Omron CX-Programmer project NewProject (CX-Programmer 9.75)

# PLC NewPLC1: CS1H-H CPU66
I/O table (CPU CS1W-SCB41-V1, CS1H-CPU66H): rack 0 slot 9 CS1W-CLK23; rack 2 slot 6 CS1W-SCU31-V1

## Program 新規ﾌﾟﾛｸﾞﾗﾑ1 (cyclic task 0)

### Section INITIAL

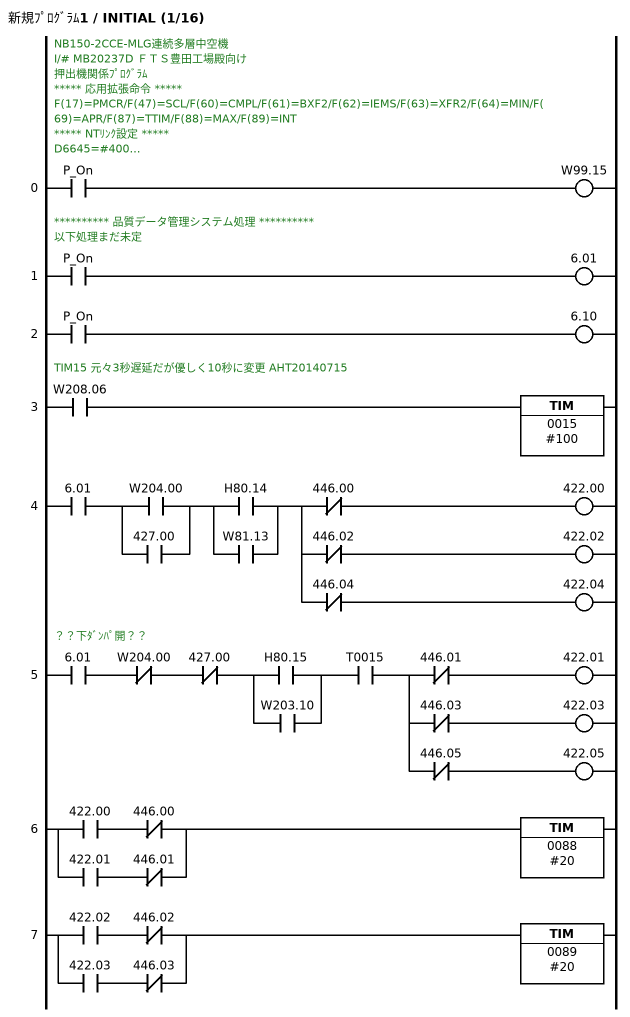
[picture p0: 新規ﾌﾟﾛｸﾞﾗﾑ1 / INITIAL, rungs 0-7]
; rung 0: NB150-2CCE-MLG連続多層中空機 / I/# MB20237D ＦＴＳ豊田工場殿向け / 押出機関係ﾌﾟﾛｸﾞﾗﾑ / ***** 応用拡張命令 ***** / F(17)=PMCR/F(47)=SCL/F(60)=CMPL/F(61)=BXF2/F(62)=IEMS/F(63)=XFR2/F(64)=MIN/F(69)=APR/F(87)=TTIM/F(88)=MAX/F(89)=INT / ***** NTﾘﾝｸ設定 ***** / D6645=#4000 / ***** 電源断検知後運転継続時間 ***** / D6605=#0010 / ***** ｺﾐｭﾆｹｰｼｮﾝﾎﾞｰﾄﾞ設定 ***** / D6555=#6001 D6556=#0304 / ***** ｺﾝﾄﾛｰﾗﾘｸ初期設定 ***** / D6420=#0010 D6421=#0400 D6422=#8000 D6423=#0014 D6424=#0000 D6425=#8200 D6426=#0020 D6427=#0000 D6428=#003F D6429=#0000 / 使用領域　400～483ch/D0000～D0119 / ***** ﾊｰﾄﾞ構成 ***** / ｼｰｹﾝｻ→C200HX-CPU65-Z / ﾃﾞｨｽﾌﾟﾚｲ→NT631C-ST141B-V2
LD P_On
OUT W99.15
; rung 1: ********** 品質データ管理システム処理 ********** / 以下処理まだ未定
LD P_On
OUT 6.01
; rung 2
LD P_On
OUT 6.10
; rung 3: TIM15 元々3秒遅延だが優しく10秒に変更 AHT20140715
LD W208.06
TIM 0015 #100
; rung 4
LD 6.01
LD W204.00
OR 427.00
ANDLD
LD H80.14
OR W81.13
ANDLD
OUT TR0
ANDNOT 446.00
OUT 422.00
LD TR0
ANDNOT 446.02
OUT 422.02
LD TR0
ANDNOT 446.04
OUT 422.04
; rung 5: ？？下ﾀﾞﾝﾊﾟ開？？
LD 6.01
ANDNOT W204.00
ANDNOT 427.00
LD H80.15
OR W203.10
ANDLD
AND T0015
OUT TR0
ANDNOT 446.01
OUT 422.01
LD TR0
ANDNOT 446.03
OUT 422.03
LD TR0
ANDNOT 446.05
OUT 422.05
; rung 6
LD 422.00
ANDNOT 446.00
LD 422.01
ANDNOT 446.01
ORLD
TIM 0088 #20
; rung 7
LD 422.02
ANDNOT 446.02
LD 422.03
ANDNOT 446.03
ORLD
TIM 0089 #20

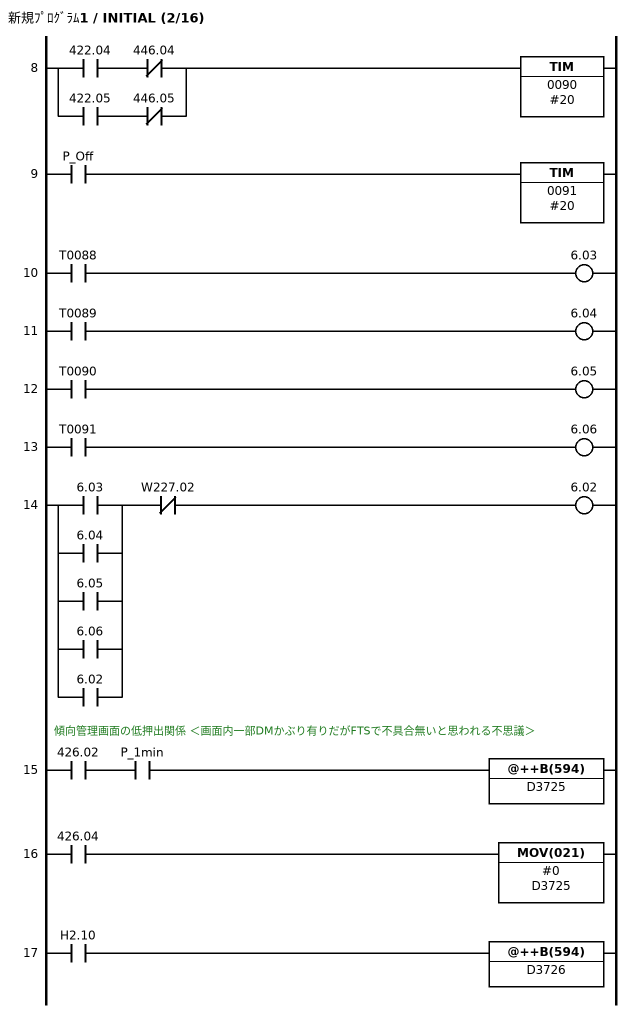
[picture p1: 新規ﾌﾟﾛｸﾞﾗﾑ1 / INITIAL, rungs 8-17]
; rung 8
LD 422.04
ANDNOT 446.04
LD 422.05
ANDNOT 446.05
ORLD
TIM 0090 #20
; rung 9
LD P_Off
TIM 0091 #20
; rung 10
LD T0088
OUT 6.03
; rung 11
LD T0089
OUT 6.04
; rung 12
LD T0090
OUT 6.05
; rung 13
LD T0091
OUT 6.06
; rung 14
LD 6.03
OR 6.04
OR 6.05
OR 6.06
OR 6.02
ANDNOT W227.02
OUT 6.02
; rung 15: 傾向管理画面の低押出関係 ＜画面内一部DMかぶり有りだがFTSで不具合無いと思われる不思議＞
LD 426.02
AND P_1min
@++B(594) D3725
; rung 16
LD 426.04
MOV(021) #0 D3725
; rung 17
LD H2.10
@++B(594) D3726

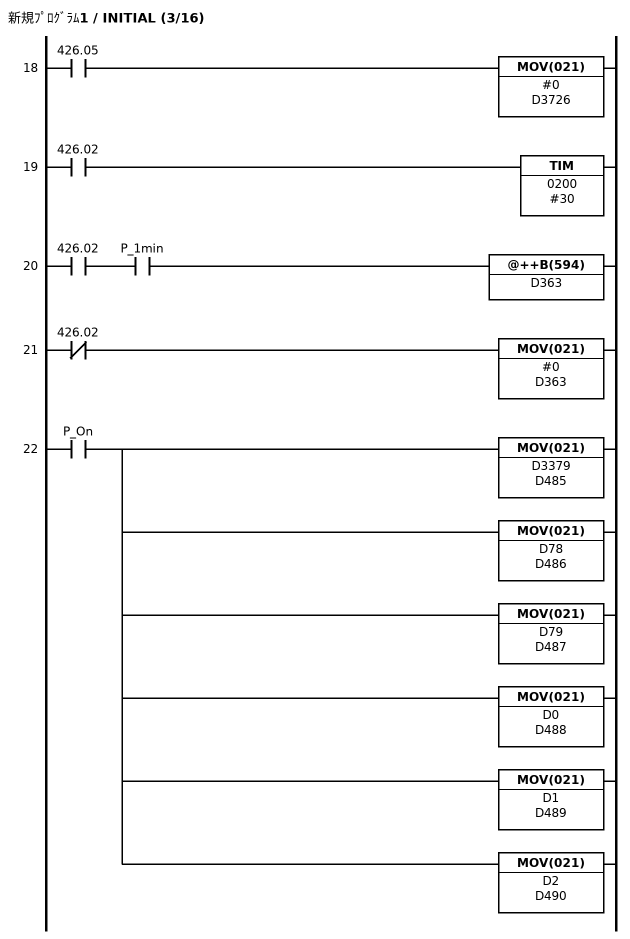
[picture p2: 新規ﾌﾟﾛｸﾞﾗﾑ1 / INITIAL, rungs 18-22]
; rung 18
LD 426.05
MOV(021) #0 D3726
; rung 19
LD 426.02
TIM 0200 #30
; rung 20
LD 426.02
AND P_1min
@++B(594) D363
; rung 21
LDNOT 426.02
MOV(021) #0 D363
; rung 22
LD P_On
MOV(021) D3379 D485
MOV(021) D78 D486
MOV(021) D79 D487
MOV(021) D0 D488
MOV(021) D1 D489
MOV(021) D2 D490

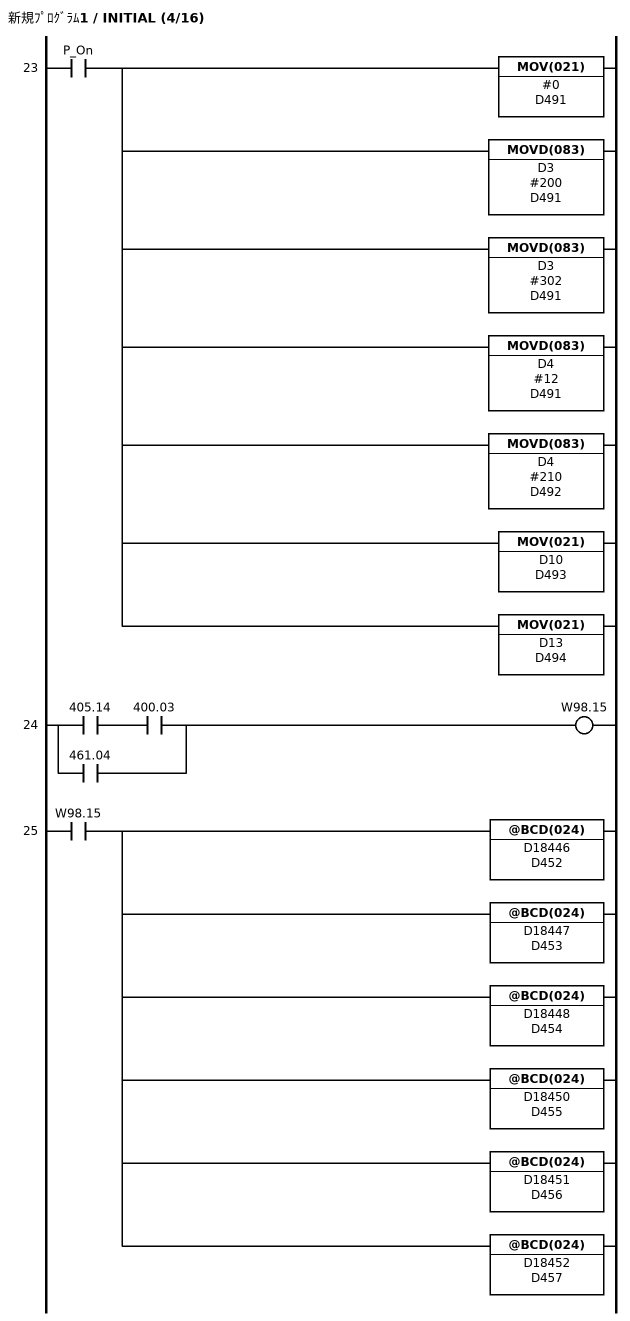
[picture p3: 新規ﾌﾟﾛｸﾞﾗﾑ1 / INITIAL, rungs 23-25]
; rung 23
LD P_On
MOV(021) #0 D491
MOVD(083) D3 #200 D491
MOVD(083) D3 #302 D491
MOVD(083) D4 #12 D491
MOVD(083) D4 #210 D492
MOV(021) D10 D493
MOV(021) D13 D494
; rung 24
LD 405.14
AND 400.03
OR 461.04
OUT W98.15
; rung 25
LD W98.15
@BCD(024) D18446 D452
@BCD(024) D18447 D453
@BCD(024) D18448 D454
@BCD(024) D18450 D455
@BCD(024) D18451 D456
@BCD(024) D18452 D457

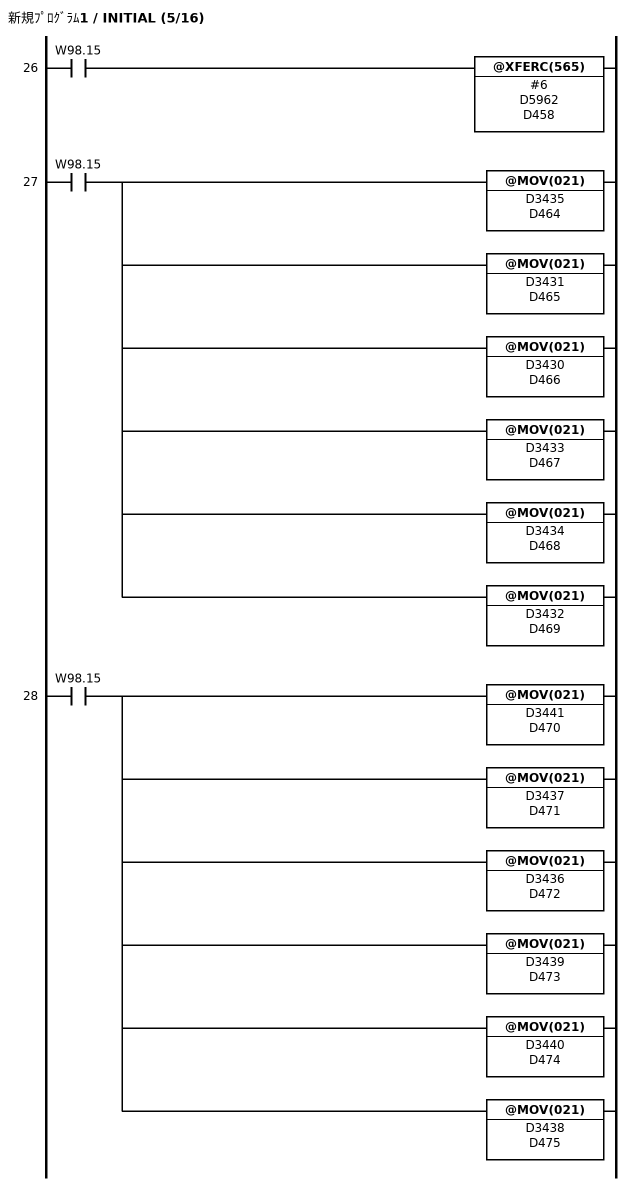
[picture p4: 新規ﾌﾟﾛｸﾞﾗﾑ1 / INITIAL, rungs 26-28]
; rung 26
LD W98.15
@XFERC(565) #6 D5962 D458
; rung 27
LD W98.15
@MOV(021) D3435 D464
@MOV(021) D3431 D465
@MOV(021) D3430 D466
@MOV(021) D3433 D467
@MOV(021) D3434 D468
@MOV(021) D3432 D469
; rung 28
LD W98.15
@MOV(021) D3441 D470
@MOV(021) D3437 D471
@MOV(021) D3436 D472
@MOV(021) D3439 D473
@MOV(021) D3440 D474
@MOV(021) D3438 D475

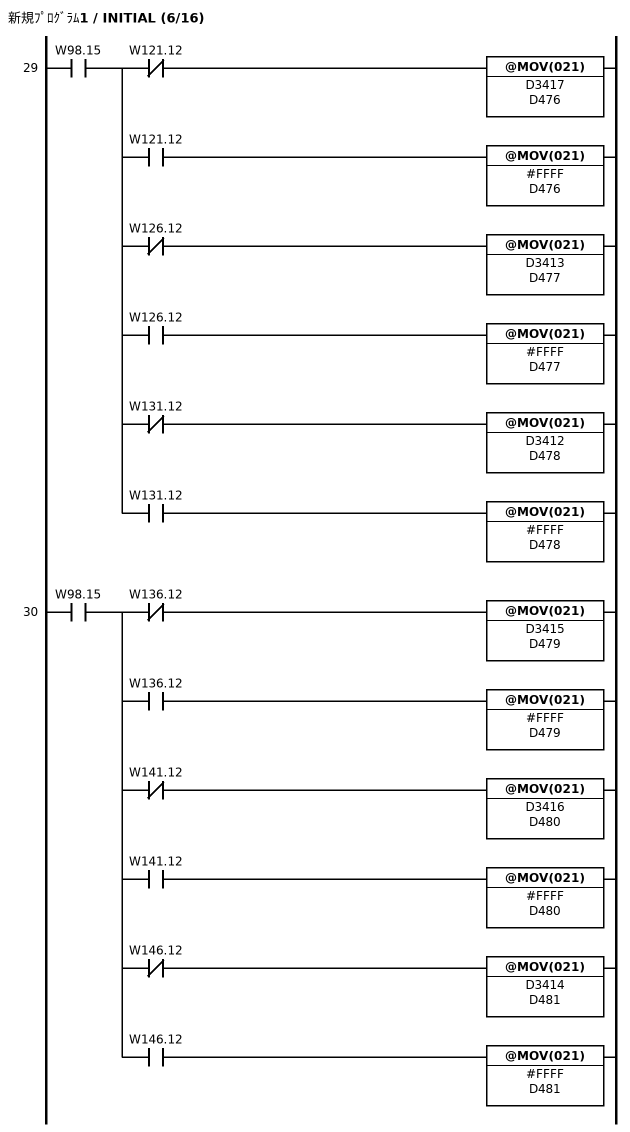
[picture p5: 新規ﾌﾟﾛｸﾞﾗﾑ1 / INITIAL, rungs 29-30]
; rung 29
LD W98.15
OUT TR0
ANDNOT W121.12
@MOV(021) D3417 D476
LD TR0
AND W121.12
@MOV(021) #FFFF D476
LD TR0
ANDNOT W126.12
@MOV(021) D3413 D477
LD TR0
AND W126.12
@MOV(021) #FFFF D477
LD TR0
ANDNOT W131.12
@MOV(021) D3412 D478
LD TR0
AND W131.12
@MOV(021) #FFFF D478
; rung 30
LD W98.15
OUT TR0
ANDNOT W136.12
@MOV(021) D3415 D479
LD TR0
AND W136.12
@MOV(021) #FFFF D479
LD TR0
ANDNOT W141.12
@MOV(021) D3416 D480
LD TR0
AND W141.12
@MOV(021) #FFFF D480
LD TR0
ANDNOT W146.12
@MOV(021) D3414 D481
LD TR0
AND W146.12
@MOV(021) #FFFF D481

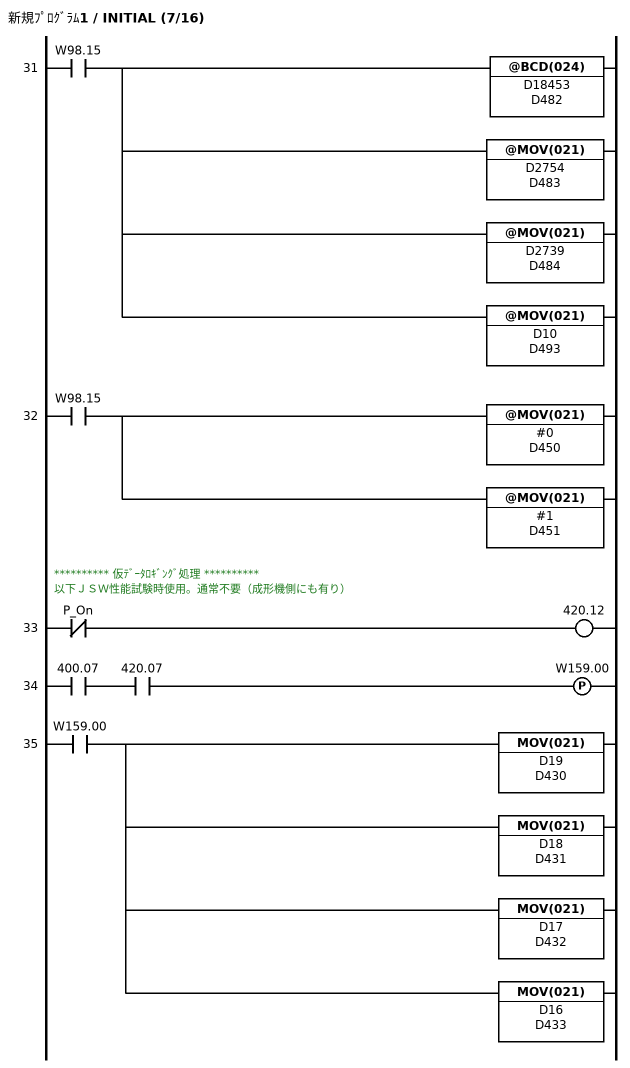
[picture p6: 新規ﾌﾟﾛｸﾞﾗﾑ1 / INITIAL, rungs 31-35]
; rung 31
LD W98.15
@BCD(024) D18453 D482
@MOV(021) D2754 D483
@MOV(021) D2739 D484
@MOV(021) D10 D493
; rung 32
LD W98.15
@MOV(021) #0 D450
@MOV(021) #1 D451
; rung 33: ********** 仮ﾃﾞｰﾀﾛｷﾞﾝｸﾞ処理 ********** / 以下ＪＳＷ性能試験時使用。通常不要（成形機側にも有り）
LDNOT P_On
OUT 420.12
; rung 34
LD 400.07
AND 420.07
DIFU(013) W159.00
; rung 35
LD W159.00
MOV(021) D19 D430
MOV(021) D18 D431
MOV(021) D17 D432
MOV(021) D16 D433

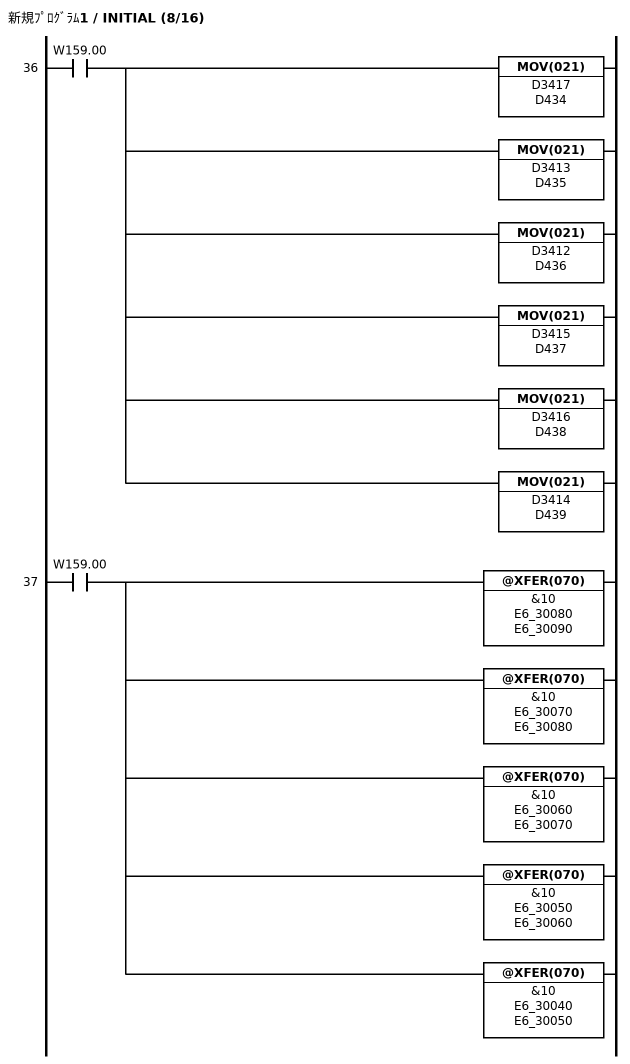
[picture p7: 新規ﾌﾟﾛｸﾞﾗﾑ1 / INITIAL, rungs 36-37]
; rung 36
LD W159.00
MOV(021) D3417 D434
MOV(021) D3413 D435
MOV(021) D3412 D436
MOV(021) D3415 D437
MOV(021) D3416 D438
MOV(021) D3414 D439
; rung 37
LD W159.00
@XFER(070) &10 E6_30080 E6_30090
@XFER(070) &10 E6_30070 E6_30080
@XFER(070) &10 E6_30060 E6_30070
@XFER(070) &10 E6_30050 E6_30060
@XFER(070) &10 E6_30040 E6_30050

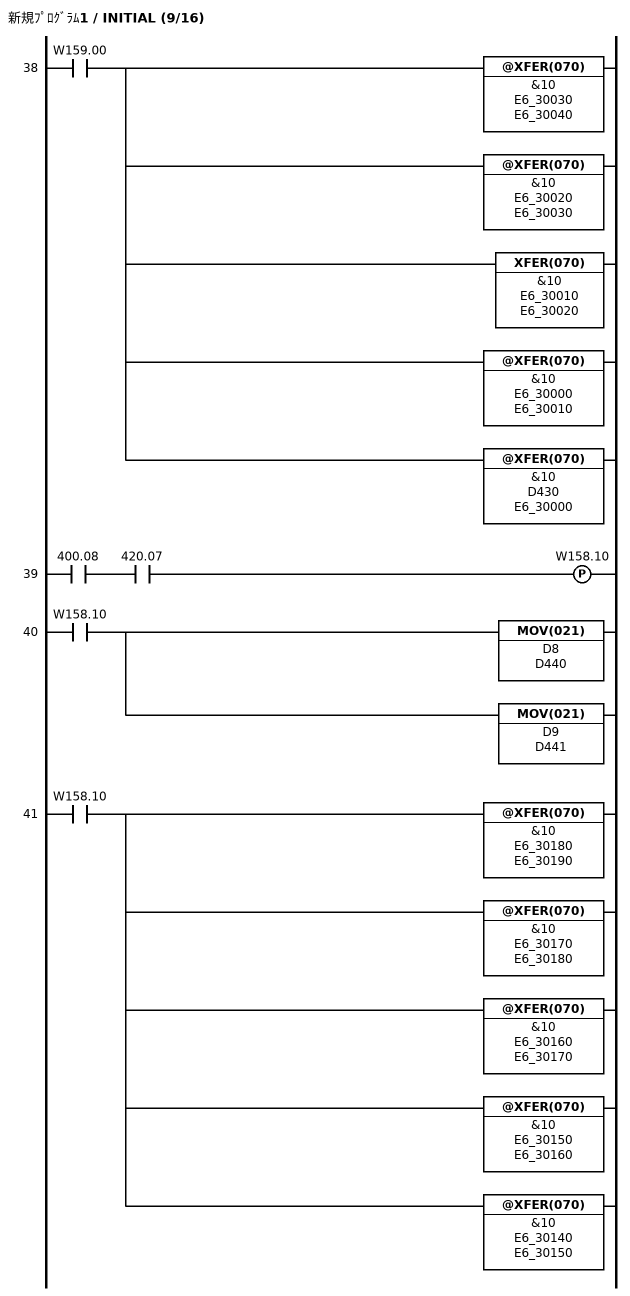
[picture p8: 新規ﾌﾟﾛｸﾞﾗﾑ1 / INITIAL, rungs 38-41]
; rung 38
LD W159.00
@XFER(070) &10 E6_30030 E6_30040
@XFER(070) &10 E6_30020 E6_30030
XFER(070) &10 E6_30010 E6_30020
@XFER(070) &10 E6_30000 E6_30010
@XFER(070) &10 D430 E6_30000
; rung 39
LD 400.08
AND 420.07
DIFU(013) W158.10
; rung 40
LD W158.10
MOV(021) D8 D440
MOV(021) D9 D441
; rung 41
LD W158.10
@XFER(070) &10 E6_30180 E6_30190
@XFER(070) &10 E6_30170 E6_30180
@XFER(070) &10 E6_30160 E6_30170
@XFER(070) &10 E6_30150 E6_30160
@XFER(070) &10 E6_30140 E6_30150

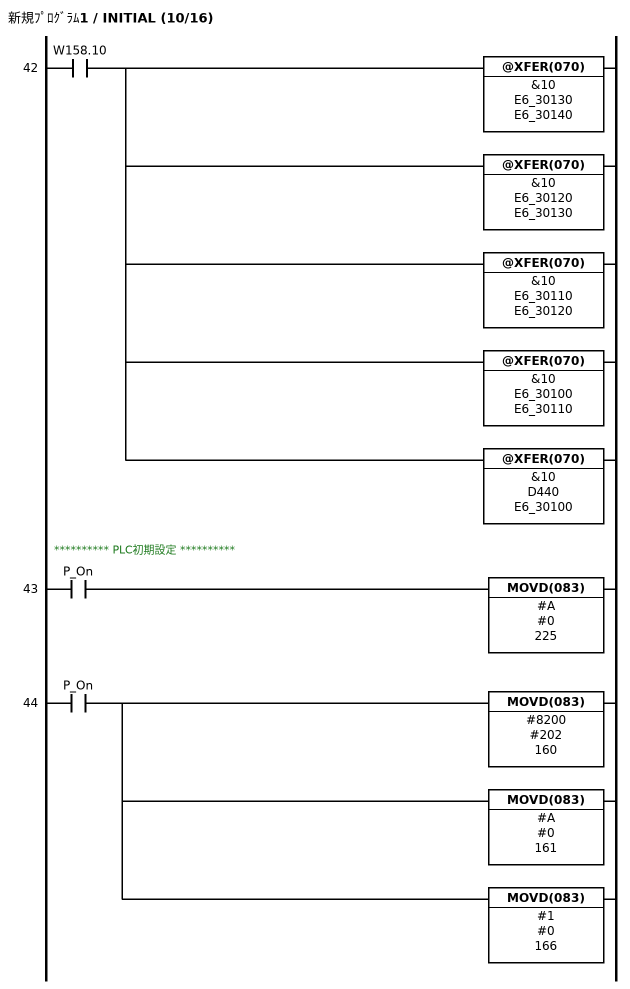
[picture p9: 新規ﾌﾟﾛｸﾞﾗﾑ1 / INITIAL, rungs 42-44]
; rung 42
LD W158.10
@XFER(070) &10 E6_30130 E6_30140
@XFER(070) &10 E6_30120 E6_30130
@XFER(070) &10 E6_30110 E6_30120
@XFER(070) &10 E6_30100 E6_30110
@XFER(070) &10 D440 E6_30100
; rung 43: ********** PLC初期設定 **********
LD P_On
MOVD(083) #A #0 225  // 瞬停検出 10ms
; rung 44
LD P_On
MOVD(083) #8200 #202 160  // NTﾘﾝｸﾓｰﾄﾞ
MOVD(083) #A #0 161  // 高速NTﾘﾝｸ
MOVD(083) #1 #0 166  // 号機数

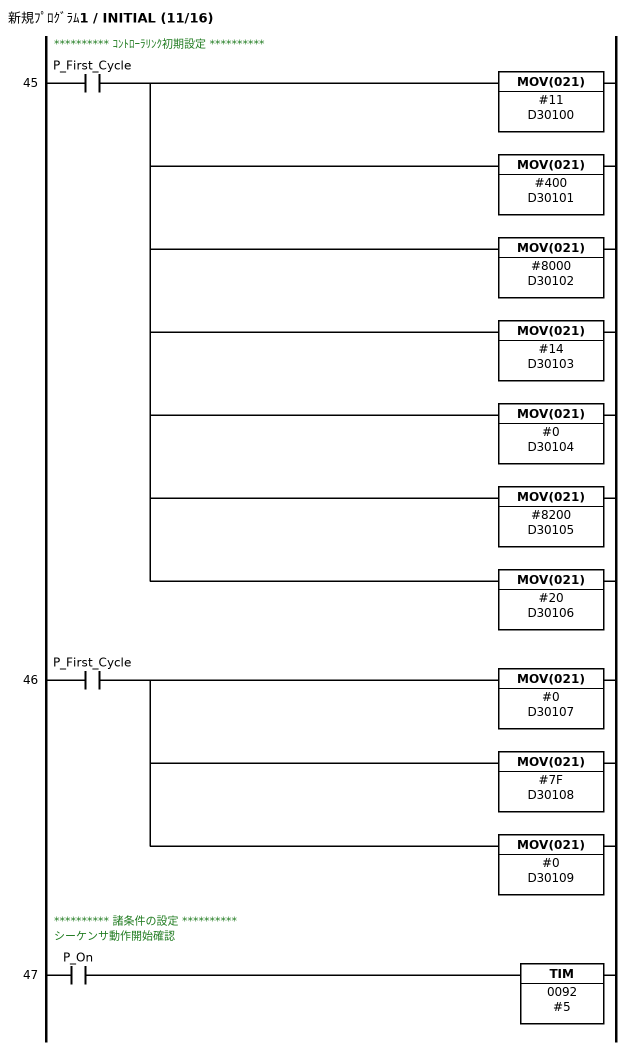
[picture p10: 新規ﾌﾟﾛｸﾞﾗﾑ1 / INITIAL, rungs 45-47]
; rung 45: ********** ｺﾝﾄﾛｰﾗﾘﾝｸ初期設定 **********
LD P_First_Cycle
MOV(021) #11 D30100
MOV(021) #400 D30101
MOV(021) #8000 D30102
MOV(021) #14 D30103
MOV(021) #0 D30104
MOV(021) #8200 D30105
MOV(021) #20 D30106
; rung 46
LD P_First_Cycle
MOV(021) #0 D30107
MOV(021) #7F D30108
MOV(021) #0 D30109
; rung 47: ********** 諸条件の設定 ********** / シーケンサ動作開始確認
LD P_On
TIM 0092 #5

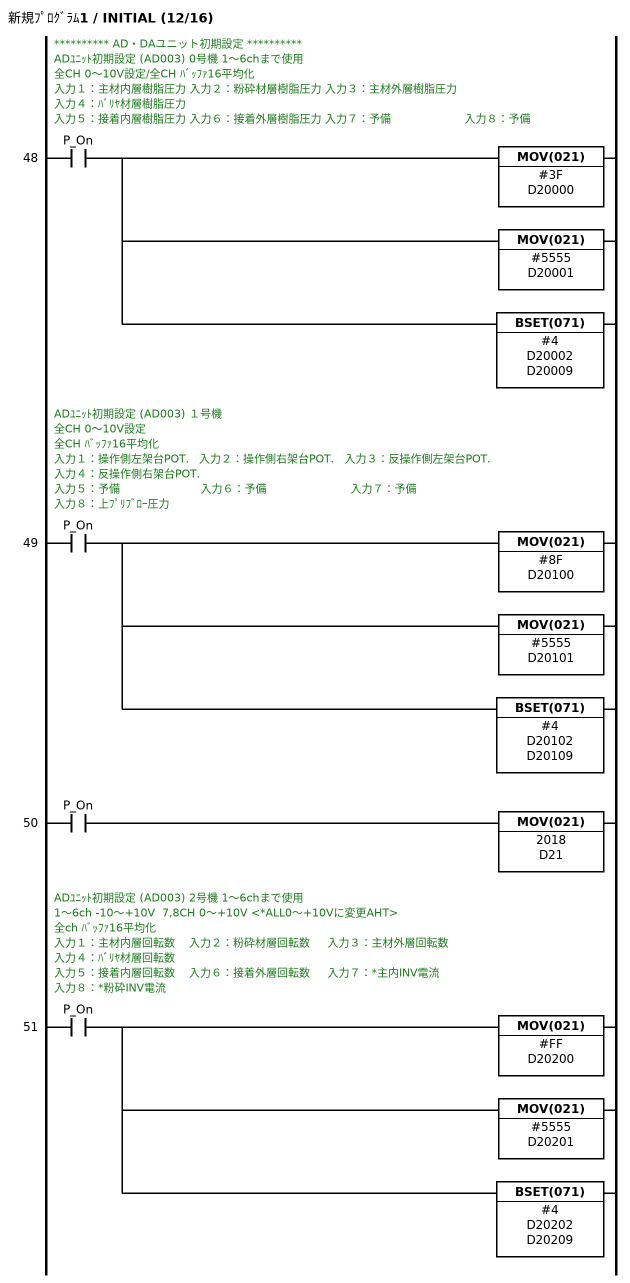
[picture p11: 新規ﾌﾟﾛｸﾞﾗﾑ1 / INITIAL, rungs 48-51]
; rung 48: ********** AD・DAユニット初期設定 ********** / ADﾕﾆｯﾄ初期設定 (AD003) 0号機 1～6chまで使用 / 全CH 0～10V設定/全CH ﾊﾞｯﾌｧ16平均化 / 入力１：主材内層樹脂圧力 入力２：粉砕材層樹脂圧力 入力３：主材外層樹脂圧力 入力４：ﾊﾞﾘﾔ材層樹脂圧力 / 入力５：接着内層樹脂圧力 入力６：接着外層樹脂圧力 入力７：予備                     入力８：予備
LD P_On
MOV(021) #3F D20000
MOV(021) #5555 D20001
BSET(071) #4 D20002 D20009
; rung 49: ADﾕﾆｯﾄ初期設定 (AD003) １号機 / 全CH 0～10V設定 / 全CH ﾊﾞｯﾌｧ16平均化 / 入力１：操作側左架台POT.   入力２：操作側右架台POT.   入力３：反操作側左架台POT.  入力４：反操作側右架台POT. / 入力５：予備                       入力６：予備                        入力７：予備                         入力８：上ﾌﾟﾘﾌﾞﾛｰ圧力
LD P_On
MOV(021) #8F D20100
MOV(021) #5555 D20101
BSET(071) #4 D20102 D20109
; rung 50
LD P_On
MOV(021) 2018 D21
; rung 51: ADﾕﾆｯﾄ初期設定 (AD003) 2号機 1～6chまで使用 / 1～6ch -10～+10V  7,8CH 0～+10V <*ALL0～+10Vに変更AHT> / 全ch ﾊﾞｯﾌｧ16平均化 / 入力１：主材内層回転数    入力２：粉砕材層回転数     入力３：主材外層回転数     入力４：ﾊﾞﾘﾔ材層回転数 / 入力５：接着内層回転数    入力６：接着外層回転数     入力７：*主内INV電流        入力８：*粉砕INV電流
LD P_On
MOV(021) #FF D20200
MOV(021) #5555 D20201
BSET(071) #4 D20202 D20209

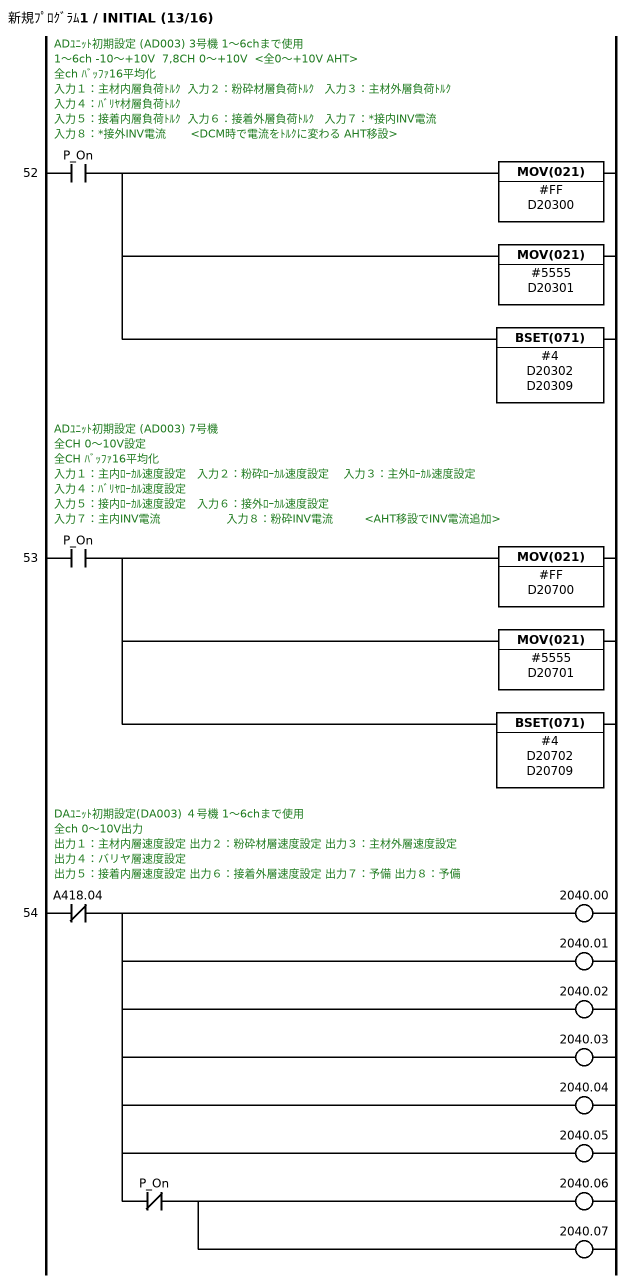
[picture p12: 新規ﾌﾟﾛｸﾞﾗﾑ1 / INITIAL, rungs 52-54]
; rung 52: ADﾕﾆｯﾄ初期設定 (AD003) 3号機 1～6chまで使用 / 1～6ch -10～+10V  7,8CH 0～+10V  <全0～+10V AHT> / 全ch ﾊﾞｯﾌｧ16平均化 / 入力１：主材内層負荷ﾄﾙｸ  入力２：粉砕材層負荷ﾄﾙｸ   入力３：主材外層負荷ﾄﾙｸ    入力４：ﾊﾞﾘﾔ材層負荷ﾄﾙｸ / 入力５：接着内層負荷ﾄﾙｸ  入力６：接着外層負荷ﾄﾙｸ   入力７：*接内INV電流         入力８：*接外INV電流       <DCM時で電流をﾄﾙｸに変わる AHT移設>
LD P_On
MOV(021) #FF D20300
MOV(021) #5555 D20301
BSET(071) #4 D20302 D20309
; rung 53: ADﾕﾆｯﾄ初期設定 (AD003) 7号機 / 全CH 0～10V設定 / 全CH ﾊﾞｯﾌｧ16平均化 / 入力１：主内ﾛｰｶﾙ速度設定　入力２：粉砕ﾛｰｶﾙ速度設定　 入力３：主外ﾛｰｶﾙ速度設定　 入力４：ﾊﾞﾘﾔﾛｰｶﾙ速度設定 / 入力５：接内ﾛｰｶﾙ速度設定　入力６：接外ﾛｰｶﾙ速度設定　 入力７：主内INV電流　　　　　　入力８：粉砕INV電流         <AHT移設でINV電流追加>
LD P_On
MOV(021) #FF D20700
MOV(021) #5555 D20701
BSET(071) #4 D20702 D20709
; rung 54: DAﾕﾆｯﾄ初期設定(DA003) ４号機 1～6chまで使用 / 全ch 0～10V出力 / 出力１：主材内層速度設定 出力２：粉砕材層速度設定 出力３：主材外層速度設定 出力４：バリヤ層速度設定 / 出力５：接着内層速度設定 出力６：接着外層速度設定 出力７：予備 出力８：予備
LDNOT A418.04
OUT 2040.00
OUT 2040.01
OUT 2040.02
OUT 2040.03
OUT 2040.04
OUT 2040.05
ANDNOT P_On
OUT 2040.06
OUT 2040.07

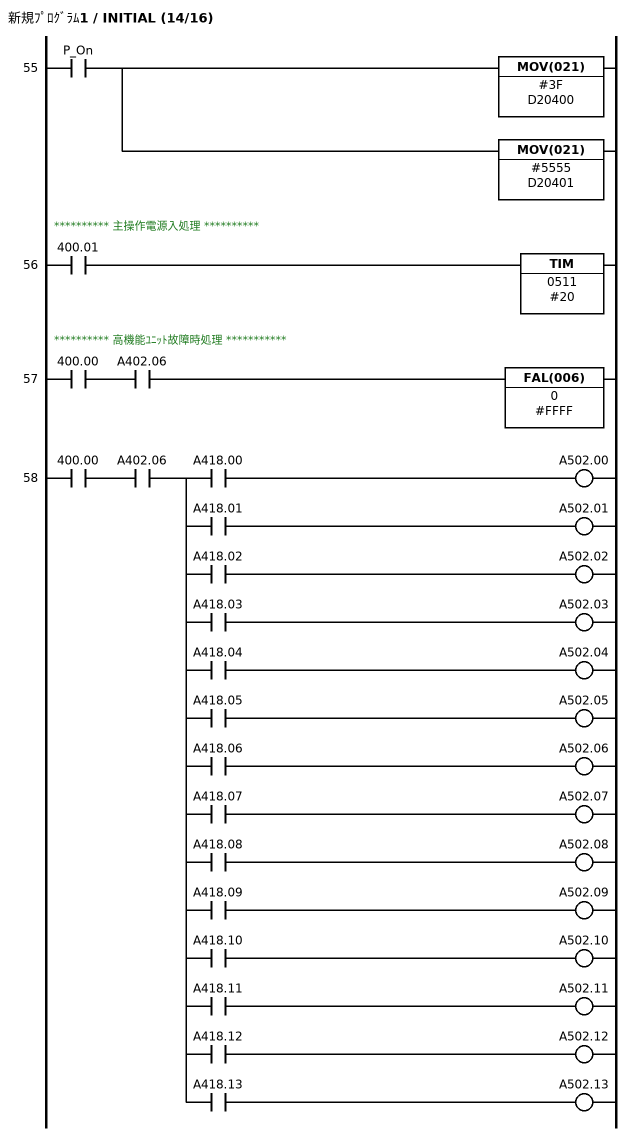
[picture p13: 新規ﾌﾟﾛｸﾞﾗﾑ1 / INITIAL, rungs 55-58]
; rung 55
LD P_On
MOV(021) #3F D20400
MOV(021) #5555 D20401
; rung 56: ********** 主操作電源入処理 **********
LD 400.01
TIM 0511 #20
; rung 57: ********** 高機能ﾕﾆｯﾄ故障時処理 ***********
LD 400.00
AND A402.06
FAL(006) 0 #FFFF
; rung 58
LD 400.00
AND A402.06
OUT TR0
AND A418.00
OUT A502.00
LD TR0
AND A418.01
OUT A502.01
LD TR0
AND A418.02
OUT A502.02
LD TR0
AND A418.03
OUT A502.03
LD TR0
AND A418.04
OUT A502.04
LD TR0
AND A418.05
OUT A502.05
LD TR0
AND A418.06
OUT A502.06
LD TR0
AND A418.07
OUT A502.07
LD TR0
AND A418.08
OUT A502.08
LD TR0
AND A418.09
OUT A502.09
LD TR0
AND A418.10
OUT A502.10
LD TR0
AND A418.11
OUT A502.11
LD TR0
AND A418.12
OUT A502.12
LD TR0
AND A418.13
OUT A502.13

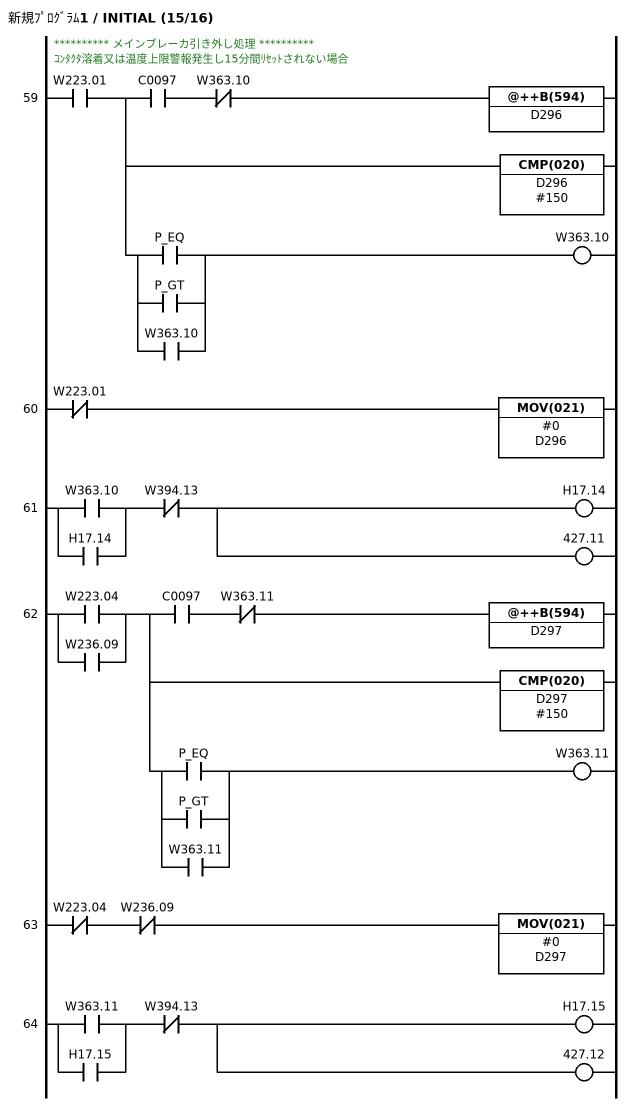
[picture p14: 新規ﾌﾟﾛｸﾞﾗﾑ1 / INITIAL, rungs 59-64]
; rung 59: ********** メインブレーカ引き外し処理 ********** / ｺﾝﾀｸﾀ溶着又は温度上限警報発生し15分間ﾘｾｯﾄされない場合
LD W223.01
OUT TR0
AND C0097
ANDNOT W363.10
@++B(594) D296
LD TR0
CMP(020) D296 #150
LD P_EQ
OR P_GT
OR W363.10
ANDLD
OUT W363.10
; rung 60
LDNOT W223.01
MOV(021) #0 D296
; rung 61
LD W363.10
OR H17.14
ANDNOT W394.13
OUT H17.14
OUT 427.11
; rung 62
LD W223.04
OR W236.09
OUT TR0
AND C0097
ANDNOT W363.11
@++B(594) D297
LD TR0
CMP(020) D297 #150
LD P_EQ
OR P_GT
OR W363.11
ANDLD
OUT W363.11
; rung 63
LDNOT W223.04
ANDNOT W236.09
MOV(021) #0 D297
; rung 64
LD W363.11
OR H17.15
ANDNOT W394.13
OUT H17.15
OUT 427.12

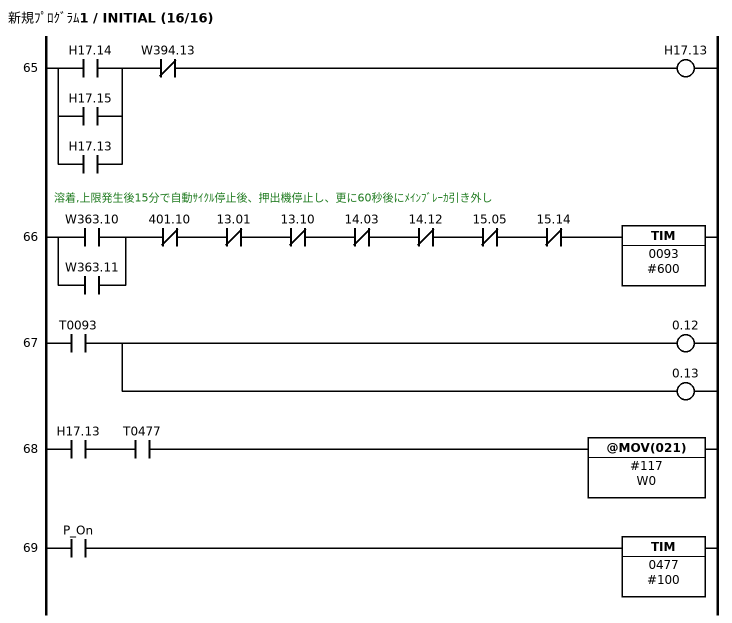
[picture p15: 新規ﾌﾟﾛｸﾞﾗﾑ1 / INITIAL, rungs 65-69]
; rung 65
LD H17.14
OR H17.15
OR H17.13
ANDNOT W394.13
OUT H17.13
; rung 66: 溶着,上限発生後15分で自動ｻｲｸﾙ停止後、押出機停止し、更に60秒後にﾒｲﾝﾌﾞﾚｰｶ引き外し
LD W363.10
OR W363.11
ANDNOT 401.10
ANDNOT 13.01
ANDNOT 13.10
ANDNOT 14.03
ANDNOT 14.12
ANDNOT 15.05
ANDNOT 15.14
TIM 0093 #600
; rung 67
LD T0093
OUT 0.12
OUT 0.13
; rung 68
LD H17.13
AND T0477
@MOV(021) #117 W0
; rung 69
LD P_On
TIM 0477 #100

### Section BASE_LIFT

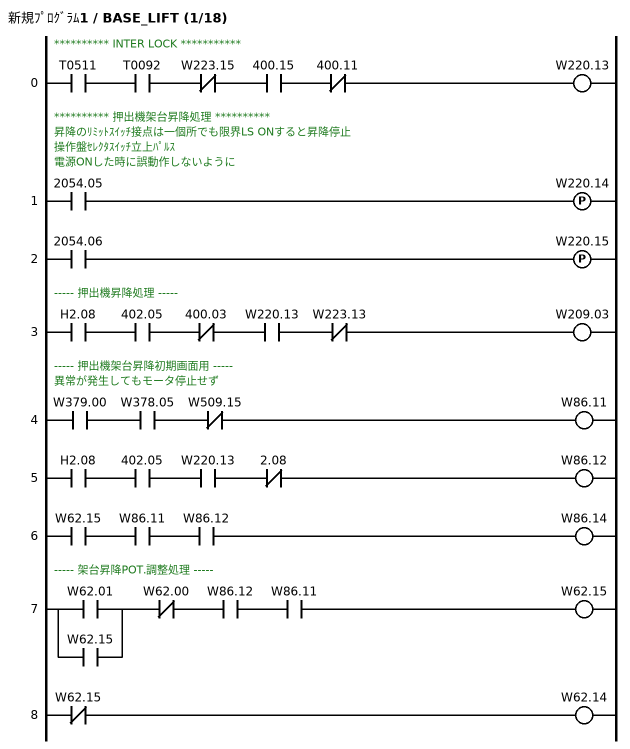
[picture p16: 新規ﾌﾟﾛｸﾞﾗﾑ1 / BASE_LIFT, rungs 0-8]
; rung 0: ********** INTER LOCK ***********
LD T0511
AND T0092
ANDNOT W223.15
AND 400.15
ANDNOT 400.11
OUT W220.13
; rung 1: ********** 押出機架台昇降処理 ********** / 昇降のﾘﾐｯﾄｽｲｯﾁ接点は一個所でも限界LS ONすると昇降停止 / 操作盤ｾﾚｸﾀｽｲｯﾁ立上ﾊﾟﾙｽ / 電源ONした時に誤動作しないように
LD 2054.05
DIFU(013) W220.14
; rung 2
LD 2054.06
DIFU(013) W220.15
; rung 3: ----- 押出機昇降処理 -----
LD H2.08
AND 402.05
ANDNOT 400.03
AND W220.13
ANDNOT W223.13
OUT W209.03
; rung 4: ----- 押出機架台昇降初期画面用 ----- / 異常が発生してもモータ停止せず
LD W379.00
AND W378.05
ANDNOT W509.15
OUT W86.11
; rung 5
LD H2.08
AND 402.05
AND W220.13
ANDNOT 2.08
OUT W86.12
; rung 6
LD W62.15
AND W86.11
AND W86.12
OUT W86.14
; rung 7: ----- 架台昇降POT.調整処理 -----
LD W62.01
OR W62.15
ANDNOT W62.00
AND W86.12
AND W86.11
OUT W62.15
; rung 8
LDNOT W62.15
OUT W62.14

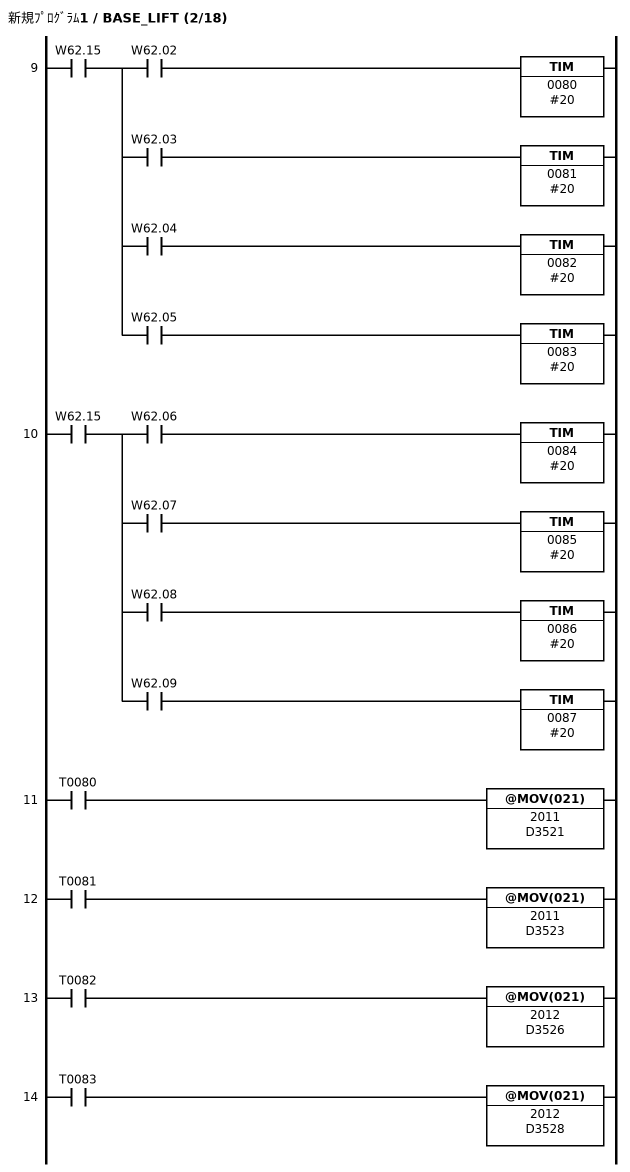
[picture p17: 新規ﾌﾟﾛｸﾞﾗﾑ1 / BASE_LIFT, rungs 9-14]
; rung 9
LD W62.15
OUT TR0
AND W62.02
TIM 0080 #20
LD TR0
AND W62.03
TIM 0081 #20
LD TR0
AND W62.04
TIM 0082 #20
LD TR0
AND W62.05
TIM 0083 #20
; rung 10
LD W62.15
OUT TR0
AND W62.06
TIM 0084 #20
LD TR0
AND W62.07
TIM 0085 #20
LD TR0
AND W62.08
TIM 0086 #20
LD TR0
AND W62.09
TIM 0087 #20
; rung 11
LD T0080
@MOV(021) 2011 D3521
; rung 12
LD T0081
@MOV(021) 2011 D3523
; rung 13
LD T0082
@MOV(021) 2012 D3526
; rung 14
LD T0083
@MOV(021) 2012 D3528

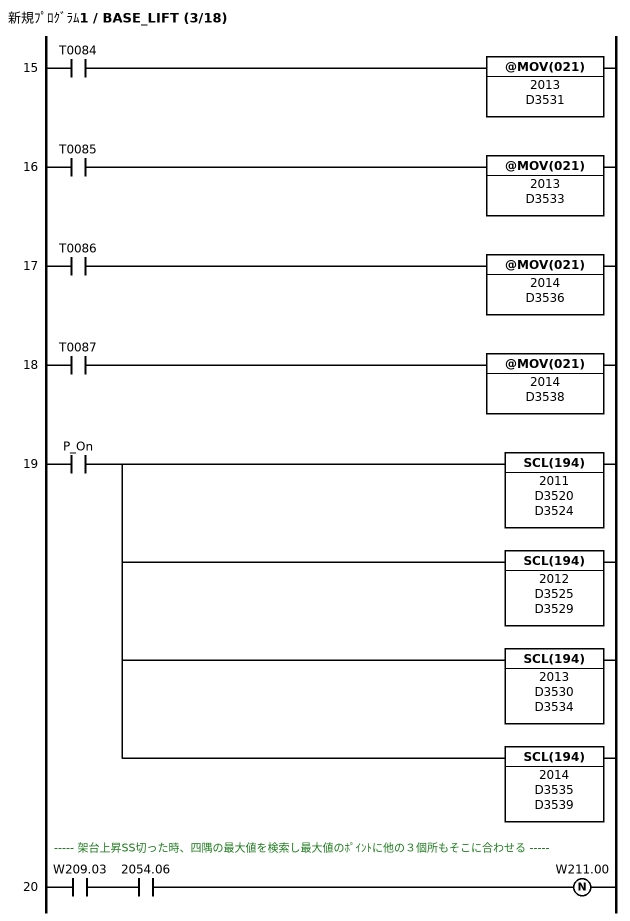
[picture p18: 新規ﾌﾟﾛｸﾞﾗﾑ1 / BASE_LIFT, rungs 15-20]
; rung 15
LD T0084
@MOV(021) 2013 D3531
; rung 16
LD T0085
@MOV(021) 2013 D3533
; rung 17
LD T0086
@MOV(021) 2014 D3536
; rung 18
LD T0087
@MOV(021) 2014 D3538
; rung 19
LD P_On
SCL(194) 2011 D3520 D3524
SCL(194) 2012 D3525 D3529
SCL(194) 2013 D3530 D3534
SCL(194) 2014 D3535 D3539
; rung 20: ----- 架台上昇SS切った時、四隅の最大値を検索し最大値のﾎﾟｲﾝﾄに他の３個所もそこに合わせる -----
LD W209.03
AND 2054.06
DIFD(014) W211.00

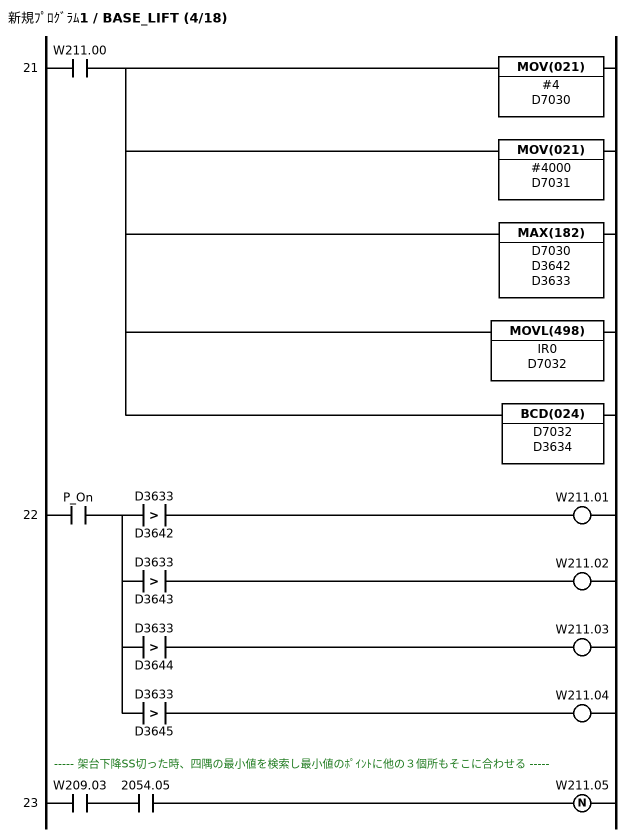
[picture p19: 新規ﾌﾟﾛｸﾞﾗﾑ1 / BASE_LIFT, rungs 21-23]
; rung 21
LD W211.00
MOV(021) #4 D7030
MOV(021) #4000 D7031
MAX(182) D7030 D3642 D3633
MOVL(498) IR0 D7032
BCD(024) D7032 D3634
; rung 22
LD P_On
OUT TR0
AND>(320) D3633 D3642
OUT W211.01
LD TR0
AND>(320) D3633 D3643
OUT W211.02
LD TR0
AND>(320) D3633 D3644
OUT W211.03
LD TR0
AND>(320) D3633 D3645
OUT W211.04
; rung 23: ----- 架台下降SS切った時、四隅の最小値を検索し最小値のﾎﾟｲﾝﾄに他の３個所もそこに合わせる -----
LD W209.03
AND 2054.05
DIFD(014) W211.05

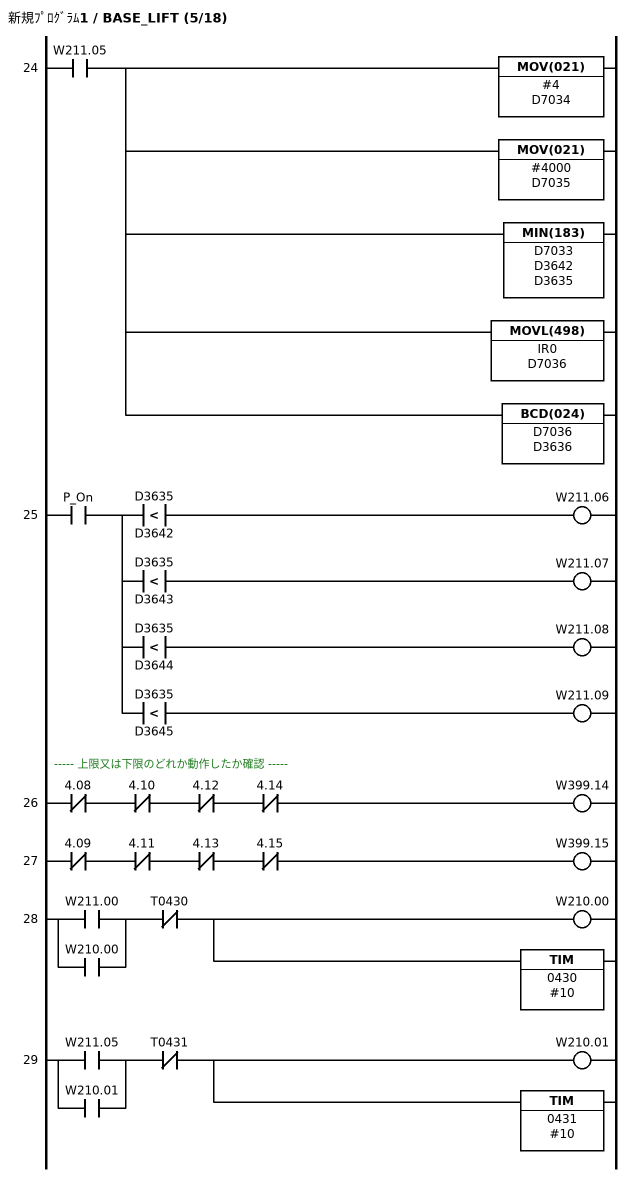
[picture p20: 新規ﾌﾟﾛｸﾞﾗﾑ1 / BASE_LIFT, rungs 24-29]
; rung 24
LD W211.05
MOV(021) #4 D7034
MOV(021) #4000 D7035
MIN(183) D7033 D3642 D3635
MOVL(498) IR0 D7036
BCD(024) D7036 D3636
; rung 25
LD P_On
OUT TR0
AND<(310) D3635 D3642
OUT W211.06
LD TR0
AND<(310) D3635 D3643
OUT W211.07
LD TR0
AND<(310) D3635 D3644
OUT W211.08
LD TR0
AND<(310) D3635 D3645
OUT W211.09
; rung 26: ----- 上限又は下限のどれか動作したか確認 -----
LDNOT 4.08
ANDNOT 4.10
ANDNOT 4.12
ANDNOT 4.14
OUT W399.14
; rung 27
LDNOT 4.09
ANDNOT 4.11
ANDNOT 4.13
ANDNOT 4.15
OUT W399.15
; rung 28
LD W211.00
OR W210.00
ANDNOT T0430
OUT W210.00
TIM 0430 #10
; rung 29
LD W211.05
OR W210.01
ANDNOT T0431
OUT W210.01
TIM 0431 #10

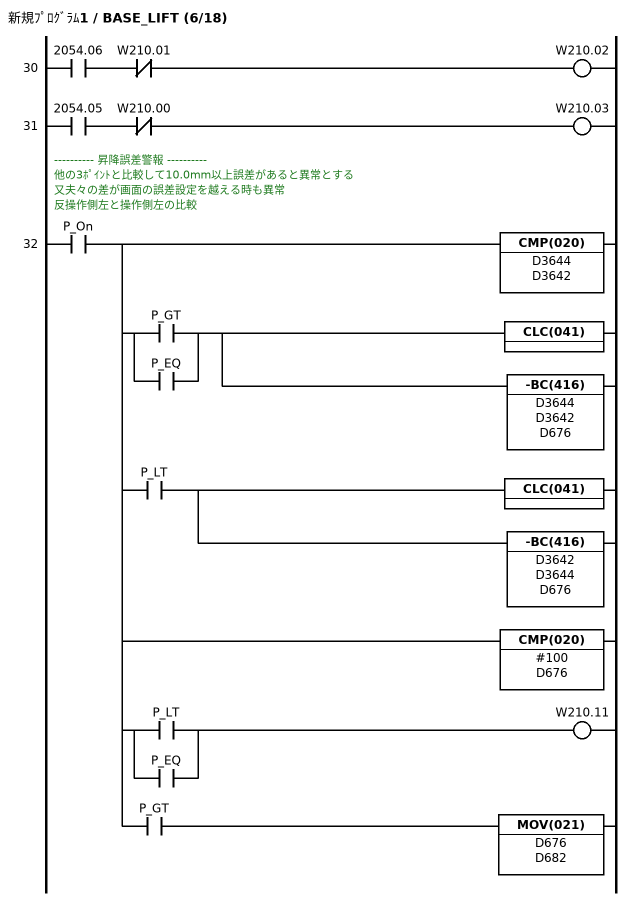
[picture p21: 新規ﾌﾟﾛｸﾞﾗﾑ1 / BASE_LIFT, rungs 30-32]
; rung 30
LD 2054.06
ANDNOT W210.01
OUT W210.02
; rung 31
LD 2054.05
ANDNOT W210.00
OUT W210.03
; rung 32: ---------- 昇降誤差警報 ---------- / 他の3ﾎﾟｲﾝﾄと比較して10.0mm以上誤差があると異常とする / 又夫々の差が画面の誤差設定を越える時も異常 / 反操作側左と操作側左の比較
LD P_On
OUT TR0
CMP(020) D3644 D3642
LD P_GT
OR P_EQ
ANDLD
CLC(041)
-BC(416) D3644 D3642 D676
LD TR0
AND P_LT
CLC(041)
-BC(416) D3642 D3644 D676
LD TR0
CMP(020) #100 D676
LD P_LT
OR P_EQ
ANDLD
OUT W210.11
LD TR0
AND P_GT
MOV(021) D676 D682

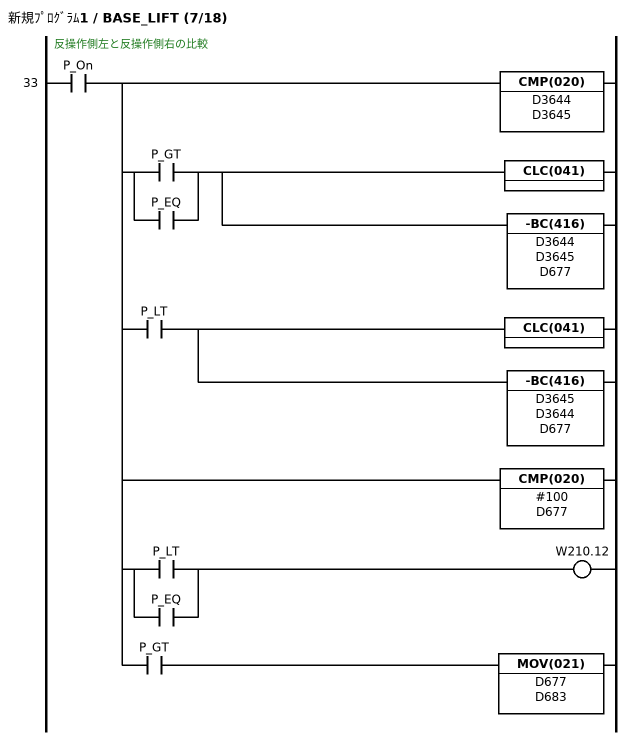
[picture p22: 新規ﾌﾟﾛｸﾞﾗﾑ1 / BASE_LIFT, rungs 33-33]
; rung 33: 反操作側左と反操作側右の比較
LD P_On
OUT TR0
CMP(020) D3644 D3645
LD P_GT
OR P_EQ
ANDLD
CLC(041)
-BC(416) D3644 D3645 D677
LD TR0
AND P_LT
CLC(041)
-BC(416) D3645 D3644 D677
LD TR0
CMP(020) #100 D677
LD P_LT
OR P_EQ
ANDLD
OUT W210.12
LD TR0
AND P_GT
MOV(021) D677 D683

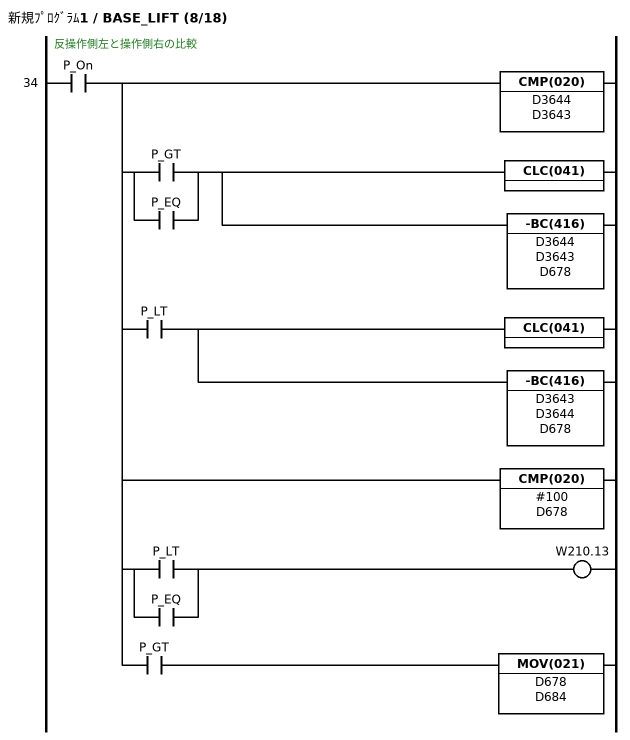
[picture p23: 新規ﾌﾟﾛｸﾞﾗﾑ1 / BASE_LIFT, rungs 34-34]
; rung 34: 反操作側左と操作側右の比較
LD P_On
OUT TR0
CMP(020) D3644 D3643
LD P_GT
OR P_EQ
ANDLD
CLC(041)
-BC(416) D3644 D3643 D678
LD TR0
AND P_LT
CLC(041)
-BC(416) D3643 D3644 D678
LD TR0
CMP(020) #100 D678
LD P_LT
OR P_EQ
ANDLD
OUT W210.13
LD TR0
AND P_GT
MOV(021) D678 D684

; rung 35: 操作側左と反操作側右の比較
LD P_On
OUT TR0
CMP(020) D3642 D3645
LD P_GT
OR P_EQ
ANDLD
CLC(041)
-BC(416) D3642 D3645 D679
LD TR0
AND P_LT
CLC(041)
-BC(416) D3645 D3642 D679
LD TR0
CMP(020) #100 D679
LD P_LT
OR P_EQ
ANDLD
OUT W210.14
LD TR0
AND P_GT
MOV(021) D679 D685

; rung 36: 操作側左と操作側右の比較
LD P_On
OUT TR0
CMP(020) D3642 D3643
LD P_GT
OR P_EQ
ANDLD
CLC(041)
-BC(416) D3642 D3643 D680
LD TR0
AND P_LT
CLC(041)
-BC(416) D3643 D3642 D680
LD TR0
CMP(020) #100 D680
LD P_LT
OR P_EQ
ANDLD
OUT W210.15
LD TR0
AND P_GT
MOV(021) D680 D686

; rung 37: 反操作側右と操作側右の比較
LD P_On
OUT TR0
CMP(020) D3645 D3643
LD P_GT
OR P_EQ
ANDLD
CLC(041)
-BC(416) D3645 D3643 D681
LD TR0
AND P_LT
CLC(041)
-BC(416) D3643 D3645 D681
LD TR0
CMP(020) #100 D681
LD P_LT
OR P_EQ
ANDLD
OUT W212.13
LD TR0
AND P_GT
MOV(021) D681 D687
; rung 38: 反操作側左と操作側左の差が設定誤差内か判別
LDNOT W210.11
AND<(310) D3646 D682
OUT W210.04
; rung 39: 反操作側左と反操作側右の差が設定誤差内か判別
LDNOT W210.12
AND<(310) D3646 D683
OUT W210.05
; rung 40: 反操作側左と操作側右の差が設定誤差内か判別
LDNOT W210.13
AND<(310) D3646 D684
OUT W210.06
; rung 41: 操作側左と反操作側右の差が設定誤差内か判別
LDNOT W210.14
AND<(310) D3646 D685
OUT W210.07

; rung 42: 操作側左と操作側右の差が設定誤差内か判別
LDNOT W210.15
AND<(310) D3646 D686
OUT W210.08
; rung 43: 反操作側右と操作側右の差が設定誤差内か判別
LDNOT W212.13
AND<(310) D3646 D687
OUT W210.09
; rung 44
LDNOT W210.04
ANDNOT W210.05
ANDNOT W210.06
ANDNOT W210.07
ANDNOT W210.08
ANDNOT W210.09
ANDNOT W210.11
ANDNOT W210.12
ANDNOT W210.13
ANDNOT W210.14
ANDNOT W210.15
ANDNOT W212.13
OUTNOT W210.10
; rung 45: ----- 押出機昇降 反操作側（左） -----
LD P_On
OUT TR0
MOV(021) D3534 D3644
AND<=(315) D3641 D3644
OUT W211.10
LD TR0
AND>=(325) D3640 D3644
OUT W211.14
; rung 46: 以前は昇降SSﾊﾟﾙｽを保持するのにﾘﾚｰで自己保持していた / ｱﾝｻｰﾊﾞｯｸが遅くて保持できない場合は処理を変更すること
LD W220.15
LD 0.00
ANDNOT T0451
ORLD
LD W210.02
OR W211.03
ANDLD
AND W209.03
ANDNOT 0.01
ANDNOT 0.03
ANDNOT 0.05
ANDNOT 0.07
AND W399.14
ANDNOT W211.10
OUT W87.00
; rung 47
LD W87.00
AND W209.03
ANDNOT W86.11
LD W86.00
OR W86.08
ANDNOT 4.08
AND W86.14
ORLD
OUT 0.00
; rung 48
LD 0.00
ANDNOT 3.04
TIM 0451 #20
; rung 49
LD W220.14
LD 0.01
ANDNOT T0452
ORLD
LD W210.03
OR W211.08
ANDLD
AND W209.03
ANDNOT 0.00
ANDNOT 0.02
ANDNOT 0.04
ANDNOT 0.06
AND W399.15
ANDNOT W211.14
OUT W87.01

; rung 50
LD W87.01
AND W209.03
ANDNOT W86.11
LD W86.01
OR W86.09
ANDNOT 4.09
AND W86.14
ORLD
OUT 0.01
; rung 51
LD 0.01
ANDNOT 3.05
TIM 0452 #20
; rung 52: ----- 押出機昇降 反操作側（右） -----
LD P_On
OUT TR0
MOV(021) D3539 D3645
AND<=(315) D3641 D3645
OUT W211.11
LD TR0
AND>=(325) D3640 D3645
OUT W211.15
; rung 53
LD W220.15
LD 0.02
ANDNOT T0453
ORLD
LD W210.02
OR W211.04
ANDLD
AND W209.03
ANDNOT 0.03
ANDNOT 0.01
ANDNOT 0.05
ANDNOT 0.07
AND W399.14
ANDNOT W211.11
OUT W87.02
; rung 54
LD W87.02
AND W209.03
ANDNOT W86.11
LD W86.02
OR W86.08
ANDNOT 4.10
AND W86.14
ORLD
OUT 0.02
; rung 55
LD 0.02
ANDNOT 3.06
TIM 0453 #20
; rung 56
LD W220.14
LD 0.03
ANDNOT T0454
ORLD
LD W210.03
OR W211.09
ANDLD
AND W209.03
ANDNOT 0.02
ANDNOT 0.00
ANDNOT 0.04
ANDNOT 0.06
AND W399.15
ANDNOT W211.15
OUT W87.03

; rung 57
LD W87.03
AND W209.03
ANDNOT W86.11
LD W86.03
OR W86.09
ANDNOT 4.11
AND W86.14
ORLD
OUT 0.03
; rung 58
LD 0.03
ANDNOT 3.07
TIM 0454 #20
; rung 59: ----- 押出機昇降 操作側（左） -----
LD P_On
OUT TR0
MOV(021) D3524 D3642
AND<=(315) D3641 D3642
OUT W211.12
LD TR0
AND>=(325) D3640 D3642
OUT W212.14
; rung 60
LD W220.15
LD 0.04
ANDNOT T0455
ORLD
LD W210.02
OR W211.01
ANDLD
AND W209.03
ANDNOT 0.05
ANDNOT 0.01
ANDNOT 0.03
ANDNOT 0.07
AND W399.14
ANDNOT W211.12
OUT W87.04
; rung 61
LD W87.04
AND W209.03
ANDNOT W86.11
LD W86.04
OR W86.08
ANDNOT 4.12
AND W86.14
ORLD
OUT 0.04
; rung 62
LD 0.04
ANDNOT 3.08
TIM 0455 #20
; rung 63
LD W220.14
LD 0.05
ANDNOT T0456
ORLD
LD W210.03
OR W211.06
ANDLD
AND W209.03
ANDNOT 0.04
ANDNOT 0.00
ANDNOT 0.02
ANDNOT 0.06
AND W399.15
ANDNOT W212.14
OUT W87.05

; rung 64
LD W87.05
AND W209.03
ANDNOT W86.11
LD W86.05
OR W86.09
ANDNOT 4.13
AND W86.14
ORLD
OUT 0.05
; rung 65
LD 0.05
ANDNOT 3.09
TIM 0456 #20
; rung 66: ----- 押出機昇降 操作側（右） -----
LD P_On
OUT TR0
MOV(021) D3529 D3643
AND<=(315) D3641 D3643
OUT W211.13
LD TR0
AND>=(325) D3640 D3643
OUT W212.15
; rung 67
LD W220.15
LD 0.06
ANDNOT T0457
ORLD
LD W210.02
OR W211.02
ANDLD
AND W209.03
ANDNOT 0.07
ANDNOT 0.01
ANDNOT 0.03
ANDNOT 0.05
AND W399.14
ANDNOT W211.13
OUT W87.06
; rung 68
LD W87.06
AND W209.03
ANDNOT W86.11
LD W86.06
OR W86.08
ANDNOT 4.14
AND W86.14
ORLD
OUT 0.06
; rung 69
LD 0.06
ANDNOT 3.10
TIM 0457 #20
; rung 70
LD W220.14
LD 0.07
ANDNOT T0458
ORLD
LD W210.03
OR W211.07
ANDLD
AND W209.03
ANDNOT 0.06
ANDNOT 0.00
ANDNOT 0.02
ANDNOT 0.04
AND W399.15
ANDNOT W212.15
OUT W87.07

; rung 71
LD W87.07
AND W209.03
ANDNOT W86.11
LD W86.07
OR W86.09
ANDNOT 4.15
AND W86.14
ORLD
OUT 0.07
; rung 72
LD 0.07
ANDNOT 3.11
TIM 0458 #20
; rung 73: ----- 架台位置確認 -----
LD 401.00
LDNOT 401.00
ANDNOT 401.01
ORLD
OUT TR0
AND=(300) D11 #1
XFER(070) &2 D6902 D6900
LD TR0
AND=(300) D11 #2
XFER(070) &2 D6904 D6900
LD TR0
AND=(300) D11 #3
XFER(070) &2 D6906 D6900
LD TR0
AND=(300) D11 #4
XFER(070) &2 D6908 D6900
; rung 74
LD 401.00
LDNOT 401.00
ANDNOT 401.01
ORLD
OUT TR0
AND=(300) D11 #5
XFER(070) &2 D6910 D6900
LD TR0
AND=(300) D11 #6
XFER(070) &2 D6912 D6900
LD TR0
AND=(300) D11 #7
XFER(070) &2 D6914 D6900

; rung 75
LDNOT 401.00
AND 401.01
OR W86.11
OR=(300) D11 #0
OUT W490.00
; rung 76
LD>(320) D6900 D3642
AND>(320) D6900 D3643
AND>(320) D6900 D3644
AND>(320) D6900 D3645
AND<(310) D6901 D3642
AND<(310) D6901 D3643
AND<(310) D6901 D3644
AND<(310) D6901 D3645
OUT W490.01
; rung 77
LD 401.01
LDNOT 401.00
ANDNOT 401.01
ORLD
OUT TR0
AND=(300) D12 #1
XFER(070) &2 D6922 D6920
LD TR0
AND=(300) D12 #2
XFER(070) &2 D6924 D6920
LD TR0
AND=(300) D12 #3
XFER(070) &2 D6926 D6920
LD TR0
AND=(300) D12 #4
XFER(070) &2 D6928 D6920
; rung 78
LD 401.01
LDNOT 401.00
ANDNOT 401.01
ORLD
OUT TR0
AND=(300) D12 #5
XFER(070) &2 D6930 D6920
LD TR0
AND=(300) D12 #6
XFER(070) &2 D6932 D6920
LD TR0
AND=(300) D12 #7
XFER(070) &2 D6934 D6920
; rung 79
LD 401.00
ANDNOT 401.01
OR W86.11
OR=(300) D12 #0
OUT W490.03

; rung 80
LD>(320) D6920 D3642
AND>(320) D6920 D3643
AND>(320) D6920 D3644
AND>(320) D6920 D3645
AND<(310) D6921 D3642
AND<(310) D6921 D3643
AND<(310) D6921 D3644
AND<(310) D6921 D3645
OUT W490.04
; rung 81
LD W490.01
OR W490.00
LD W490.04
OR W490.03
ANDLD
OUT W490.05
OUT 420.15

### Section EXTRUDER

; rung 0: ********** ｼｮｯﾄ時間転送 **********
LD P_On
MOV(021) D2754 D20
MOV(021) D2754 425
; rung 1: ********** 押出機処理 **********
LD W363.10
OR W363.11
DIFU(013) W356.01
; rung 2
LD 10.06
AND 10.07
AND 10.08
AND 10.09
AND 10.10
AND 10.11
OUT W208.06
; rung 3: ----- 計算用初期値設定 -----
LD P_First_Cycle
MOV(021) #1000 D202
MOV(021) #0 D203
; rung 4: ***** 押出機運転設定画面(No.81)の手動減速／増速処理 ***** / 設定押出量を増加減しAPRで出た回転数をDAに設定(回転数を増減しているわけでは無い)
LD W379.05
AND W378.03
ANDNOT W509.15
AND W200.01
OR T0153
OUT W510.01
; rung 5
LD W379.05
AND W378.04
ANDNOT W509.15
AND W200.01
OR T0153
OUT W510.02

; rung 6: ----- 増速・減速の範囲設定 ----- / この範囲になると1毎INC/DECする / 押出機能力定数設定１及び２、ﾃﾞｰﾀ読出時に計算する。
LD W510.01
CLC(041)
-BC(416) D2867 #50 D635
AND P_CY
MOV(021) #0 D635
; rung 7
LD W510.01
MOVD(083) D2867 #21 D636
CLC(041)
-BC(416) D636 #5 D637
AND P_CY
MOV(021) #0 D637
; rung 8
LD W510.01
CLC(041)
-BC(416) D2803 #50 D631
AND P_CY
MOV(021) #0 D631
; rung 9
LD W510.01
CLC(041)
-BC(416) D2787 #50 D630
AND P_CY
MOV(021) #0 D630

; rung 10
LD W510.02
CLC(041)
-BC(416) D2835 #50 D633
AND P_CY
MOV(021) #0 D633
; rung 11
LD W510.02
CLC(041)
-BC(416) D2851 #50 D634
AND P_CY
MOV(021) #0 D634
; rung 12
LD W510.02
CLC(041)
-BC(416) D2819 #50 D632
AND P_CY
MOV(021) #0 D632
; rung 13: 押出機定数設定１(調整)画面の時、押出機最高回転数をBIN
LDNOT W509.15
AND W379.04
AND W378.13
BIN(023) D730 D748
BIN(023) D731 D749
BIN(023) D732 D750

; rung 14
LDNOT W509.15
AND W379.04
AND W378.13
BIN(023) D733 D751
BIN(023) D734 D752
BIN(023) D735 D753
; rung 15: --- 主材内層DA出力SCLﾃﾞｰﾀ ---
LD P_On
MOV(021) #0 D335
MOV(021) #0 D336
MOV(021) #4000 D337
MOV(021) D748 D338
; rung 16: --- 粉砕材層DA出力SCLﾃﾞｰﾀ ---
LD P_On
MOV(021) #0 D307
MOV(021) #0 D308
MOV(021) #4000 D309
MOV(021) D749 D310

; rung 17: --- 主材外層DA出力SCLﾃﾞｰﾀ ---
LD P_On
MOV(021) #0 D300
MOV(021) #0 D301
MOV(021) #4000 D302
MOV(021) D750 D303
; rung 18: --- ﾊﾞﾘﾔ材層DA出力SCLﾃﾞｰﾀ ---
LD P_On
MOV(021) #0 D321
MOV(021) #0 D322
MOV(021) #4000 D323
MOV(021) D751 D324
; rung 19: --- 接着内層DA出力SCLﾃﾞｰﾀ ---
LD P_On
MOV(021) #0 D328
MOV(021) #0 D329
MOV(021) #4000 D330
MOV(021) D752 D331

; rung 20: --- 接着外層DA出力SCLﾃﾞｰﾀ ---
LD P_On
MOV(021) #0 D314
MOV(021) #0 D315
MOV(021) #4000 D316
MOV(021) D753 D317
; rung 21: ----- ﾘﾓｰﾄ手動許可条件 -----
LD W379.05
AND W378.01
ANDNOT W509.15
ANDNOT H2.09
ANDNOT 17.10
OUT W510.00
; rung 22: ----- 主材外層　手動／ﾘﾓｰﾄ操作 -----
LD 10.08
DIFU(013) W511.15
; rung 23
LDNOT H2.09
ANDNOT 17.10
AND W511.15
AND 10.08
@MOV(021) #0 D3388
; rung 24
LDNOT H2.09
ANDNOT 17.10
AND 10.08
OUT TR0
ANDNOT W511.15
@MOV(021) D2727 D3388
LD TR0
MOV(021) D3388 D2727
; rung 25
LDNOT H2.09
ANDNOT 10.08
MOV(021) #0 D3388

; rung 26
LD W510.00
AND W218.01
ANDNOT W218.00
OUT TR0
CMP(020) D3388 D2787
AND P_LT
AND P_0_1s
OUT TR1
LDNOT T0288
OR W217.00
ANDLD
@++B(594) D3388
LD TR1
CMP(020) D630 D3388
AND P_LT
OUT W217.00
LD TR1
ANDNOT W217.00
AND T0288
CLC(041)
@+BC(406) #10 D3388 D3388
LD TR0
TIM 0288 #10
; rung 27
LD W510.00
AND W218.00
ANDNOT W218.01
OUT TR0
CMP(020) D3388 #0
AND P_GT
AND P_0_1s
OUT TR1
LDNOT T0289
OR W217.01
ANDLD
@--B(596) D3388
LD TR1
CMP(020) #50 D3388
AND P_GT
OUT W217.01
LD TR1
ANDNOT W217.01
AND T0289
CLC(041)
@-BC(416) D3388 #10 D3388
LD TR0
TIM 0289 #10
; rung 28: ----- 粉砕層　手動／ﾘﾓｰﾄ操作 -----
LD 10.07
DIFU(013) W511.14

; rung 29
LDNOT H2.09
ANDNOT 17.10
AND W511.14
AND 10.07
@MOV(021) #0 D3389
; rung 30
LDNOT H2.09
ANDNOT 17.10
AND 10.07
OUT TR0
ANDNOT W511.14
@MOV(021) D2728 D3389
LD TR0
MOV(021) D3389 D2728
; rung 31
LDNOT H2.09
ANDNOT 10.07
MOV(021) #0 D3389
; rung 32
LD W510.00
AND W218.03
ANDNOT W218.02
OUT TR0
CMP(020) D3389 D2803
AND P_LT
AND P_0_1s
OUT TR1
LDNOT T0290
OR W217.02
ANDLD
@++B(594) D3389
LD TR1
CMP(020) D631 D3389
AND P_LT
OUT W217.02
LD TR1
ANDNOT W217.02
AND T0290
CLC(041)
@+BC(406) #10 D3389 D3389
LD TR0
TIM 0290 #15

; rung 33
LD W510.00
AND W218.02
ANDNOT W218.03
OUT TR0
CMP(020) D3389 #0
AND P_GT
AND P_0_1s
OUT TR1
LDNOT T0291
OR W217.03
ANDLD
@--B(596) D3389
LD TR1
CMP(020) #50 D3389
AND P_GT
OUT W217.03
LD TR1
ANDNOT W217.03
AND T0291
CLC(041)
@-BC(416) D3389 #10 D3389
LD TR0
TIM 0291 #15
; rung 34: ----- 接着外層　手動／ﾘﾓｰﾄ操作 -----
LD 10.11
DIFU(013) W511.13
; rung 35
LDNOT H2.09
ANDNOT 17.10
AND W511.13
AND 10.11
@MOV(021) #0 D3390
; rung 36
LDNOT H2.09
ANDNOT 17.10
AND 10.11
OUT TR0
ANDNOT W511.13
@MOV(021) D2729 D3390
LD TR0
MOV(021) D3390 D2729
; rung 37
LDNOT H2.09
ANDNOT 10.11
MOV(021) #0 D3390

; rung 38
LD W510.00
AND W218.05
ANDNOT W218.04
OUT TR0
CMP(020) D3390 D2819
AND P_LT
AND P_0_1s
OUT TR1
LDNOT T0292
OR W217.04
ANDLD
@++B(594) D3390
LD TR1
CMP(020) D632 D3390
AND P_LT
OUT W217.04
LD TR1
ANDNOT W217.04
AND T0292
CLC(041)
@+BC(406) #10 D3390 D3390
LD TR0
TIM 0292 #15
; rung 39
LD W510.00
AND W218.04
ANDNOT W218.05
OUT TR0
CMP(020) D3390 #0
AND P_GT
AND P_0_1s
OUT TR1
LDNOT T0293
OR W217.05
ANDLD
@--B(596) D3390
LD TR1
CMP(020) #50 D3390
AND P_GT
OUT W217.05
LD TR1
ANDNOT W217.05
AND T0293
CLC(041)
@-BC(416) D3390 #10 D3390
LD TR0
TIM 0293 #15
; rung 40: ----- ﾊﾞﾘﾔｰ層　手動／ﾘﾓｰﾄ操作 -----
LD 10.09
DIFU(013) W511.12

; rung 41
LDNOT H2.09
ANDNOT 17.10
AND W511.12
AND 10.09
@MOV(021) #0 D3391
; rung 42
LDNOT H2.09
ANDNOT 17.10
AND 10.09
OUT TR0
ANDNOT W511.12
@MOV(021) D2730 D3391
LD TR0
MOV(021) D3391 D2730
; rung 43
LDNOT H2.09
ANDNOT 10.09
MOV(021) #0 D3391
; rung 44
LD W510.00
AND W218.07
ANDNOT W218.06
OUT TR0
CMP(020) D3391 D2835
AND P_LT
AND P_0_1s
OUT TR1
LDNOT T0294
OR W217.06
ANDLD
@++B(594) D3391
LD TR1
CMP(020) D633 D3391
AND P_LT
OUT W217.06
LD TR1
ANDNOT W217.06
AND T0294
CLC(041)
@+BC(406) #10 D3391 D3391
LD TR0
TIM 0294 #15

; rung 45
LD W510.00
AND W218.06
ANDNOT W218.07
OUT TR0
CMP(020) D3391 #0
AND P_GT
AND P_0_1s
OUT TR1
LDNOT T0295
OR W217.07
ANDLD
@--B(596) D3391
LD TR1
CMP(020) #50 D3391
AND P_GT
OUT W217.07
LD TR1
ANDNOT W217.07
AND T0295
CLC(041)
@-BC(416) D3391 #10 D3391
LD TR0
TIM 0295 #15
; rung 46: ----- 接着内層　手動／ﾘﾓｰﾄ操作 -----
LD 10.10
DIFU(013) W511.11
; rung 47
LDNOT H2.09
ANDNOT 17.10
AND W511.11
AND 10.10
@MOV(021) #0 D3392
; rung 48
LDNOT H2.09
ANDNOT 17.10
AND 10.10
OUT TR0
ANDNOT W511.11
@MOV(021) D2731 D3392
LD TR0
MOV(021) D3392 D2731
; rung 49
LDNOT H2.09
ANDNOT 10.10
MOV(021) #0 D3392

; rung 50
LD W510.00
AND W218.09
ANDNOT W218.08
OUT TR0
CMP(020) D3392 D2851
AND P_LT
AND P_0_1s
OUT TR1
LDNOT T0296
OR W217.08
ANDLD
@++B(594) D3392
LD TR1
CMP(020) D634 D3392
AND P_LT
OUT W217.08
LD TR1
ANDNOT W217.08
AND T0296
CLC(041)
@+BC(406) #10 D3392 D3392
LD TR0
TIM 0296 #15
; rung 51
LD W510.00
AND W218.08
ANDNOT W218.09
OUT TR0
CMP(020) D3392 #0
AND P_GT
AND P_0_1s
OUT TR1
LDNOT T0297
OR W217.09
ANDLD
@--B(596) D3392
LD TR1
CMP(020) #50 D3392
AND P_GT
OUT W217.09
LD TR1
ANDNOT W217.09
AND T0297
CLC(041)
@-BC(416) D3392 #10 D3392
LD TR0
TIM 0297 #15
; rung 52: ----- 主材内層　手動／ﾘﾓｰﾄ操作 -----
LD 10.06
DIFU(013) W511.10

; rung 53
LDNOT H2.09
ANDNOT 17.10
AND W511.10
AND 10.06
@MOV(021) #0 D3393
; rung 54
LDNOT H2.09
ANDNOT 17.10
AND 10.06
OUT TR0
ANDNOT W511.10
@MOV(021) D2732 D3393
LD TR0
MOV(021) D3393 D2732
; rung 55
LDNOT H2.09
ANDNOT 10.06
MOV(021) #0 D3393
; rung 56
LD W510.00
AND W218.11
ANDNOT W218.10
OUT TR0
CMP(020) D3393 D2867
AND P_LT
AND P_0_1s
OUT TR1
LDNOT T0298
OR W217.10
ANDLD
@++B(594) D3393
LD TR1
CMP(020) D635 D3393
AND P_LT
OUT W217.10
LD TR1
ANDNOT W217.10
AND T0298
CLC(041)
@+BC(406) #10 D3393 D3393
LD TR0
TIM 0298 #15

; rung 57
LD W510.00
AND W218.10
ANDNOT W218.11
OUT TR0
CMP(020) D3393 #0
AND P_GT
AND P_0_1s
OUT TR1
LDNOT T0299
OR W217.11
ANDLD
@--B(596) D3393
LD TR1
CMP(020) #50 D3393
AND P_GT
OUT W217.11
LD TR1
ANDNOT W217.11
AND T0299
CLC(041)
@-BC(416) D3393 #10 D3393
LD TR0
TIM 0299 #15
; rung 58
LD 6.10
LD W209.01
OR T0425
OR W290.00
OR T0003
OR T0004
OR T0005
ANDLD
ANDNOT W290.05
OUT TR0
LD T0005
OR T0002
ANDLD
OUT W290.00
LD TR0
ANDNOT T0425
TIM 0003 #9000
LD TR0
AND T0425
TIM 0002 #500
; rung 59
LD T0003
OR T0004
ANDNOT W290.05
TIM 0004 #5400
; rung 60
LD T0004
OR T0005
ANDNOT W290.05
TIM 0005 #300
; rung 61
LD T0333
AND T0348
AND T0363
AND T0378
AND T0393
AND T0408
AND W290.10
OUT W290.05

; rung 62
LD T0004
OR W290.06
ANDNOT W290.05
OUT W290.06
; rung 63
LD T0003
OR W290.07
ANDNOT W290.05
OUT W290.07
; rung 64
LD T0005
OR W290.08
ANDNOT W290.05
OUT W290.08
; rung 65
LD W290.06
AND W290.07
AND W290.08
OR T0002
ANDNOT W290.05
OUT W290.10
; rung 66
LD 6.10
LD W290.00
OR W212.05
ANDLD
OUT W291.00
OUT W291.01
OUT W291.02
OUT W291.03
OUT W291.04
OUT W291.05
OUT W291.08
; rung 67
LD W212.04
OR W212.05
ANDNOT W290.05
OUT W212.05
; rung 68
LDNOT W509.15
AND W379.05
OUT TR0
LD W378.09
OR W378.15
ANDLD
OUT W203.11
LD TR0
AND W378.12
OUT W204.08

; rung 69
LD W63.07
OUT TR0
ANDNOT H94.02
MOV(021) #89 W0
LD TR0
AND H94.02
MOV(021) #95 W0
; rung 70
LD H2.14
ANDNOT 17.10
OUT TR0
ANDNOT H80.15
OUT W203.10
LD TR0
AND H80.15
OUT W204.09
; rung 71
LD W203.10
OR W204.09
OUT TR0
AND 10.06
TIM 0130 #1200
LD TR0
AND 10.07
TIM 0131 #1200
; rung 72
LD W203.10
LD W204.09
AND W74.02
ORLD
AND 10.08
TIM 0132 #1200
; rung 73
LD W203.10
AND W209.00
LD W204.09
AND W74.03
ORLD
AND 10.09
TIM 0133 #600
; rung 74
LD W203.10
AND W209.01
LD W204.09
AND W74.04
ORLD
OUT TR0
AND 10.10
TIM 0134 #600
LD TR0
AND 10.11
TIM 0135 #600

; rung 75
LD W203.11
OUT TR0
AND>(320) D3738 D730
MOV(021) D730 D3738
LD TR0
AND>(320) D3740 D731
MOV(021) D731 D3740
LD TR0
AND>(320) D3739 D732
MOV(021) D732 D3739
; rung 76
LD W203.11
OUT TR0
AND>(320) D3741 D733
MOV(021) D733 D3741
LD TR0
AND>(320) D7106 D733
MOV(021) D733 D7106
LD TR0
AND>(320) D3742 D734
MOV(021) D734 D3742
LD TR0
AND>(320) D3743 D735
MOV(021) D735 D3743
; rung 77
LD W378.11
OUT TR0
AND>(320) D3121 D732
MOV(021) D732 D3121
LD TR0
AND>(320) D3122 D731
MOV(021) D731 D3122
LD TR0
AND>(320) D3123 D733
MOV(021) D733 D3123
LD TR0
AND>(320) D7108 D733
MOV(021) D733 D7108
; rung 78
LD W203.10
AND 2050.00
OUT W71.15

; rung 79
LD W203.10
AND W208.06
OUT TR0
AND C0097
@++B(594) D342
LD TR0
CMP(020) D342 D3744
LD P_EQ
OR P_GT
OR W209.00
ANDLD
OUT W209.00
MOV(021) D3744 D342
LD TR0
CMP(020) D3744 D343
ANDNOT P_EQ
MOV(021) #0 D342
LD TR0
MOV(021) D3744 D343
; rung 80
LDNOT H2.14
LD W203.10
ANDNOT 2054.04
ORLD
MOV(021) #0 D342
; rung 81
LD P_On
MOV(021) D342 D3747

; rung 82
LD W203.10
AND W209.00
OUT TR0
AND C0097
@++B(594) D344
LD TR0
CMP(020) D344 D3745
LD P_EQ
OR P_GT
OR W209.01
ANDLD
OUT W209.01
MOV(021) D3745 D344
LD TR0
CMP(020) D3745 D345
ANDNOT P_EQ
MOV(021) #0 D344
LD TR0
MOV(021) D3745 D345
; rung 83
LDNOT H2.14
MOV(021) #0 D344
; rung 84
LD P_On
MOV(021) D344 D3748

; rung 85
LD W203.10
AND W209.01
OUT TR0
AND C0097
@++B(594) D346
LD TR0
CMP(020) D346 D3746
LD P_EQ
OR P_GT
OR W209.02
ANDLD
OUT W209.02
MOV(021) D3746 D346
LD TR0
CMP(020) D3746 D347
ANDNOT P_EQ
MOV(021) #0 D346
LD TR0
MOV(021) D3746 D347
; rung 86
LDNOT H2.14
MOV(021) #0 D346
; rung 87
LD P_On
MOV(021) D346 D3749
; rung 88
LD 6.10
AND W203.10
AND W209.01
CMP(020) D346 D3130
AND P_EQ
OUT W209.10
; rung 89
LD W209.10
OR W209.11
ANDNOT W209.02
OUT W209.11
; rung 90
LDNOT W203.10
MOV(021) #0 D304

; rung 91
LD W203.10
ANDNOT W208.05
AND>(320) D342 #10
LD>S(322) D5964 D6001
OR W67.04
ANDLD
OUT W67.04
; rung 92
LD W203.10
AND W67.01
AND W53.12
AND H94.02
OR W208.05
MOV(021) #0 D6007
; rung 93
LD W203.10
AND W208.06
AND W67.04
LD W67.01
ANDNOT W53.12
ORNOT W67.01
ANDLD
AND H94.02
OUT TR0
AND C0097
@++B(594) D6007
LD TR0
CMP(020) D6007 D6004
LD P_EQ
OR P_GT
OR W67.01
ANDLD
OUT W67.01
MOV(021) D6004 D6007
; rung 94
LD W203.10
OUT TR0
ANDNOT W209.11
OUT TR1
LDNOT H94.02
LD H94.02
ANDNOT W67.01
ORLD
ANDLD
BIN(023) D3739 D304
LD TR1
AND H94.02
AND W67.01
BIN(023) D6010 D304
LD TR0
AND W209.11
BIN(023) D3121 D304
LD TR0
SCL(194) D304 D300 D305
BIN(023) D305 D306
AND 10.08
MOV(021) D306 2043

; rung 95: ********** ｵｰﾄｽﾀｰﾄｱｯﾌﾟ処理 ********** / ｵｰﾄｽﾀｰﾄｱｯﾌﾟとは押出機起動にて先に主材内層･主材外層･粉砕層を起動させ、設定時間後、ﾊﾞﾘﾔ層起動。 / 設定時間後、接着内層･接着外層を起動し更に設定時間後、自動運転也開始する。 / 但し、動作選択画面にて押出機運転設定－自動選択、ﾛｽｲﾝ制御－入、運転ﾓｰﾄﾞ設定－全自動 / 選択時にｵｰﾄｽﾀｰﾄｱｯﾌﾟ処理有効
LDNOT W203.10
MOV(021) #0 D311
; rung 96
LD W203.10
ANDNOT W208.01
AND>(320) D342 #10
LD>S(322) D5963 D6002
OR W67.05
ANDLD
OUT W67.05
; rung 97
LD W203.10
AND W67.02
AND W53.11
AND H94.02
OR W208.01
MOV(021) #0 D6008
; rung 98
LD W203.10
AND W208.06
AND W67.05
LD W67.02
ANDNOT W53.11
ORNOT W67.02
ANDLD
AND H94.02
OUT TR0
AND C0097
@++B(594) D6008
LD TR0
CMP(020) D6008 D6005
LD P_EQ
OR P_GT
OR W67.02
ANDLD
OUT W67.02
MOV(021) D6005 D6008

; rung 99
LD W203.10
OUT TR0
ANDNOT W209.11
OUT TR1
LDNOT H94.02
LD H94.02
ANDNOT W67.02
ORLD
ANDLD
BIN(023) D3740 D311
LD TR1
AND H94.02
AND W67.02
BIN(023) D6011 D311
LD TR0
AND W209.11
BIN(023) D3122 D311
LD TR0
SCL(194) D311 D307 D312
BIN(023) D312 D313
AND 10.07
MOV(021) D313 2042
; rung 100: --- ｽﾀｰﾄｱｯﾌﾟ押出機回転数設定範囲確認 --- / 設定が最高回転数以上の場合、強制的に最高回転数を転送
LDNOT W203.10
MOV(021) #0 D318
; rung 101
LD W203.10
BIN(023) D3743 D318
SCL(194) D318 D314 D319
BIN(023) D319 D320
AND 10.11
AND W209.01
MOV(021) D320 2046
OUT W88.01

; rung 102: ----- ﾊﾞﾘｱ過負荷対策 2014.07.17 ----- / 画面にSU完了前時間設定/ﾊﾞﾘｱ低回転数入力を追加 20140828 / FTSさんが作ったSU画面とJSW標準画面と別DMにしたが同じ値を入れないとおかしなことになると思われる
LD P_On
OUT TR0
ANDNOT W209.11
OUT TR1
AND P_Off
/B(434) D3741 #2 D7100
LD TR1
MOV(021) D7106 D7100
-B(414) D3746 D3749 D7102
LD TR0
AND W209.11
OUT TR0
AND P_Off
/B(434) D3123 #2 D7100
LD TR0
MOV(021) D7108 D7100
-B(414) D3130 D3749 D7102
; rung 103
LD>=(325) D7105 D7102
ANDNOT W209.11
LD>=(325) D7107 D7102
AND W209.11
ORLD
LD>=(325) #50 D7102
AND P_Off
ORLD
OR W498.00
AND W203.10
ANDNOT W209.02
ANDNOT W74.07
AND T0511
OUT W498.00
; rung 104: ﾊﾞﾘﾔ層押出機回転遅延設定時間がﾀｲﾑｱｯﾌﾟしたか確認
LDNOT W203.10
MOV(021) #0 D325

; rung 105
LD W203.10
OUT TR0
ANDNOT W209.11
ANDNOT W498.00
BIN(023) D3741 D325
LD TR0
AND W209.11
ANDNOT W498.00
BIN(023) D3123 D325
LD TR0
AND W498.00
BIN(023) D7100 D325
LD TR0
SCL(194) D325 D321 D326
BIN(023) D326 D327
AND 10.09
AND W209.00
MOV(021) D327 2044
OUT W88.00
; rung 106: ｽﾀｰﾄｱｯﾌﾟ処理中に押出機切PBを押して中断した場合、ｶｳﾝﾀをﾘｾｯﾄする様に追加 990415
LDNOT W203.10
MOV(021) #0 D332
; rung 107
LD W203.10
BIN(023) D3742 D332
SCL(194) D332 D328 D333
BIN(023) D333 D334
AND 10.10
AND W209.01
MOV(021) D334 2045
OUT W88.02

; rung 108: 接着層押出機回転遅延設定時間がﾀｲﾑｱｯﾌﾟしたか確認
LDNOT W203.10
MOV(021) #0 D339
; rung 109
LD W203.10
ANDNOT W208.04
AND>(320) D342 #10
LD>S(322) D5962 D6012
OR W67.03
ANDLD
OUT W67.03
; rung 110
LD W203.10
AND W67.00
AND W53.10
AND H94.02
OR W208.04
MOV(021) #0 D6006
; rung 111
LD W203.10
AND W208.06
AND W67.03
LD W67.00
ANDNOT W53.10
ORNOT W67.00
ANDLD
AND H94.02
OUT TR0
AND C0097
@++B(594) D6006
LD TR0
CMP(020) D6006 D6003
LD P_EQ
OR P_GT
OR W67.00
ANDLD
OUT W67.00
MOV(021) D6003 D6006
; rung 112
LD W203.10
OUT TR0
LDNOT H94.02
LD H94.02
ANDNOT W67.00
ORLD
ANDLD
BIN(023) D3738 D339
LD TR0
AND H94.02
AND W67.00
BIN(023) D6009 D339
LD TR0
SCL(194) D339 D335 D340
BIN(023) D340 D341
AND 10.06
MOV(021) D341 2041

; rung 113
LD W204.08
OUT TR0
CMP(020) D3610 D730
AND P_GT
MOV(021) D730 D3610
LD TR0
CMP(020) D3611 D731
AND P_GT
MOV(021) D731 D3611
LD TR0
AND 6.10
CMP(020) D3125 D731
LD TR0
AND P_GT
AND 6.10
MOV(021) D731 D3125
LD TR0
AND 6.10
CMP(020) D3126 D731
LD TR0
AND P_GT
AND 6.10
MOV(021) D731 D3126
; rung 114
LD W204.08
OUT TR0
CMP(020) D3614 D732
AND P_GT
MOV(021) D732 D3614
LD TR0
CMP(020) D3621 D732
AND P_GT
MOV(021) D732 D3621
LD TR0
CMP(020) D3623 D732
AND P_GT
MOV(021) D732 D3623

; rung 115
LD W204.08
OUT TR0
CMP(020) D3616 D733
AND P_GT
MOV(021) D733 D3616
LD TR0
CMP(020) D3619 D734
AND P_GT
MOV(021) D734 D3619
LD TR0
CMP(020) D3620 D735
AND P_GT
MOV(021) D735 D3620
; rung 116
LD H2.14
AND H80.15
ANDNOT 17.10
AND W157.13
OUT W77.00
; rung 117
LD W77.00
OUT TR0
CMP(020) D5962 D3612
ANDNOT P_LT
ANDNOT 2001.15
OUT W74.00
LD TR0
CMP(020) D5963 D3613
ANDNOT P_LT
ANDNOT 2002.15
OUT W74.01
; rung 118
LD W74.00
TIM 0427 D3631
; rung 119
LD T0427
OR W77.03
AND W77.00
OUT W77.03

; rung 120
LD W74.01
TIM 0428 D3632
AND 6.10
AND T0428
OUT W75.11
TIM 0436 D3127
AND T0436
OUT W75.12
TIM 0437 D3128
; rung 121
LD T0428
OR W77.04
AND W77.00
OUT W77.04
; rung 122
LD W77.03
AND W77.04
OUT W74.02
TIM 0429 D3615
; rung 123
LD T0429
OUT W74.03
TIM 0423 D3617
; rung 124
LD T0423
OUT W74.04
TIM 0424 D3618

; rung 125
LD T0424
OUT W74.05
OUT W77.09
TIM 0425 D3622
AND T0425
OUT W74.06
OUT W77.14
TIM 0426 D3624
; rung 126
LD T0437
ORNOT 6.10
AND T0426
OUT TR0
CMP(020) D5962 D3625
LDNOT P_LT
ANDNOT 2001.15
OR W78.01
ANDLD
OUT W78.01
LD TR0
CMP(020) D5963 D3626
LDNOT P_LT
ANDNOT 2002.15
OR W78.02
ANDLD
OUT W78.02
LD TR0
CMP(020) D5964 D3627
LDNOT P_LT
ANDNOT 2003.15
OR W78.03
ANDLD
OUT W78.03

; rung 127
LD T0437
ORNOT 6.10
AND T0426
OUT TR0
CMP(020) D5965 D3628
LDNOT P_LT
ANDNOT 2004.15
OR W78.04
ANDLD
OUT W78.04
LD TR0
CMP(020) D5966 D3629
LDNOT P_LT
ANDNOT 2005.15
OR W78.05
ANDLD
OUT W78.05
LD TR0
CMP(020) D5967 D3630
LDNOT P_LT
ANDNOT 2006.15
OR W78.06
ANDLD
OUT W78.06
; rung 128
LD W78.01
AND W78.02
AND W78.03
AND W78.04
AND W78.05
AND W78.06
OUT W74.07
DIFU(013) W75.09
; rung 129: ｵｰﾄｽﾀｰﾄ処理完了遅延確認 / ｵｰﾄｽﾀｰﾄ処理が完了(20902がON)したらHR0214が切れる
LD W77.00
OUT TR0
AND 11.05
OUT W77.01
LD TR0
AND 11.01
OUT W77.02
; rung 130
LD W74.02
OUT W77.10
OUT W77.11
AND 11.00
OUT W77.05
; rung 131
LD W74.03
AND 11.03
OUT W77.06

; rung 132
LD W74.04
OUT TR0
OUT W77.08
AND 11.04
OUT W77.07
LD TR0
AND 10.10
OUT W77.12
LD TR0
AND 11.02
OUT W77.15
LD TR0
AND 10.11
OUT W77.13
; rung 133
LD T0426
OUT W78.00
; rung 134
LD W74.07
OR W78.07
ANDNOT W204.00
ANDNOT 17.10
AND 2054.04
AND W208.06
OUT W78.07
; rung 135: ----- 主材外層ｵｰﾄｽﾀｰﾄｱｯﾌﾟ処理 -----
LDNOT W77.00
MOV(021) #0 D560
; rung 136
LD W77.00
BIN(023) D3610 D560
SCL(194) D560 D335 D561
AND 10.06
BIN(023) D561 2041
; rung 137: ----- 粉砕層ｵｰﾄｽﾀｰﾄｱｯﾌﾟ処理 -----
LDNOT W77.00
MOV(021) #0 D562

; rung 138
LD W77.00
OUT TR0
ANDNOT W75.11
BIN(023) D3611 D562
LD TR0
AND W75.11
ANDNOT W75.12
BIN(023) D3125 D562
LD TR0
AND W75.12
BIN(023) D3126 D562
LD TR0
SCL(194) D562 D307 D563
AND 10.07
BIN(023) D563 2042
; rung 139: ----- 接着外層ｵｰﾄｽﾀｰﾄｱｯﾌﾟ処理 ----- / 接着外層は設定ﾀｲﾏｰ後起動
LDNOT W77.00
MOV(021) #0 D564
; rung 140
LD W74.02
ANDNOT W74.05
BIN(023) D3614 D564
; rung 141
LD W74.05
ANDNOT W74.06
BIN(023) D3621 D564
; rung 142
LD W74.06
BIN(023) D3623 D564
; rung 143
LD W77.00
SCL(194) D564 D300 D565
AND 10.08
BIN(023) D565 2043

; rung 144: ----- ﾊﾞﾘﾔ層ｵｰﾄｽﾀｰﾄｱｯﾌﾟ処理 ----- / ﾊﾞﾘﾔ層は設定時間T.UP後起動
LDNOT W77.00
MOV(021) #0 D566
; rung 145
LD W74.03
BIN(023) D3616 D566
; rung 146
LD W77.00
SCL(194) D566 D321 D567
AND 10.09
BIN(023) D567 2044
; rung 147: ----- 接着内層ｵｰﾄｽﾀｰﾄｱｯﾌﾟ処理 ----- / 接着内層は設定時間T.UP後起動
LDNOT W77.00
MOV(021) #0 D568
; rung 148
LD W74.04
BIN(023) D3619 D568
; rung 149
LD W77.00
SCL(194) D568 D328 D569
AND 10.10
BIN(023) D569 2045
; rung 150: ----- 主材内層ｵｰﾄｽﾀｰﾄｱｯﾌﾟ処理 -----
LDNOT W77.00
MOV(021) #0 D570

; rung 151
LD W74.04
BIN(023) D3620 D570
; rung 152
LD W77.00
SCL(194) D570 D314 D571
AND 10.11
BIN(023) D571 2046
; rung 153: ********** 低押出ﾓｰﾄﾞ処理 ********** / 以前は動作選択画面にて切り替え
LDNOT H2.14
ANDNOT 427.00
AND H2.09
AND W208.06
AND 2054.10
LD H2.09
AND W208.06
AND 2054.08
OR 427.00
OR H2.14
ORNOT H2.09
ORNOT W208.06
KEEP(011) H98.15
; rung 154
LD H98.15
AND 420.07
OUT 426.02
; rung 155
LD 426.02
OR H98.15
OR W63.06
OUT 422.11
; rung 156
LD 6.10
LD H2.09
AND W208.06
AND 2054.08
LD W212.03
ANDNOT T0201
AND H98.15
ORLD
ANDLD
OUT W212.03
TIM 0201 D2996
AND<(310) T201 #100
OUT W212.04

; rung 157: ----- 押出機回転数設定範囲確認 ----- / 設定が最高回転数以上の場合、強制的に最高回転数にする
LDNOT W509.15
AND W379.06
AND W378.01
OUT TR0
AND>(320) D2733 D730
MOV(021) D730 D2733
LD TR0
AND>(320) D2734 D731
MOV(021) D731 D2734
LD TR0
AND>(320) D2735 D732
MOV(021) D732 D2735
LD TR0
AND>(320) D2736 D733
MOV(021) D733 D2736
LD TR0
AND>(320) D2737 D734
MOV(021) D734 D2737
LD TR0
AND>(320) D2738 D735
MOV(021) D735 D2738
; rung 158: ----- 低押出条件 -----
LD H98.15
ANDNOT H2.14
ANDNOT 17.10
ANDNOT 427.00
OUT W63.06
; rung 159: ----- 主内低押出ﾓｰﾄﾞ処理 -----
LDNOT H98.15
@MOV(021) #0 D1820
; rung 160
LD H98.15
OUT TR0
ANDNOT W212.03
BIN(023) D2733 D1820
LD TR0
AND W212.03
BIN(023) D2990 D1820

; rung 161
LD H98.15
SCL(194) D1820 D335 D1821
BIN(023) D1821 D1822
; rung 162
LD W63.06
AND 10.06
OUT W63.00
MOV(021) D1822 2041
; rung 163: ----- 粉砕低押出ﾓｰﾄﾞ処理 -----
LDNOT H98.15
@MOV(021) #0 D1850
; rung 164
LD H98.15
OUT TR0
ANDNOT W212.03
BIN(023) D2734 D1850
LD TR0
AND W212.03
BIN(023) D2992 D1850
; rung 165
LD H98.15
SCL(194) D1850 D307 D1851
BIN(023) D1851 D1852
; rung 166
LD W63.06
AND 10.07
OUT W63.01
MOV(021) D1852 2042

; rung 167: ----- 主外低押出ﾓｰﾄﾞ処理 -----
LDNOT H98.15
@MOV(021) #0 D1880
; rung 168
LD H98.15
OUT TR0
ANDNOT W212.03
BIN(023) D2735 D1880
LD TR0
AND W212.03
BIN(023) D2991 D1880
; rung 169
LD H98.15
SCL(194) D1880 D300 D1881
BIN(023) D1881 D1882
; rung 170
LD W63.06
AND 10.08
OUT W63.02
MOV(021) D1882 2043
; rung 171: ----- ﾊﾞﾘﾔ低押出ﾓｰﾄﾞ処理 -----
LDNOT H98.15
@MOV(021) #0 D1910
; rung 172
LD H98.15
OUT TR0
ANDNOT W212.03
BIN(023) D2736 D1910
LD TR0
AND W212.03
BIN(023) D2993 D1910

; rung 173
LD H98.15
SCL(194) D1910 D321 D1911
BIN(023) D1911 D1912
; rung 174
LD W63.06
AND 10.09
OUT W63.03
MOV(021) D1912 2044
; rung 175: ----- 接内低押出ﾓｰﾄﾞ処理 -----
LDNOT H98.15
@MOV(021) #0 D1940
; rung 176
LD H98.15
OUT TR0
ANDNOT W212.03
BIN(023) D2737 D1940
LD TR0
AND W212.03
BIN(023) D2994 D1940
; rung 177
LD H98.15
SCL(194) D1940 D328 D1941
BIN(023) D1941 D1942
; rung 178
LD W63.06
AND 10.10
OUT W63.04
MOV(021) D1942 2045

; rung 179: ----- 接外低押出ﾓｰﾄﾞ処理 -----
LDNOT H98.15
@MOV(021) #0 D1970
; rung 180
LD H98.15
OUT TR0
ANDNOT W212.03
BIN(023) D2738 D1970
LD TR0
AND W212.03
BIN(023) D2995 D1970
; rung 181
LD H98.15
SCL(194) D1970 D314 D1971
BIN(023) D1971 D1972
; rung 182
LD W63.06
AND 10.11
OUT W63.05
MOV(021) D1972 2046
; rung 183: ********** 押出機ﾛｰｶﾙ操作処理 **********
LD 17.10
AND 17.11
OUT W215.12
; rung 184
LD 17.10
AND T0511
OUT W215.13
; rung 185: ----- 主内押出機ﾛｰｶﾙ操作 -----
LD W215.13
OUT TR0
ANDNOT 2071.15
MOV(021) 2071 D2053
LD TR0
AND 2071.15
OUT W50.00
MOV(021) #0 D2053

; rung 186
LD W215.13
MOV(021) #0 D2054
MOV(021) #4000 D2056
SCL(194) D2053 D2054 D2058
AND>(320) D2058 #4000
MOV(021) #4000 D2058  // 10V以上は10Vに丸め込み
; rung 187
LD W215.13
AND 10.06
BIN(023) D2058 2041
; rung 188: ----- 粉砕押出機ﾛｰｶﾙ操作 -----
LD W215.13
OUT TR0
ANDNOT 2072.15
MOV(021) 2072 D2153
LD TR0
AND 2072.15
OUT W50.01
MOV(021) #0 D2153
; rung 189
LD W215.13
MOV(021) #0 D2154
MOV(021) #4000 D2156
SCL(194) D2153 D2154 D2158
AND>(320) D2158 #4000
MOV(021) #4000 D2158
; rung 190
LD W215.13
AND 10.07
BIN(023) D2158 2042

; rung 191: ----- 主外押出機ﾛｰｶﾙ操作 -----
LD W215.13
OUT TR0
ANDNOT 2073.15
MOV(021) 2073 D2253
LD TR0
AND 2073.15
OUT W50.02
MOV(021) #0 D2253
; rung 192
LD W215.13
MOV(021) #0 D2254
MOV(021) #4000 D2256
SCL(194) D2253 D2254 D2258
AND>(320) D2258 #4000
MOV(021) #4000 D2258
; rung 193
LD W215.13
AND 10.08
BIN(023) D2258 2043
; rung 194: ----- ﾊﾞﾘﾔ押出機ﾛｰｶﾙ操作 -----
LD W215.13
OUT TR0
ANDNOT 2074.15
MOV(021) 2074 D2353
LD TR0
AND 2074.15
OUT W50.03
MOV(021) #0 D2353

; rung 195
LD W215.13
MOV(021) #0 D2354
MOV(021) #4000 D2356
SCL(194) D2353 D2354 D2358
AND>(320) D2358 #4000
MOV(021) #4000 D2358
; rung 196
LD W215.13
AND 10.09
BIN(023) D2358 2044
; rung 197: ----- 接内押出機ﾛｰｶﾙ操作 -----
LD W215.13
OUT TR0
ANDNOT 2075.15
MOV(021) 2075 D2453
LD TR0
AND 2075.15
OUT W50.04
MOV(021) #0 D2453
; rung 198
LD W215.13
MOV(021) #0 D2454
MOV(021) #4000 D2456
SCL(194) D2453 D2454 D2458
AND>(320) D2458 #4000
MOV(021) #4000 D2458
; rung 199
LD W215.13
AND 10.10
BIN(023) D2458 2045

; rung 200: ----- 接外押出機ﾛｰｶﾙ操作 -----
LD W215.13
OUT TR0
ANDNOT 2076.15
MOV(021) 2076 D2553
LD TR0
AND 2076.15
OUT W50.05
MOV(021) #0 D2553
; rung 201
LD W215.13
MOV(021) #0 D2554
MOV(021) #4000 D2556
SCL(194) D2553 D2554 D2558
AND>(320) D2558 #4000
MOV(021) #4000 D2558
; rung 202
LD W215.13
AND 10.11
BIN(023) D2558 2046
; rung 203: ********** ロスインプログラム追加 **********
LD P_On
MOV(021) #3600 D2906
MOV(021) #0 D2755

; rung 204: ----- 全設定押出量Ｑ(画面表示 全設定押出量)を算出 ----- / Ｗ：パリソン重量(画面設定ｼｮｯﾄ重量) Ｔ：成形サイクル(画面設定ｼｮｯﾄ時間) / Ｑ(kg/H)=Ｗ(kg)÷T(sec)×3600
LD H2.09
AND H2.13
*B(424) D2906 D2739 D2740
/BL(435) D2740 D2754 D2756
; rung 205: 押出機運転自動選択時、押出機運転設定・押出機運転モニタ・動作選択画面表示中 / 接点ON
LD T0152
LD W379.02
AND W378.00
LD W378.01
OR W378.00
AND W379.05
ORLD
ANDNOT W509.15
AND H2.09
ORLD
OUT W200.00
; rung 206: --- 各層の重量比を求める --- / 画面の設定構成比はあくまで膜厚比(体積%)として処理 / 各重量比＝樹脂の比重(密度)×各層構成比（体積：画面より設定） / 主材外層重量比Ｑ1＝DM3396(密度)×主材外層設定構成比(体積)(画面設定)を求める
LD W200.00
*B(424) D3400 D3396 D900
MOV(021) #10 D902
MOV(021) #0 D903
*BL(425) D900 D902 D904

; rung 207: 粉砕材層重量比Ｑ2＝DM3395(密度)×粉砕材層設定構成比(体積)(画面設定)を求める
LD W200.00
*B(424) D3401 D3395 D908
MOV(021) #10 D910
MOV(021) #0 D911
*BL(425) D908 D910 D912
; rung 208: 接着外層重量比Ｑ3＝DM3399(密度)×接着外層設定構成比(体積)(画面設定)を求める
LD W200.00
*B(424) D3402 D3399 D916
MOV(021) #10 D918
MOV(021) #0 D919
*BL(425) D916 D918 D920
; rung 209: ﾊﾞﾘﾔ層重量比Ｑ4＝DM3397(密度)×ﾊﾞﾘﾔ層設定構成比(体積)(画面設定)を求める
LD W200.00
*B(424) D3403 D3397 D924
MOV(021) #10 D926
MOV(021) #0 D927
*BL(425) D924 D926 D928

; rung 210: 接着内層重量比Ｑ5＝DM3398(密度)×接着内層設定構成比(体積)(画面設定)を求める
LD W200.00
*B(424) D3404 D3398 D932
MOV(021) #10 D934
MOV(021) #0 D935
*BL(425) D932 D934 D936
; rung 211: 主材内層重量比Ｑ6＝DM3394(体積)×主材内層設定構成比(体積)(画面設定)を求める
LD W200.00
*B(424) D3405 D3394 D940
MOV(021) #10 D942
MOV(021) #0 D943
*BL(425) D940 D942 D944
; rung 212: --- 各重量比を計算し総重量比を求める --- / 総重量比=Q1+Q2+Q3+Q4+Q5+Q6 / 注）画面から比重設定出来る様にした為、全て比重1.000に設定した場合、構成比が桁上がりするので計算式変更。 / Q1+Q2
LD W200.00
CLC(041)
+BCL(407) D900 D908 D948

; rung 213: Q1+Q2+Q3
LD W200.00
CLC(041)
+BCL(407) D948 D916 D950
; rung 214: Q1+Q2+Q3+Q4
LD W200.00
CLC(041)
+BCL(407) D950 D924 D952
; rung 215: Q1+Q2+Q3+Q4+Q5
LD W200.00
CLC(041)
+BCL(407) D952 D932 D954
; rung 216: Q1+Q2+Q3+Q4+Q5+Q6
LD W200.00
CLC(041)
+BCL(407) D954 D940 D956

; rung 217: 注意 ******************************************* / 全重量比を四捨五入し桁を合わせる。
LD W200.00
MOV(021) D956 D983
MOV(021) D957 D984
SRD(075) D983 D984
SRD(075) D983 D984
CLC(041)
+BCL(407) D983 D190 D985
SRD(075) D985 D986
; rung 218: --- 層構成比を求める --- / 各層構成比=各層重量比÷全重量比 / 主材外層構成比＝主材外層重量比÷全重量比
LD W200.00
MOV(021) #0 D958
/BL(435) D904 D985 D959
; rung 219: 粉砕材層構成比＝粉砕材層重量比÷全重量比
LD W200.00
/BL(435) D912 D985 D963
; rung 220: 接着外層構成比＝接着外層重量比÷全重量比
LD W200.00
/BL(435) D920 D985 D967

; rung 221: バリヤ層構成比＝バリヤ層重量比÷全重量比
LD W200.00
/BL(435) D928 D985 D971
; rung 222: 接着内層構成比＝接着内層重量比÷全重量比
LD W200.00
/BL(435) D936 D985 D975
; rung 223: 主材内層構成比＝主材内層重量比÷全重量比
LD W200.00
/BL(435) D944 D985 D979
; rung 224: --- 設定押出量算出 --- / 各設定押出量は先に求めた総可塑化Q(kg/h)(１時間当りの押出量)と各層構成比から算出 / 各層押出量=総可塑化×各層構成比 / 主材外層押出量算出
LD W200.00
*B(424) D959 D2756 D2742
CLC(041)
+BCL(407) D2742 D192 D2742
MOVD(083) D2742 #3 D2727
MOVD(083) D2743 #120 D2727

; rung 225: 粉砕材層押出量算出
LD W200.00
*B(424) D963 D2756 D2744
CLC(041)
+BCL(407) D2744 D200 D2744
MOVD(083) D2744 #3 D2728
MOVD(083) D2745 #120 D2728
; rung 226: 接着外層押出量算出
LD W200.00
*B(424) D967 D2756 D2746
CLC(041)
+BCL(407) D2746 D192 D2746
MOVD(083) D2746 #12 D2729
MOVD(083) D2747 #210 D2729

; rung 227: バリヤ層押出量算出
LD W200.00
*B(424) D971 D2756 D2748
CLC(041)
+BCL(407) D2748 D192 D2748
MOVD(083) D2748 #12 D2730
MOVD(083) D2749 #210 D2730
; rung 228: 接着内層押出量算出
LD W200.00
*B(424) D975 D2756 D2750
CLC(041)
+BCL(407) D2750 D192 D2750
MOVD(083) D2750 #12 D2731
MOVD(083) D2751 #210 D2731

; rung 229: 主材内層押出量算出
LD W200.00
*B(424) D979 D2756 D2752
CLC(041)
+BCL(407) D2752 D200 D2752
MOVD(083) D2752 #3 D2732
MOVD(083) D2753 #120 D2732
; rung 230: --- 単独自動時の主材内層押出機処理 ---
LD 10.06
ANDNOT W509.15
AND W379.05
AND W378.01
AND H2.09
ANDNOT H2.13
ANDNOT 17.10
OUT W208.07
; rung 231
LD 10.06
MOV(021) D2732 D3649
; rung 232
LDNOT 10.06
MOV(021) #0 D2770
; rung 233
LD 10.06
AND H2.09
ANDNOT H2.13
ANDNOT 17.10
@MOV(021) D3649 D2770

; rung 234
LD W208.07
AND W218.13
ANDNOT W218.12
OUT TR0
CMP(020) D2770 D2867
AND P_LT
AND P_0_1s
OUT TR1
LDNOT T0300
OR W200.02
ANDLD
@++B(594) D2770
LD TR1
CMP(020) D635 D2770
AND P_LT
OUT W200.02
LD TR1
ANDNOT W200.02
AND T0300
CLC(041)
@+BC(406) #10 D2770 D2770
LD TR0
TIM 0300 #15
; rung 235
LD W208.07
AND W218.12
ANDNOT W218.13
OUT TR0
CMP(020) D2770 #0
AND P_GT
AND P_0_1s
OUT TR1
LDNOT T0301
OR W200.03
ANDLD
@--B(596) D2770
LD TR1
CMP(020) #50 D2770
AND P_GT
OUT W200.03
LD TR1
ANDNOT W200.03
AND T0301
CLC(041)
@-BC(416) D2770 #10 D2770
LD TR0
TIM 0301 #15

; rung 236
LD H2.09
ANDNOT H2.13
ANDNOT 17.10
AND 10.06
MOV(021) D2770 D2761
MOV(021) D3405 D2762
/BL(435) D2760 D2762 D2764
MOVD(083) D2764 #21 D2756
MOVD(083) D2765 #300 D2756
; rung 237: ************************************************** / 上処理で求めた各層の設定押出量を押出機能力設定画面のAPR変化に当てはめ各層の設定速度を求める
LD P_On
BIN(023) D2727 D2619
BIN(023) D2728 D2640
BIN(023) D2729 D2661
BIN(023) D2730 D2682
BIN(023) D2731 D2703
BIN(023) D2732 D2724

; rung 238: ********** 押出機能力定数設定画面よりAPRのﾃﾞｰﾀﾃｰﾌﾞﾙを作成 ********** / 折線近似APRの初期設定
LD P_On
MOV(021) #0 D2602
MOV(021) #0 D2623
MOV(021) #0 D2644
MOV(021) #0 D2665
MOV(021) #0 D2686
MOV(021) #0 D2707
; rung 239
LD P_On
MOV(021) D2617 D2601
MOV(021) D2638 D2622
MOV(021) D2659 D2643
MOV(021) D2680 D2664
MOV(021) D2701 D2685
MOV(021) D2722 D2706

; rung 240
LD P_On
MOV(021) #0 D2780
MOV(021) #0 D2788
MOV(021) #0 D2796
MOV(021) #0 D2804
MOV(021) #0 D2812
MOV(021) #0 D2820
MOV(021) #0 D2828
MOV(021) #0 D2836
MOV(021) #0 D2844
MOV(021) #0 D2852
MOV(021) #0 D2860
MOV(021) #0 D2868

; rung 241: ----- 主材外層押出量データ変換 -----
LD W510.01
@BIN(023) D2780 D2603
@BIN(023) D2781 D2605
@BIN(023) D2782 D2607
@BIN(023) D2783 D2609
@BIN(023) D2784 D2611
@BIN(023) D2785 D2613
@BIN(023) D2786 D2615
@BIN(023) D2787 D2617

; rung 242: ----- 主材外層ｽｸﾘｭｰ回転数データ変換 -----
LD W510.01
@BIN(023) D2788 D2604
@BIN(023) D2789 D2606
@BIN(023) D2790 D2608
@BIN(023) D2791 D2610
@BIN(023) D2792 D2612
@BIN(023) D2793 D2614
@BIN(023) D2794 D2616
@BIN(023) D2795 D2618

; rung 243: ----- 粉砕材層押出量データ変換 -----
LD W510.01
@BIN(023) D2796 D2624
@BIN(023) D2797 D2626
@BIN(023) D2798 D2628
@BIN(023) D2799 D2630
@BIN(023) D2800 D2632
@BIN(023) D2801 D2634
@BIN(023) D2802 D2636
@BIN(023) D2803 D2638

; rung 244: ----- 粉砕材層ｽｸﾘｭｰ回転数データ変換 -----
LD W510.01
@BIN(023) D2804 D2625
@BIN(023) D2805 D2627
@BIN(023) D2806 D2629
@BIN(023) D2807 D2631
@BIN(023) D2808 D2633
@BIN(023) D2809 D2635
@BIN(023) D2810 D2637
@BIN(023) D2811 D2639

; rung 245: ----- 接着外層押出量データ変換 -----
LD W510.02
@BIN(023) D2812 D2645
@BIN(023) D2813 D2647
@BIN(023) D2814 D2649
@BIN(023) D2815 D2651
@BIN(023) D2816 D2653
@BIN(023) D2817 D2655
@BIN(023) D2818 D2657
@BIN(023) D2819 D2659

; rung 246: ----- 接着外層ｽｸﾘｭｰ回転数データ変換 -----
LD W510.02
@BIN(023) D2820 D2646
@BIN(023) D2821 D2648
@BIN(023) D2822 D2650
@BIN(023) D2823 D2652
@BIN(023) D2824 D2654
@BIN(023) D2825 D2656
@BIN(023) D2826 D2658
@BIN(023) D2827 D2660

; rung 247: ----- ﾊﾞﾘｱ層押出量データ変換 -----
LD W510.02
@BIN(023) D2828 D2666
@BIN(023) D2829 D2668
@BIN(023) D2830 D2670
@BIN(023) D2831 D2672
@BIN(023) D2832 D2674
@BIN(023) D2833 D2676
@BIN(023) D2834 D2678
@BIN(023) D2835 D2680

; rung 248: ----- ﾊﾞﾘｱ層ｽｸﾘｭｰ回転数データ変換 -----
LD W510.02
@BIN(023) D2836 D2667
@BIN(023) D2837 D2669
@BIN(023) D2838 D2671
@BIN(023) D2839 D2673
@BIN(023) D2840 D2675
@BIN(023) D2841 D2677
@BIN(023) D2842 D2679
@BIN(023) D2843 D2681

; rung 249: ----- 接着内層押出量データ変換 -----
LD W510.02
@BIN(023) D2844 D2687
@BIN(023) D2845 D2689
@BIN(023) D2846 D2691
@BIN(023) D2847 D2693
@BIN(023) D2848 D2695
@BIN(023) D2849 D2697
@BIN(023) D2850 D2699
@BIN(023) D2851 D2701

; rung 250: ----- 接着内層ｽｸﾘｭｰ回転数データ変換 -----
LD W510.02
@BIN(023) D2852 D2688
@BIN(023) D2853 D2690
@BIN(023) D2854 D2692
@BIN(023) D2855 D2694
@BIN(023) D2856 D2696
@BIN(023) D2857 D2698
@BIN(023) D2858 D2700
@BIN(023) D2859 D2702

; rung 251: ----- 主材内層押出量データ変換 -----
LD W510.01
@BIN(023) D2860 D2708
@BIN(023) D2861 D2710
@BIN(023) D2862 D2712
@BIN(023) D2863 D2714
@BIN(023) D2864 D2716
@BIN(023) D2865 D2718
@BIN(023) D2866 D2720
@BIN(023) D2867 D2722

; rung 252: ----- 主材内層ｽｸﾘｭｰ回転数データ変換 -----
LD W510.01
@BIN(023) D2868 D2709
@BIN(023) D2869 D2711
@BIN(023) D2870 D2713
@BIN(023) D2871 D2715
@BIN(023) D2872 D2717
@BIN(023) D2873 D2719
@BIN(023) D2874 D2721
@BIN(023) D2875 D2723
; rung 253: ----- 押出機能力定数ﾃｰﾌﾞﾙ(画面)から設定押出量(画面)の時の回転数を求める -----
LD 10.08
MOV(021) #7 D2600
APR(069) D2600 D2619 D2620
; rung 254
LD 10.07
MOV(021) #7 D2621
APR(069) D2621 D2640 D2641

; rung 255
LD 10.11
MOV(021) #7 D2642
APR(069) D2642 D2661 D2662
; rung 256
LD 10.09
MOV(021) #7 D2663
APR(069) D2663 D2682 D2683
; rung 257
LD 10.10
MOV(021) #7 D2684
APR(069) D2684 D2703 D2704
; rung 258
LD 10.06
MOV(021) #7 D2705
APR(069) D2705 D2724 D2725
; rung 259: ********** 押出機回転数DA出力(基本的な部分) ********** / 回転数に乗算している定数はDAﾌﾙ出力4000(0FA0)を最高回転数で除算した0.1(or 0.01)rpmに対する / DAの値(4000/回転数)(40000000/****)。DA出力は最高回転数で10V出力するようになっている。 / ----- 主材外層 ----- / 最高回転数/10V / 操作ﾛｰｶﾙ接点追加
LDNOT 17.10
AND 10.08
SCL(194) D2620 D300 D2888
BIN(023) D2888 D2894
ANDNOT 427.00
ANDNOT H2.14
ANDNOT H98.15
OUT TR0
ANDNOT H2.12
MOV(021) D2894 2043
LD TR0
AND H2.12
AND H2.13
@MOV(021) D2894 2043

; rung 260
LDNOT 10.08
MOV(021) #0 2043
; rung 261: ----- 粉砕材層 ----- / 最高回転数/ 10V / 操作ﾛｰｶﾙ接点追加
LDNOT 17.10
AND 10.07
SCL(194) D2641 D307 D2889
BIN(023) D2889 D2895
ANDNOT 427.00
ANDNOT H2.14
ANDNOT H98.15
OUT TR0
ANDNOT H2.12
MOV(021) D2895 2042
LD TR0
AND H2.12
AND H2.13
@MOV(021) D2895 2042
; rung 262
LDNOT 10.07
MOV(021) #0 2042
; rung 263: ----- 接着外層 ----- / 最高回転数/ 10V / 操作ﾛｰｶﾙ接点追加
LDNOT 17.10
AND 10.11
SCL(194) D2662 D314 D2890
BIN(023) D2890 D2896
ANDNOT 427.00
ANDNOT H2.14
ANDNOT H98.15
OUT TR0
ANDNOT H2.12
MOV(021) D2896 2046
LD TR0
AND H2.12
AND H2.13
@MOV(021) D2896 2046
; rung 264
LDNOT 10.11
MOV(021) #0 2046

; rung 265: ----- ﾊﾞﾘﾔ材層 ----- / 最高回転数 / 10V / 操作ﾛｰｶﾙ接点追加
LDNOT 17.10
AND 10.09
SCL(194) D2683 D321 D2891
BIN(023) D2891 D2897
ANDNOT 427.00
ANDNOT H2.14
ANDNOT H98.15
OUT TR0
ANDNOT H2.12
MOV(021) D2897 2044
LD TR0
AND H2.12
AND H2.13
@MOV(021) D2897 2044
; rung 266
LDNOT 10.09
MOV(021) #0 2044
; rung 267: ----- 接着内層 ----- / 最高回転数 / 10V / 操作ﾛｰｶﾙ接点追加
LDNOT 17.10
AND 10.10
SCL(194) D2704 D328 D2892
BIN(023) D2892 D2898
ANDNOT 427.00
ANDNOT H2.14
ANDNOT H98.15
OUT TR0
ANDNOT H2.12
MOV(021) D2898 2045
LD TR0
AND H2.12
AND H2.13
@MOV(021) D2898 2045
; rung 268
LDNOT 10.10
MOV(021) #0 2045

; rung 269: ----- 主材内層 ----- / 最高回転数 / 10V / 操作ﾛｰｶﾙ接点追加
LDNOT 17.10
AND 10.06
SCL(194) D2725 D335 D2893
BIN(023) D2893 D2899
ANDNOT 427.00
ANDNOT H2.14
ANDNOT H98.15
OUT TR0
ANDNOT H2.12
MOV(021) D2899 2041
LD TR0
AND H2.12
AND H2.13
@MOV(021) D2899 2041
; rung 270
LDNOT 10.06
MOV(021) #0 2041
; rung 271: ********** 原料供給装置に各押出機の設定押出量を転送 **********
LD P_On
MOV(021) D2727 416
MOV(021) D2728 415
MOV(021) D2729 419
MOV(021) D2730 417
MOV(021) D2731 418
MOV(021) D2732 414

; rung 272: ***** 押出機設定速度にロスイン信号付加処理 ***** / ロスイン補正方法を旧方式にする場合は下記HR98ﾘﾚｰをOFFする
LD P_On
OUT H98.06
OUT H98.07
OUT H98.08
OUT H98.09
OUT H98.10
OUT H98.11
; rung 273
LDNOT H2.14
AND H2.12
ANDNOT 17.10
ANDNOT H98.15
ANDNOT W73.00
OUT W203.02
; rung 274: *********** 主材外層ロスイン演算 ********** / ﾛｽｲﾝ指令値=(設定押出量(画面)×ﾛｽｲﾝ割合)÷最大押出量×ﾛｽｲﾝ補正量設定(画面) / ﾛｽｲﾝ補正量が±5%以内か判別(ﾛｽｲﾝ安定ﾗﾝﾌﾟ追加した為)
LD W203.02
AND H90.02
ANDNOT 427.00
AND 10.08
AND>(320) D172 #950
AND<(310) D172 #1050
OUT W60.06
; rung 275: 原料供給装置からの偏差信号が100.0%以上か判別しﾛｽｲﾝの割合を求める
LD W203.02
AND 10.08
AND W156.02
OUT W203.04
; rung 276
LD W203.04
OUT TR0
CMP(020) D172 #1000
LD P_GT
OR P_EQ
ANDLD
OUT W202.00
LD TR0
AND P_LT
OUT W202.01
LD TR0
AND W202.00
CLC(041)
@-BC(416) D172 #1000 D3212
LD TR0
AND W202.01
CLC(041)
@-BC(416) #1000 D172 D3212

; rung 277: '主外ﾛｽｲﾝ割合値が99.9%以上か判別(以上の場合は99.9%に丸込) / 主外設定押出量Q(画面)×偏差量ε(受信したﾛｽｲﾝ値から-100 or 100- した偏差量)
LD W203.04
OUT TR0
CMP(020) D3212 #999
AND P_GT
OUT W202.02
LD TR0
AND W202.02
@MOV(021) #999 D3212
LD TR0
@MOVD(083) D3212 #120 D3218
@*B(424) D2727 D3218 D3219
; rung 278: 主外補正量が5%以上か判別し5%以上の場合はﾛｽｲﾝ補正係数大(画面)を補正係数に。 / 5%未満の場合はﾛｽｲﾝ補正係数小(画面)を補正係数に。
LD W203.04
OUT TR0
CMP(020) D3218 #500
LD P_GT
OR P_EQ
ANDLD
@MOV(021) D3206 D3291
LD TR0
AND P_LT
@MOV(021) D3200 D3291
; rung 279: ﾛｽｲﾝ指令値＝設定回転数／最大回転数×ﾛｽｲﾝ割合値×ﾛｽｲﾝ補正係数を求める
LD W203.04
@MOV(021) D2787 D3221
@MOV(021) #0 D3222
@/BL(435) D3219 D3221 D3222
@*B(424) D3222 D3291 D3226

; rung 280
LD W203.04
@MOVD(083) D3226 #3 D3228
@MOVD(083) D3227 #120 D3228
@SRD(075) D3228 D3228
@BIN(023) D3228 D3228
@ASL(025) D3228
@ASL(025) D3228
@BCD(024) D3228 D3228
AND<(310) D3228 #1
MOV(021) #1 D3228
; rung 281
LD W203.04
AND H98.07
AND<(310) D3218 D755
OUT W60.00

; rung 282: 主外ﾛｽｲﾝ出力が＋の場合、補正量を現在の設定押出量に－する。 / 主外ﾛｽｲﾝ出力が－の場合、補正量を現在の設定押出量に＋する。
LDNOT W60.00
ORNOT H98.07
AND H90.02
AND H2.13
ANDNOT 427.00
AND W203.04
OUT TR0
@BIN(023) D3228 D3229
AND W202.00
CLC(041)
@-C(412) 2043 D3229 2043
AND P_CY
MOV(021) #0 2043
LD TR0
AND W202.01
CLC(041)
@+C(402) 2043 D3229 2043
; rung 283: 押出機回転設定上限規制
LD H90.02
AND H2.13
ANDNOT 427.00
AND W203.04
AND>(320) 2043 #FA0
MOV(021) #FA0 2043
; rung 284: ********** 粉砕材層ロスイン演算 ********** / ﾛｽｲﾝ補正量が±5%以内か判別(ﾛｽｲﾝ安定ﾗﾝﾌﾟ追加した為)
LD W203.02
AND H90.01
ANDNOT 427.00
AND 10.07
AND>(320) D171 #950
AND<(310) D171 #1050
OUT W60.07
; rung 285: 原料供給装置からの偏差信号が100.0%以上か判別しﾛｽｲﾝの割合を求める
LD W203.02
AND 10.07
AND W156.01
OUT W203.05

; rung 286
LD W203.05
OUT TR0
CMP(020) D171 #1000
LD P_GT
OR P_EQ
ANDLD
OUT W202.03
LD TR0
AND P_LT
OUT W202.04
LD TR0
AND W202.03
CLC(041)
@-BC(416) D171 #1000 D3213
LD TR0
AND W202.04
CLC(041)
@-BC(416) #1000 D171 D3213
; rung 287: 粉砕ﾛｽｲﾝ割合値が99.9%以上か判別(以上の場合は99.9%に丸込) / 粉砕設定押出量Q(画面)×偏差量ε
LD W203.05
OUT TR0
CMP(020) D3213 #999
AND P_GT
OUT W202.05
LD TR0
AND W202.05
@MOV(021) #999 D3213
LD TR0
@MOVD(083) D3213 #120 D3230
@*B(424) D2728 D3230 D3231

; rung 288: 粉砕補正量が10%以上か判別し10%以上の場合はﾛｽｲﾝ補正係数大(画面)を補正係数に。 / 10%未満の場合はﾛｽｲﾝ補正係数小(画面)を補正係数に。 / 今回5%未満
LD W203.05
OUT TR0
CMP(020) D3230 #500
LD P_GT
OR P_EQ
ANDLD
@MOV(021) D3207 D3292
LD TR0
AND P_LT
@MOV(021) D3201 D3292
; rung 289: ﾛｽｲﾝ指令値＝設定回転数／最大回転数×ﾛｽｲﾝ割合値×ﾛｽｲﾝ補正係数を求める
LD W203.05
@MOV(021) D2803 D3233
@MOV(021) #0 D3234
@/BL(435) D3231 D3233 D3234
@*B(424) D3234 D3292 D3238

; rung 290
LD W203.05
@MOVD(083) D3238 #3 D3240
@MOVD(083) D3239 #120 D3240
@SRD(075) D3240 D3240
@BIN(023) D3240 D3240
@ASL(025) D3240
@ASL(025) D3240
@BCD(024) D3240 D3240
AND<(310) D3240 #1
MOV(021) #1 D3240
; rung 291
LD W203.05
AND H98.06
AND<(310) D3230 D754
OUT W60.01

; rung 292: 粉砕ﾛｽｲﾝ出力が＋の場合、補正量を現在の設定押出量に－する。 / 粉砕ﾛｽｲﾝ出力が－の場合、補正量を現在の設定押出量に＋する。
LDNOT W60.01
ORNOT H98.06
AND H90.01
AND H2.13
ANDNOT 427.00
AND W203.05
OUT TR0
@BIN(023) D3240 D3241
AND W202.03
CLC(041)
@-C(412) 2042 D3241 2042
AND P_CY
MOV(021) #0 2042
LD TR0
AND W202.04
CLC(041)
@+C(402) 2042 D3241 2042
; rung 293: 押出機回転数設定上限規制
LD H90.01
AND H2.13
ANDNOT 427.00
AND W203.05
AND>(320) 2042 #FA0
MOV(021) #FA0 2042
; rung 294: ********** 接着外層ロスイン演算 ********** / ﾛｽｲﾝ補正量が±5%以内か判別(ﾛｽｲﾝ安定ﾗﾝﾌﾟ追加した為)
LD W203.02
AND H90.05
ANDNOT 427.00
AND 10.11
AND>(320) D175 #950
AND<(310) D175 #1050
OUT W60.08
; rung 295: 原料供給装置からの偏差信号が100.0%以上か判別しﾛｽｲﾝの割合を求める
LD W203.02
AND 10.11
AND W156.05
OUT W203.06

; rung 296
LD W203.06
OUT TR0
CMP(020) D175 #1000
LD P_GT
OR P_EQ
ANDLD
OUT W202.06
LD TR0
AND P_LT
OUT W202.07
LD TR0
AND W202.06
CLC(041)
@-BC(416) D175 #1000 D3214
LD TR0
AND W202.07
CLC(041)
@-BC(416) #1000 D175 D3214
; rung 297: 接外ﾛｽｲﾝ割合値が99.9%以上か判別(以上の場合は99.9%に丸込) / 接外設定押出量Q(画面)×偏差量ε
LD W203.06
OUT TR0
CMP(020) D3214 #999
AND P_GT
OUT W202.08
LD TR0
AND W202.08
@MOV(021) #999 D3214
LD TR0
@MOVD(083) D3214 #120 D3242
@*B(424) D2729 D3242 D3243

; rung 298: 接外補正量が10%以上か判別し10%以上の場合はﾛｽｲﾝ補正係数大(画面)を補正係数に。 / 10%未満の場合はﾛｽｲﾝ補正係数小(画面)を補正係数に。 / 今回5%未満
LD W203.06
OUT TR0
CMP(020) D3242 #500
LD P_GT
OR P_EQ
ANDLD
@MOV(021) D3208 D3293
LD TR0
AND P_LT
@MOV(021) D3202 D3293
; rung 299: ﾛｽｲﾝ指令値＝設定回転数／最大回転数×ﾛｽｲﾝ割合値×ﾛｽｲﾝ補正係数を求める
LD W203.06
@MOV(021) D2819 D3245
@MOV(021) #0 D3246
@/BL(435) D3243 D3245 D3246
@*B(424) D3246 D3293 D3250

; rung 300
LD W203.06
@MOVD(083) D3250 #3 D3252
@MOVD(083) D3251 #120 D3252
@SRD(075) D3252 D3252
@BIN(023) D3252 D3252
@ASL(025) D3252
@ASL(025) D3252
@BCD(024) D3252 D3252
AND<(310) D3252 #1
MOV(021) #1 D3252
; rung 301
LD W203.06
AND H98.08
AND<(310) D3242 D756
OUT W60.02

; rung 302: 接外ﾛｽｲﾝ出力が＋の場合、補正量を現在の設定押出量に－する。 / 接外ﾛｽｲﾝ出力が－の場合、補正量を現在の設定押出量に＋する。
LDNOT W60.02
ORNOT H98.08
AND H90.05
AND H2.13
ANDNOT 427.00
AND W203.06
OUT TR0
@BIN(023) D3252 D3253
AND W202.06
CLC(041)
@-C(412) 2046 D3253 2046
AND P_CY
MOV(021) #0 2046
LD TR0
AND W202.07
CLC(041)
@+C(402) 2046 D3253 2046
; rung 303: 押出機回転数設定上限規制
LD H90.05
AND H2.13
ANDNOT 427.00
AND W203.06
AND>(320) 2046 #FA0
MOV(021) #FA0 2046
; rung 304: ********** ﾊﾞﾘﾔ材層ロスイン演算 ********** / ﾛｽｲﾝ補正量が±5%以内か判別(ﾛｽｲﾝ安定ﾗﾝﾌﾟ追加した為)
LD W203.02
AND H90.03
ANDNOT 427.00
AND 10.09
AND>(320) D173 #950
AND<(310) D173 #1050
OUT W60.09
; rung 305: 原料供給装置からの偏差信号が100.0%以上か判別しﾛｽｲﾝの割合を求める
LD W203.02
AND 10.09
AND W156.03
OUT W203.07

; rung 306
LD W203.07
OUT TR0
CMP(020) D173 #1000
LD P_GT
OR P_EQ
ANDLD
OUT W202.09
LD TR0
AND P_LT
OUT W202.10
LD TR0
AND W202.09
CLC(041)
@-BC(416) D173 #1000 D3215
LD TR0
AND W202.10
CLC(041)
@-BC(416) #1000 D173 D3215
; rung 307: ﾊﾞﾘﾔﾛｽｲﾝ割合値が99.9%以上か判別(以上の場合は99.9%に丸込) / ﾊﾞﾘﾔ設定押出量Q(画面)×偏差量ε
LD W203.07
OUT TR0
CMP(020) D3215 #999
AND P_GT
OUT W202.11
LD TR0
AND W202.11
@MOV(021) #999 D3215
LD TR0
@MOVD(083) D3215 #120 D3254
@*B(424) D2730 D3254 D3255

; rung 308: ﾊﾞﾘﾔ補正量が10%以上か判別し10%以上の場合はﾛｽｲﾝ補正係数大(画面)を補正係数に。 / 10%未満の場合はﾛｽｲﾝ補正係数小(画面)を補正係数に。 / 今回5%未満
LD W203.07
OUT TR0
CMP(020) D3254 #500
LD P_GT
OR P_EQ
ANDLD
@MOV(021) D3209 D3294
LD TR0
AND P_LT
@MOV(021) D3203 D3294
; rung 309: ﾛｽｲﾝ指令値＝設定回転数／最大回転数×ﾛｽｲﾝ割合値×ﾛｽｲﾝ補正係数を求める
LD W203.07
@MOV(021) D2835 D3257
@MOV(021) #0 D3258
@/BL(435) D3255 D3257 D3258
@*B(424) D3258 D3294 D3262

; rung 310
LD W203.07
@MOVD(083) D3262 #3 D3264
@MOVD(083) D3263 #120 D3264
@SRD(075) D3264 D3264
@BIN(023) D3264 D3264
@ASL(025) D3264
@ASL(025) D3264
@BCD(024) D3264 D3264
AND<(310) D3264 #1
MOV(021) #1 D3264
; rung 311
LD W203.07
AND H98.09
AND<(310) D3254 D757
OUT W60.03

; rung 312: ﾊﾞﾘﾔﾛｽｲﾝ出力が＋の場合、補正量を現在の設定押出量に－する。 / ﾊﾞﾘﾔﾛｽｲﾝ出力が－の場合、補正量を現在の設定押出量に＋する。
LDNOT W60.03
ORNOT H98.09
AND H90.03
AND H2.13
ANDNOT 427.00
AND W203.07
OUT TR0
@BIN(023) D3264 D3265
AND W202.09
CLC(041)
@-C(412) 2044 D3265 2044
AND P_CY
MOV(021) #0 2044
LD TR0
AND W202.10
CLC(041)
@+C(402) 2044 D3265 2044
; rung 313: 押出機回転数設定上限規制
LD H90.03
AND H2.13
ANDNOT 427.00
AND W203.07
AND>(320) 2044 #FA0
MOV(021) #FA0 2044
; rung 314: ********** 接着内層ロスイン演算 ********** / ﾛｽｲﾝ補正量が±5%以内か判別(ﾛｽｲﾝ安定ﾗﾝﾌﾟ追加した為)
LD W203.02
AND H90.04
ANDNOT 427.00
AND 10.10
AND>(320) D174 #950
AND<(310) D174 #1050
OUT W60.10
; rung 315: 原料供給装置からの偏差信号が100.0%以上か判別しﾛｽｲﾝの割合を求める
LD W203.02
AND 10.10
AND W156.04
OUT W203.08

; rung 316
LD W203.08
OUT TR0
CMP(020) D174 #1000
LD P_GT
OR P_EQ
ANDLD
OUT W202.12
LD TR0
AND P_LT
OUT W202.13
LD TR0
AND W202.12
CLC(041)
@-BC(416) D174 #1000 D3216
LD TR0
AND W202.13
CLC(041)
@-BC(416) #1000 D174 D3216
; rung 317: 接内ﾛｽｲﾝ割合値が99.9%以上か判別(以上の場合は99.9%に丸込) / 接内設定押出量Q(画面)×偏差量ε
LD W203.08
OUT TR0
CMP(020) D3216 #999
AND P_GT
OUT W202.14
LD TR0
AND W202.14
@MOV(021) #999 D3216
LD TR0
@MOVD(083) D3216 #120 D3266
@*B(424) D2731 D3266 D3267

; rung 318: 接内補正量が10%以上か判別し10%以上の場合はﾛｽｲﾝ補正係数大(画面)を補正係数に。 / 10%未満の場合はﾛｽｲﾝ補正係数小(画面)を補正係数に。 / 今回5%未満
LD W203.08
OUT TR0
CMP(020) D3266 #500
LD P_GT
OR P_EQ
ANDLD
@MOV(021) D3210 D3295
LD TR0
AND P_LT
@MOV(021) D3204 D3295
; rung 319: ﾛｽｲﾝ指令値＝設定回転数／最大回転数×ﾛｽｲﾝ割合値×ﾛｽｲﾝ補正係数を求める
LD W203.08
@MOV(021) D2851 D3269
@MOV(021) #0 D3270
@/BL(435) D3267 D3269 D3270
@*B(424) D3270 D3295 D3274

; rung 320
LD W203.08
@MOVD(083) D3274 #3 D3276
@MOVD(083) D3275 #120 D3276
@SRD(075) D3276 D3276
@BIN(023) D3276 D3276
@ASL(025) D3276
@ASL(025) D3276
@BCD(024) D3276 D3276
AND<(310) D3276 #1
MOV(021) #1 D3276
; rung 321
LD W203.08
AND H98.10
AND<(310) D3266 D758
OUT W60.04

; rung 322: 接内ﾛｽｲﾝ出力が＋の場合、補正量を現在の設定押出量に－する。 / 接内ﾛｽｲﾝ出力が－の場合、補正量を現在の設定押出量に＋する。
LDNOT W60.04
ORNOT H98.10
AND H90.04
AND H2.13
ANDNOT 427.00
AND W203.08
OUT TR0
@BIN(023) D3276 D3277
AND W202.12
CLC(041)
@-C(412) 2045 D3277 2045
AND P_CY
MOV(021) #0 2045
LD TR0
AND W202.13
CLC(041)
@+C(402) 2045 D3277 2045
; rung 323: 押出機回転数設定上限規制
LD H90.04
AND H2.13
ANDNOT 427.00
AND W203.08
AND>(320) 2045 #FA0
MOV(021) #FA0 2045
; rung 324: ********** 主材内層ロスイン演算 ********** / ﾛｽｲﾝ補正量が±5%以内か判別(ﾛｽｲﾝ安定ﾗﾝﾌﾟ追加した為)
LD W203.02
AND H90.00
ANDNOT 427.00
AND 10.06
AND>(320) D170 #950
AND<(310) D170 #1050
OUT W60.11
; rung 325: 原料供給装置からの偏差信号が100.0%以上か判別しﾛｽｲﾝの割合を求める
LD W203.02
AND 10.06
AND W156.00
OUT W203.09

; rung 326
LD W203.09
OUT TR0
CMP(020) D170 #1000
LD P_GT
OR P_EQ
ANDLD
OUT W202.15
LD TR0
AND P_LT
OUT W203.00
LD TR0
AND W202.15
CLC(041)
@-BC(416) D170 #1000 D3217
LD TR0
AND W203.00
CLC(041)
@-BC(416) #1000 D170 D3217
; rung 327: 主内ﾛｽｲﾝ割合値が99.9%以上か判別(以上の場合は99.9%に丸込) / 主内設定押出量Q(画面)×偏差量ε
LD W203.09
OUT TR0
CMP(020) D3217 #999
AND P_GT
OUT W203.01
LD TR0
AND W203.01
@MOV(021) #999 D3217
LD TR0
@MOVD(083) D3217 #120 D3278
@*B(424) D2732 D3278 D3279

; rung 328: 主内補正量が10%以上か判別し10%以上の場合はﾛｽｲﾝ補正係数大(画面)を補正係数に。 / 10%未満の場合はﾛｽｲﾝ補正係数小(画面)を補正係数に。 / 今回5%未満
LD W203.09
OUT TR0
CMP(020) D3278 #500
LD P_GT
OR P_EQ
ANDLD
@MOV(021) D3211 D3296
LD TR0
AND P_LT
@MOV(021) D3205 D3296
; rung 329: ﾛｽｲﾝ指令値＝設定回転数／最大回転数×ﾛｽｲﾝ割合値×ﾛｽｲﾝ補正係数を求める
LD W203.09
@MOV(021) D2867 D3281
@MOV(021) #0 D3282
@/BL(435) D3279 D3281 D3282
@*B(424) D3282 D3296 D3286

; rung 330
LD W203.09
@MOVD(083) D3286 #3 D3288
@MOVD(083) D3287 #120 D3288
@SRD(075) D3288 D3288
@BIN(023) D3288 D3288
@ASL(025) D3288
@ASL(025) D3288
@BCD(024) D3288 D3288
AND<(310) D3288 #1
MOV(021) #1 D3288
; rung 331
LD W203.09
AND H98.11
AND<(310) D3278 D759
OUT W60.05

; rung 332: 主内ﾛｽｲﾝ出力が＋の場合、補正量を現在の設定押出量に－する。 / 主内ﾛｽｲﾝ出力が－の場合、補正量を現在の設定押出量に＋する。
LDNOT W60.05
ORNOT H98.11
AND H90.00
AND H2.13
ANDNOT 427.00
AND W203.09
OUT TR0
@BIN(023) D3288 D3289
AND W202.15
CLC(041)
@-C(412) 2041 D3289 2041
AND P_CY
MOV(021) #0 2041
LD TR0
AND W203.00
CLC(041)
@+C(402) 2041 D3289 2041
; rung 333: 押出機回転数設定上限規制
LD H90.00
AND H2.13
ANDNOT 427.00
AND W203.09
AND>(320) 2041 #FA0
MOV(021) #FA0 2041
; rung 334: ********** 原料供給装置からの押出量実測値を転送(押出機運転ﾓﾆﾀ画面に表示) ********** / 原料供給装置をやめてＪＳＷ内にて処理変更
LD P_On
MOV(021) D178 D3412
MOV(021) D177 D3413
MOV(021) D181 D3414
MOV(021) D179 D3415
MOV(021) D180 D3416
MOV(021) D176 D3417

; rung 335: ********** 原料供給装置からのロスイン補正量転送(押出機運転ﾓﾆﾀ画面に表示) ********** / 原料供給装置をやめてＪＳＷ内にて処理変更
LD P_On
MOV(021) D172 D3418
MOV(021) D171 D3419
MOV(021) D175 D3420
MOV(021) D173 D3421
MOV(021) D174 D3422
MOV(021) D170 D3423
; rung 336: ********** 主材外層押出機回転数(押出機運転モニタ設定速度の表示) **********  この値を原料供給装置へ / 定数はDA出力BCD 4000で回転数を除算した値 / DA出力BCD 1当たりの回転数 / 最高回転数59.24rpm / DA設定値から設定速度を求めているのでｼｬｯﾄﾀﾞｳﾝ/ﾊﾟｰｼﾞ/低押出時の設定速度と誤差が出る時がある。(0.1rpm)
LDNOT W63.02
BCD(024) 2043 D3300
*B(424) D3300 D744 D386
MOV(021) D387 D3430
; rung 337
LD W63.02
@MOV(021) #0 D3430
MOVD(083) D2735 #21 D3430

; rung 338: ********** 粉砕材層押出機回転数(押出機運転モニタ設定速度の表示) **********  この値を原料供給装置へ / 定数はDA出力BCD 4000で回転数を除算した値 / 最高回転数49.09rpm / DA設定値から設定速度を求めているのでｼｬｯﾄﾀﾞｳﾝ/ﾊﾟｰｼﾞ/低押出時の設定速度と誤差が出る時がある。(0.1rpm)
LDNOT W63.01
BCD(024) 2042 D3301
*B(424) D3301 D743 D384
MOV(021) D385 D3431
; rung 339
LD W63.01
@MOV(021) #0 D3431
MOVD(083) D2734 #21 D3431
; rung 340: ********** 接着外層押出機回転数(押出機運転モニタ設定速度の表示) **********  この値を原料供給装置へ / 定数はDA出力BCD 4000で回転数を除算した値 / 最高回転数91.15rpm / DA設定値から設定速度を求めているのでｼｬｯﾄﾀﾞｳﾝ/ﾊﾟｰｼﾞ/低押出時の設定速度と誤差が出る時がある。(0.1rpm)
LDNOT W63.05
BCD(024) 2046 D3302
*B(424) D3302 D747 D392
MOV(021) D393 D3432
; rung 341
LD W63.05
@MOV(021) #0 D3432
MOVD(083) D2738 #21 D3432

; rung 342: ********** バリヤ層押出機回転数(押出機運転モニタ設定速度の表示) **********  この値を原料供給装置へ / 定数はDA出力BCD 4000で回転数を除算した値 / 最高回転数82.64rpm / DA設定値から設定速度を求めているのでｼｬｯﾄﾀﾞｳﾝ/ﾊﾟｰｼﾞ/低押出時の設定速度と誤差が出る時がある。(0.1rpm)
LDNOT W63.03
BCD(024) 2044 D3303
*B(424) D3303 D745 D388
MOV(021) D389 D3433
; rung 343
LD W63.03
@MOV(021) #0 D3433
MOVD(083) D2736 #21 D3433
; rung 344: ********** 接着内層押出機回転数(押出機運転モニタ設定速度の表示) **********  この値を原料供給装置へ / 定数はDA出力BCD 4000で回転数を除算した値 / 最高回転数91.15rpm / DA設定値から設定速度を求めているのでｼｬｯﾄﾀﾞｳﾝ/ﾊﾟｰｼﾞ/低押出時の設定速度と誤差が出る時がある。(0.1rpm)
LDNOT W63.04
BCD(024) 2045 D3304
*B(424) D3304 D746 D390
MOV(021) D391 D3434
; rung 345
LD W63.04
@MOV(021) #0 D3434
MOVD(083) D2737 #21 D3434

; rung 346: ********** 主材内層押出機回転数(押出機運転モニタ設定速度の表示) **********  この値を原料供給装置へ / 定数はDA出力BCD 4000で回転数を除算した値 / 最高回転数62.37rpm / DA設定値から設定速度を求めているのでｼｬｯﾄﾀﾞｳﾝ/ﾊﾟｰｼﾞ/低押出時の設定速度と誤差が出る時がある。(0.1rpm)
LDNOT W63.00
BCD(024) 2041 D3305
*B(424) D3305 D742 D382
MOV(021) D383 D3435
; rung 347
LD W63.00
@MOV(021) #0 D3435
MOVD(083) D2733 #21 D3435
; rung 348: ********** 全設定押出量及び全実押出量計算処理 ********** / 全実押出量の計算は各層の実押出量を加算した総和。(実押出量は原料供給装置より来る) / ﾃﾞｰﾀの桁上がりがあるので加算は２ﾜｰﾄﾞ処理。今回実押出量桁同一
LD P_On
MOVD(083) D2756 #210 D3365
MOVD(083) D2756 #12 D3366

; rung 349: '主材内層実押出量＋粉砕材層実押出量
LD P_On
MOV(021) D3417 D3367
MOV(021) #0 D3368
MOV(021) D3413 D3369
MOV(021) #0 D3370
CLC(041)
+BCL(407) D3367 D3369 D3371
; rung 350: （主材内層実押出量＋粉砕材層実押出量）＋主材外層実押出量
LD P_On
MOV(021) D3371 D3367
MOV(021) D3372 D3368
MOV(021) D3412 D3369
MOV(021) #0 D3370
CLC(041)
+BCL(407) D3367 D3369 D3371

; rung 351: 999.9を999.90に変更する処理
LD P_On
MOVD(083) D3372 #100 D3372
MOVD(083) D3371 #3 D3372
MOVD(083) D3371 #120 D3371
MOVD(083) #0 #0 D3371
; rung 352: 接着外層実押出量＋ﾊﾞﾘﾔ材層実押出量
LD P_On
MOV(021) D3414 D3373
MOV(021) #0 D3374
MOV(021) D3415 D3375
MOV(021) #0 D3376
CLC(041)
+BCL(407) D3373 D3375 D3377

; rung 353: 接着外層実押出量＋ﾊﾞﾘﾔ材層実押出量＋接着内層実押出量
LD P_On
MOV(021) D3377 D3373
MOV(021) D3378 D3374
MOV(021) D3416 D3375
MOV(021) #0 D3376
CLC(041)
+BCL(407) D3373 D3375 D3377
; rung 354: 全実押出量＝各実押出量の総和
LD P_On
CLC(041)
+BCL(407) D3371 D3377 D3379
; rung 355: ********** 実押出量許容範囲内判別 ********** / 実押出量が設定押出量の設定範囲に入っているか確認 / 範囲上限及び範囲下限は自己保持せず、警報画面の表示のみ自己保持
LD W378.00
AND W379.05
ANDNOT W509.15
DIFU(013) W207.13
; rung 356
LD H2.09
DIFU(013) W207.14
; rung 357
LD W379.04
AND W378.10
LD W379.05
AND W378.01
ORLD
ANDNOT W509.15
OR W207.13
OR W207.14
OR T0152
OR W163.13
OUT W206.08

; rung 358
LD 401.10
ANDNOT 406.02
OUT W158.09
; rung 359: ---------- 主材内層実押出量許容範囲判別 ----------
LD H80.02
AND>(320) #3 D3670
MOV(021) #3 D3670
; rung 360
LD W206.08
CLC(041)
+BC(406) #100 D3670 D3503
CLC(041)
-BC(416) #100 D3670 D3504
; rung 361
LD W206.08
*B(424) D2732 D3503 D3505
MOVD(083) D3505 #12 D3676
MOVD(083) D3506 #210 D3676
AND>=(325) D3506 #100
MOV(021) #9999 D3676

; rung 362
LD W206.08
*B(424) D2732 D3504 D3505
MOVD(083) D3505 #12 D3677
MOVD(083) D3506 #210 D3677
; rung 363
LD H80.02
AND W158.09
OUT TR0
AND>(320) D3417 D3676
OUT W207.00
LD TR0
AND<(310) D3417 D3677
OUT W207.01
; rung 364
LD W207.00
OR W207.01
OUT W216.00
; rung 365: ---------- 粉砕材層実押出量許容範囲判別 ----------
LD H80.03
AND>(320) #3 D3671
MOV(021) #3 D3671
; rung 366
LD W206.08
CLC(041)
+BC(406) #100 D3671 D3503
CLC(041)
-BC(416) #100 D3671 D3504

; rung 367
LD W206.08
*B(424) D2728 D3503 D3505
MOVD(083) D3505 #12 D3678
MOVD(083) D3506 #210 D3678
AND>=(325) D3506 #100
MOV(021) #9999 D3678
; rung 368
LD W206.08
*B(424) D2728 D3504 D3505
MOVD(083) D3505 #12 D3679
MOVD(083) D3506 #210 D3679
; rung 369
LD H80.03
AND W158.09
OUT TR0
AND>(320) D3413 D3678
OUT W207.02
LD TR0
AND<(310) D3413 D3679
OUT W207.03
; rung 370
LD W207.02
OR W207.03
OUT W216.01
; rung 371: ---------- 主材外層実押出量許容範囲判別 ----------
LD H80.04
AND>(320) #3 D3672
MOV(021) #3 D3672

; rung 372
LD W206.08
CLC(041)
+BC(406) #100 D3672 D3503
CLC(041)
-BC(416) #100 D3672 D3504
; rung 373
LD W206.08
*B(424) D2727 D3503 D3505
MOVD(083) D3505 #12 D3680
MOVD(083) D3506 #210 D3680
AND>=(325) D3506 #100
MOV(021) #9999 D3680
; rung 374
LD W206.08
*B(424) D2727 D3504 D3505
MOVD(083) D3505 #12 D3681
MOVD(083) D3506 #210 D3681
; rung 375
LD H80.04
AND W158.09
OUT TR0
AND>(320) D3412 D3680
OUT W207.04
LD TR0
AND<(310) D3412 D3681
OUT W207.05

; rung 376
LD W207.04
OR W207.05
OUT W216.02
; rung 377: ---------- ﾊﾞﾘﾔ材層実押出量許容範囲判別 ----------
LD H80.05
AND>(320) #3 D3673
MOV(021) #3 D3673
; rung 378
LD W206.08
CLC(041)
+BC(406) #100 D3673 D3503
CLC(041)
-BC(416) #100 D3673 D3504
; rung 379
LD W206.08
*B(424) D2730 D3503 D3505
MOVD(083) D3505 #12 D3682
MOVD(083) D3506 #210 D3682
AND>=(325) D3506 #100
MOV(021) #9999 D3682

; rung 380
LD W206.08
*B(424) D2730 D3504 D3505
MOVD(083) D3505 #12 D3683
MOVD(083) D3506 #210 D3683
; rung 381
LD H80.05
AND W158.09
OUT TR0
AND>(320) D3415 D3682
OUT W207.06
LD TR0
AND<(310) D3415 D3683
OUT W207.07
; rung 382
LD W207.06
OR W207.07
OUT W216.03
; rung 383: ---------- 接着内層層実押出量許容範囲判別 ----------
LD H80.06
AND>(320) #3 D3674
MOV(021) #3 D3674
; rung 384
LD W206.08
CLC(041)
+BC(406) #100 D3674 D3503
CLC(041)
-BC(416) #100 D3674 D3504

; rung 385
LD W206.08
*B(424) D2731 D3503 D3505
MOVD(083) D3505 #12 D3684
MOVD(083) D3506 #210 D3684
AND>=(325) D3506 #100
MOV(021) #9999 D3684
; rung 386
LD W206.08
*B(424) D2731 D3504 D3505
MOVD(083) D3505 #12 D3685
MOVD(083) D3506 #210 D3685
; rung 387
LD H80.06
AND W158.09
OUT TR0
AND>(320) D3416 D3684
OUT W207.08
LD TR0
AND<(310) D3416 D3685
OUT W207.09
; rung 388
LD W207.08
OR W207.09
OUT W216.04
; rung 389: ---------- 接着外層層実押出量許容範囲判別 ----------
LD H80.07
AND>(320) #3 D3675
MOV(021) #3 D3675

; rung 390
LD W206.08
CLC(041)
+BC(406) #100 D3675 D3503
CLC(041)
-BC(416) #100 D3675 D3504
; rung 391
LD W206.08
*B(424) D2729 D3503 D3505
MOVD(083) D3505 #12 D3686
MOVD(083) D3506 #210 D3686
AND>=(325) D3506 #100
MOV(021) #9999 D3686
; rung 392
LD W206.08
*B(424) D2729 D3504 D3505
MOVD(083) D3505 #12 D3687
MOVD(083) D3506 #210 D3687
; rung 393
LD H80.07
AND W158.09
OUT TR0
AND>(320) D3414 D3686
OUT W207.10
LD TR0
AND<(310) D3414 D3687
OUT W207.11

; rung 394
LD W207.10
OR W207.11
OUT W216.05
; rung 395
LD H80.01
AND H80.02
AND H80.03
AND H80.04
AND H80.05
AND H80.06
AND H80.07
OUTNOT H80.08
; rung 396: ---------- 全実押出量判別処理 ----------
LD H80.01
CMP(020) #0 D273
AND P_EQ
MOV(021) #3 D273
; rung 397
LD W206.08
CLC(041)
+BC(406) #100 D273 D251
CLC(041)
-BC(416) #100 D273 D252
; rung 398
LD W206.08
MOVD(083) D3365 #12 D253
MOVD(083) D3366 #210 D253
; rung 399
LD W206.08
*B(424) D253 D251 D254
*B(424) D253 D252 D256

; rung 400
LD H80.01
AND W158.09
CMPL(060) D3379 D254
AND P_GT
OUT W398.10
; rung 401
LD H80.01
AND W158.09
CMPL(060) D3379 D256
AND P_LT
OUT W398.11
; rung 402: ----- 全設定押出量が範囲外か判別 -----
LD P_On
CMPL(060) D3365 D294
AND P_GT
OUT W398.09
; rung 403: ********** シャットダウン(ﾊﾟｰｼﾞ)処理 **********
LDNOT W509.15
AND W379.05
OUT TR0
AND W378.14
OUT W203.12
LD TR0
AND W378.13
OUT W204.07
; rung 404: --- ｼｬｯﾄﾀﾞｳﾝ押出機回転数設定範囲確認 --- / 最高回転数より大きい値を設定した場合、強制的に最高回転数を設定する。
LD W203.12
OUT TR0
AND>(320) D2917 D730
MOV(021) D730 D2917
LD TR0
AND>(320) D348 D730
MOV(021) D730 D348
LD TR0
AND>(320) D2910 D731
MOV(021) D731 D2910
LD TR0
AND>(320) D2913 D731
MOV(021) D731 D2913

; rung 405
LD W203.12
OUT TR0
AND>(320) D2912 D732
MOV(021) D732 D2912
LD TR0
AND>(320) D349 D732
MOV(021) D732 D349
LD TR0
AND>(320) D2911 D733
MOV(021) D733 D2911
LD TR0
AND>(320) D2915 D733
MOV(021) D733 D2915
; rung 406
LD W203.12
OUT TR0
AND>(320) D2916 D734
MOV(021) D734 D2916
LD TR0
AND>(320) D2914 D735
MOV(021) D735 D2914
; rung 407: ----- パージ時　主材外層押出機回転数データ変換処理 ----- / Max回転数 → 4000
LDNOT W201.04
MOV(021) #0 D3149
; rung 408
LD W201.04
ANDNOT W200.11
BIN(023) D2912 D3149
; rung 409
LD W201.04
AND W200.11
BIN(023) D349 D3149
; rung 410
LD P_On
SCL(194) D3149 D300 D3150
BIN(023) D3150 D3151

; rung 411: ----- パージ時　粉砕材層押出機回転数設定データ変換処理 ----- / Max回転数 → 4000
LDNOT W201.04
ANDNOT W201.07
MOV(021) #0 D3156
; rung 412
LD W201.04
ANDNOT W201.07
BIN(023) D2910 D3156
; rung 413
LD W201.04
AND W201.07
BIN(023) D2913 D3156
; rung 414
LD P_On
SCL(194) D3156 D307 D3157
BIN(023) D3157 D3158
; rung 415: ----- パージ時　接着外層押出機回転数データ変換処理 ----- / Max回転数 → 4000 / 計量ﾎｯﾊﾟﾀﾞﾝﾊﾟ閉を確認してから低速回転
LDNOT W201.04
LD W201.04
ANDNOT T0507
ORLD
MOV(021) #0 D3163
; rung 416
LD W201.04
AND T0507
BIN(023) D2914 D3163
; rung 417
LD P_On
SCL(194) D3163 D314 D3164
BIN(023) D3164 D3165

; rung 418: ----- パージ時　バリヤ層押出機回転数データ変換処理 ----- / Max回転数 → 4000
LDNOT W201.04
ANDNOT W201.10
MOV(021) #0 D3170
; rung 419
LD W201.04
ANDNOT W201.10
BIN(023) D2911 D3170
; rung 420
LD W201.04
AND W201.10
BIN(023) D2915 D3170
; rung 421
LD P_On
SCL(194) D3170 D321 D3171
BIN(023) D3171 D3172
; rung 422: ----- パージ時　接着内層押出機回転数変換データ処理 ----- / Max回転数 → 4000 / 計量ﾎｯﾊﾟﾀﾞﾝﾊﾟ閉を確認してから低速回転
LDNOT W201.04
LD W201.04
ANDNOT T0508
ORLD
MOV(021) #0 D3177
; rung 423
LD W201.04
AND T0508
BIN(023) D2916 D3177
; rung 424
LD P_On
SCL(194) D3177 D328 D3178
BIN(023) D3178 D3179

; rung 425: ----- パージ時　主材内層押出機回転数データ変換処理 ----- / Max回転数 → 4000
LDNOT W201.04
MOV(021) #0 D3184
; rung 426
LD W201.04
ANDNOT W200.11
BIN(023) D2917 D3184
; rung 427
LD W201.04
AND W200.11
BIN(023) D348 D3184
; rung 428
LD P_On
SCL(194) D3184 D335 D3185
BIN(023) D3185 D3186
; rung 429: ----- パージ開始 ----- / Ｙを基にしているので供給装置との受渡接点を生かし、その接点を制御する / 操作ﾛｰｶﾙ接点追加 / ﾊﾟｰｼﾞ押釦３秒ONでﾊﾟｰｼﾞ開始追加
LD 2054.09
TIM 0504 #30
; rung 430
LD W208.06
AND T0504
ANDNOT H80.14
ANDNOT H2.14
OR 427.00
ANDNOT H2.06
ANDNOT H2.07
ANDNOT W203.13
ANDNOT 17.10
AND H2.09
AND 2054.04
OUT 427.00
; rung 431
LD W208.06
AND T0504
AND H80.14
ANDNOT H2.14
OR W204.00
ANDNOT H2.06
ANDNOT H2.07
ANDNOT W203.13
ANDNOT 17.10
AND H2.09
AND 2054.04
ANDNOT W63.15
OUT W204.00
; rung 432
LD W204.00
AND P_1s
OR W73.14
OUT 2050.09
; rung 433
LD H80.14
AND P_Off
OUT 427.06

; rung 434
LD 5.11
OR T0505
AND 427.00
TIM 0505 #10
; rung 435
LD 5.07
OR T0506
AND 427.00
TIM 0506 #10
; rung 436
LD 5.15
OR T0507
AND 427.00
TIM 0507 #10
; rung 437
LD 5.13
OR T0508
AND 427.00
TIM 0508 #10
; rung 438
LD T0505
OUT W81.07
; rung 439
LD T0506
OUT W81.08
; rung 440
LD T0507
OUT W82.00
; rung 441
LD T0508
OUT W82.01
; rung 442
LD W81.07
OR W81.08
AND 427.00
OUT TR0
OUT W201.04
AND W81.08
OUT 427.02
LD TR0
AND W81.07
OUT 427.01

; rung 443
LD W201.04
MOV(021) D3151 2043
MOV(021) D3165 2046
MOV(021) D3179 2045
MOV(021) D3186 2041
; rung 444
LD 427.02
ANDNOT W201.07
OR W201.07
AND W201.04
MOV(021) D3158 2042
; rung 445
LD 427.01
ANDNOT W201.10
OR W201.10
AND W201.04
MOV(021) D3172 2044
; rung 446
LD W379.02
LD W378.13
OR W378.14
ANDLD
ANDNOT W509.15
OUT TR0
LD W64.05
OR W66.05
ANDLD
ANDNOT H94.02
ANDNOT W64.04
OUT W66.05
LD TR0
LD W66.05
AND P_0_2s
OR H94.02
ANDLD
OUT W65.05
LD TR0
LD W64.04
OR W66.04
ANDLD
AND H94.02
ANDNOT W64.05
OUT W66.04
LD TR0
LD W66.04
AND P_0_2s
ORNOT H94.02
ANDLD
OUT W65.04
; rung 447
LD W66.05
AND W363.05
OR H94.02
LDNOT W66.04
ORNOT W363.05
ANDLD
OUT H94.02

; rung 448
LD W379.02
LD W378.13
OR W378.14
ANDLD
ANDNOT W509.15
OUT TR0
LD W64.01
OR W66.01
ANDLD
ANDNOT H94.00
ANDNOT W64.00
OUT W66.01
LD TR0
LD W66.01
AND P_0_2s
OR H94.00
ANDLD
OUT W65.01
LD TR0
LD W64.00
OR W66.00
ANDLD
AND H94.00
ANDNOT W64.01
OUT W66.00
LD TR0
LD W66.00
AND P_0_2s
ORNOT H94.00
ANDLD
OUT W65.00
; rung 449
LD W66.01
AND W363.05
OR H94.00
LDNOT W66.00
ORNOT W363.05
ANDLD
OUT H94.00
; rung 450
LD W379.02
LD W378.13
OR W378.14
ANDLD
ANDNOT W509.15
OUT TR0
LD W64.03
OR W66.03
ANDLD
ANDNOT H94.01
ANDNOT W64.02
OUT W66.03
LD TR0
LD W66.03
AND P_0_2s
OR H94.01
ANDLD
OUT W65.03
LD TR0
LD W64.02
OR W66.02
ANDLD
AND H94.01
ANDNOT W64.03
OUT W66.02
LD TR0
LD W66.02
AND P_0_2s
ORNOT H94.01
ANDLD
OUT W65.02
; rung 451
LD W66.03
AND W363.05
OR H94.01
LDNOT W66.02
ORNOT W363.05
ANDLD
OUT H94.01
; rung 452
LD W209.00
TIM 0014 #30
; rung 453
LD 427.00
AND H94.00
OUT 422.06

; rung 454
LDNOT 446.03
OUT 422.09
; rung 455
LD 427.00
AND H94.01
OR 422.08
ANDNOT 426.10
OUT 422.08
; rung 456
LD W203.10
AND T0015
OUT TR0
ANDNOT 446.03
OUT 422.07
LD TR0
ANDNOT 446.06
AND T0014
OUT 426.10
; rung 457
LD W84.07
OR T0509
AND 427.02
TIM 0509 #100
; rung 458
LD T0509
OR 422.06
OUT TR0
ANDNOT H94.00
OUT W81.10
LD TR0
OUT 426.13
AND H94.00
OUT W81.05
; rung 459
LD 427.02
LD W81.10
OR W81.05
ANDLD
AND<=(315) D5963 D3443
TIM 0270 #30
; rung 460
LD T0270
OR W201.05
AND 427.02
LD W81.10
OR W81.05
ANDLD
OUT W201.05
; rung 461
LD W201.05
AND<=(315) D3425 D3449
TIM 0271 #30
; rung 462
LD T0271
OR W201.06
AND W201.05
OUT W201.06
OUT W201.07

; rung 463
LD W84.15
OR T0510
AND 427.01
TIM 0510 #100
; rung 464
LD T0510
OR 422.08
OUT TR0
ANDNOT H94.01
OUT W81.09
LD TR0
OUT 426.12
AND H94.01
OUT W81.06
; rung 465
LD 427.01
LD W81.09
OR W81.06
ANDLD
AND<=(315) D5965 D3445
TIM 0272 #30
; rung 466
LD T0272
OR W201.08
AND 427.01
LD W81.09
OR W81.06
ANDLD
OUT W201.08
; rung 467
LD W201.08
AND<=(315) D3427 D3451
TIM 0273 #30
; rung 468
LD T0273
OR W201.09
AND W201.08
OUT W201.09
OUT W201.10
; rung 469
LD W201.09
OUT 427.03
ANDNOT 427.05
LDNOT 427.00
LD H3.15
OR W291.08
ANDLD
ANDNOT H3.09
AND H3.13
ORLD
OUT 426.14
; rung 470
LD W201.06
OUT 427.04
ANDNOT 427.05
LDNOT 427.00
LD H3.15
OR W291.08
ANDLD
ANDNOT H3.07
AND H3.14
ORLD
OUT 426.15

; rung 471
LD 426.14
AND 413.08
OR W82.05
ANDNOT W203.13
AND 427.00
OUT W82.05
; rung 472
LD 426.15
AND 413.10
OR W82.06
ANDNOT W203.13
AND 427.00
OUT W82.06
; rung 473
LD 426.14
AND 413.08
AND 426.15
AND 413.10
OR W81.11
ANDNOT W203.13
AND 427.00
OUT W81.11
; rung 474
LD 426.14
ANDNOT 413.08
ANDNOT 427.05
LD T0478
ANDNOT W227.02
ORLD
AND 427.00
TIM 0478 #30
; rung 475
LD 426.15
ANDNOT 413.10
ANDNOT 427.05
LD T0479
ANDNOT W227.02
ORLD
AND 427.00
TIM 0479 #30
; rung 476
LDNOT P_On
OUT TR0
AND P_1s
AND W81.12
LD TR0
LD C0274
OR P_First_Cycle
ANDLD
CNT 0274 #60

; rung 477
LDNOT P_On
AND W81.12
OUT TR0
AND C0274
ANDNOT W201.12
@++B(594) D3187
LD TR0
CMP(020) D3187 D2918
LD P_EQ
OR P_GT
OR W201.12
ANDLD
OUT W201.12
MOV(021) D2918 D3187
LD TR0
CMP(020) D2918 D3188
ANDNOT P_EQ
MOV(021) #0 D3187
LD TR0
MOV(021) D2918 D3188
; rung 478
LDNOT P_On
ANDNOT W81.12
MOV(021) #0 D3187
; rung 479
LD P_1s
AND W81.11
LD C0275
OR P_First_Cycle
CNT 0275 #60

; rung 480
LD W81.11
OUT TR0
AND C0275
ANDNOT W201.13
@++B(594) D3189
LD TR0
CMP(020) D3189 D2919
LD P_EQ
OR P_GT
OR W201.13
ANDLD
OUT W201.13
MOV(021) D2919 D3189
LD TR0
CMP(020) D2919 D3190
ANDNOT P_EQ
MOV(021) #0 D3189
LD TR0
MOV(021) D2919 D3190
; rung 481
LDNOT W81.10
ANDNOT W81.05
MOV(021) #0 D3189
; rung 482
LD W201.12
OR P_On
AND W81.11
AND W201.13
OR 427.05
ANDNOT W203.13
AND 427.00
OUT 427.05
; rung 483
LD 5.05
OR W156.14
AND 427.05
OUT W156.14
; rung 484
LD 5.09
OR W156.15
AND 427.05
OUT W156.15
; rung 485
LD 427.05
AND 413.09
AND 413.11
AND 5.05
AND 5.07
AND 5.09
AND 5.11
AND 5.13
AND 5.15
OR W81.13
ANDNOT W203.13
AND 427.00
OUT W81.13

; rung 486
LD 427.05
ANDNOT 426.14
ANDNOT 413.09
LD T0468
ANDNOT W227.02
ORLD
AND 427.00
TIM 0468 #30
; rung 487
LD 427.05
ANDNOT 426.15
ANDNOT 413.11
LD T0469
ANDNOT W227.02
ORLD
AND 427.00
TIM 0469 #30
; rung 488
LD 427.05
AND W81.13
OUT W200.11
; rung 489
LD P_1s
AND W200.11
LD C0304
OR P_First_Cycle
CNT 0304 #60
; rung 490
LD W200.11
OUT TR0
AND C0304
ANDNOT W510.14
@++B(594) D289
LD TR0
CMP(020) D289 D288
LD P_EQ
OR P_GT
OR W510.14
ANDLD
OUT W510.14
MOV(021) D288 D289
LD TR0
CMP(020) D288 D298
ANDNOT P_EQ
MOV(021) #0 D289
LD TR0
MOV(021) D288 D298
; rung 491
LDNOT W200.11
MOV(021) #0 D289

; rung 492
LD W510.14
AND W200.11
AND<=(315) D5964 D3442
TIM 0276 #30
; rung 493
LD T0276
OR W200.12
AND W200.11
AND W510.14
OUT W200.12
; rung 494
LD W200.12
AND<=(315) D3424 D3448
TIM 0277 #30
; rung 495
LD T0277
OR W200.13
AND W200.12
OUT W200.13
; rung 496
LD W200.11
AND<=(315) D5963 D2779
TIM 0278 #30
; rung 497
LD T0278
OR W200.14
AND W200.11
OUT W200.14
; rung 498
LD W200.14
AND<=(315) D3425 D2778
TIM 0279 #30
; rung 499
LD T0279
OR W200.15
AND W200.14
OUT W200.15
; rung 500
LD P_1s
AND W201.04
LD C0303
OR P_First_Cycle
CNT 0303 #60

; rung 501
LD W201.04
OUT TR0
AND C0303
ANDNOT W511.07
@++B(594) D283
LD TR0
CMP(020) D283 D282
LD P_EQ
OR P_GT
OR W511.07
ANDLD
OUT W511.07
MOV(021) D282 D283
LD TR0
CMP(020) D282 D285
ANDNOT P_EQ
MOV(021) #0 D283
LD TR0
MOV(021) D282 D285
; rung 502
LDNOT W201.04
MOV(021) #0 D283
; rung 503
LD W511.07
AND<=(315) D5967 D3444
TIM 0280 #30
; rung 504
LD T0280
OR W201.00
AND W201.04
OUT W201.00
; rung 505
LD W201.00
AND<=(315) D3426 D3450
TIM 0281 #30
; rung 506
LD T0281
OR W201.01
AND W201.00
OUT W201.01

; rung 507
LD W200.11
AND<=(315) D5965 D2777
TIM 0282 #30
; rung 508
LD T0282
OR W201.02
AND W200.11
OUT W201.02
; rung 509
LD W201.02
AND<=(315) D3427 D2776
TIM 0283 #30
; rung 510
LD T0283
OR W201.03
AND W201.02
OUT W201.03
; rung 511: '
LD P_1s
AND W201.04
LD C0302
OR P_First_Cycle
CNT 0302 #60

; rung 512
LD W201.04
OUT TR0
AND C0302
ANDNOT W511.06
@++B(594) D281
LD TR0
CMP(020) D281 D280
LD P_EQ
OR P_GT
OR W511.06
ANDLD
OUT W511.06
MOV(021) D280 D281
LD TR0
CMP(020) D280 D284
ANDNOT P_EQ
MOV(021) #0 D281
LD TR0
MOV(021) D280 D284
; rung 513
LDNOT W201.04
MOV(021) #0 D281
; rung 514
LD W511.06
AND<=(315) D5966 D3446
TIM 0284 #30
; rung 515
LD T0284
OR W201.14
AND W201.04
OUT W201.14
; rung 516
LD W201.14
AND<=(315) D3428 D3452
TIM 0285 #30
; rung 517
LD T0285
OR W201.15
AND W201.14
OUT W201.15

; rung 518: ﾊﾞﾘﾔ計量ﾎｯﾊﾟﾊﾞﾙﾌﾞ閉又は粉砕計量ﾎｯﾊﾟﾊﾞﾙﾌﾞ閉信号が来た時、各押出機低速運転し、ﾊﾞﾘｱ及び粉砕押出機は高速回転数にする
LD P_1s
AND W200.11
LD C0305
OR P_First_Cycle
CNT 0305 #60
; rung 519
LD W200.11
OUT TR0
AND C0305
ANDNOT W510.13
++B(594) D287
LD TR0
CMP(020) D287 D286
LD P_EQ
OR P_GT
OR W510.13
ANDLD
OUT W510.13
MOV(021) D286 D287
LD TR0
CMP(020) D286 D299
ANDNOT P_EQ
MOV(021) #0 D287
LD TR0
MOV(021) D286 D299
; rung 520
LDNOT W200.11
MOV(021) #0 D287
; rung 521
LD W510.13
AND W200.11
AND<=(315) D5962 D3447
TIM 0286 #30
; rung 522
LD T0286
OR W203.14
AND W200.11
AND W510.13
OUT W203.14

; rung 523
LD W203.14
AND<=(315) D3429 D3453
TIM 0287 #30
; rung 524
LD T0287
OR W203.15
AND W203.14
OUT W203.15
; rung 525
LD W200.13
AND W200.15
AND W201.01
AND W201.03
AND W201.15
AND W203.15
OUT W203.13
; rung 526: ----- 各押出機回転数を設定 -----
LD W204.07
OUT TR0
CMP(020) D5990 D730
AND P_GT
MOV(021) D730 D5990
LD TR0
CMP(020) D5994 D730
AND P_GT
MOV(021) D730 D5994
LD TR0
CMP(020) D5991 D731
AND P_GT
MOV(021) D731 D5991
; rung 527: 供給装置から粉砕層空信号確認後粉砕樹脂圧力が設定値以下になったか確認 / 今回空信号はﾛｰﾄﾞｾﾙﾒｰﾀのLL信号ONしてから10sec後
LD W208.06
AND H80.14
OR W73.00
AND W204.00
ANDNOT 17.10
AND 2054.04
ANDNOT W73.13
OUT W73.00
TIM 0077 #10

; rung 528
LD T0077
OUT TR0
AND 5.05
OUT W76.00
DIFU(013) W73.01
LD TR0
AND 5.07
OUT W76.01
DIFU(013) W73.02
LD TR0
AND 5.09
OUT W76.02
DIFU(013) W74.09
LD TR0
AND 5.11
OUT W76.03
DIFU(013) W74.10
LD TR0
AND 5.13
OUT W76.04
DIFU(013) W74.11
LD TR0
AND 5.15
OUT W76.05
DIFU(013) W74.12
; rung 529: 粉砕層樹脂圧力が設定以下到達後、電動機電流が設定値以下に到達したか確認する。
LD W73.01
OR W73.03
AND T0077
ANDNOT W73.08
OUT W73.03
OUT W76.10
; rung 530
LD W73.02
OR W73.04
AND T0077
OUT W73.04
ANDNOT W76.12
OUT W76.11
; rung 531
LD W73.03
AND W73.04
OUT W73.05

; rung 532
LD W73.05
OUT TR0
CMP(020) D5992 D5963
LDNOT P_LT
OR 2002.15
OR W73.06
ANDLD
OUT W73.06
LD TR0
AND W73.06
CMP(020) D5993 D3425
ANDNOT P_LT
OUT W73.07
; rung 533
LD W73.07
OR W73.08
AND T0077
OUT W73.08
OUT W76.12
ANDNOT W208.01
OUT W76.13
; rung 534
LD W73.08
OUT TR0
CMP(020) D5997 D5962
LDNOT P_LT
OR 2001.15
OR W73.09
ANDLD
OUT W73.09
LD TR0
AND W73.09
CMP(020) D5998 D3429
LDNOT P_LT
OR W73.10
ANDLD
OUT W73.10

; rung 535
LD W73.08
OUT TR0
CMP(020) D5995 D5963
LDNOT P_LT
OR 2002.15
OR W73.11
ANDLD
OUT W73.11
LD TR0
AND W73.11
CMP(020) D5996 D3425
LDNOT P_LT
OR W73.12
ANDLD
OUT W73.12
; rung 536: 供給装置からﾊﾞﾘﾔ層空信号確認後ﾊﾞﾘﾔ樹脂圧力が設定値以下になったか確認 / 今回空信号はﾛｰﾄﾞｾﾙﾒｰﾀのLL信号ONしてから10sec後
LD W74.09
OR W74.13
AND T0077
OUT W74.13
ANDNOT W74.15
OUT W76.06
; rung 537
LD W74.13
OUT TR0
CMP(020) D661 D5964
LDNOT P_LT
OR 2003.15
OR W74.14
ANDLD
OUT W74.14
LD TR0
AND W74.14
CMP(020) D662 D3424
LDNOT P_LT
OR W74.15
ANDLD
OUT W74.15
; rung 538: ﾊﾞﾘﾔ層樹脂圧力が設定値以下到達後、電動機電流が設定値以下に到達したか確認する。
LD W74.10
OR W75.00
AND T0077
OUT W75.00
ANDNOT W75.02
OUT W76.07

; rung 539
LD W75.00
OUT TR0
CMP(020) D664 D5965
LDNOT P_LT
OR 2004.15
OR W75.01
ANDLD
OUT W75.01
LD TR0
AND W75.01
CMP(020) D665 D3427
LDNOT P_LT
OR W75.02
ANDLD
OUT W75.02
; rung 540: ・供給装置からﾊﾟｰｼﾞ材開信号確認後ﾊﾟｰｼﾞ時間ｶｳﾝﾄﾀﾞｳﾝ ﾊﾞﾘﾔ&粉砕AND信号となっていたが / ﾊﾞﾘﾔ信号のみに変更(980620) / ・ﾊﾞﾘﾔと粉砕のﾀﾞﾝﾊﾟが両方開してからﾊﾟｰｼﾞ時間ｶｳﾝﾄﾀﾞｳﾝ開始に変更
LD W74.11
OR W75.03
AND T0077
OUT W75.03
ANDNOT W75.05
OUT W76.08
; rung 541
LD W75.03
OUT TR0
CMP(020) D667 D5966
LDNOT P_LT
OR 2005.15
OR W75.04
ANDLD
OUT W75.04
LD TR0
AND W75.04
CMP(020) D668 D3428
LDNOT P_LT
OR W75.05
ANDLD
OUT W75.05
; rung 542: ﾊﾞﾘﾔ及び粉砕のﾊﾟｰｼﾞﾀﾞﾝﾊﾟ開LS ONしたか確認
LD W74.12
OR W75.06
AND T0077
OUT W75.06
ANDNOT W75.08
OUT W76.09

; rung 543
LD W75.06
OUT TR0
CMP(020) D670 D5967
LDNOT P_LT
OR 2006.15
OR W75.07
ANDLD
OUT W75.07
LD TR0
AND W75.07
CMP(020) D671 D3426
LDNOT P_LT
OR W75.08
ANDLD
OUT W75.08
; rung 544
LD T0077
AND W208.04
AND W208.01
AND W208.05
AND W208.00
AND W208.02
AND W208.03
OUT W73.13
DIFU(013) W75.10
; rung 545
LD W73.13
OR W73.14
AND W204.00
ANDNOT 17.10
OUT W73.14
; rung 546
LDNOT W73.00
ANDNOT W73.14
OUT W73.15
; rung 547: ﾊﾟｰｼﾞ時間ｶｳﾝﾄﾀﾞｳﾝ処理
LDNOT T0077
MOV(021) #0 D3170
; rung 548
LD W73.03
BIN(023) D5990 D3170
; rung 549
LD W73.08
BIN(023) D5994 D3170

; rung 550
LD W73.03
OR W73.08
SCL(194) D3170 D335 D3171
AND 10.06
BIN(023) D3171 2041
; rung 551: ﾊﾞﾘﾔ及び粉砕のﾊﾟｰｼﾞﾀﾞﾝﾊﾟ閉LS ONしたか確認
LDNOT T0077
MOV(021) #0 D3172
; rung 552
LD W73.04
BIN(023) D5991 D3172
; rung 553
LD W73.04
SCL(194) D3172 D307 D3173
AND 10.07
BIN(023) D3173 2042
; rung 554: 991021 主外高回転時間追加
LDNOT T0077
MOV(021) #0 D3174
; rung 555
LD W74.13
BIN(023) D660 D3174
SCL(194) D3174 D300 D3175
AND 10.08
BIN(023) D3175 2043

; rung 556: 98.06.08 全ﾊﾞﾙﾌﾞ閉確認後、接着外層EXT停止処理していたが、先に停止処理させる / 99.06.30 接着外層低回転時間追加
LDNOT T0077
MOV(021) #0 D3176
; rung 557
LD W75.00
BIN(023) D663 D3176
SCL(194) D3176 D321 D3177
AND 10.09
BIN(023) D3177 2044
; rung 558: 98.06.08 全ﾊﾞﾙﾌﾞ閉確認後、接着内層EXT停止処理していたが、先に停止処理させる / 99.06.30 接着内層低回転時間追加
LDNOT T0077
MOV(021) #0 D3178
; rung 559
LD W75.03
BIN(023) D666 D3178
SCL(194) D3178 D328 D3179
AND 10.10
BIN(023) D3179 2045
; rung 560: 991021 主内高回転時間追加
LDNOT T0077
MOV(021) #0 D3180

; rung 561
LD W75.06
BIN(023) D669 D3180
SCL(194) D3180 D314 D3181
AND 10.11
BIN(023) D3181 2046
; rung 562
LDNOT 427.00
ANDNOT W73.00
OUT W204.06
; rung 563: ********** 押出機起動共通ｲﾝﾀｰﾛｯｸ ********** / 今回ｶｯﾀｰ装置が移動するのでｶｯﾀｰ装置が成形位置でﾛｯｸﾋﾟﾝﾛｯｸしていない場合は押出機起動不可とした。
LD W433.04
OR W215.12
OR 461.04
AND T0511
AND 408.01
AND 408.02
LD 2050.01
OR W215.12
OR 461.04
ANDLD
OUT W215.15
; rung 564
LDNOT 13.08
AND 10.06
TIM 0186 #20
; rung 565
LDNOT 14.01
AND 10.07
TIM 0187 #20
; rung 566
LDNOT 14.10
AND 10.08
TIM 0188 #20
; rung 567
LDNOT 15.03
AND 10.09
TIM 0189 #20
; rung 568
LDNOT 15.12
AND 10.10
TIM 0190 #20

; rung 569
LDNOT 16.05
AND 10.11
TIM 0191 #20
; rung 570
LD H2.09
ORNOT H2.09
ANDNOT 17.10
OUT TR0
AND 2054.04
OUT W63.13
LD TR0
ANDNOT 2054.04
OUT W63.14
LD TR0
AND 2054.03
AND 401.06
OUT W63.15
; rung 571: ********** 主材内層押出機処理 **********
LDNOT H2.09
AND 17.09
AND 17.10
LD H2.09
ORNOT H2.09
AND 2054.04
ANDNOT 17.10
ORLD
AND W215.15
AND T0092
ANDNOT W223.15
ANDNOT W357.10
OUT W215.00
; rung 572
LDNOT H2.09
ANDNOT 17.09
AND 17.10
LD H2.09
ORNOT H2.09
ANDNOT 2054.04
ANDNOT 17.10
ORLD
OR W203.15
OR W73.10
OR W356.01
OR W215.06
AND 13.01
AND T0511
ANDNOT T0486
OUT W215.06
TIM 0486 #50
; rung 573
LD 13.02
ORNOT 13.04
OR T0186
LDNOT 4.00
AND 10.06
AND H2.09
ORLD
OR W357.10
ANDNOT W394.13
AND T0511
OUT W357.10

; rung 574
LDNOT H2.09
AND 17.08
AND 17.10
AND 401.06
LD H2.09
ORNOT H2.09
AND 2054.03
ANDNOT 17.10
AND 401.06
AND 406.15
ORLD
ANDNOT 427.00
LD 10.00
AND 13.01
AND 3.12
ORLD
LD 13.09
ANDNOT T0486
ANDNOT W357.10
LD 402.05
AND 461.04
ORLD
ANDLD
AND W215.15
OUT 10.00
OUT 0.08
TIM 0492 #30
; rung 575
LD 10.00
AND 13.01
AND 3.12
AND T0492
AND W215.00
ANDNOT W215.06
OUT 10.06
AND 13.03
OUT 420.00
OUTNOT W208.04
; rung 576: ********** 粉砕材層押出機処理 ***********
LDNOT H2.09
AND 17.01
AND 17.10
LD H2.09
ORNOT H2.09
AND 2054.04
ANDNOT 17.10
ORLD
AND W215.15
AND T0092
ANDNOT W223.15
ANDNOT W357.11
OUT W215.01
; rung 577
LD W215.01
OUT 422.10
; rung 578
LDNOT H2.09
ANDNOT 17.01
AND 17.10
LD H2.09
ORNOT H2.09
ANDNOT 2054.04
ANDNOT 17.10
ORLD
OR W200.15
OR W73.12
OR W356.01
OR W215.07
AND 13.10
AND T0511
ANDNOT T0487
OUT W215.07
TIM 0487 #50

; rung 579
LD 13.11
ORNOT 13.13
OR T0187
LDNOT 4.02
AND 10.07
AND H2.09
ORLD
OR W357.11
ANDNOT W394.13
AND T0511
OUT W357.11
; rung 580
LDNOT H2.09
AND 17.00
AND 17.10
AND 401.06
LD H2.09
ORNOT H2.09
AND 2054.03
ANDNOT 17.10
AND 401.06
AND 406.15
ORLD
ANDNOT 427.00
LD 10.01
AND 13.10
AND 3.13
ORLD
LD 13.09
ANDNOT T0487
ANDNOT W357.11
LD 402.05
AND 461.04
ORLD
ANDLD
AND W215.15
OUT 10.01
OUT 0.09
TIM 0493 #30
; rung 581
LD 10.01
AND 13.10
AND 3.13
AND T0493
AND W215.01
ANDNOT W215.07
OUT 10.07
AND 13.12
OUT 420.01
OUTNOT W208.01
; rung 582
LD 10.07
DIFD(014) W54.12
; rung 583: ********** 主材外層押出機処理 **********
LDNOT H2.09
AND 16.15
AND 17.10
LD H2.09
ORNOT H2.09
AND 2054.04
ANDNOT 17.10
ORLD
AND W215.15
AND T0092
ANDNOT W223.15
ANDNOT W357.12
OUT W215.02

; rung 584
LDNOT H2.09
ANDNOT 16.15
AND 17.10
LD H2.09
ORNOT H2.09
ANDNOT 2054.04
ANDNOT 17.10
ORLD
OR W200.13
OR W74.15
OR W356.01
OR W215.08
AND 14.03
AND T0511
ANDNOT T0488
OUT W215.08
TIM 0488 #50
; rung 585
LD 14.04
ORNOT 14.06
OR T0188
LDNOT 4.01
AND 10.08
AND H2.09
ORLD
OR W357.12
ANDNOT W394.13
AND T0511
OUT W357.12
; rung 586
LDNOT H2.09
AND 16.14
AND 17.10
AND 401.06
LD H2.09
ORNOT H2.09
AND 2054.03
ANDNOT 17.10
AND 401.06
AND 406.15
ORLD
ANDNOT 427.00
LD 10.02
AND 14.03
ORLD
LD 13.09
ANDNOT T0488
ANDNOT W357.12
LD 402.05
AND 461.04
ORLD
ANDLD
AND W215.15
OUT 10.02
TIM 0494 #30
; rung 587
LD 10.02
AND 14.03
AND T0494
AND W215.02
ANDNOT W215.08
OUT 10.08
AND 14.05
OUT 420.02
OUTNOT W208.05
; rung 588: ********** ﾊﾞﾘﾔ材層押出機処理 **********
LDNOT H2.09
AND 17.05
AND 17.10
LD H2.09
ORNOT H2.09
AND 2054.04
ANDNOT 17.10
ORLD
AND W215.15
AND T0092
ANDNOT W223.15
ANDNOT W357.13
OUT W215.03

; rung 589
LDNOT H2.09
ANDNOT 17.05
AND 17.10
LD H2.09
ORNOT H2.09
ANDNOT 2054.04
ANDNOT 17.10
ORLD
OR W201.03
OR W75.02
OR W356.01
OR W215.09
AND 14.12
AND T0511
ANDNOT T0489
OUT W215.09
TIM 0489 #50
; rung 590
LD 14.13
ORNOT 14.15
OR T0189
LDNOT 4.05
AND 10.09
AND H2.09
ORLD
OR W357.13
ANDNOT W394.13
AND T0511
OUT W357.13
; rung 591
LDNOT H2.09
AND 17.04
AND 17.10
AND 401.06
LD H2.09
ORNOT H2.09
AND 2054.03
ANDNOT 17.10
AND 401.06
AND 406.15
ORLD
ANDNOT 427.00
LD 10.03
AND 14.12
ORLD
LD 13.09
ANDNOT T0489
ANDNOT W357.13
LD 402.05
AND 461.04
ORLD
ANDLD
AND W215.15
OUT 10.03
TIM 0495 #30
; rung 592
LD 10.03
AND 14.12
AND T0495
AND W215.03
ANDNOT W215.09
OUT 10.09
AND 14.14
OUT 420.03
OUTNOT W208.00
; rung 593
LD 10.09
DIFD(014) W54.13

; rung 594: ********** 接着内層押出機処理 **********
LDNOT H2.09
AND 17.07
AND 17.10
LD H2.09
ORNOT H2.09
AND 2054.04
ANDNOT 17.10
ORLD
AND W215.15
AND T0092
ANDNOT W223.15
ANDNOT W357.14
OUT W215.04
; rung 595
LDNOT H2.09
ANDNOT 17.07
AND 17.10
LD H2.09
ORNOT H2.09
ANDNOT 2054.04
ANDNOT 17.10
ORLD
OR W201.15
OR W75.05
OR W356.01
OR W215.10
AND 15.05
AND T0511
ANDNOT T0490
OUT W215.10
TIM 0490 #50
; rung 596
LD 15.06
ORNOT 15.08
OR T0190
LDNOT 4.03
AND 10.10
AND H2.09
ORLD
OR W357.14
ANDNOT W394.13
AND T0511
OUT W357.14
; rung 597
LDNOT H2.09
AND 17.06
AND 17.10
AND 401.06
LD H2.09
ORNOT H2.09
AND 2054.03
ANDNOT 17.10
AND 401.06
AND 406.15
ORLD
ANDNOT 427.00
LD 10.04
AND 15.05
ORLD
LD 13.09
ANDNOT T0490
ANDNOT W357.14
LD 402.05
AND 461.04
ORLD
ANDLD
AND W215.15
OUT 10.04
TIM 0496 #30
; rung 598
LD 10.04
AND 15.05
AND T0496
AND W215.04
ANDNOT W215.10
OUT 10.10
AND 15.07
OUT 420.04
OUTNOT W208.02

; rung 599: ********** 接着外層押出機処理 **********
LDNOT H2.09
AND 17.03
AND 17.10
LD H2.09
ORNOT H2.09
AND 2054.04
ANDNOT 17.10
ORLD
AND W215.15
AND T0092
ANDNOT W223.15
ANDNOT W357.15
OUT W215.05
; rung 600
LDNOT H2.09
ANDNOT 17.03
AND 17.10
LD H2.09
ORNOT H2.09
ANDNOT 2054.04
ANDNOT 17.10
ORLD
OR W201.01
OR W75.08
OR W356.01
OR W215.11
AND 15.14
AND T0511
ANDNOT T0491
OUT W215.11
TIM 0491 #50
; rung 601
LD 15.15
ORNOT 16.01
OR T0191
LDNOT 4.04
AND 10.11
AND H2.09
ORLD
OR W357.15
ANDNOT W394.13
AND T0511
OUT W357.15
; rung 602
LDNOT H2.09
AND 17.02
AND 17.10
AND 401.06
LD H2.09
ORNOT H2.09
AND 2054.03
ANDNOT 17.10
AND 401.06
AND 406.15
ORLD
ANDNOT 427.00
LD 10.05
AND 15.14
ORLD
LD 13.09
ANDNOT T0491
ANDNOT W357.15
LD 402.05
AND 461.04
ORLD
ANDLD
AND W215.15
OUT 10.05
TIM 0497 #30
; rung 603
LD 10.05
AND 15.14
AND T0497
AND W215.05
ANDNOT W215.11
OUT 10.11
AND 16.00
OUT 420.05
OUTNOT W208.03

; rung 604: ----- ｺﾝﾄﾛｰﾗｰﾘﾝｸ信号まとめ -----
LDNOT 13.01
ANDNOT 13.10
ANDNOT 14.03
ANDNOT 14.12
ANDNOT 15.05
ANDNOT 15.14
ANDNOT 10.06
ANDNOT 10.07
ANDNOT 10.08
ANDNOT 10.09
ANDNOT 10.10
ANDNOT 10.11
OUT 420.06
; rung 605
LD 13.01
AND 13.10
AND 14.03
AND 14.12
AND 15.05
AND 15.14
AND W208.06
OUT 420.07
; rung 606
LD H2.14
OUT 420.09
AND 2050.00
OUT 420.08
; rung 607
LD 2054.03
AND 406.15
AND 401.06
OUT 420.10
; rung 608: ********** ロスイン補正警報(M) **********(M) / 画面設定時間経過してもロスイン補正が掛からなかった場合、警報のみ発生
LDNOT 420.09
AND 420.07
AND H2.12
ANDNOT H98.15
AND W204.06
OUT W203.03
; rung 609
LD W203.03
AND H90.00
AND 10.06
AND H2.00
ANDNOT W503.00
ANDNOT W156.00
TIM 0254 D3688
; rung 610
LD W203.03
AND H90.01
AND 10.07
AND H2.01
ANDNOT W503.01
ANDNOT W156.01
TIM 0255 D3689
; rung 611
LD W203.03
AND H90.02
AND 10.08
AND H2.02
ANDNOT W503.02
ANDNOT W156.02
TIM 0256 D3690
; rung 612
LD W203.03
AND H90.03
AND 10.09
AND H2.03
ANDNOT W503.03
ANDNOT W156.03
TIM 0257 D3691
; rung 613
LD W203.03
AND H90.04
AND 10.10
AND H2.04
ANDNOT W503.04
ANDNOT W156.04
TIM 0258 D3692

; rung 614
LD W203.03
AND H90.05
AND 10.11
AND H2.05
ANDNOT W503.05
ANDNOT W156.05
TIM 0259 D3693

### Section LAMP_BUZZER

; rung 0: ********** 各ランプ処理 **********
LDNOT 14.03
ANDNOT 13.10
ANDNOT 15.14
ANDNOT 14.12
ANDNOT 15.05
ANDNOT 13.01
OUTNOT W157.13
; rung 1
LD 14.03
AND P_1s
OR 10.08
AND T0511
OUT 11.00
; rung 2
LD 13.10
AND P_1s
OR 10.07
AND T0511
OUT 11.01
; rung 3
LD 15.14
AND P_1s
OR 10.11
AND T0511
OUT 11.02
; rung 4
LD 14.12
AND P_1s
OR 10.09
AND T0511
OUT 11.03
; rung 5
LD 15.05
AND P_1s
OR 10.10
AND T0511
OUT 11.04
; rung 6
LD 13.01
AND P_1s
OR 10.06
AND T0511
OUT 11.05
; rung 7
LD W208.06
LD W157.13
AND P_1s
ORLD
AND T0511
OUT 2050.00
; rung 8
LD 2050.00
OUT 424.00
; rung 9
LD 420.07
AND T0511
AND H2.14
AND H2.09
AND H2.13
AND W204.06
OUT W157.14

; rung 10
LD W209.02
ANDNOT H80.15
LD W74.07
AND H80.15
ORLD
AND W157.14
OR W157.15
ANDNOT 427.00
OUT W157.15
OUT 421.03
; rung 11
LD P_1s
AND W157.14
LD W157.15
ANDNOT W77.00
ORLD
AND T0511
OUT 2050.02
; rung 12
LD W157.13
AND T0511
AND 427.00
OUT W157.11
; rung 13
LDNOT W204.00
AND W203.13
OR W157.09
AND T0511
ANDNOT W157.12
OUT W157.09
OUT 421.05
; rung 14
LD W157.09
OR W157.12
AND T0511
ANDNOT 10.06
ANDNOT 10.07
ANDNOT 10.08
ANDNOT 10.09
ANDNOT 10.10
ANDNOT 10.11
OUT W157.12
; rung 15
LD P_1s
AND W157.11
ANDNOT W157.12
LD W157.12
ANDNOT P_On
ORLD
AND T0511
OUT 2050.04
OUT 421.04
; rung 16
LD H2.09
AND W208.06
ANDNOT 427.00
LDNOT H98.15
LD P_1s
AND W212.03
ORLD
ANDLD
OUT 2050.05
; rung 17
LD H98.15
ANDNOT W212.03
OUT 2050.06
; rung 18
LD 420.07
ANDNOT 427.00
ANDNOT H2.14
AND H2.09
AND H2.13
AND H2.12
AND W86.15
OUT W157.10

; rung 19
LD W157.10
AND P_1s
LD H90.00
OR H90.01
OR H90.02
OR H90.03
OR H90.04
OR H90.05
LD W60.06
ORNOT H90.02
ANDLD
LD W60.07
ORNOT H90.01
ANDLD
LD W60.08
ORNOT H90.05
ANDLD
LD W60.09
ORNOT H90.03
ANDLD
LD W60.10
ORNOT H90.04
ANDLD
LD W60.11
ORNOT H90.00
ANDLD
ORLD
AND T0511
OUT 2050.03
OUT 421.02
; rung 20
LD W157.10
AND T0511
OUT W361.00
; rung 21
LD W361.00
OUT TR0
AND P_1s
ANDNOT 400.09
@++BL(595) D7900
LD TR0
ANDNOT 400.09
MOV(021) D7900 D7901
; rung 22
LDNOT 2050.02
@MOV(021) #0 D7901
@MOV(021) #0 D7900
; rung 23
LD T0511
OUT TR0
AND T0094
AND W433.13
ANDNOT W362.13
OUT W362.10
LD TR0
AND T0094
AND W433.12
ANDNOT W362.13
OUT W362.11
LD TR0
AND T0094
AND W438.09
ANDNOT W362.13
OUT W362.15
LD TR0
AND W433.03
AND W438.06
AND W433.04
OUT W362.13
; rung 24
LD T0094
AND W362.13
OUT 2050.01
; rung 25
LD T0460
ANDNOT W223.01
AND T0511
OUT W362.12
OUT 2050.07

; rung 26
LD 2054.01
ORNOT 2054.01
ANDNOT 2054.00
ANDNOT W224.00
AND H2.15
AND T0094
OUT W362.09
; rung 27
LD W362.11
OR W362.15
OUT W362.08
; rung 28
LD W362.12
OUT TR0
ANDNOT H17.11
OUT W61.13
LD TR0
AND H17.11
OUT W61.14
; rung 29
LD 410.00
LD W157.09
KEEP(011) 470.00
; rung 30
LD 410.01
LD W157.09
KEEP(011) 470.01
; rung 31
LD 420.08
LD 470.00
AND 470.01
LDNOT 470.00
ORNOT 470.01
AND P_1s
ORLD
ANDLD
OUT 2050.08
; rung 32: ********** パトライト処理 **********
LDNOT W223.00
ANDNOT W223.01
ANDNOT W223.02
ANDNOT W223.03
ANDNOT W223.04
ANDNOT W223.05
ANDNOT W223.06
ANDNOT W223.07
ANDNOT W223.08
ANDNOT W223.09
ANDNOT W223.10
ANDNOT W223.11
ANDNOT W223.12
ANDNOT W223.13
ANDNOT W223.14
ANDNOT W223.15
OUTNOT W216.11
; rung 33
LDNOT W224.00
ANDNOT W224.01
ANDNOT W224.02
ANDNOT W224.03
ANDNOT W224.04
ANDNOT W224.05
ANDNOT W224.06
ANDNOT W224.07
ANDNOT W224.08
ANDNOT W224.09
ANDNOT W224.10
ANDNOT W224.11
ANDNOT W224.12
ANDNOT W224.13
ANDNOT W224.14
AND P_On
OUTNOT W216.12
; rung 34
LDNOT W224.15
ANDNOT W236.01
ANDNOT H99.00
ANDNOT W236.05
ANDNOT W236.09
OUTNOT W220.11

; rung 35
LD T0511
LD W216.11
OR W216.12
OR W220.11
ANDLD
OUT 427.15
AND P_1s
OUT W362.00
; rung 36
LD W216.11
OR W216.12
AND P_1s
OUT W212.00
; rung 37
LD W220.11
AND P_1s
OUT W212.01
; rung 38: '********** ブザー処理 **********
LDNOT W223.00
OR W225.00
LDNOT W223.01
OR W225.01
ANDLD
LDNOT W223.02
OR W225.02
ANDLD
LDNOT W223.03
OR W225.03
ANDLD
LDNOT W223.04
OR W225.04
ANDLD
LDNOT W223.05
OR W225.05
ANDLD
LDNOT W223.06
OR W225.06
ANDLD
LDNOT W223.07
OR W225.07
ANDLD
LDNOT W223.08
OR W225.08
ANDLD
LDNOT W223.09
OR W225.09
ANDLD
LDNOT W223.10
OR W225.10
ANDLD
LDNOT W223.11
OR W225.11
ANDLD
LDNOT W223.12
OR W225.12
ANDLD
LDNOT W223.13
OR W225.13
ANDLD
LDNOT W223.14
OR W225.14
ANDLD
LDNOT W223.15
OR W225.15
ANDLD
OUTNOT W216.13
; rung 39
LDNOT W224.00
OR W226.00
LDNOT W224.02
OR W226.02
ANDLD
LDNOT W224.04
OR W226.04
ANDLD
LDNOT W224.05
OR W226.05
ANDLD
LDNOT W224.06
OR W226.06
ANDLD
LDNOT W224.08
OR W226.08
ANDLD
LDNOT W224.10
OR W226.10
ANDLD
LDNOT W224.13
OR W226.13
ANDLD
AND P_On
OUTNOT W216.14
; rung 40
LDNOT W224.15
OR W226.15
LDNOT W236.01
OR W236.02
ANDLD
LDNOT H99.00
OR H99.01
ANDLD
LDNOT W236.05
OR W236.06
ANDLD
LDNOT W236.09
OR W236.10
ANDLD
LDNOT W237.00
OR W237.01
ANDLD
OUTNOT W220.10
; rung 41
LD W216.13
OR W216.14
OR W220.10
AND T0511
OUT 427.14
; rung 42
LDNOT W224.01
OR W226.01
LDNOT W224.03
OR W226.03
ANDLD
LDNOT W224.07
OR W226.07
ANDLD
LDNOT W224.09
OR W226.09
ANDLD
LDNOT W224.11
OR W226.11
ANDLD
LDNOT W224.12
OR W226.12
ANDLD
LDNOT W224.14
OR W226.14
ANDLD
OUTNOT W220.09

; rung 43
LD W220.09
AND T0511
OUT 426.09
; rung 44: ********** NT画面処理プログラム ********** / 注意) NT631Cと標準で使用するNTではPT状態の占有CH数が異なるので注意すること / NT631C･･･制御ｴﾘｱ 5ch/通知ｴﾘｱ 2CH 標準･･･制御ｴﾘｱ 4ch/通知ｴﾘｱ 3ch / 特に画面表示通知が違うので注意
LD P_First_Cycle
MOV(021) #1 W0
; rung 45
LD P_On
BIN(023) W0 D290
MLPX(076) D290 #10 W378
; rung 46
LD W379.00
AND W378.01
ANDNOT W509.15
@MOV(021) #1 W0
; rung 47
LD W394.15
AND W394.14
@MOV(021) #210 W0
; rung 48
LD W394.15
AND W80.00
@MOV(021) #43 W0
; rung 49
LD W394.15
AND W80.11
@MOV(021) #82 W0
; rung 50
LD W394.15
AND W394.12
@MOV(021) #6 W0
; rung 51
LD P_On
AND>=(325) W0 #256
OUT W509.15

; rung 52: ********** 現在時刻設定 **********
LD W379.02
AND W378.04
ANDNOT W509.15
@XFER(070) &4 A351 D426
; rung 53
LD W363.04
@DATE(735) D426

### Section EXT_Amp_rpm

; rung 0: ********** 押出機電流値及び回転数処理 ********** / ・押出機回転数及び電流値の値が－側にふれない様変更 / ・押出機停止及び回転設定０の時表示０にする / ・最大電流値も画面より入れれる様にした / ・回転数及び電流値が－側に振れるのを防止した / ---------- 主材内層押出機 ----------
LD P_On
AND=(300) #0 2041
OUT W200.05
; rung 1
LDNOT 17.10
AND W200.05
AND 10.06
ORNOT 10.06
MOV(021) #0 D3141
MOV(021) #0 D3142
MOV(021) #0 D1010
; rung 2
LDNOT W200.05
OR 17.10
AND 10.06
OUT W54.00
; rung 3: 主材内層押出機回転数計算
LD W54.00
OUT TR0
ANDNOT 2021.15
MOV(021) 2021 D3340
LD TR0
AND 2021.15
MOV(021) #0 D3340
LD TR0
MOV(021) #0 D3550
MOV(021) #0 D3551
MOV(021) D724 D3552
MOV(021) #FA0 D3553
; rung 4
LD W54.00
SCL(194) D3340 D3550 D3141

; rung 5: 主材内層押出機ﾄﾙｸ値計算
LD W54.00
MOV(021) 2031 D3347
AND 2031.15
MOV(021) #0 D3347
; rung 6
LD W54.00
SCL(194) D3347 D1000 D3142
; rung 7: ----- 粉砕材層押出機 -----
LD P_On
AND=(300) #0 2042
OUT W200.06
; rung 8
LDNOT 17.10
AND W200.06
AND 10.07
ORNOT 10.07
MOV(021) #0 D3143
MOV(021) #0 D3144
MOV(021) #0 D1011
; rung 9
LDNOT W200.06
OR 17.10
AND 10.07
OUT W54.01

; rung 10: 粉砕材押出機回転数計算
LD W54.01
OUT TR0
ANDNOT 2022.15
MOV(021) 2022 D3341
LD TR0
AND 2022.15
MOV(021) #0 D3341
LD TR0
MOV(021) #0 D3554
MOV(021) #0 D3555
MOV(021) D725 D3556
MOV(021) #FA0 D3557
; rung 11
LD W54.01
SCL(194) D3341 D3554 D3143
; rung 12: 粉砕材押出機ﾄﾙｸ値計算
LD W54.01
MOV(021) 2032 D3348
AND 2032.15
MOV(021) #0 D3348
; rung 13
LD W54.01
SCL(194) D3348 D1000 D3144
; rung 14: ----- 主材外層押出機 -----
LD P_On
AND=(300) #0 2043
OUT W200.07

; rung 15
LDNOT 17.10
AND W200.07
AND 10.08
ORNOT 10.08
MOV(021) #0 D3191
MOV(021) #0 D3192
MOV(021) #0 D1012
; rung 16
LDNOT W200.07
OR 17.10
AND 10.08
OUT W54.02
; rung 17: 主材外層押出機回転数計算
LD W54.02
OUT TR0
ANDNOT 2023.15
MOV(021) 2023 D3342
LD TR0
AND 2023.15
MOV(021) #0 D3342
LD TR0
MOV(021) #0 D3558
MOV(021) #0 D3559
MOV(021) D726 D3560
MOV(021) #FA0 D3561
; rung 18
LD W54.02
SCL(194) D3342 D3558 D3191

; rung 19: 主材外層押出機ﾄﾙｸ値計算
LD W54.02
MOV(021) 2033 D3349
AND 2033.15
MOV(021) #0 D3349
; rung 20
LD W54.02
SCL(194) D3349 D1000 D3192
; rung 21: ----- ﾊﾞﾘﾔ材層押出機 -----
LD P_On
AND=(300) #0 2044
OUT W200.08
; rung 22
LDNOT 17.10
AND W200.08
AND 10.09
ORNOT 10.09
MOV(021) #0 D3193
MOV(021) #0 D3194
MOV(021) #0 D1013
; rung 23
LDNOT W200.08
OR 17.10
AND 10.09
OUT W54.03

; rung 24: ﾊﾞﾘﾔ層押出機回転数計算
LD W54.03
OUT TR0
ANDNOT 2024.15
MOV(021) 2024 D3343
LD TR0
AND 2024.15
MOV(021) #0 D3343
LD TR0
MOV(021) #0 D3562
MOV(021) #0 D3563
MOV(021) D727 D3564
MOV(021) #FA0 D3565
; rung 25
LD W54.03
SCL(194) D3343 D3562 D3193
; rung 26: ﾊﾞﾘﾔ層押出機ﾄﾙｸ値計算
LD W54.03
MOV(021) 2034 D3350
AND 2034.15
MOV(021) #0 D3350
; rung 27
LD W54.03
SCL(194) D3350 D1000 D3194
; rung 28: ----- 接着内層押出機 -----
LD P_On
AND=(300) #0 2045
OUT W200.09

; rung 29
LDNOT 17.10
AND W200.09
AND 10.10
ORNOT 10.10
MOV(021) #0 D3195
MOV(021) #0 D3196
MOV(021) #0 D1014
; rung 30
LDNOT W200.09
OR 17.10
AND 10.10
OUT W54.04
; rung 31: 接着内層押出機回転数計算
LD W54.04
OUT TR0
ANDNOT 2025.15
MOV(021) 2025 D3345
LD TR0
AND 2025.15
MOV(021) #0 D3345
LD TR0
MOV(021) #0 D3566
MOV(021) #0 D3567
MOV(021) D728 D3568
MOV(021) #FA0 D3569
; rung 32
LD W54.04
SCL(194) D3345 D3566 D3195

; rung 33: 接着内層押出機ﾄﾙｸ値計算
LD W54.04
MOV(021) 2035 D3351
AND 2035.15
MOV(021) #0 D3351
; rung 34
LD W54.04
SCL(194) D3351 D1000 D3196
; rung 35: ----- 接着外層押出機 -----
LD P_On
AND=(300) #0 2046
OUT W200.10
; rung 36
LDNOT 17.10
AND W200.10
AND 10.11
ORNOT 10.11
MOV(021) #0 D3197
MOV(021) #0 D3198
MOV(021) #0 D1015
; rung 37
LDNOT W200.10
OR 17.10
AND 10.11
OUT W54.05

; rung 38: 接着外層押出機回転数計算
LD W54.05
OUT TR0
ANDNOT 2026.15
MOV(021) 2026 D3346
LD TR0
AND 2026.15
MOV(021) #0 D3346
LD TR0
MOV(021) #0 D3570
MOV(021) #0 D3571
MOV(021) D729 D3572
MOV(021) #FA0 D3573
; rung 39
LD W54.05
SCL(194) D3346 D3570 D3197
; rung 40: 接着外層押出機ﾄﾙｸ値計算
LD W54.05
MOV(021) 2036 D3352
AND 2036.15
MOV(021) #0 D3352
; rung 41
LD W54.05
SCL(194) D3352 D1000 D3198

; rung 42: AD取込値がふらつくので平均値化処理(25回)した後,画面に表示
LD P_On
MOV(021) #25 D6100
MOV(021) #0 D6101
; rung 43: 主材外層押出機電流値表示
LD P_On
MOV(021) D3192 D3310
MOV(021) #0 D3311
CLC(041)
+BCL(407) D6102 D3310 D6102
++B(594) D6104
; rung 44
LD P_On
AND>=(325) D6104 D6100
/BL(435) D6102 D6100 D6105
MOV(021) D6105 D3424
MOV(021) #0 D6102
MOV(021) #0 D6103
MOV(021) #0 D6104

; rung 45: 粉砕材押出機電流値表示
LD P_On
MOV(021) D3144 D3312
MOV(021) #0 D3313
CLC(041)
+BCL(407) D6109 D3312 D6109
++B(594) D6111
; rung 46
LD P_On
AND>=(325) D6111 D6100
/BL(435) D6109 D6100 D6105
MOV(021) D6105 D3425
MOV(021) #0 D6109
MOV(021) #0 D6110
MOV(021) #0 D6111

; rung 47: 接着外層押出機電流値表示
LD P_On
MOV(021) D3198 D3314
MOV(021) #0 D3315
CLC(041)
+BCL(407) D6112 D3314 D6112
++B(594) D6114
; rung 48
LD P_On
AND>=(325) D6114 D6100
/BL(435) D6112 D6100 D6105
MOV(021) D6105 D3426
MOV(021) #0 D6112
MOV(021) #0 D6113
MOV(021) #0 D6114

; rung 49: ﾊﾞﾘﾔ層押出機電流値表示
LD P_On
MOV(021) D3194 D3316
MOV(021) #0 D3317
CLC(041)
+BCL(407) D6115 D3316 D6115
++B(594) D6117
; rung 50
LD P_On
AND>=(325) D6117 D6100
/BL(435) D6115 D6100 D6105
MOV(021) D6105 D3427
MOV(021) #0 D6115
MOV(021) #0 D6116
MOV(021) #0 D6117

; rung 51: 接着内層押出機電流値表示
LD P_On
MOV(021) D3196 D3318
MOV(021) #0 D3319
CLC(041)
+BCL(407) D6118 D3318 D6118
++B(594) D6120
; rung 52
LD P_On
AND>=(325) D6120 D6100
/BL(435) D6118 D6100 D6105
MOV(021) D6105 D3428
MOV(021) #0 D6118
MOV(021) #0 D6119
MOV(021) #0 D6120

; rung 53: 主材内層押出機ﾄﾙｸ値表示
LD P_On
MOV(021) D3142 D3320
MOV(021) #0 D3321
CLC(041)
+BCL(407) D6121 D3320 D6121
++B(594) D6123
; rung 54
LD P_On
AND>=(325) D6123 D6100
/BL(435) D6121 D6100 D6105
MOV(021) D6105 D3429
MOV(021) #0 D6121
MOV(021) #0 D6122
MOV(021) #0 D6123

; rung 55: 主材外層押出機回転数表示
LD P_On
MOV(021) D3191 D3322
MOV(021) #0 D3323
CLC(041)
+BCL(407) D6124 D3322 D6124
++B(594) D6126
; rung 56
LD P_On
AND>=(325) D6126 D6100
/BL(435) D6124 D6100 D6105
MOV(021) D6105 D3436
MOV(021) #0 D6124
MOV(021) #0 D6125
MOV(021) #0 D6126

; rung 57: 粉砕材押出機回転数表示
LD P_On
MOV(021) D3143 D3324
MOV(021) #0 D3325
CLC(041)
+BCL(407) D6127 D3324 D6127
++B(594) D6129
; rung 58
LD P_On
AND>=(325) D6129 D6100
/BL(435) D6127 D6100 D6105
MOV(021) D6105 D3437
MOV(021) #0 D6127
MOV(021) #0 D6128
MOV(021) #0 D6129

; rung 59: 接着外層押出機回転数表示
LD P_On
MOV(021) D3197 D3326
MOV(021) #0 D3327
CLC(041)
+BCL(407) D6130 D3326 D6130
++B(594) D6132
; rung 60
LD P_On
AND>=(325) D6132 D6100
/BL(435) D6130 D6100 D6105
MOV(021) D6105 D3438
MOV(021) #0 D6130
MOV(021) #0 D6131
MOV(021) #0 D6132

; rung 61: ﾊﾞﾘﾔ層押出機回転数表示
LD P_On
MOV(021) D3193 D3328
MOV(021) #0 D3329
CLC(041)
+BCL(407) D6133 D3328 D6133
++B(594) D6135
; rung 62
LD P_On
AND>=(325) D6135 D6100
/BL(435) D6133 D6100 D6105
MOV(021) D6105 D3439
MOV(021) #0 D6133
MOV(021) #0 D6134
MOV(021) #0 D6135

; rung 63: 接着内層押出機回転数表示
LD P_On
MOV(021) D3195 D3330
MOV(021) #0 D3331
CLC(041)
+BCL(407) D6136 D3330 D6136
++B(594) D6138
; rung 64
LD P_On
AND>=(325) D6138 D6100
/BL(435) D6136 D6100 D6105
MOV(021) D6105 D3440
MOV(021) #0 D6136
MOV(021) #0 D6137
MOV(021) #0 D6138

; rung 65: 主材内層押出機回転数表示
LD P_On
MOV(021) D3141 D3332
MOV(021) #0 D3333
CLC(041)
+BCL(407) D6139 D3332 D6139
++B(594) D6141
; rung 66
LD P_On
AND>=(325) D6141 D6100
/BL(435) D6139 D6100 D6105
MOV(021) D6105 D3441
MOV(021) #0 D6139
MOV(021) #0 D6140
MOV(021) #0 D6141
; rung 67
LD T0420
MOV(021) #0 D3650
MOV(021) #0 D3651
MOV(021) #0 D3652

; rung 68: ----- 押出機INVﾄﾙｸ表示ｽｹｰﾘﾝｸﾞｺﾝﾄﾛｰﾙﾃﾞｰﾀ処理 -----
LD P_On
MOV(021) #0 D1000
MOV(021) #0 D1001
MOV(021) #2000 D1002
MOV(021) #FA0 D1003
; rung 69: ----- 主内押出機負荷電流 -----
LD W54.00
OUT TR0
MOV(021) #0 D3574
MOV(021) #0 D3575
MOV(021) #4600 D3576
MOV(021) #7D0 D3577
ANDNOT 2077.15
SCL(194) 2077 D3574 D1010
LD TR0
AND 2077.15
MOV(021) #0 D1010
LD TR0
AND>(320) D1010 #4600
OUT W176.00

; rung 70: ----- 粉砕押出機負荷ﾄﾙｸ -----
LD W54.01
OUT TR0
MOV(021) #0 D3578
MOV(021) #0 D3579
MOV(021) #6000 D3580
MOV(021) #7D0 D3581
ANDNOT 2078.15
SCL(194) 2078 D3578 D1011
LD TR0
AND 2078.15
MOV(021) #0 D1011
LD TR0
AND>(320) D1011 #6000
OUT W176.01
; rung 71: ----- 主外押出機負荷電流 -----
LD W54.02
OUT TR0
MOV(021) #0 D3582
MOV(021) #0 D3583
MOV(021) #2100 D3584
MOV(021) #7D0 D3585
ANDNOT 2027.15
SCL(194) 2027 D3582 D1012
LD TR0
AND 2027.15
MOV(021) #0 D1012
LD TR0
AND>(320) D1012 #2100
OUT W176.02

; rung 72: ----- ﾊﾞﾘｱ押出機負荷電流 -----
LD W54.03
OUT TR0
MOV(021) #0 D3586
MOV(021) #0 D3587
MOV(021) #755 D3588
MOV(021) #7D0 D3589
ANDNOT 2028.15
SCL(194) 2028 D3586 D1013
LD TR0
AND 2028.15
MOV(021) #0 D1013
LD TR0
AND>(320) D1013 #755
OUT W176.03
; rung 73: ----- 接内押出機負荷電流 -----
LD W54.04
OUT TR0
MOV(021) #0 D3590
MOV(021) #0 D3591
MOV(021) #460 D3592
MOV(021) #7D0 D3593
ANDNOT 2037.15
SCL(194) 2037 D3590 D1014
LD TR0
AND 2037.15
MOV(021) #0 D1014
LD TR0
AND>(320) D1014 #460
OUT W176.04

; rung 74: ----- 接外押出機負荷電流 -----
LD W54.05
OUT TR0
MOV(021) #0 D3594
MOV(021) #0 D3595
MOV(021) #460 D3596
MOV(021) #7D0 D3597
ANDNOT 2038.15
SCL(194) 2038 D3594 D1015
LD TR0
AND 2038.15
MOV(021) #0 D1015
LD TR0
AND>(320) D1015 #460
OUT W176.05

### Section TIMERUP

; rung 0: ********** タイマー画面 ********** / タイマ１モニタ タイムアップ表示処理
LD P_On
OUT TR0
CLC(041)
-BC(416) D3650 D3600 D3660
AND W433.03
OUT W357.00
LD TR0
CLC(041)
-BC(416) D3651 D3601 D3661
AND W438.06
OUT W357.01
LD TR0
CLC(041)
-BC(416) D3652 D3602 D3662
AND W433.04
OUT W357.02
; rung 1
LD P_On
MOV(021) T203 D3663
LD T0203
LD W357.03
AND P_On
ORLD
ANDLD
OUT W357.03

### Section SELECTION

; rung 0: ********** 動作選択処理 ********** / ----- 動作選択1選択中 -----
LD W377.00
OR W377.01
OR W377.02
OR W377.03
OR W377.04
OR W377.05
OR W377.06
OR W377.07
ANDNOT W375.00
ANDNOT W375.01
ANDNOT W375.02
ANDNOT W375.03
ANDNOT W375.04
ANDNOT W375.05
ANDNOT W375.06
ANDNOT W375.07
TIM 0260 #100
; rung 1
LD W377.08
OR W377.09
OR W377.10
OR W377.11
OR W377.12
OR W377.13
OR W377.14
OR W377.15
ANDNOT W375.08
ANDNOT W375.09
ANDNOT W375.10
ANDNOT W375.11
ANDNOT W375.12
ANDNOT W375.13
ANDNOT W375.14
ANDNOT W375.15
TIM 0261 #100
; rung 2: ----- 動作選択2選択中 -----
LD W58.00
OR W58.01
OR W58.02
OR W58.03
OR W58.04
OR W58.05
OR W58.06
OR W58.07
ANDNOT W56.00
ANDNOT W56.01
ANDNOT W56.02
ANDNOT W56.03
ANDNOT W56.04
ANDNOT W56.05
ANDNOT W56.06
ANDNOT W56.07
TIM 0262 #100

; rung 3
LD W58.08
OR W58.09
OR W58.10
OR W58.11
OR W58.12
OR W58.13
OR W58.14
OR W58.15
ANDNOT W56.08
ANDNOT W56.09
ANDNOT W56.10
ANDNOT W56.11
ANDNOT W56.12
ANDNOT W56.13
ANDNOT W56.14
ANDNOT W56.15
TIM 0263 #100
; rung 4: ----- 動作選択１処理 -----
LD W379.02
AND W378.00
LD W379.01
AND W378.15
ORLD
ANDNOT W509.15
OUT W510.03
; rung 5
LD W379.00
AND W378.07
LD W379.02
AND W378.00
ORLD
LD W379.01
AND W378.15
ORLD
ANDNOT W509.15
OUT TR0
LD W375.01
OR W377.01
ANDLD
ANDNOT H2.08
ANDNOT T0260
ANDNOT W377.00
ANDNOT W375.00
OUT W377.01
LD TR0
LD W377.01
AND P_0_2s
OR H2.08
ANDLD
OUT W376.01
LD TR0
LD W375.00
OR W377.00
ANDLD
AND H2.08
ANDNOT T0260
ANDNOT W377.01
ANDNOT W375.01
OUT W377.00
LD TR0
LD W377.00
AND P_0_2s
ORNOT H2.08
ANDLD
OUT W376.00
; rung 6
LD W377.01
AND W363.05
OR H2.08
LDNOT W377.00
ORNOT W363.05
ANDLD
OUT H2.08

; rung 7
LD W379.01
AND W378.15
LD W378.00
OR W378.01
LD W379.05
OR W379.02
ANDLD
ORLD
LD W378.07
OR W378.08
AND W379.05
ORLD
LD W378.01
AND W379.06
ORLD
LD W378.05
AND W379.02
ORLD
ANDNOT W509.15
OUT TR0
LD W375.03
OR W377.03
ANDLD
ANDNOT H2.09
ANDNOT T0260
ANDNOT W377.02
ANDNOT W375.02
OUT W377.03
LD TR0
LD W377.03
AND P_0_2s
OR H2.09
ANDLD
ANDNOT H2.14
OUT W376.03
LD TR0
LDNOT H2.14
AND W375.02
OR W377.02
ANDLD
AND H2.09
ANDNOT T0260
ANDNOT W377.03
ANDNOT W375.03
OUT W377.02
LD TR0
LD W377.02
AND P_0_2s
ORNOT H2.09
ANDLD
OUT W376.02
; rung 8
LD W377.03
AND W363.05
OR H2.09
LDNOT W377.02
ORNOT W363.05
ANDLD
OUT H2.09
; rung 9
LD W379.02
AND W378.00
LD W379.01
AND W378.15
ORLD
ANDNOT W509.15
OUT TR0
LD W375.05
OR W377.05
ANDLD
ANDNOT H2.10
ANDNOT T0260
ANDNOT W377.04
ANDNOT W375.04
AND W204.06
ANDNOT H2.14
OUT W377.05
LD TR0
LD W377.05
AND P_0_2s
OR H2.10
ANDLD
OUT W376.05
LD TR0
LD W375.04
OR W377.04
ANDLD
AND H2.10
ANDNOT T0260
ANDNOT W377.05
ANDNOT W375.05
OUT W377.04
LD TR0
LD W377.04
AND P_0_2s
ORNOT H2.10
ANDLD
OUT W376.04
; rung 10
LD W377.05
AND W363.05
OR H2.10
LDNOT W377.04
ORNOT W363.05
ANDLD
ANDNOT H2.14
AND W204.06
OUT H2.10

; rung 11
LD W379.02
AND W378.00
LD W379.01
AND W378.15
ORLD
ANDNOT W509.15
OUT TR0
LD W375.07
OR W377.07
ANDLD
ANDNOT H2.11
ANDNOT T0260
ANDNOT W377.06
ANDNOT W375.06
OUT W377.07
LD TR0
LD W377.07
AND P_0_2s
OR H2.11
ANDLD
OUT W376.07
LD TR0
LD W375.06
OR W377.06
ANDLD
AND H2.11
ANDNOT T0260
ANDNOT W377.07
ANDNOT W375.07
OUT W377.06
LD TR0
LD W377.06
AND P_0_2s
ORNOT H2.11
ANDLD
OUT W376.06
; rung 12
LD W377.07
AND W363.05
OR H2.11
LDNOT W377.06
ORNOT W363.05
ANDLD
OUT H2.11
; rung 13: ----- 自動ﾌﾟﾘﾝﾄｱｳﾄ処理 -----
LD H2.11
CLC(041)
-BC(416) D3654 D250 D3664
; rung 14
LD P_On
AND<(310) D3654 #50
MOV(021) #50 D3654
; rung 15
LD H2.11
OUT TR0
AND C0097
++B(594) D250
LD TR0
AND>=(325) D250 D3654
OUT W398.12

; rung 16
LD W398.12
OR W398.13
AND H2.11
ANDNOT T0172
OUT W398.13
OUT W357.04
@MOV(021) #86 W0
TIM 0172 #10
; rung 17
LD T0172
ORNOT H2.11
MOV(021) #0 D250
MOV(021) #0 D3664
; rung 18
LD H2.11
OUT TR0
LD T0172
OR W398.08
ANDLD
ANDNOT W46.14
OUT W398.08
LD TR0
LD W398.08
OR W398.07
ANDLD
ANDNOT W398.06
OUT W398.07
LD TR0
AND W398.07
AND W46.14
DIFD(014) W398.06
LD TR0
LD W398.06
OR W398.05
ANDLD
ANDNOT W46.14
OUT W398.05
@MOV(021) #87 W0
TIM 0173 #10
LD TR0
LD W398.05
OR W398.04
ANDLD
ANDNOT W398.03
OUT W398.04
LD TR0
AND W398.04
AND W46.14
DIFD(014) W398.03
LD TR0
AND W398.03
@MOV(021) #80 W0

; rung 19
LD W398.08
OR T0173
OUT W343.15
; rung 20
LD W379.02
OR W379.05
LD W378.00
OR W378.01
ANDLD
LD W379.01
AND W378.15
ORLD
LD W378.07
OR W378.08
OR W378.09
OR W378.10
AND W379.05
ORLD
LD W378.01
AND W379.06
ORLD
ANDNOT W509.15
OUT TR0
LD W375.09
OR W377.09
ANDLD
ANDNOT H2.12
ANDNOT T0261
ANDNOT W377.08
ANDNOT W375.08
OUT W377.09
LD TR0
LD W377.09
AND P_0_2s
OR H2.12
ANDLD
LDNOT H2.14
OR P_On
ANDLD
OUT W376.09
LD TR0
LDNOT H2.14
OR P_On
AND W375.08
OR W377.08
ANDLD
AND H2.12
ANDNOT T0261
ANDNOT W377.09
ANDNOT W375.09
OUT W377.08
LD TR0
LD W377.08
AND P_0_2s
ORNOT H2.12
ANDLD
OUT W376.08
; rung 21
LD W377.09
AND W363.05
OR H2.12
LDNOT W377.08
ORNOT W363.05
ANDLD
AND H2.09
OUT H2.12
DIFU(013) W117.15
; rung 22
LD H2.09
DIFU(013) W511.08
; rung 23
LD W379.02
OR W379.05
LD W378.00
OR W378.01
ANDLD
LD W379.01
AND W378.15
ORLD
LD W378.07
OR W378.08
OR W378.09
OR W378.10
AND W379.05
ORLD
LD W378.01
AND W379.06
ORLD
ANDNOT W509.15
AND H2.09
OUT TR0
LD W375.11
OR W511.08
OR W377.11
ANDLD
ANDNOT H2.13
ANDNOT T0261
ANDNOT W377.10
ANDNOT W375.10
OUT W377.11
LD TR0
LD W377.11
AND P_0_2s
OR H2.13
ANDLD
ANDNOT H2.14
OUT W376.11
LD TR0
LDNOT H2.14
AND W375.10
OR W377.10
ANDLD
AND H2.13
ANDNOT T0261
ANDNOT W377.11
ANDNOT W375.11
OUT W377.10
LD TR0
LD W377.10
AND P_0_2s
ORNOT H2.13
ANDLD
OUT W376.10

; rung 24
LD W377.11
AND W363.05
OR H2.13
LDNOT W377.10
ORNOT W363.05
ANDLD
AND H2.09
OUT H2.13
; rung 25
LD W379.02
AND W378.00
LD W379.01
AND W378.15
ORLD
LD W378.00
OR W378.01
OR W378.07
OR W378.08
OR W378.09
OR W378.10
OR W378.15
AND W379.05
ORLD
LD W378.01
AND W379.06
ORLD
ANDNOT W509.15
OUT TR0
LD W375.13
OR W377.13
ANDLD
ANDNOT H2.14
ANDNOT T0261
ANDNOT W377.12
ANDNOT W375.12
OUT W377.13
LD TR0
LD W377.13
AND P_0_2s
OR H2.14
ANDLD
OUT W376.13
LD TR0
LD W375.12
OR W377.12
ANDLD
AND H2.14
ANDNOT T0261
ANDNOT W377.13
ANDNOT W375.13
OUT W377.12
LD TR0
LD W377.12
AND P_0_2s
ORNOT H2.14
ANDLD
OUT W376.12
; rung 26
LD 420.06
AND H2.09
AND H2.13
AND W377.13
AND W86.15
AND 402.12
OUT W356.14
; rung 27
LD W356.14
AND W363.05
OR H2.14
LDNOT W377.12
ORNOT W363.05
ANDLD
ANDNOT W209.02
ANDNOT W74.07
OUT H2.14
; rung 28
LD W86.13
AND 420.06
TIM 0420 #20
; rung 29
LD T0092
TIM 0422 #50
; rung 30
LDNOT T0422
OR W209.04
AND 2054.01
ANDNOT W377.15
OUT TR0
ANDNOT T0421
OUT W209.04
LD TR0
TIM 0421 #300

; rung 31
LD W510.03
OUT TR0
LD W70.01
AND W70.14
OR W72.01
ANDLD
ANDNOT H80.15
AND 420.06
ANDNOT T0261
ANDNOT W72.00
ANDNOT W70.00
OUT W72.01
LD TR0
LD W72.01
AND P_0_2s
OR H80.15
ANDLD
OUT W71.01
LD TR0
LD W70.00
AND W70.14
OR W72.00
ANDLD
AND H80.15
AND 420.06
ANDNOT T0261
ANDNOT W72.01
ANDNOT W70.01
OUT W72.00
LD TR0
LD W72.00
AND P_0_2s
ORNOT H80.15
ANDLD
OUT W71.00
; rung 32
LD W72.01
AND W363.05
OR H80.15
LDNOT W72.00
ORNOT W363.05
ANDLD
ANDNOT W75.09
OUT H80.15
; rung 33
LD W204.06
OUT W72.15
; rung 34
LD W510.03
OUT TR0
LD W70.03
AND W70.14
OR W72.03
ANDLD
ANDNOT H80.14
AND W72.15
ANDNOT T0261
ANDNOT W72.02
ANDNOT W70.02
OUT W72.03
LD TR0
LD W72.03
AND P_0_2s
OR H80.14
ANDLD
OUT W71.03
LD TR0
LD W70.02
AND W70.14
OR W72.02
ANDLD
AND H80.14
AND W72.15
ANDNOT T0261
ANDNOT W72.03
ANDNOT W70.03
OUT W72.02
LD TR0
LD W72.02
AND P_0_2s
ORNOT H80.14
ANDLD
OUT W71.02
; rung 35
LD W72.03
AND W363.05
OR H80.14
LDNOT W72.02
ORNOT W363.05
ANDLD
ANDNOT W75.10
OUT H80.14

; rung 36
LD W379.02
AND W378.00
LD W379.01
AND W378.15
ORLD
ANDNOT W509.15
OUT TR0
LD W375.15
OR W377.15
ANDLD
ANDNOT H2.15
ANDNOT T0261
ANDNOT W377.14
ANDNOT W375.14
OUT W377.15
LD TR0
LD W377.15
AND P_0_2s
OR H2.15
ANDLD
OUT W376.15
LD TR0
LD W375.14
OR W377.14
ANDLD
AND H2.15
ANDNOT T0261
ANDNOT W377.15
ANDNOT W375.15
OUT W377.14
LD TR0
LD W377.14
AND P_0_2s
ORNOT H2.15
ANDLD
OUT W376.14
; rung 37
LD W377.15
AND W363.05
LD W362.12
AND H17.01
ORLD
OR H2.15
LDNOT W377.14
ORNOT W363.05
ANDLD
LDNOT T0197
ORNOT W61.06
OR 2054.01
ANDLD
ANDNOT W433.00
LDNOT H17.00
ORNOT T0460
ANDLD
ANDNOT T0420
ANDNOT W209.04
OUT H2.15
; rung 38: ----- 動作選択２処理 ----- / 供給装置使用・不使用はパージ処理完了にて強制的に切る
LD W379.02
LD W378.01
OR W378.06
ANDLD
LD W379.01
AND W378.15
ORLD
ANDNOT W509.15
OUT W510.04
; rung 39
LD W510.04
OUT TR0
LD W56.01
OR W58.01
ANDLD
ANDNOT H2.00
ANDNOT T0262
ANDNOT W58.00
ANDNOT W56.00
OUT W58.01
LD TR0
LD W58.01
AND P_0_2s
OR H2.00
ANDLD
OUT W57.01
LD TR0
LD W56.00
OR W58.00
ANDLD
AND H2.00
ANDNOT T0262
ANDNOT W58.01
ANDNOT W56.01
OUT W58.00
LD TR0
LD W58.00
AND P_0_2s
ORNOT H2.00
ANDLD
OUT W57.00

; rung 40
LD W58.01
AND W363.05
LD W511.10
AND H2.09
ORLD
OR W377.13
OR H2.00
LDNOT W58.00
ORNOT W363.05
ANDLD
ANDNOT W200.11
ANDNOT W76.00
OUT H2.00
; rung 41
LD W510.04
OUT TR0
LD W56.03
OR W58.03
ANDLD
ANDNOT H2.01
ANDNOT T0262
ANDNOT W58.02
ANDNOT W56.02
OUT W58.03
LD TR0
LD W58.03
AND P_0_2s
OR H2.01
ANDLD
OUT W57.03
LD TR0
LD W56.02
OR W58.02
ANDLD
AND H2.01
ANDNOT T0262
ANDNOT W58.03
ANDNOT W56.03
OUT W58.02
LD TR0
LD W58.02
AND P_0_2s
ORNOT H2.01
ANDLD
OUT W57.02
; rung 42
LD W58.03
AND W363.05
LD W511.14
AND H2.09
ORLD
OR W377.13
OR H2.01
LDNOT W58.02
ORNOT W363.05
ANDLD
ANDNOT W200.11
ANDNOT W76.01
OUT H2.01
; rung 43
LD W510.04
OUT TR0
LD W56.05
OR W58.05
ANDLD
ANDNOT H2.02
ANDNOT T0262
ANDNOT W58.04
ANDNOT W56.04
OUT W58.05
LD TR0
LD W58.05
AND P_0_2s
OR H2.02
ANDLD
OUT W57.05
LD TR0
LD W56.04
OR W58.04
ANDLD
AND H2.02
ANDNOT T0262
ANDNOT W58.05
ANDNOT W56.05
OUT W58.04
LD TR0
LD W58.04
AND P_0_2s
ORNOT H2.02
ANDLD
OUT W57.04

; rung 44
LD W58.05
AND W363.05
LD W511.15
AND H2.09
ORLD
OR W377.13
OR H2.02
LDNOT W58.04
ORNOT W363.05
ANDLD
ANDNOT W200.11
ANDNOT W76.02
OUT H2.02
; rung 45
LD W510.04
OUT TR0
LD W56.07
OR W58.07
ANDLD
ANDNOT H2.03
ANDNOT T0262
ANDNOT W58.06
ANDNOT W56.06
OUT W58.07
LD TR0
LD W58.07
AND P_0_2s
OR H2.03
ANDLD
OUT W57.07
LD TR0
LD W56.06
OR W58.06
ANDLD
AND H2.03
ANDNOT T0262
ANDNOT W58.07
ANDNOT W56.07
OUT W58.06
LD TR0
LD W58.06
AND P_0_2s
ORNOT H2.03
ANDLD
OUT W57.06
; rung 46
LD W58.07
AND W363.05
LD W511.12
AND H2.09
ORLD
OR W377.13
OR H2.03
LDNOT W58.06
ORNOT W363.05
ANDLD
ANDNOT W200.11
ANDNOT W76.03
OUT H2.03
; rung 47
LD W510.04
OUT TR0
LD W56.09
OR W58.09
ANDLD
ANDNOT H2.04
ANDNOT T0263
ANDNOT W58.08
ANDNOT W56.08
OUT W58.09
LD TR0
LD W58.09
AND P_0_2s
OR H2.04
ANDLD
OUT W57.09
LD TR0
LD W56.08
OR W58.08
ANDLD
AND H2.04
ANDNOT T0263
ANDNOT W58.09
ANDNOT W56.09
OUT W58.08
LD TR0
LD W58.08
AND P_0_2s
ORNOT H2.04
ANDLD
OUT W57.08

; rung 48
LD W58.09
AND W363.05
LD W511.11
AND H2.09
ORLD
OR W377.13
OR H2.04
LDNOT W58.08
ORNOT W363.05
ANDLD
ANDNOT W200.11
ANDNOT W76.04
OUT H2.04
; rung 49
LD W510.04
OUT TR0
LD W56.11
OR W58.11
ANDLD
ANDNOT H2.05
ANDNOT T0263
ANDNOT W58.10
ANDNOT W56.10
OUT W58.11
LD TR0
LD W58.11
AND P_0_2s
OR H2.05
ANDLD
OUT W57.11
LD TR0
LD W56.10
OR W58.10
ANDLD
AND H2.05
ANDNOT T0263
ANDNOT W58.11
ANDNOT W56.11
OUT W58.10
LD TR0
LD W58.10
AND P_0_2s
ORNOT H2.05
ANDLD
OUT W57.10
; rung 50
LD W58.11
AND W363.05
LD W511.13
AND H2.09
ORLD
OR W377.13
OR H2.05
LDNOT W58.10
ORNOT W363.05
ANDLD
ANDNOT W200.11
ANDNOT W76.05
OUT H2.05
; rung 51
LD H2.00
AND H2.01
AND H2.02
AND H2.03
AND H2.04
AND H2.05
ANDNOT H2.06
ANDNOT H2.07
OUT W86.15

; rung 52
LD W510.04
OUT TR0
LD W56.13
OR W58.13
ANDLD
ANDNOT H2.06
ANDNOT T0263
ANDNOT W58.12
ANDNOT W56.12
OUT W58.13
LD TR0
LD W58.13
AND P_0_2s
OR H2.06
ANDLD
OUT W57.13
LD TR0
LD W56.12
OR W58.12
ANDLD
AND H2.06
ANDNOT T0263
ANDNOT W58.13
ANDNOT W56.13
OUT W58.12
LD TR0
LD W58.12
AND P_0_2s
ORNOT H2.06
ANDLD
OUT W57.12
; rung 53
LD W58.13
AND W363.05
OR H2.06
LDNOT W58.12
ORNOT W363.05
ANDLD
ANDNOT H2.01
AND W204.06
ANDNOT H2.14
OUT H2.06
; rung 54
LD W510.04
OUT TR0
LD W56.15
OR W58.15
ANDLD
ANDNOT H2.07
ANDNOT T0263
ANDNOT W58.14
ANDNOT W56.14
OUT W58.15
LD TR0
LD W58.15
AND P_0_2s
OR H2.07
ANDLD
OUT W57.15
LD TR0
LD W56.14
OR W58.14
ANDLD
AND H2.07
ANDNOT T0263
ANDNOT W58.15
ANDNOT W56.15
OUT W58.14
LD TR0
LD W58.14
AND P_0_2s
ORNOT H2.07
ANDLD
OUT W57.14
; rung 55
LD W58.15
AND W363.05
OR H2.07
LDNOT W58.14
ORNOT W363.05
ANDLD
ANDNOT H2.03
AND W204.06
ANDNOT H2.14
OUT H2.07

; rung 56: ----- 動作選択３ ＜一部押出機ﾌﾞﾛｯｸにて処理有り＞ -----
LD W379.02
LD W378.13
OR W378.14
ANDLD
ANDNOT W509.15
OUT TR0
LD W64.07
OR W66.03
ANDLD
ANDNOT H94.03
ANDNOT W64.06
OUT W66.07
LD TR0
LD W66.07
AND P_0_2s
OR H94.03
ANDLD
OUT W65.07
LD TR0
LD W64.06
OR W66.06
ANDLD
AND H94.03
ANDNOT W64.07
OUT W66.06
LD TR0
LD W66.06
AND P_0_2s
ORNOT H94.03
ANDLD
OUT W65.06
; rung 57
LD W66.07
AND W363.05
OR H94.03
LDNOT W66.06
ORNOT W363.05
ANDLD
OUT H94.03
; rung 58
LD W379.02
LD W378.13
OR W378.14
ANDLD
ANDNOT W509.15
OUT TR0
LD W64.09
OR W66.03
ANDLD
ANDNOT H94.04
ANDNOT W64.08
OUT W66.09
LD TR0
LD W66.09
AND P_0_2s
OR H94.04
ANDLD
OUT W65.09
LD TR0
LD W64.08
OR W66.08
ANDLD
AND H94.04
ANDNOT W64.09
OUT W66.08
LD TR0
LD W66.08
AND P_0_2s
ORNOT H94.04
ANDLD
OUT W65.08
; rung 59
LD W66.09
AND W363.05
OR H94.04
LDNOT W66.08
ORNOT W363.05
ANDLD
OUT H94.04

; rung 60
LD W379.02
LD W378.13
OR W378.14
ANDLD
ANDNOT W509.15
OUT TR0
LD W64.11
OR W66.11
ANDLD
ANDNOT H94.05
ANDNOT W64.10
OUT W66.11
LD TR0
LD W66.11
AND P_0_2s
OR H94.05
ANDLD
OUT W65.11
LD TR0
LD W64.10
OR W66.10
ANDLD
AND H94.05
ANDNOT W64.11
OUT W66.10
LD TR0
LD W66.10
AND P_0_2s
ORNOT H94.05
ANDLD
OUT W65.10
; rung 61
LD W66.11
AND W363.05
OR H94.05
LDNOT W66.10
ORNOT W363.05
ANDLD
OUT H94.05
; rung 62
LD W379.02
LD W378.13
OR W378.14
ANDLD
ANDNOT W509.15
OUT TR0
LD W64.13
OR W66.13
ANDLD
ANDNOT H94.06
ANDNOT W64.12
OUT W66.13
LD TR0
LD W66.13
AND P_0_2s
OR H94.06
ANDLD
OUT W65.13
LD TR0
LD W64.12
OR W66.12
ANDLD
AND H94.06
ANDNOT W64.13
OUT W66.12
LD TR0
LD W66.12
AND P_0_2s
ORNOT H94.06
ANDLD
OUT W65.12
; rung 63
LD W66.13
AND W363.05
OR H94.06
LDNOT W66.12
ORNOT W363.05
ANDLD
OUT H94.06

; rung 64
LD W379.02
LD W378.13
OR W378.14
ANDLD
ANDNOT W509.15
OUT TR0
LD W64.15
OR W66.15
ANDLD
ANDNOT H94.07
ANDNOT W64.14
OUT W66.15
LD TR0
LD W66.15
AND P_0_2s
OR H94.07
ANDLD
OUT W65.15
LD TR0
LD W64.14
OR W66.14
ANDLD
AND H94.07
ANDNOT W64.15
OUT W66.14
LD TR0
LD W66.14
AND P_0_2s
ORNOT H94.07
ANDLD
OUT W65.14
; rung 65
LD W66.15
AND W363.05
OR H94.07
LDNOT W66.14
ORNOT W363.05
ANDLD
OUT H94.07

### Section ALARM

; rung 0: ********** 警報処理 **********
LD 400.00
DIFU(013) W394.13
OUT 421.01
; rung 1
LD 400.04
OUT 421.00
; rung 2
LD W163.15
TIM 0177 #30
; rung 3
LD T0177
OUT W47.00
; rung 4
LD 400.04
ORNOT 400.05
OUT W216.10
; rung 5
LD 3.14
AND P_On
OUT 423.00
; rung 6: ----- 警報１ -----
LDNOT W357.10
ANDNOT W357.11
ANDNOT W357.12
ANDNOT W357.13
ANDNOT W357.14
ANDNOT W357.15
OUTNOT W80.01
; rung 7
LD T0511
OUT TR0
LD W80.01
OR W223.00
ANDLD
ANDNOT W227.00
OUT W223.00
OUT 427.10
LD TR0
LD W223.00
AND W216.10
OR W225.00
ANDLD
ANDNOT W227.00
OUT W225.00
AND W394.13
OUT W227.00
LD TR0
LD P_1s
OR W225.00
ANDLD
AND W223.00
OUT W221.00
; rung 8
LDNOT W227.00
AND T0511
ANDNOT W394.13
OUT W396.14

; rung 9: 主材内層押出機各警報
LD W357.10
OR W396.00
AND W396.14
OUT W396.00
; rung 10
LD 13.02
OR W396.15
AND W396.14
OUT W396.15
; rung 11
LD T0186
OR W397.00
AND W396.14
OUT W397.00
; rung 12
LD 13.05
ANDNOT 13.06
ANDNOT 13.07
ANDNOT 16.06
OR W170.00
AND W396.14
OUT W170.00
; rung 13
LDNOT 13.05
AND 13.06
ANDNOT 13.07
ANDNOT 16.06
OR W170.01
AND W396.14
OUT W170.01
; rung 14
LD 13.05
AND 13.06
ANDNOT 13.07
ANDNOT 16.06
OR W170.02
AND W396.14
OUT W170.02
; rung 15
LDNOT 13.05
ANDNOT 13.06
AND 13.07
ANDNOT 16.06
OR W170.03
AND W396.14
OUT W170.03
; rung 16
LD 13.05
ANDNOT 13.06
AND 13.07
ANDNOT 16.06
OR W170.04
AND W396.14
OUT W170.04
; rung 17
LDNOT 13.05
AND 13.06
AND 13.07
ANDNOT 16.06
OR W170.05
AND W396.14
OUT W170.05

; rung 18
LD 13.05
AND 13.06
AND 13.07
ANDNOT 16.06
OR W170.06
AND W396.14
OUT W170.06
; rung 19
LDNOT 13.05
ANDNOT 13.06
ANDNOT 13.07
AND 16.06
OR W170.07
AND W396.14
OUT W170.07
; rung 20
LD 13.05
ANDNOT 13.06
ANDNOT 13.07
AND 16.06
OR W170.08
AND W396.14
OUT W170.08
; rung 21
LDNOT 13.05
AND 13.06
ANDNOT 13.07
AND 16.06
OR W170.09
AND W396.14
OUT W170.09
; rung 22
LD 13.05
AND 13.06
ANDNOT 13.07
AND 16.06
OR W170.10
AND W396.14
OUT W170.10
; rung 23
LDNOT 13.05
ANDNOT 13.06
AND 13.07
AND 16.06
OR W170.11
AND W396.14
OUT W170.11
; rung 24
LD 13.05
ANDNOT 13.06
AND 13.07
AND 16.06
OR W170.12
AND W396.14
OUT W170.12
; rung 25
LDNOT 13.05
AND 13.06
AND 13.07
AND 16.06
OR W170.13
AND W396.14
OUT W170.13
; rung 26
LD 13.05
AND 13.06
AND 13.07
AND 16.06
OR W170.14
AND W396.14
OUT W170.14

; rung 27
LDNOT 4.00
AND H2.09
OR W82.07
AND W396.14
OUT W82.07
; rung 28: 粉砕材層押出機各警報
LD W357.11
OR W396.01
AND W396.14
OUT W396.01
; rung 29
LD 13.11
OR W397.07
AND W396.14
OUT W397.07
; rung 30
LD T0187
OR W397.08
AND W396.14
OUT W397.08
; rung 31
LD 13.14
ANDNOT 13.15
ANDNOT 14.00
ANDNOT 16.07
OR W171.00
AND W396.14
OUT W171.00
; rung 32
LDNOT 13.14
AND 13.15
ANDNOT 14.00
ANDNOT 16.07
OR W171.01
AND W396.14
OUT W171.01
; rung 33
LD 13.14
AND 13.15
ANDNOT 14.00
ANDNOT 16.07
OR W171.02
AND W396.14
OUT W171.02
; rung 34
LDNOT 13.14
ANDNOT 13.15
AND 14.00
ANDNOT 16.07
OR W171.03
AND W396.14
OUT W171.03
; rung 35
LD 13.14
ANDNOT 13.15
AND 14.00
ANDNOT 16.07
OR W171.04
AND W396.14
OUT W171.04

; rung 36
LDNOT 13.14
AND 13.15
AND 14.00
ANDNOT 16.07
OR W171.05
AND W396.14
OUT W171.05
; rung 37
LD 13.14
AND 13.15
AND 14.00
ANDNOT 16.07
OR W171.06
AND W396.14
OUT W171.06
; rung 38
LDNOT 13.14
ANDNOT 13.15
ANDNOT 14.00
AND 16.07
OR W171.07
AND W396.14
OUT W171.07
; rung 39
LD 13.14
ANDNOT 13.15
ANDNOT 14.00
AND 16.07
OR W171.08
AND W396.14
OUT W171.08
; rung 40
LDNOT 13.14
AND 13.15
ANDNOT 14.00
AND 16.07
OR W171.09
AND W396.14
OUT W171.09
; rung 41
LD 13.14
AND 13.15
ANDNOT 14.00
AND 16.07
OR W171.10
AND W396.14
OUT W171.10
; rung 42
LDNOT 13.14
ANDNOT 13.15
AND 14.00
AND 16.07
OR W171.11
AND W396.14
OUT W171.11
; rung 43
LD 13.14
ANDNOT 13.15
AND 14.00
AND 16.07
OR W171.12
AND W396.14
OUT W171.12
; rung 44
LDNOT 13.14
AND 13.15
AND 14.00
AND 16.07
OR W171.13
AND W396.14
OUT W171.13

; rung 45
LD 13.14
AND 13.15
AND 14.00
AND 16.07
OR W171.14
AND W396.14
OUT W171.14
; rung 46
LDNOT 4.02
AND H2.09
OR W82.08
AND W396.14
OUT W82.08
; rung 47: 主材外層押出機各警報
LD W357.12
OR W396.02
AND W396.14
OUT W396.02
; rung 48
LD 14.04
OR W51.00
AND W396.14
OUT W51.00
; rung 49
LD T0188
OR W51.01
AND W396.14
OUT W51.01
; rung 50
LD 14.07
ANDNOT 14.08
ANDNOT 14.09
ANDNOT 16.08
OR W172.00
AND W396.14
OUT W172.00
; rung 51
LDNOT 14.07
AND 14.08
ANDNOT 14.09
ANDNOT 16.08
OR W172.01
AND W396.14
OUT W172.01
; rung 52
LD 14.07
AND 14.08
ANDNOT 14.09
ANDNOT 16.08
OR W172.02
AND W396.14
OUT W172.02
; rung 53
LDNOT 14.07
ANDNOT 14.08
AND 14.09
ANDNOT 16.08
OR W172.03
AND W396.14
OUT W172.03

; rung 54
LD 14.07
ANDNOT 14.08
AND 14.09
ANDNOT 16.08
OR W172.04
AND W396.14
OUT W172.04
; rung 55
LDNOT 14.07
AND 14.08
AND 14.09
ANDNOT 16.08
OR W172.05
AND W396.14
OUT W172.05
; rung 56
LD 14.07
AND 14.08
AND 14.09
ANDNOT 16.08
OR W172.06
AND W396.14
OUT W172.06
; rung 57
LDNOT 14.07
ANDNOT 14.08
ANDNOT 14.09
AND 16.08
OR W172.07
AND W396.14
OUT W172.07
; rung 58
LD 14.07
ANDNOT 14.08
ANDNOT 14.09
AND 16.08
OR W172.08
AND W396.14
OUT W172.08
; rung 59
LDNOT 14.07
AND 14.08
ANDNOT 14.09
AND 16.08
OR W172.09
AND W396.14
OUT W172.09
; rung 60
LD 14.07
AND 14.08
ANDNOT 14.09
AND 16.08
OR W172.10
AND W396.14
OUT W172.10
; rung 61
LDNOT 14.07
ANDNOT 14.08
AND 14.09
AND 16.08
OR W172.11
AND W396.14
OUT W172.11
; rung 62
LD 14.07
ANDNOT 14.08
AND 14.09
AND 16.08
OR W172.12
AND W396.14
OUT W172.12

; rung 63
LDNOT 14.07
AND 14.08
AND 14.09
AND 16.08
OR W172.13
AND W396.14
OUT W172.13
; rung 64
LD 14.07
AND 14.08
AND 14.09
AND 16.08
OR W172.14
AND W396.14
OUT W172.14
; rung 65
LDNOT 4.01
AND H2.09
OR W82.09
AND W396.14
OUT W82.09
; rung 66: ﾊﾞﾘﾔ材層押出機各警報
LD W357.13
OR W396.03
AND W396.14
OUT W396.03
; rung 67
LD 14.13
OR W51.08
AND W396.14
OUT W51.08
; rung 68
LD T0189
OR W51.09
AND W396.14
OUT W51.09
; rung 69
LD 15.00
ANDNOT 15.01
ANDNOT 15.02
ANDNOT 16.09
OR W173.00
AND W396.14
OUT W173.00
; rung 70
LDNOT 15.00
AND 15.01
ANDNOT 15.02
ANDNOT 16.09
OR W173.01
AND W396.14
OUT W173.01
; rung 71
LD 15.00
AND 15.01
ANDNOT 15.02
ANDNOT 16.09
OR W173.02
AND W396.14
OUT W173.02

; rung 72
LDNOT 15.00
ANDNOT 15.01
AND 15.02
ANDNOT 16.09
OR W173.03
AND W396.14
OUT W173.03
; rung 73
LD 15.00
ANDNOT 15.01
AND 15.02
ANDNOT 16.09
OR W173.04
AND W396.14
OUT W173.04
; rung 74
LDNOT 15.00
AND 15.01
AND 15.02
ANDNOT 16.09
OR W173.05
AND W396.14
OUT W173.05
; rung 75
LD 15.00
AND 15.01
AND 15.02
ANDNOT 16.09
OR W173.06
AND W396.14
OUT W173.06
; rung 76
LDNOT 15.00
ANDNOT 15.01
ANDNOT 15.02
AND 16.09
OR W173.07
AND W396.14
OUT W173.07
; rung 77
LD 15.00
ANDNOT 15.01
ANDNOT 15.02
AND 16.09
OR W173.08
AND W396.14
OUT W173.08
; rung 78
LDNOT 15.00
AND 15.01
ANDNOT 15.02
AND 16.09
OR W173.09
AND W396.14
OUT W173.09
; rung 79
LD 15.00
AND 15.01
ANDNOT 15.02
AND 16.09
OR W173.10
AND W396.14
OUT W173.10
; rung 80
LDNOT 15.00
ANDNOT 15.01
AND 15.02
AND 16.09
OR W173.11
AND W396.14
OUT W173.11

; rung 81
LD 15.00
ANDNOT 15.01
AND 15.02
AND 16.09
OR W173.12
AND W396.14
OUT W173.12
; rung 82
LDNOT 15.00
AND 15.01
AND 15.02
AND 16.09
OR W173.13
AND W396.14
OUT W173.13
; rung 83
LD 15.00
AND 15.01
AND 15.02
AND 16.09
OR W173.14
AND W396.14
OUT W173.14
; rung 84
LDNOT 4.05
AND H2.09
OR W82.10
AND W396.14
OUT W82.10
; rung 85: 接着内層押出機各警報
LD W357.14
OR W396.04
AND W396.14
OUT W396.04
; rung 86
LD 15.06
OR W52.00
AND W396.14
OUT W52.00
; rung 87
LD T0190
OR W52.01
AND W396.14
OUT W52.01
; rung 88
LD 15.09
ANDNOT 15.10
ANDNOT 15.11
ANDNOT 16.10
OR W174.00
AND W396.14
OUT W174.00
; rung 89
LDNOT 15.09
AND 15.10
ANDNOT 15.11
ANDNOT 16.10
OR W174.01
AND W396.14
OUT W174.01

; rung 90
LD 15.09
AND 15.10
ANDNOT 15.11
ANDNOT 16.10
OR W174.02
AND W396.14
OUT W174.02
; rung 91
LDNOT 15.09
ANDNOT 15.10
AND 15.11
ANDNOT 16.10
OR W174.03
AND W396.14
OUT W174.03
; rung 92
LD 15.09
ANDNOT 15.10
AND 15.11
ANDNOT 16.10
OR W174.04
AND W396.14
OUT W174.04
; rung 93
LDNOT 15.09
AND 15.10
AND 15.11
ANDNOT 16.10
OR W174.05
AND W396.14
OUT W174.05
; rung 94
LD 15.09
AND 15.10
AND 15.11
ANDNOT 16.10
OR W174.06
AND W396.14
OUT W174.06
; rung 95
LDNOT 15.09
ANDNOT 15.10
ANDNOT 15.11
AND 16.10
OR W174.07
AND W396.14
OUT W174.07
; rung 96
LD 15.09
ANDNOT 15.10
ANDNOT 15.11
AND 16.10
OR W174.08
AND W396.14
OUT W174.08
; rung 97
LDNOT 15.09
AND 15.10
ANDNOT 15.11
AND 16.10
OR W174.09
AND W396.14
OUT W174.09
; rung 98
LD 15.09
AND 15.10
ANDNOT 15.11
AND 16.10
OR W174.10
AND W396.14
OUT W174.10

; rung 99
LDNOT 15.09
ANDNOT 15.10
AND 15.11
AND 16.10
OR W174.11
AND W396.14
OUT W174.11
; rung 100
LD 15.09
ANDNOT 15.10
AND 15.11
AND 16.10
OR W174.12
AND W396.14
OUT W174.12
; rung 101
LDNOT 15.09
AND 15.10
AND 15.11
AND 16.10
OR W174.13
AND W396.14
OUT W174.13
; rung 102
LD 15.09
AND 15.10
AND 15.11
AND 16.10
OR W174.14
AND W396.14
OUT W174.14
; rung 103
LDNOT 4.03
AND H2.09
OR W82.11
AND W396.14
OUT W82.11
; rung 104: 接着外層押出機各警報
LD W357.15
OR W396.05
AND W396.14
OUT W396.05
; rung 105
LD 15.15
OR W52.08
AND W396.14
OUT W52.08
; rung 106
LD T0191
OR W52.09
AND W396.14
OUT W52.09
; rung 107
LD 16.02
ANDNOT 16.03
ANDNOT 16.04
ANDNOT 16.11
OR W175.00
AND W396.14
OUT W175.00

; rung 108
LDNOT 16.02
AND 16.03
ANDNOT 16.04
ANDNOT 16.11
OR W175.01
AND W396.14
OUT W175.01
; rung 109
LD 16.02
AND 16.03
ANDNOT 16.04
ANDNOT 16.11
OR W175.02
AND W396.14
OUT W175.02
; rung 110
LDNOT 16.02
ANDNOT 16.03
AND 16.04
ANDNOT 16.11
OR W175.03
AND W396.14
OUT W175.03
; rung 111
LD 16.02
ANDNOT 16.03
AND 16.04
ANDNOT 16.11
OR W175.04
AND W396.14
OUT W175.04
; rung 112
LDNOT 16.02
AND 16.03
AND 16.04
ANDNOT 16.11
OR W175.05
AND W396.14
OUT W175.05
; rung 113
LD 16.02
AND 16.03
AND 16.04
ANDNOT 16.11
OR W175.06
AND W396.14
OUT W175.06
; rung 114
LDNOT 16.02
ANDNOT 16.03
ANDNOT 16.04
AND 16.11
OR W175.07
AND W396.14
OUT W175.07
; rung 115
LD 16.02
ANDNOT 16.03
ANDNOT 16.04
AND 16.11
OR W175.08
AND W396.14
OUT W175.08
; rung 116
LDNOT 16.02
AND 16.03
ANDNOT 16.04
AND 16.11
OR W175.09
AND W396.14
OUT W175.09

; rung 117
LD 16.02
AND 16.03
ANDNOT 16.04
AND 16.11
OR W175.10
AND W396.14
OUT W175.10
; rung 118
LDNOT 16.02
ANDNOT 16.03
AND 16.04
AND 16.11
OR W175.11
AND W396.14
OUT W175.11
; rung 119
LD 16.02
ANDNOT 16.03
AND 16.04
AND 16.11
OR W175.12
AND W396.14
OUT W175.12
; rung 120
LDNOT 16.02
AND 16.03
AND 16.04
AND 16.11
OR W175.13
AND W396.14
OUT W175.13
; rung 121
LD 16.02
AND 16.03
AND 16.04
AND 16.11
OR W175.14
AND W396.14
OUT W175.14
; rung 122
LDNOT 4.04
AND H2.09
OR W82.12
AND W396.14
OUT W82.12
; rung 123: 押出機ﾓｰﾀ電流値定格以上時画面ランプのみ点灯 ＜ﾄﾙｸ定格以上に変更 byAHT＞
LD 10.06
AND>=(325) D3429 #1000
OUT W53.10
; rung 124
LD 10.07
AND>=(325) D3425 #1000
OUT W53.11
; rung 125
LD 10.08
AND>=(325) D3424 #1000
OUT W53.12
; rung 126
LD 10.09
AND>=(325) D3427 #1000
OUT W53.13

; rung 127
LD 10.10
AND>=(325) D3428 #1000
OUT W53.14
; rung 128
LD 10.11
AND>=(325) D3426 #1000
OUT W53.15
; rung 129: ----- 警報２ -----
LDNOT W436.08
ANDNOT W436.09
ANDNOT W436.10
ANDNOT W436.11
ANDNOT W436.12
ANDNOT W436.13
ANDNOT W436.14
ANDNOT W436.15
OUTNOT W80.02
; rung 130
LD T0511
OUT TR0
AND W80.02
TIM 0498 #50
LD TR0
LD T0498
OR W223.01
ANDLD
ANDNOT W227.01
OUT W223.01
LD TR0
LD W223.01
AND W216.10
OR W225.01
ANDLD
ANDNOT W227.01
OUT W225.01
AND W394.13
OUT W227.01
LD TR0
LD P_1s
OR W225.01
ANDLD
AND W223.01
OUT W221.01
; rung 131: ----- 警報３ ----- / 原料供給装置の異常は下記の場合警報 / ・各ﾀﾞﾝﾊﾟ開閉信号がONしない場合 / ・下限ONして30sec経過しても下限がOFFしない場合 / ・ﾊﾟｰｼﾞ時ﾊﾟｰｼﾞﾀﾞﾝﾊﾟ開閉LSがONしない場合
LD 1.00
ANDNOT 5.04
LDNOT 1.00
ANDNOT 5.05
ORLD
LD T0470
ANDNOT W227.02
ORLD
AND T0511
AND H2.00
TIM 0470 #50
AND T0470
OUT W121.15
; rung 132
LD 1.01
ANDNOT 5.06
LDNOT 1.01
ANDNOT 5.07
ORLD
LD T0471
ANDNOT W227.02
ORLD
AND T0511
AND H2.01
TIM 0471 #50
AND T0471
OUT W126.15

; rung 133
LD 1.02
ANDNOT 5.08
LDNOT 1.02
ANDNOT 5.09
ORLD
LD T0472
ANDNOT W227.02
ORLD
AND T0511
AND H2.02
TIM 0472 #50
AND T0472
OUT W131.15
; rung 134
LD 1.03
ANDNOT 5.10
LDNOT 1.03
ANDNOT 5.11
ORLD
LD T0473
ANDNOT W227.02
ORLD
AND T0511
AND H2.03
TIM 0473 #50
AND T0473
OUT W136.15
; rung 135
LD 1.04
ANDNOT 5.12
LDNOT 1.04
ANDNOT 5.13
ORLD
LD T0474
ANDNOT W227.02
ORLD
AND T0511
AND H2.04
TIM 0474 #50
AND T0474
OUT W141.15
; rung 136
LD 1.05
ANDNOT 5.14
LDNOT 1.05
ANDNOT 5.15
ORLD
LD T0475
ANDNOT W227.02
ORLD
AND T0511
AND H2.05
TIM 0475 #50
AND T0475
OUT W146.15
; rung 137
LDNOT W121.15
ANDNOT W126.15
ANDNOT W131.15
ANDNOT W136.15
ANDNOT W141.15
ANDNOT W146.15
OUTNOT W396.12
; rung 138
LD W84.02
AND W121.02
LD W84.03
AND 10.06
ANDNOT W156.14
ORLD
LD T0480
LDNOT W156.14
AND 10.06
AND W84.03
ORLD
ANDNOT W227.02
ORLD
LD T0130
ORNOT H2.14
ANDLD
AND T0511
AND H2.00
TIM 0480 #600
LD T0480
LDNOT W156.14
AND W84.03
ORLD
ANDLD
OUT W121.12
; rung 139
LD W121.12
DIFU(013) W511.00

; rung 140
LD W84.06
AND W126.02
LD W84.07
AND 10.07
ANDNOT T0506
ORLD
LD T0481
LDNOT T0506
AND 10.07
AND W84.07
ORLD
ANDNOT W227.02
ORLD
LD T0131
ORNOT H2.14
ANDLD
AND T0511
AND H2.01
TIM 0481 #600
LD T0481
LDNOT T0506
AND W84.07
ORLD
ANDLD
OUT W126.12
; rung 141
LD W126.12
DIFU(013) W511.01
; rung 142
LD W84.10
AND W131.02
LD W84.11
AND 10.08
ANDNOT W156.15
ORLD
LD T0482
LDNOT W156.15
AND 10.08
AND W84.11
ORLD
ANDNOT W227.02
ORLD
LD T0132
ORNOT H2.14
ANDLD
AND T0511
AND H2.02
TIM 0482 #600
LD T0482
LDNOT W156.15
AND W84.11
ORLD
ANDLD
OUT W131.12
; rung 143
LD W131.12
DIFU(013) W511.02
; rung 144
LD W84.14
AND W136.02
LD W84.15
AND 10.09
ANDNOT T0505
ORLD
LD T0483
LDNOT T0505
AND 10.09
AND W84.15
ORLD
ANDNOT W227.02
ORLD
LD T0133
ORNOT H2.14
ANDLD
AND T0511
AND H2.03
TIM 0483 #600
LD T0483
LDNOT T0505
AND W84.15
ORLD
ANDLD
OUT W136.12
; rung 145
LD W136.12
DIFU(013) W511.03
; rung 146
LD W85.02
AND W141.02
LD W85.03
AND 10.10
ANDNOT T0508
ORLD
LD T0484
LDNOT T0508
AND 10.10
AND W85.03
ORLD
ANDNOT W227.02
ORLD
LD T0134
ORNOT H2.14
ANDLD
AND T0511
AND H2.04
TIM 0484 #600
LD T0484
LDNOT T0508
AND W85.03
ORLD
ANDLD
OUT W141.12
; rung 147
LD W141.12
DIFU(013) W511.04

; rung 148
LD W85.06
AND W146.02
LD W85.07
AND 10.11
ANDNOT T0507
ORLD
LD T0485
LDNOT T0507
AND 10.11
AND W85.07
ORLD
ANDNOT W227.02
ORLD
LD T0135
ORNOT H2.14
ANDLD
AND T0511
AND H2.05
TIM 0485 #600
LD T0485
LDNOT T0507
AND W85.07
ORLD
ANDLD
OUT W146.12
; rung 149
LD W146.12
DIFU(013) W511.05
; rung 150
LDNOT W121.12
ANDNOT W126.12
ANDNOT W131.12
ANDNOT W136.12
ANDNOT W141.12
ANDNOT W146.12
OUTNOT W396.13
; rung 151
LDNOT W511.00
ANDNOT W511.01
ANDNOT W511.02
ANDNOT W511.03
ANDNOT W511.04
ANDNOT W511.05
OUTNOT W510.15
; rung 152
LD W396.13
OR 427.07
AND T0511
ANDNOT W227.02
OUT 427.07
; rung 153
LD T0511
ANDNOT W227.02
OUT TR0
LD T0478
OR W81.14
ANDLD
OUT W81.14
LD TR0
LD T0479
OR W81.15
ANDLD
OUT W81.15
LD TR0
LD T0468
OR W82.02
ANDLD
OUT W82.02
LD TR0
LD T0469
OR W82.03
ANDLD
OUT W82.03
; rung 154
LDNOT W81.14
ANDNOT W81.15
ANDNOT W82.02
ANDNOT W82.03
OUTNOT W82.04

; rung 155
LD T0511
ANDNOT W227.02
OUT TR0
LDNOT 444.00
OR W53.00
ANDLD
OUT W53.00
LD TR0
LDNOT 444.01
OR W53.01
ANDLD
OUT W53.01
LD TR0
LDNOT 444.02
OR W53.02
ANDLD
OUT W53.02
; rung 156
LD T0511
ANDNOT W227.02
OUT TR0
LDNOT 444.03
OR W53.03
ANDLD
OUT W53.03
LD TR0
LDNOT 444.04
OR W53.04
ANDLD
OUT W53.04
LD TR0
LDNOT 444.05
OR W53.05
ANDLD
OUT W53.05
; rung 157
LDNOT W53.00
ANDNOT W53.01
ANDNOT W53.02
ANDNOT W53.03
ANDNOT W53.04
ANDNOT W53.05
OUTNOT W53.06
; rung 158
LD 413.15
OR W53.09
AND T0511
ANDNOT W227.02
OUT W53.09

; rung 159
LD T0511
OUT TR0
LD W396.12
OR W396.13
OR W82.04
OR W53.06
OR 413.15
OR W223.02
OR 6.02
ANDLD
ANDNOT W227.02
OUT W223.02
LD TR0
LD W223.02
AND W216.10
OR W225.02
ANDLD
ANDNOT W510.15
ANDNOT W227.02
OUT W225.02
AND W394.13
OUT W227.02
LD TR0
LD P_1s
OR W225.02
ANDLD
AND W223.02
OUT W221.02
; rung 160: ----- 警報４ -----
LDNOT W436.00
ANDNOT W436.01
ANDNOT W436.02
ANDNOT W436.03
ANDNOT W436.04
ANDNOT W436.05
ANDNOT W436.06
ANDNOT W436.07
OUTNOT W80.03
; rung 161
LD T0511
OUT TR0
AND W80.03
TIM 0499 #600
LD TR0
LD T0499
OR W223.03
ANDLD
ANDNOT W227.03
OUT W223.03
LD TR0
LD W223.03
AND W216.10
OR W225.03
ANDLD
ANDNOT W227.03
OUT W225.03
AND W394.13
OUT W227.03
LD TR0
LD P_1s
OR W225.03
ANDLD
AND W223.03
OUT W221.03
; rung 162: ----- 警報５ -----
LDNOT W435.00
ANDNOT W435.01
ANDNOT W435.02
ANDNOT W435.03
ANDNOT W435.04
ANDNOT W435.05
ANDNOT W435.06
ANDNOT W435.07
OUTNOT W80.04

; rung 163
LD T0511
OUT TR0
LD W80.04
OR W223.04
ANDLD
ANDNOT W227.04
OUT W223.04
LD TR0
LD W223.04
AND W216.10
OR W225.04
ANDLD
ANDNOT W227.04
OUT W225.04
AND W394.13
OUT W227.04
LD TR0
LD P_1s
OR W225.04
ANDLD
AND W223.04
OUT W221.04
; rung 164: ----- 警報６ -----
LDNOT W435.08
ANDNOT W435.09
ANDNOT W435.10
ANDNOT W435.11
ANDNOT W435.12
ANDNOT W435.13
ANDNOT W435.14
ANDNOT W435.15
OUTNOT W80.05
; rung 165
LD T0511
OUT TR0
LD W80.05
OR W223.05
ANDLD
ANDNOT W227.05
OUT W223.05
LD TR0
LD W223.05
AND W216.10
OR W225.05
ANDLD
ANDNOT W227.05
OUT W225.05
AND W394.13
OUT W227.05
LD TR0
LD P_1s
OR W225.05
ANDLD
AND W223.05
OUT W221.05
; rung 166: ----- 警報７ -----
LDNOT W437.08
ANDNOT W437.09
ANDNOT W437.10
ANDNOT W437.11
ANDNOT W437.12
ANDNOT W437.13
ANDNOT W437.14
ANDNOT W437.15
OUTNOT W80.06
; rung 167
LD T0511
OUT TR0
LD W80.06
OR W223.06
ANDLD
ANDNOT W227.06
OUT W223.06
LD TR0
LD W223.06
AND W216.10
OR W225.06
ANDLD
ANDNOT W227.06
OUT W225.06
AND W394.13
OUT W227.06
LD TR0
LD P_1s
OR W225.06
ANDLD
AND W223.06
OUT W221.06

; rung 168: ----- 警報８ -----
LDNOT W437.00
ANDNOT W437.01
ANDNOT W437.02
ANDNOT W437.03
ANDNOT W437.04
ANDNOT W437.05
ANDNOT W437.06
ANDNOT W437.07
OUTNOT W80.07
; rung 169
LD T0511
OUT TR0
LD W80.07
OR W223.07
ANDLD
ANDNOT W227.07
OUT W223.07
LD TR0
LD W223.07
AND W216.10
OR W225.07
ANDLD
ANDNOT W227.07
OUT W225.07
AND W394.13
OUT W227.07
LD TR0
LD P_1s
OR W225.07
ANDLD
AND W223.07
OUT W221.07
; rung 170: ----- 警報９ -----
LD P_On
OUTNOT W80.08
; rung 171
LD T0511
OUT TR0
LD W80.08
AND P_Off
OR W223.08
ANDLD
ANDNOT W227.08
OUT W223.08
LD TR0
LD W223.08
AND W216.10
OR W225.08
ANDLD
ANDNOT W227.08
OUT W225.08
AND W394.13
OUT W227.08
LD TR0
LD P_1s
OR W225.08
ANDLD
AND W223.08
OUT W221.08
; rung 172: ----- 警報10 -----
LD P_On
OUTNOT W80.09

; rung 173
LD T0511
OUT TR0
LD W80.09
AND P_Off
OR W223.09
ANDLD
ANDNOT W227.09
OUT W223.09
LD TR0
LD W223.09
AND W216.10
OR W225.09
ANDLD
ANDNOT W227.09
OUT W225.09
AND W394.13
OUT W227.09
LD TR0
LD P_1s
OR W225.09
ANDLD
AND W223.09
OUT W221.09
; rung 174: ----- 警報11 -----
LDNOT T0998
ANDNOT T0985
ANDNOT W400.00
ANDNOT W434.00
OUTNOT W284.14
; rung 175
LDNOT T0984
ANDNOT T0983
ANDNOT W410.00
ANDNOT W434.01
OUTNOT W284.15
; rung 176
LD T0511
OUT TR0
LD W284.14
OR W284.15
OR W223.10
ANDLD
ANDNOT W227.10
OUT W223.10
OUT 427.09
LD TR0
LD W223.10
AND W216.10
OR W225.10
ANDLD
ANDNOT W227.10
OUT W225.10
AND W394.13
OUT W227.10
LD TR0
LD P_1s
OR W225.10
ANDLD
AND W223.10
OUT W221.10

; rung 177
LD W223.10
OUT TR0
LD W284.14
OR W97.09
ANDLD
OUT W97.09
LD TR0
LD T0998
OR T0985
OR W97.10
ANDLD
OUT W97.10
LD TR0
LD W400.00
OR W97.11
ANDLD
OUT W97.11
LD TR0
LD W284.15
OR W97.12
ANDLD
OUT W97.12
LD TR0
LD T0984
OR T0983
OR W97.13
ANDLD
OUT W97.13
LD TR0
LD W410.00
OR W97.14
ANDLD
OUT W97.14
LD TR0
LD P_Off
OR W97.15
ANDLD
OUT W97.15
; rung 178: ----- 警報12 -----
LD T0511
ANDNOT W399.00
AND>(320) D5964 D5977
TIM 0440 #100
AND T0440
OUT W219.00
; rung 179
LD T0511
ANDNOT W399.01
AND>(320) D5963 D5976
TIM 0441 #100
AND T0441
OUT W219.01

; rung 180
LD T0511
ANDNOT W399.01
AND 2050.03
AND<(310) #0 D5970
AND<(310) D5963 D5970
TIM 0446 #100
AND T0446
OUT W219.15
; rung 181
LD T0511
ANDNOT W399.02
AND>(320) D5965 D5978
TIM 0442 #100
AND T0442
OUT W219.02
; rung 182
LD T0511
ANDNOT W399.03
AND>(320) D5967 D5980
TIM 0443 #100
AND T0443
OUT W219.03
; rung 183
LD T0511
ANDNOT W399.04
AND>(320) D5962 D5975
TIM 0444 #100
AND T0444
OUT W219.04
; rung 184
LD T0511
ANDNOT W399.05
AND>(320) D5966 D5979
TIM 0445 #100
AND T0445
OUT W219.05
; rung 185
LDNOT W219.00
ANDNOT W219.01
ANDNOT W219.02
ANDNOT W219.03
ANDNOT W219.04
ANDNOT W219.05
OUTNOT W80.10
; rung 186
LD T0511
OUT TR0
LD W80.10
OR W223.11
ANDLD
ANDNOT W227.11
OUT W223.11
OUT 427.08
LD TR0
LD W223.11
AND W216.10
OR W225.11
ANDLD
ANDNOT W227.11
OUT W225.11
AND W394.13
OUT W227.11
LD TR0
LD P_1s
OR W225.11
ANDLD
AND W223.11
OUT W221.11

; rung 187
LD T0511
OUT TR0
LD W219.00
OR W219.07
ANDLD
ANDNOT W227.11
OUT W219.07
LD TR0
LD W219.01
OR W219.08
ANDLD
ANDNOT W227.11
OUT W219.08
LD TR0
LD W219.02
OR W219.09
ANDLD
ANDNOT W227.11
OUT W219.09
LD TR0
LD W219.03
OR W219.10
ANDLD
ANDNOT W227.11
OUT W219.10
LD TR0
LD W219.04
OR W219.11
ANDLD
ANDNOT W227.11
OUT W219.11
LD TR0
LD W219.05
OR W219.12
ANDLD
ANDNOT W227.11
OUT W219.12
; rung 188: ----- 警報13 -----
LD T0511
OUT TR0
LD 2.06
ORNOT 5.00
LD 13.01
AND 5.01
ORLD
OR 2.07
ORNOT 5.02
LD 13.10
AND 5.03
ORLD
OR T0450
ANDLD
ANDNOT W227.12
OUT TR1
AND T0450
OUT W223.12
LD TR1
TIM 0450 #100
LD TR0
LD T0450
AND W216.10
OR W225.12
ANDLD
ANDNOT W227.12
OUT W225.12
AND W394.13
OUT W227.12
LD TR0
LD P_1s
OR W225.12
ANDLD
AND T0450
OUT W221.12
; rung 189
LD 2.06
OR W53.07
ANDNOT W227.12
AND T0511
OUT W53.07

; rung 190
LDNOT 5.00
OR W364.08
ANDNOT W227.12
AND T0511
OUT W364.08
; rung 191
LD 3.12
AND T0450
AND 5.01
OR W364.09
ANDNOT W227.12
AND T0511
OUT W364.09
; rung 192
LD 2.07
OR W53.08
ANDNOT W227.12
AND T0511
OUT W53.08
; rung 193
LDNOT 5.02
OR W364.10
ANDNOT W227.12
AND T0511
OUT W364.10
; rung 194
LD 3.13
AND T0450
AND 5.03
OR W364.11
ANDNOT W227.12
AND T0511
OUT W364.11
; rung 195: ----- 警報14 ----- / POT.→450mmで0～10V / 架台ﾌﾙｽﾄﾛｰｸ300mmなので計算上,POT.の75～375mmを使用する。 / 故に1.67～8.33Vを外れた場合異常とした。 / 現地にて#0029B→#0250に変更
LD P_On
OUT TR0
AND<(310) #230 2011
AND>(320) #D05 2011
OUTNOT W220.02
LD TR0
AND<(310) #230 2012
AND>(320) #D05 2012
OUTNOT W220.03
LD TR0
AND<(310) #230 2013
AND>(320) #D05 2013
OUTNOT W220.00
LD TR0
AND<(310) #230 2014
AND>(320) #D05 2014
OUTNOT W220.01
; rung 196
LD W220.02
TIM 0434 #15
; rung 197
LD W220.03
TIM 0435 #15

; rung 198
LD W220.00
TIM 0432 #15
; rung 199
LD W220.01
TIM 0433 #15
; rung 200
LDNOT W227.13
OUT TR0
LD T0434
OR W83.02
ANDLD
OUT W83.02
LD TR0
LD T0435
OR W83.03
ANDLD
OUT W83.03
LD TR0
LD T0432
OR W83.00
ANDLD
OUT W83.00
LD TR0
LD T0433
OR W83.01
ANDLD
OUT W83.01
; rung 201
LDNOT W83.00
ANDNOT W83.01
ANDNOT W83.02
ANDNOT W83.03
OUTNOT W83.04
; rung 202
LD T0511
ANDNOT W227.13
OUT TR0
LD T0451
OR W83.05
ANDLD
OUT W83.05
LD TR0
LD T0452
OR W83.06
ANDLD
OUT W83.06
LD TR0
LD T0453
OR W83.07
ANDLD
OUT W83.07
LD TR0
LD T0454
OR W83.08
ANDLD
OUT W83.08

; rung 203
LD T0511
ANDNOT W227.13
OUT TR0
LD T0455
OR W83.09
ANDLD
OUT W83.09
LD TR0
LD T0456
OR W83.10
ANDLD
OUT W83.10
LD TR0
LD T0457
OR W83.11
ANDLD
OUT W83.11
LD TR0
LD T0458
OR W83.12
ANDLD
OUT W83.12
; rung 204
LDNOT W83.05
ANDNOT W83.06
ANDNOT W83.07
ANDNOT W83.08
ANDNOT W83.09
ANDNOT W83.10
ANDNOT W83.11
ANDNOT W83.12
OUTNOT W83.13
; rung 205
LD T0511
OUT TR0
LD 2.08
OR W210.10
OR W83.04
OR W83.13
OR W223.13
ANDLD
ANDNOT W227.13
OUT W223.13
LD TR0
LD W223.13
AND W216.10
OR W225.13
ANDLD
ANDNOT W227.13
OUT W225.13
AND W394.13
OUT W227.13
LD TR0
LD P_1s
OR W225.13
ANDLD
AND W223.13
OUT W221.13
; rung 206
LD 2.08
OR W398.14
AND T0511
ANDNOT W227.13
OUT W398.14
; rung 207
LD W210.10
OR W398.15
AND T0511
ANDNOT W227.13
OUT W398.15

; rung 208: ----- 警報15 -----
LD 4.00
AND 4.01
AND 4.02
AND 4.03
AND 4.04
AND 4.05
AND 4.06
OUT W80.12
; rung 209
LD T0511
OUT TR0
LDNOT W80.12
OR W223.14
ANDLD
ANDNOT W227.14
OUT W223.14
LD TR0
LD W223.14
AND W216.10
OR W225.14
ANDLD
ANDNOT W227.14
OUT W225.14
AND W394.13
OUT W227.14
LD TR0
LD P_1s
OR W225.14
ANDLD
AND W223.14
OUT W221.14
; rung 210: ----- 警報16 -----
LDNOT W223.15
AND=(300) #0 A418
OUT W216.15
MOV(021) #8140 D270

; rung 211
LD P_On
OUT TR0
AND A418.09
MOV(021) #8258 D270
LD TR0
AND A418.08
MOV(021) #8257 D270
LD TR0
AND A418.07
MOV(021) #8256 D270
LD TR0
AND A418.06
MOV(021) #8255 D270
LD TR0
AND A418.05
MOV(021) #8254 D270
LD TR0
AND A418.04
MOV(021) #8253 D270
LD TR0
AND A418.03
MOV(021) #8252 D270
LD TR0
AND A418.02
MOV(021) #8251 D270
LD TR0
AND A418.01
MOV(021) #8250 D270
LD TR0
AND A418.00
MOV(021) #824F D270
; rung 212
LD P_On
OUT TR0
AND A418.10
MOV(021) #8260 D270
LD TR0
AND A418.11
MOV(021) #8261 D270
LD TR0
AND A418.12
MOV(021) #8262 D270
LD TR0
AND A418.13
MOV(021) #8263 D270

; rung 213
LD P_On
OUT TR0
LD T0092
ANDNOT W216.15
OR W223.15
ANDLD
ANDNOT W227.15
OUT W223.15
LD TR0
LD W223.15
AND W216.10
OR W225.15
ANDLD
ANDNOT W227.15
OUT W225.15
AND W394.13
OUT W227.15
LD TR0
LD P_1s
OR W225.15
ANDLD
AND W223.15
OUT W221.15
; rung 214: ----- 警報17 -----
LD T0511
OUT TR0
LD H17.13
OR W224.00
ANDLD
ANDNOT W228.00
OUT W224.00
LD TR0
LD W224.00
AND W216.10
OR W226.00
ANDLD
ANDNOT W228.00
OUT W226.00
AND W394.13
OUT W228.00
LD TR0
LD P_1s
OR W226.00
ANDLD
AND W224.00
OUT W222.00
; rung 215: ----- 警報18 -----
LD P_On
OUT TR0
LD P_Low_Battery
OR W224.01
ANDLD
ANDNOT W228.01
OUT W224.01
LD TR0
LD W224.01
AND W216.10
OR W226.01
ANDLD
ANDNOT W228.01
OUT W226.01
AND W394.13
OUT W228.01
LD TR0
LD P_1s
OR W226.01
ANDLD
AND W224.01
OUT W222.01
; rung 216: ----- 警報19 -----
LDNOT 2.00
ANDNOT 2.01
ANDNOT 2.02
ANDNOT 2.03
ANDNOT 2.04
ANDNOT 2.05
OUTNOT W80.13

; rung 217
LD T0511
OUT TR0
LD W80.13
OR W224.02
ANDLD
ANDNOT W228.02
OUT W224.02
LD TR0
LD W224.02
AND W216.10
OR W226.02
ANDLD
ANDNOT W228.02
OUT W226.02
AND W394.13
OUT W228.02
LD TR0
LD P_1s
OR W226.02
ANDLD
AND W224.02
OUT W222.02
; rung 218
LD T0511
ANDNOT W228.02
OUT TR0
LD 2.00
OR W80.14
ANDLD
OUT W80.14
LD TR0
LD 2.01
OR W80.15
ANDLD
OUT W80.15
LD TR0
LD 2.02
OR W81.00
ANDLD
OUT W81.00
LD TR0
LD 2.03
OR W81.01
ANDLD
OUT W81.01
LD TR0
LD 2.04
OR W81.02
ANDLD
OUT W81.02
LD TR0
LD 2.05
OR W81.03
ANDLD
OUT W81.03
; rung 219: ----- 警報20 -----
LD T0511
OUT TR0
LD 3.15
OR W224.03
ANDLD
ANDNOT W228.03
OUT W224.03
LD TR0
LD W224.03
AND W216.10
OR W226.03
ANDLD
ANDNOT W228.03
OUT W226.03
AND W394.13
OUT W228.03
LD TR0
LD P_1s
OR W226.03
ANDLD
AND W224.03
OUT W222.03

; rung 220
LD W224.03
AND T0511
OUT 426.00
; rung 221: ----- 警報21 -----
LDNOT T0242
ANDNOT T0243
ANDNOT T0244
ANDNOT T0245
ANDNOT T0246
ANDNOT T0247
ANDNOT T0248
ANDNOT T0249
ANDNOT T0250
ANDNOT T0251
ANDNOT T0252
ANDNOT T0253
OUTNOT W500.09
; rung 222
LD T0511
OUT TR0
LD W500.09
OR W224.04
ANDLD
ANDNOT W228.04
OUT W224.04
LD TR0
LD W224.04
AND W216.10
OR W226.04
ANDLD
ANDNOT W228.04
OUT W226.04
AND W394.13
OUT W228.04
LD TR0
LD P_1s
OR W226.04
ANDLD
AND W224.04
OUT W222.04
; rung 223
LD T0511
ANDNOT W228.04
OUT TR0
LD T0242
OR W502.00
ANDLD
OUT W502.00
LD TR0
LD T0243
OR W502.01
ANDLD
OUT W502.01
LD TR0
LD T0244
OR W502.02
ANDLD
OUT W502.02
LD TR0
LD T0245
OR W502.03
ANDLD
OUT W502.03
LD TR0
LD T0246
OR W502.04
ANDLD
OUT W502.04
LD TR0
LD T0247
OR W502.05
ANDLD
OUT W502.05

; rung 224
LD T0511
ANDNOT W228.04
OUT TR0
LD T0248
OR W502.06
ANDLD
OUT W502.06
LD TR0
LD T0249
OR W502.07
ANDLD
OUT W502.07
LD TR0
LD T0250
OR W502.08
ANDLD
OUT W502.08
LD TR0
LD T0251
OR W502.09
ANDLD
OUT W502.09
LD TR0
LD T0252
OR W502.10
ANDLD
OUT W502.10
LD TR0
LD T0253
OR W502.11
ANDLD
OUT W502.11
; rung 225: ----- 警報22 -----
LDNOT T0254
ANDNOT T0255
ANDNOT T0256
ANDNOT T0257
ANDNOT T0258
ANDNOT T0259
OUTNOT W503.06
; rung 226
LD T0511
OUT TR0
LD W503.06
OR W224.05
ANDLD
ANDNOT W228.05
OUT W224.05
LD TR0
LD W224.05
AND W216.10
OR W226.05
ANDLD
ANDNOT W228.05
OUT W226.05
AND W394.13
OUT W228.05
LD TR0
LD P_1s
OR W226.05
ANDLD
AND W224.05
OUT W222.05

; rung 227
LD T0511
ANDNOT W228.05
OUT TR0
LD T0254
OR W503.00
ANDLD
OUT W503.00
LD TR0
LD T0255
OR W503.01
ANDLD
OUT W503.01
LD TR0
LD T0256
OR W503.02
ANDLD
OUT W503.02
LD TR0
LD T0257
OR W503.03
ANDLD
OUT W503.03
LD TR0
LD T0258
OR W503.04
ANDLD
OUT W503.04
LD TR0
LD T0259
OR W503.05
ANDLD
OUT W503.05
; rung 228: ----- 警報23 -----
LD 400.15
ORNOT 420.06
OUT TR0
LDNOT 4.07
OR W224.06
ANDLD
ANDNOT W228.06
OUT W224.06
LD TR0
LD W224.06
AND W216.10
OR W226.06
ANDLD
ANDNOT W228.06
OUT W226.06
AND W394.13
OUT W228.06
LD TR0
LD P_1s
OR W226.06
ANDLD
AND W224.06
OUT W222.06
; rung 229: ----- 警報24 -----
LD P_On
OUT TR0
LD 3.00
OR W224.07
ANDLD
ANDNOT W228.07
OUT W224.07
LD TR0
LD W224.07
AND W216.10
OR W226.07
ANDLD
ANDNOT W228.07
OUT W226.07
AND W394.13
OUT W228.07
LD TR0
LD P_1s
OR W226.07
ANDLD
AND W224.07
OUT W222.07

; rung 230
LD 3.00
OR W216.06
ANDNOT W228.07
OUT W216.06
; rung 231
LD P_Off
OR W216.07
ANDNOT W228.07
OUT W216.07
; rung 232: ----- 警報25 -----
LD 36.00
TIM 0264 #30
; rung 233
LD 36.03
TIM 0265 #30
; rung 234
LD 36.06
TIM 0266 #30
; rung 235
LD 36.09
TIM 0267 #30
; rung 236
LD 36.12
TIM 0268 #30
; rung 237
LD 36.15
TIM 0269 #30
; rung 238
LDNOT T0264
ANDNOT T0265
ANDNOT T0266
ANDNOT T0267
ANDNOT T0268
ANDNOT T0269
OUTNOT W99.00

; rung 239
LD T0511
OUT TR0
LD W99.00
OR W224.08
ANDLD
ANDNOT W228.08
OUT W224.08
LD TR0
LD W224.08
AND W216.10
OR W226.08
ANDLD
ANDNOT W228.08
OUT W226.08
AND W394.13
OUT W228.08
LD TR0
LD P_1s
OR W226.08
ANDLD
AND W224.08
OUT W222.08
; rung 240
LD T0511
ANDNOT W228.08
OUT TR0
LD T0264
OR W99.01
ANDLD
OUT W99.01
LD TR0
LD T0265
OR W99.02
ANDLD
OUT W99.02
LD TR0
LD T0266
OR W99.03
ANDLD
OUT W99.03
LD TR0
LD T0267
OR W99.04
ANDLD
OUT W99.04
LD TR0
LD T0268
OR W99.05
ANDLD
OUT W99.05
LD TR0
LD T0269
OR W99.06
ANDLD
OUT W99.06
; rung 241: ----- 警報26 -----
LD W54.12
OR W54.07
ANDNOT 10.07
ANDNOT W157.12
ANDNOT H17.09
ANDNOT W86.10
ANDNOT W204.00
OUT W54.07
; rung 242
LD W54.07
CLC(041)
-BC(416) D3658 D258 D3668

; rung 243
LD W54.07
OUT TR0
AND C0097
++B(594) D258
LD TR0
AND>=(325) D258 D3658
OUT W54.08
OUT W357.08
MOV(021) D3658 D258
; rung 244
LDNOT W54.07
MOV(021) #0 D258
MOV(021) #0 D3668
; rung 245
LD W54.08
OR H17.09
ANDNOT W157.12
ANDNOT 10.07
ANDNOT W86.10
OUT H17.09
; rung 246
LD W54.13
OR W54.10
ANDNOT 10.09
ANDNOT W157.12
ANDNOT H17.10
ANDNOT W86.10
ANDNOT W204.00
OUT W54.10
; rung 247
LD W54.10
CLC(041)
-BC(416) D3659 D259 D3669
; rung 248
LD W54.10
OUT TR0
AND C0097
++B(594) D259
LD TR0
AND>=(325) D259 D3659
OUT W54.11
OUT W357.09
MOV(021) D3659 D259

; rung 249
LDNOT W54.10
MOV(021) #0 D259
MOV(021) #0 D3669
; rung 250
LD W54.11
OR H17.10
ANDNOT W157.12
ANDNOT 10.09
ANDNOT W86.10
OUT H17.10
; rung 251
LD T0511
ANDNOT W204.00
OUT TR0
LD H17.09
OR H17.10
OR W224.09
ANDLD
ANDNOT W228.09
OUT W224.09
LD TR0
LD W224.09
AND W216.10
OR W226.09
ANDLD
ANDNOT W228.09
OUT W226.09
AND W394.13
OUT W228.09
LD TR0
LD P_1s
OR W226.09
ANDLD
AND W224.09
OUT W222.09
; rung 252: ----- 警報27 -----
LD T0094
AND=(300) #0 D2880
AND=(300) #0 D2881
AND=(300) #0 D2882
AND=(300) #0 D2883
AND=(300) #0 D2884
OUT W83.15
; rung 253
LD T0511
OUT TR0
LD T0094
ANDNOT W83.15
OR W224.10
ANDLD
ANDNOT W228.10
OUT W224.10
LD TR0
LD W224.10
AND W216.10
OR W226.10
ANDLD
ANDNOT W228.10
OUT W226.10
AND W394.13
OUT W228.10
LD TR0
LD P_1s
OR W226.10
ANDLD
AND W224.10
OUT W222.10
; rung 254
LD P_Off
OUT W217.15

; rung 255: ----- 警報28 -----
LD T0511
OUT TR0
LD 17.15
OR W224.11
ANDLD
ANDNOT W228.11
OUT W224.11
LD TR0
LD W224.11
AND W216.10
OR W226.11
ANDLD
ANDNOT W228.11
OUT W226.11
AND W394.13
OUT W228.11
LD TR0
LD P_1s
OR W226.11
ANDLD
AND W224.11
OUT W222.11
; rung 256: ----- 警報29 -----
LD P_On
OUT TR0
LD W45.04
OR W224.12
ANDLD
ANDNOT W228.12
OUT W224.12
LD TR0
LD W224.12
AND W216.10
OR W226.12
ANDLD
ANDNOT W228.12
OUT W226.12
AND W394.13
OUT W228.12
LD TR0
LD P_1s
OR W226.12
ANDLD
AND W224.12
OUT W222.12
; rung 257: ----- 警報30 -----
LDNOT W207.00
ANDNOT W207.01
ANDNOT W207.02
ANDNOT W207.03
ANDNOT W207.04
ANDNOT W207.05
ANDNOT W207.06
ANDNOT W207.07
ANDNOT W207.08
ANDNOT W207.09
ANDNOT W207.10
ANDNOT W207.11
ANDNOT W398.10
ANDNOT W398.11
OUTNOT W207.12
; rung 258
LD T0511
ANDNOT 406.02
AND H80.01
AND 401.10
OUT TR0
LD W207.12
OR W224.13
ANDLD
ANDNOT W228.13
OUT W224.13
LD TR0
LD W224.13
AND W216.10
OR W226.13
ANDLD
ANDNOT W228.13
OUT W226.13
AND W394.13
OUT W228.13
LD TR0
LD P_1s
OR W226.13
ANDLD
AND W224.13
OUT W222.13

; rung 259: ----- 警報31 -----
LD 10.06
OR 10.07
OR 10.08
OR 10.09
OR 10.10
OR 10.11
OR H99.15
ANDNOT W157.12
ANDNOT W70.15
AND H2.09
OUT H99.15
AND 420.06
OUT W74.08
; rung 260
LD W74.08
CLC(041)
-BC(416) D3657 D572 D3667
; rung 261
LD W74.08
OUT TR0
AND C0097
++B(594) D572
LD TR0
AND>=(325) D572 D3657
OUT W357.07
MOV(021) D3657 D572
; rung 262
LDNOT W74.08
MOV(021) #0 D572
MOV(021) #0 D3667
; rung 263
LD 2054.09
MOV(021) D227 D165
MOV(021) D228 D166

; rung 264
LD W71.01
MOV(021) #0 D165
MOV(021) #0 D166
; rung 265
LD W357.07
OR H99.14
ANDNOT W157.12
ANDNOT W70.15
AND 420.06
ANDNOT W228.14
OUT H99.14
; rung 266
LD T0511
OUT TR0
LD H99.14
OR W224.14
ANDLD
ANDNOT W228.14
OUT W224.14
LD TR0
LD W224.14
AND W216.10
OR W226.14
ANDLD
ANDNOT W228.14
OUT W226.14
LD W394.13
OR W70.15
ANDLD
OUT W228.14
LD TR0
LD P_1s
OR W226.14
ANDLD
AND W224.14
OUT W222.14
; rung 267: ----- 警報32 -----
LD T0511
OUT TR0
LD W219.15
OR W224.15
ANDLD
ANDNOT W228.15
OUT W224.15
LD TR0
LD W224.15
AND W216.10
OR W226.15
ANDLD
ANDNOT W228.15
OUT W226.15
AND W394.13
OUT W228.15
LD TR0
LD P_1s
OR W226.15
ANDLD
AND W224.15
OUT W222.15
; rung 268: ----- 警報33 -----
LD T0511
AND 2050.01
LDNOT 2050.00
ORNOT W208.06
ANDLD
ANDNOT T0317
OR C0316
TIM 0317 #7200

; rung 269
LD T0317
LD 2050.00
OR W376.15
OR W208.06
OR P_First_Cycle
CNT 0316 #10
; rung 270
LD T0511
OUT TR0
LD C0316
OR W236.01
ANDLD
ANDNOT W236.03
OUT W236.01
LD TR0
LD W236.01
AND W216.10
OR W236.02
ANDLD
ANDNOT W236.03
OUT W236.02
AND W394.13
OUT W236.03
LD TR0
LD P_1s
OR W236.02
ANDLD
AND W236.01
OUT W236.04
; rung 271: ----- 警報34 -----
LD H99.00
OUT TR0
ANDNOT 36.02
OUT W94.00
LD TR0
ANDNOT 36.05
OUT W94.01
LD TR0
ANDNOT 36.08
OUT W94.02
LD TR0
ANDNOT 36.11
OUT W94.03
LD TR0
ANDNOT 36.14
OUT W94.04
LD TR0
ANDNOT 37.01
OUT W94.05

; rung 272
LD T0511
OUT TR0
LDNOT 36.02
ORNOT 36.05
ORNOT 36.08
ORNOT 36.11
ORNOT 36.14
ORNOT 37.01
ANDLD
ANDNOT H99.02
OUT H99.00
LD TR0
LD H99.00
AND W216.10
OR H99.01
ANDLD
ANDNOT H99.02
OUT H99.01
AND W394.13
OUT H99.02
LD TR0
LD P_1s
OR H99.01
ANDLD
AND H99.00
OUT H99.03
; rung 273
LD W398.10
OR W206.09
AND W224.13
OUT W206.09
; rung 274
LD W207.00
OR W206.10
AND W224.13
OUT W206.10
; rung 275
LD W207.02
OR W206.11
AND W224.13
OUT W206.11
; rung 276
LD W207.04
OR W206.12
AND W224.13
OUT W206.12
; rung 277
LD W207.06
OR W206.13
AND W224.13
OUT W206.13
; rung 278
LD W207.08
OR W206.14
AND W224.13
OUT W206.14

; rung 279
LD W207.10
OR W206.15
AND W224.13
OUT W206.15
; rung 280
LD W398.11
OR W208.09
AND W224.13
OUT W208.09
; rung 281
LD W207.01
OR W208.10
AND W224.13
OUT W208.10
; rung 282
LD W207.03
OR W208.11
AND W224.13
OUT W208.11
; rung 283
LD W207.05
OR W208.12
AND W224.13
OUT W208.12
; rung 284
LD W207.07
OR W208.13
AND W224.13
OUT W208.13
; rung 285
LD W207.09
OR W208.14
AND W224.13
OUT W208.14
; rung 286
LD W207.11
OR W208.15
AND W224.13
OUT W208.15

; rung 287: ----- 警報35 -----
LD T0511
OUT TR0
LDNOT W490.05
OR W236.05
ANDLD
ANDNOT W236.07
OUT W236.05
LD TR0
LD W236.05
AND W216.10
OR W236.06
ANDLD
ANDNOT W236.07
OUT W236.06
AND W394.13
OUT W236.07
LD TR0
LD P_1s
OR W236.06
ANDLD
AND W236.05
OUT W236.08
; rung 288: ----- 警報36 -----
LD P_On
OUT TR0
LD W183.00
OR W236.09
ANDLD
ANDNOT W236.11
OUT W236.09
LD TR0
LD W236.09
AND W216.10
OR W236.10
ANDLD
ANDNOT W236.11
OUT W236.10
AND W394.13
OUT W236.11
LD TR0
LD P_1s
OR W236.10
ANDLD
AND W236.09
OUT W236.12
; rung 289: ----- 警報37 -----
LD P_On
OUT TR0
LD W237.04
OR W237.00
ANDLD
ANDNOT W237.02
OUT W237.00
LD TR0
LD W237.00
AND W216.10
OR W237.01
ANDLD
ANDNOT W237.02
OUT W237.01
AND W394.13
OUT W237.02
LD TR0
LD P_1s
OR W237.01
ANDLD
AND W237.00
OUT W237.03
LD TR0
AND 2050.00
AND 2050.05
AND 2054.11
AND 2054.12
TIM 0160 #4800

### Section RESIN_PRESS_TEMP

; rung 0: ********** 樹脂圧力表示 ********** / 樹脂圧力表示で負側も使用するので-0.5V～10.5Vでｽｹｰﾘﾝｸﾞ(但し10V以上は10Vに丸め込み) / DM削減の為SCLのDM共通にした(011007) / ----- AD取込値嵩上げ用SCLﾃﾞｰﾀ設定 -----
LD P_On
MOV(021) #0 D2920
MOV(021) #0 D2921
MOV(021) #4400 D2922
MOV(021) #1130 D2923
; rung 1: ----- AD値が負のSCLﾃﾞｰﾀ設定 -----
LD P_On
MOV(021) #100 D2927
MOV(021) #0 D2928
MOV(021) #0 D2929
MOV(021) #C8 D2930
; rung 2: ----- AD値が正のSCLﾃﾞｰﾀ設定 -----
LD P_On
MOV(021) #0 D2932
MOV(021) #C8 D2933
MOV(021) #2000 D2934
MOV(021) #1068 D2935

; rung 3: ----- 主材外層樹脂圧力処理 ----- / 0～2000kgf(200.0MPa)/0～10V  200kgf(20MPa)/1V  100kgf(10MPa)/0.5V
LD P_On
CLC(041)
+C(402) 2003 #C8 D2924
SCL(194) D2924 D2920 D2925
; rung 4: AD値が負か判別
LD P_On
AND>(320) #200 D2925
OUT W399.00
; rung 5
LD W399.00
BIN(023) D2925 D2926
SCL(194) D2926 D2927 D2931
MOVD(083) #FFFF #303 D2931
MOV(021) D2931 D5964
; rung 6: AD値正の時
LDNOT W399.00
AND<(310) #4200 D2925
MOV(021) #4200 D2925

; rung 7
LDNOT W399.00
BIN(023) D2925 D2926
SCL(194) D2926 D2932 D2936
MOV(021) D2936 D5964
; rung 8: ----- 粉砕材層樹脂圧力処理 ----- / 0～2000kgf(200.0MPa)/0～10V 200kgf/1V 100kgf/0.5V
LD P_On
CLC(041)
+C(402) 2002 #C8 D2924
SCL(194) D2924 D2920 D2925
; rung 9: AD値が負か判別
LD P_On
AND>(320) #200 D2925
OUT W399.01
; rung 10: AD値が負の時
LD W399.01
BIN(023) D2925 D2926
SCL(194) D2926 D2927 D2931
MOVD(083) #FFFF #303 D2931
MOV(021) D2931 D5963

; rung 11: 'AD値正の時
LDNOT W399.01
AND<(310) #4200 D2925
MOV(021) #4200 D2925
; rung 12
LDNOT W399.01
BIN(023) D2925 D2926
SCL(194) D2926 D2932 D2936
MOV(021) D2936 D5963
; rung 13: ----- ﾊﾞﾘﾔ材層樹脂圧力処理 ----- / 0～2000kgf(200.0MPa)/0～10V 200kgf/1V 100kgf/0.5V
LD P_On
CLC(041)
+C(402) 2004 #C8 D2924
SCL(194) D2924 D2920 D2925
; rung 14: AD値が負か判別
LD P_On
AND>(320) #200 D2925
OUT W399.02

; rung 15: AD値が負の時
LD W399.02
BIN(023) D2925 D2926
SCL(194) D2926 D2927 D2931
MOVD(083) #FFFF #303 D2931
MOV(021) D2931 D5965
; rung 16: AD値正の時
LDNOT W399.02
AND<(310) #4200 D2925
MOV(021) #4200 D2925
; rung 17
LDNOT W399.02
BIN(023) D2925 D2926
SCL(194) D2926 D2932 D2936
MOV(021) D2936 D5965
; rung 18: ----- 接着外層樹脂圧力処理 ----- / 0～2000kgf(200.0MPa)/0～10V 200kgf/1V 100kgf/0.5V
LD P_On
CLC(041)
+C(402) 2006 #C8 D2924
SCL(194) D2924 D2920 D2925

; rung 19: AD値が負か判別
LD P_On
AND>(320) #200 D2925
OUT W399.03
; rung 20: AD値が負の時
LD W399.03
BIN(023) D2925 D2926
SCL(194) D2926 D2927 D2931
MOVD(083) #FFFF #303 D2931
MOV(021) D2931 D5967
; rung 21: AD値正の時
LDNOT W399.03
AND<(310) #4200 D2925
MOV(021) #4200 D2925
; rung 22
LDNOT W399.03
BIN(023) D2925 D2926
SCL(194) D2926 D2932 D2936
MOV(021) D2936 D5967

; rung 23: ----- 主材内層樹脂圧力処理 ----- / 0～2000kgf(200.0MPa)/0～10V 200kgf/1V 100kgf/0.5V
LD P_On
CLC(041)
+C(402) 2001 #C8 D2924
SCL(194) D2924 D2920 D2925
; rung 24: AD値が負か判別
LD P_On
AND>(320) #200 D2925
OUT W399.04
; rung 25: AD値が負の時
LD W399.04
BIN(023) D2925 D2926
SCL(194) D2926 D2927 D2931
MOVD(083) #FFFF #303 D2931
MOV(021) D2931 D5962
; rung 26: AD値正の時
LDNOT W399.04
AND<(310) #4200 D2925
MOV(021) #4200 D2925

; rung 27
LDNOT W399.04
BIN(023) D2925 D2926
SCL(194) D2926 D2932 D2936
MOV(021) D2936 D5962
; rung 28: ----- 接着内層樹脂圧力処理 ----- / 0～2000kgf(200.0MPa)/0～10V 200kgf/1V 100kgf/0.5V
LD P_On
CLC(041)
+C(402) 2005 #C8 D2924
SCL(194) D2924 D2920 D2925
; rung 29: AD値が負か判別
LD P_On
AND>(320) #200 D2925
OUT W399.05
; rung 30: AD値が負の時
LD W399.05
BIN(023) D2925 D2926
SCL(194) D2926 D2927 D2931
MOVD(083) #FFFF #303 D2931
MOV(021) D2931 D5966

; rung 31: AD値正の時
LDNOT W399.05
AND<(310) #4200 D2925
MOV(021) #4200 D2925
; rung 32
LDNOT W399.05
BIN(023) D2925 D2926
SCL(194) D2926 D2932 D2936
MOV(021) D2936 D5966
; rung 33: ********** 樹脂温度上下限処理 **********(M) / 前回は条件として自動3の時だったが、今回自動時に変更
LD 401.10
AND 401.09
ANDNOT 420.09
AND W204.06
OUT W501.12
; rung 34: ---------- 主内樹脂温度上下限処理 ----------
LD W501.12
AND 10.06
OUT TR0
AND>=(325) D18446 D3507
TIM 0242 #50
LD TR0
AND<=(315) D18446 D3508
TIM 0243 #50
; rung 35: ---------- 粉砕樹脂温度上下限処理 ----------
LD W501.12
AND 10.07
OUT TR0
AND>=(325) D18447 D3509
TIM 0244 #50
LD TR0
AND<=(315) D18447 D3510
TIM 0245 #50

; rung 36: ---------- 主外樹脂温度上下限処理 ----------
LD W501.12
AND 10.08
OUT TR0
AND>=(325) D18448 D3511
TIM 0246 #50
LD TR0
AND<=(315) D18448 D3512
TIM 0247 #50
; rung 37: ---------- ﾊﾞﾘﾔ樹脂温度上下限処理 ----------
LD W501.12
AND 10.09
OUT TR0
AND>=(325) D18450 D3513
TIM 0248 #50
LD TR0
AND<=(315) D18450 D3514
TIM 0249 #50
; rung 38: ---------- 接内樹脂温度上下限処理 ----------
LD W501.12
AND 10.10
OUT TR0
AND>=(325) D18451 D3515
TIM 0250 #50
LD TR0
AND<=(315) D18451 D3516
TIM 0251 #50
; rung 39: ---------- 接外樹脂温度上下限処理 ----------
LD W501.12
AND 10.11
OUT TR0
AND>=(325) D18452 D3517
TIM 0252 #50
LD TR0
AND<=(315) D18452 D3518
TIM 0253 #50

### Section EJ1_MAIN

; rung 0: ********** 温調関係処理 **********
LD P_On
TIM 0098 #5
OUT 0.10
; rung 1
LD P_On
BCD(024) D18449 D27
; rung 2: ----- ﾀﾞｲﾋｰﾀ電源入 -----
LD 457.06
OUT 1.07
TIM 0990 #300
; rung 3: ---------- CT相切替 ----------
LD T0999
OUT TR0
ANDNOT T0981
TIM 0980 #3000
LD TR0
AND T0980
TIM 0981 #3000
OUT 0.11
; rung 4: ----- 温調処理 ----- / 温調切で保温選択している場合、押出機盤電源ONで成形機操作盤電源OFFの時、昇温ONするのを変更 / ﾀｲﾏ選択&保温選択時、成形機操作盤電源OFFすると昇温しなくした。
LDNOT W433.00
ANDNOT 2054.01
OUT W433.01
TIM 0095 #30
; rung 5
LDNOT 2054.00
ANDNOT 2054.01
AND T0511
TIM 0460 #30

; rung 6
LD T0197
OR W61.06
OR W433.00
AND T0460
AND T0511
OUT W433.00
; rung 7
LD W433.00
OR 2054.01
LD W362.12
AND H2.15
AND 400.14
ORLD
LD W433.01
ANDNOT T0095
AND T0098
ORLD
ANDNOT 407.00
ANDNOT W223.10
ANDNOT W223.01
AND 3.14
ANDNOT P_First_Cycle
ANDNOT H17.13
AND T0511
TIM 0094 #50
; rung 8: ----- 時差昇温ﾀｲﾏｶｳﾝﾀ ----- / T.UP後、全ｿﾞｰﾝ昇温開始 / ----- 時差昇温ﾀｲﾏ1 ----- / 主材内層,粉砕材層
LD W61.08
AND T0094
OUT TR0
AND C0097
ANDNOT W433.03
@++B(594) D3600
LD TR0
CMP(020) D3600 D3650
LD P_EQ
OR P_GT
OR W433.03
ANDLD
OUT W433.03
MOV(021) D3650 D3600
LD TR0
AND<>(305) D3650 D3604
MOV(021) #0 D3600
LD TR0
MOV(021) D3650 D3604
; rung 9
LDNOT T0094
MOV(021) #0 D3600

; rung 10: ----- 時差昇温ﾀｲﾏ2 ----- / 主材外層,ﾊﾞﾘﾔ材層,接着内層,接着外層
LD W61.08
AND T0094
OUT TR0
AND C0097
ANDNOT W438.06
@++B(594) D3601
LD TR0
CMP(020) D3601 D3651
LD P_EQ
OR P_GT
OR W438.06
ANDLD
OUT W438.06
MOV(021) D3651 D3601
LD TR0
AND<>(305) D3651 D3605
MOV(021) #0 D3601
LD TR0
MOV(021) D3651 D3605
; rung 11
LDNOT T0094
MOV(021) #0 D3601
; rung 12: ----- 昇温完了遅延ﾀｲﾏｶｳﾝﾄ -----
LD W425.00
ORNOT H10.00
LD W425.01
ORNOT H10.01
ANDLD
LD W425.02
ORNOT H10.02
ANDLD
LD W425.03
ORNOT H10.03
ANDLD
LD W425.04
ORNOT H10.04
LD W425.05
ORNOT H10.05
ANDLD
OR P_On
ANDLD
LD W425.06
ORNOT H10.06
ANDLD
LD W425.07
ORNOT H10.07
ANDLD
OUT W434.04
; rung 13
LD W425.08
ORNOT H10.08
LD W425.09
ORNOT H10.09
ANDLD
LD W425.10
ORNOT H10.10
ANDLD
LD W425.11
ORNOT H10.11
ANDLD
LD W425.12
ORNOT H10.12
ANDLD
LD W425.13
ORNOT H10.13
OR P_On
ANDLD
LD W425.14
ORNOT H10.14
ANDLD
LD W425.15
ORNOT H10.15
ANDLD
OUT W434.05
; rung 14
LD W426.00
ORNOT H11.00
LD W426.01
ORNOT H11.01
ANDLD
LD W426.02
ORNOT H11.02
ANDLD
LD W426.03
ORNOT H11.03
ANDLD
LD W426.04
ORNOT H11.04
LD W426.05
ORNOT H11.05
ANDLD
OR P_On
ANDLD
LD W426.06
ORNOT H11.06
ANDLD
LD W426.07
ORNOT H11.07
ANDLD
LD W426.08
ORNOT H11.08
LD W426.09
ORNOT H11.09
ANDLD
LD W426.10
ORNOT H11.10
ANDLD
LD W426.11
ORNOT H11.11
ANDLD
OR P_On
ANDLD
OUT W434.06

; rung 15
LD W427.00
ORNOT H12.00
LD W427.01
ORNOT H12.01
ANDLD
LD W427.02
ORNOT H12.02
ANDLD
LD W427.03
ORNOT H12.03
ANDLD
LD W427.04
ORNOT H12.04
ANDLD
LD W427.05
ORNOT H12.05
ANDLD
LD W427.06
ORNOT H12.06
ANDLD
LD W427.07
ORNOT H12.07
ANDLD
LD W427.08
ORNOT H12.08
ANDLD
LD W427.09
ORNOT H12.09
ANDLD
LD W427.10
ORNOT H12.10
ANDLD
LD W427.11
ORNOT H12.11
ANDLD
OUT W434.07
; rung 16
LD W427.12
ORNOT H12.12
LD W427.13
ORNOT H12.13
ANDLD
LD W427.14
ORNOT H12.14
ANDLD
LD W427.15
ORNOT H12.15
ANDLD
LD W428.00
ORNOT H13.00
ANDLD
LD W428.01
ORNOT H13.01
OR P_On
ANDLD
LD W428.02
ORNOT H13.02
ANDLD
LD W428.03
ORNOT H13.03
ANDLD
LD W428.04
ORNOT H13.04
ANDLD
LD W428.05
ORNOT H13.05
ANDLD
LD W428.06
ORNOT H13.06
ANDLD
LD W428.07
ORNOT H13.07
ANDLD
LD W428.08
ORNOT H13.08
LD W428.09
ORNOT H13.09
ANDLD
ORNOT 1.07
ANDLD
LD W428.15
ORNOT H14.01
ANDLD
OUT W434.08
; rung 17
LD W434.04
AND W434.05
AND W434.06
AND W434.07
AND W434.08
AND T0094
AND W433.03
AND W438.06
AND W433.02
AND W61.08
ANDNOT T0501
TIM 0096 #600
; rung 18
LDNOT H10.00
ORTSTN(351) D19247 &0
LDNOT H10.01
ORTSTN(351) D19248 &0
ANDLD
LDNOT H10.02
ORTSTN(351) D19249 &0
ANDLD
LDNOT H10.03
ORTSTN(351) D19250 &0
ANDLD
LDNOT H10.04
ORTSTN(351) D19251 &0
ANDLD
LD P_On
ORNOT H10.05
ORTSTN(351) D19252 &0
ANDLD
LDNOT H10.06
ORTSTN(351) D19253 &0
ANDLD
LDNOT H10.07
ORTSTN(351) D19254 &0
ANDLD
OUT W434.10
; rung 19
LDNOT H10.08
ORTSTN(351) D19255 &0
LDNOT H10.09
ORTSTN(351) D19256 &0
ANDLD
LDNOT H10.10
ORTSTN(351) D19257 &0
ANDLD
LDNOT H10.11
ORTSTN(351) D19258 &0
ANDLD
LDNOT H10.12
ORTSTN(351) D19259 &0
ANDLD
LDNOT H10.13
ORTSTN(351) D19260 &0
ANDLD
LDNOT H10.14
ORTSTN(351) D19261 &0
ANDLD
LDNOT H10.15
ORTSTN(351) D19262 &0
ANDLD
OUT W434.11

; rung 20
LDNOT H11.00
ORTSTN(351) D19263 &0
LDNOT H11.01
ORTSTN(351) D19264 &0
ANDLD
LDNOT H11.02
ORTSTN(351) D19265 &0
ANDLD
LDNOT H11.03
ORTSTN(351) D19266 &0
ANDLD
LDNOT H11.04
ORTSTN(351) D19267 &0
ANDLD
LD P_On
ORNOT H11.05
ORTSTN(351) D19268 &0
ANDLD
LDNOT H11.06
ORTSTN(351) D19269 &0
ANDLD
LDNOT H11.07
ORTSTN(351) D19270 &0
ANDLD
LDNOT H11.08
ORTSTN(351) D19271 &0
ANDLD
LD P_On
ORNOT H11.09
ORTSTN(351) D19272 &0
ANDLD
LDNOT H11.10
ORTSTN(351) D19273 &0
ANDLD
LDNOT H11.11
ORTSTN(351) D19274 &0
ANDLD
OUT W434.12
; rung 21
LDNOT H12.00
ORTSTN(351) D18454 &0
LDNOT H12.01
ORTSTN(351) D18455 &0
ANDLD
LDNOT H12.02
ORTSTN(351) D18456 &0
ANDLD
LDNOT H12.03
ORTSTN(351) D18457 &0
ANDLD
LDNOT H12.04
ORTSTN(351) D18458 &0
ANDLD
LDNOT H12.05
ORTSTN(351) D18459 &0
ANDLD
LDNOT H12.06
ORTSTN(351) D18460 &0
ANDLD
LDNOT H12.07
ORTSTN(351) D18461 &0
ANDLD
LDNOT H12.08
ORTSTN(351) D18462 &0
ANDLD
LDNOT H12.09
ORTSTN(351) D18463 &0
ANDLD
LDNOT H12.10
ORTSTN(351) D18464 &0
ANDLD
LDNOT H12.11
ORTSTN(351) D18465 &0
ANDLD
OUT W434.13
; rung 22
LDNOT H12.12
ORTSTN(351) D18466 &0
LDNOT H12.13
ORTSTN(351) D18467 &0
ANDLD
LDNOT H12.14
ORTSTN(351) D18468 &0
ANDLD
LDNOT H12.15
ORTSTN(351) D18469 &0
ANDLD
LDNOT H13.00
ORTSTN(351) D18470 &0
ANDLD
LD P_On
ORNOT H13.01
ORTSTN(351) D18471 &0
ANDLD
LDNOT H13.02
ORTSTN(351) D18472 &0
ANDLD
LDNOT H13.03
ORTSTN(351) D18473 &0
ANDLD
LDNOT H13.04
ORTSTN(351) D18474 &0
ANDLD
LDNOT H13.05
ORTSTN(351) D18475 &0
ANDLD
LDNOT H13.06
ORTSTN(351) D18476 &0
ANDLD
LDNOT H13.07
ORTSTN(351) D18477 &0
ANDLD
LDNOT H13.08
ORNOT T0990
ORTSTN(351) D18478 &0
ANDLD
LDNOT H13.09
ORNOT T0990
ORTSTN(351) D18479 &0
ANDLD
LDNOT H14.01
ORTSTN(351) D18487 &0
ANDLD
OUT W434.14
; rung 23
LD W434.10
AND W434.11
AND W434.12
AND W434.13
AND W434.14
OUT W433.02

; rung 24
LD P_1s
LD C0097
OR P_First_Cycle
CNT 0097 #6
; rung 25
LD W61.08
ANDNOT T0153
AND T0096
OUT TR0
AND C0097
ANDNOT W433.04
@++B(594) D3602
LD TR0
CMP(020) D3602 D3652
LD P_EQ
OR P_GT
OR W433.04
ANDLD
OUT W433.04
MOV(021) D3652 D3602
LD TR0
AND<>(305) D3652 D3606
MOV(021) #0 D3602
LD TR0
MOV(021) D3652 D3606
; rung 26
LD W433.04
OUT 427.13
; rung 27
LDNOT T0096
MOV(021) #0 D3602

; rung 28: ----- 成形温度２段切替 -----
LD W209.02
ANDNOT H80.15
AND W71.15
AND H94.07
LD 427.00
DOWN(522)
OR W228.14
ORNOT H94.07
ORNOT 427.13
LDNOT W357.05
ORNOT W357.06
AND H99.13
AND H94.07
@AND 420.06  // 切替前異常で停止した場合
ORLD
KEEP(011) H99.13
; rung 29
LD H99.13
AND H94.07
AND 427.13
OUT TR0
OUT W439.01
-B(414) D3655 D573 D3665
AND C0097
ANDNOT W357.05
@++B(594) D573
LD TR0
AND>=(325) D573 D3655
OUT W357.05
MOV(021) D3655 D573
LD TR0
-B(414) D3656 D574 D3666
AND C0097
ANDNOT W357.06
@++B(594) D574
LD TR0
AND>=(325) D574 D3656
OUT W357.06
MOV(021) D3656 D574
; rung 30
LDNOT W439.01
MOVL(498) #0 D573
MOVL(498) #0 D3665

; rung 31: ***** 制御開始信号 *****
LD W433.03
OR H93.00
OR H93.01
OR H2.15
AND W184.01
OR W433.12
ANDNOT W223.01
AND T0094
OUT W433.12
TIM 0977 #100
; rung 32
LD W438.06
OR H93.00
OR H93.01
OR H2.15
AND W184.01
OR W438.09
ANDNOT W223.01
AND T0094
OUT W438.09
TIM 0978 #100
; rung 33
LDNOT W223.01
AND T0094
OUT W433.13
TIM 0979 #100
; rung 34: ***** 昇温完了確認 ***** / 全系列が成形温度-測定温度≦0にて昇温完了処理
LD W61.08
AND T0502
AND T0094
AND T0511
OUT W433.08
; rung 35
LD W433.08
AND W80.05
ANDNOT P_On
TIM 0501 #6000
; rung 36
LD W433.08
OUT TR0
AND W433.03
TIM 0438 #10
AND T0438
OUT W438.07
LD TR0
AND W438.06
TIM 0439 #10
AND T0439
OUT W438.08

; rung 37
LD W438.07
OUT TR0
AND H10.00
ANDTSTN(351) D19247 &0
LD<=(315) D19604 D19219
OR W425.00
ANDLD
OUT W425.00
LD TR0
AND H10.01
ANDTSTN(351) D19248 &0
LD<=(315) D19605 D19220
OR W425.01
ANDLD
OUT W425.01
LD TR0
AND H10.02
ANDTSTN(351) D19249 &0
LD<=(315) D19606 D19221
OR W425.02
ANDLD
OUT W425.02
LD TR0
AND H10.03
ANDTSTN(351) D19250 &0
LD<=(315) D19607 D19222
OR W425.03
ANDLD
OUT W425.03
; rung 38
LD W438.07
OUT TR0
AND H10.04
ANDTSTN(351) D19251 &0
LD<=(315) D19608 D19223
OR W425.04
ANDLD
OUT W425.04
LD TR0
AND H10.05
ANDTSTN(351) D19252 &0
LD<=(315) D19609 D19224
OR W425.05
ANDLD
OUT W425.05
LD TR0
AND H10.06
ANDTSTN(351) D19253 &0
LD<=(315) D19610 D19225
OR W425.06
ANDLD
OUT W425.06
LD TR0
AND H10.07
ANDTSTN(351) D19254 &0
LD<=(315) D19611 D19226
OR W425.07
ANDLD
OUT W425.07

; rung 39
LD W438.07
OUT TR0
AND H10.08
ANDTSTN(351) D19255 &0
LD<=(315) D19612 D19227
OR W425.08
ANDLD
OUT W425.08
LD TR0
AND H10.09
ANDTSTN(351) D19256 &0
LD<=(315) D19613 D19228
OR W425.09
ANDLD
OUT W425.09
LD TR0
AND H10.10
ANDTSTN(351) D19257 &0
LD<=(315) D19614 D19229
OR W425.10
ANDLD
OUT W425.10
LD TR0
AND H10.11
ANDTSTN(351) D19258 &0
LD<=(315) D19615 D19230
OR W425.11
ANDLD
OUT W425.11
; rung 40
LD W438.07
OUT TR0
AND H10.12
ANDTSTN(351) D19259 &0
LD<=(315) D19616 D19231
OR W425.12
ANDLD
OUT W425.12
LD TR0
AND H10.13
ANDTSTN(351) D19260 &0
LD<=(315) D19617 D19232
OR W425.13
ANDLD
OUT W425.13
LD TR0
AND H10.14
ANDTSTN(351) D19261 &0
LD<=(315) D19618 D19233
OR W425.14
ANDLD
OUT W425.14
LD TR0
AND H10.15
ANDTSTN(351) D19262 &0
LD<=(315) D19619 D19234
OR W425.15
ANDLD
OUT W425.15

; rung 41
LD W438.08
OUT TR0
AND H11.00
ANDTSTN(351) D19263 &0
LD<=(315) D19620 D19235
OR W426.00
ANDLD
OUT W426.00
LD TR0
AND H11.01
ANDTSTN(351) D19264 &0
LD<=(315) D19621 D19236
OR W426.01
ANDLD
OUT W426.01
LD TR0
AND H11.02
ANDTSTN(351) D19265 &0
LD<=(315) D19622 D19237
OR W426.02
ANDLD
OUT W426.02
LD TR0
AND H11.03
ANDTSTN(351) D19266 &0
LD<=(315) D19623 D19238
OR W426.03
ANDLD
OUT W426.03
; rung 42
LD W438.08
OUT TR0
AND H11.04
ANDTSTN(351) D19267 &0
LD<=(315) D19624 D19239
OR W426.04
ANDLD
OUT W426.04
LD TR0
AND H11.05
ANDTSTN(351) D19268 &0
LD<=(315) D19625 D19240
OR W426.05
ANDLD
OUT W426.05
LD TR0
AND H11.06
ANDTSTN(351) D19269 &0
LD<=(315) D19626 D19241
OR W426.06
ANDLD
OUT W426.06
LD TR0
AND H11.07
ANDTSTN(351) D19270 &0
LD<=(315) D19627 D19242
OR W426.07
ANDLD
OUT W426.07

; rung 43
LD W438.08
OUT TR0
AND H11.08
ANDTSTN(351) D19271 &0
LD<=(315) D19628 D19243
OR W426.08
ANDLD
OUT W426.08
LD TR0
AND H11.09
ANDTSTN(351) D19272 &0
LD<=(315) D19629 D19244
OR W426.09
ANDLD
OUT W426.09
LD TR0
AND H11.10
ANDTSTN(351) D19273 &0
LD<=(315) D19630 D19245
OR W426.10
ANDLD
OUT W426.10
LD TR0
AND H11.11
ANDTSTN(351) D19274 &0
LD<=(315) D19631 D19246
OR W426.11
ANDLD
OUT W426.11
; rung 44
LD W438.08
OUT TR0
AND H12.00
ANDTSTN(351) D18454 &0
LD<=(315) D18804 D18420
OR W427.00
ANDLD
OUT W427.00
LD TR0
AND H12.01
ANDTSTN(351) D18455 &0
LD<=(315) D18805 D18421
OR W427.01
ANDLD
OUT W427.01
LD TR0
AND H12.02
ANDTSTN(351) D18456 &0
LD<=(315) D18806 D18422
OR W427.02
ANDLD
OUT W427.02
LD TR0
AND H12.03
ANDTSTN(351) D18457 &0
LD<=(315) D18807 D18423
OR W427.03
ANDLD
OUT W427.03
LD TR0
AND H12.04
ANDTSTN(351) D18458 &0
LD<=(315) D18808 D18424
OR W427.04
ANDLD
OUT W427.04
LD TR0
AND H12.05
ANDTSTN(351) D18459 &0
LD<=(315) D18809 D18425
OR W427.05
ANDLD
OUT W427.05

; rung 45
LD W438.08
OUT TR0
AND H12.06
ANDTSTN(351) D18460 &0
LD<=(315) D18810 D18426
OR W427.06
ANDLD
OUT W427.06
LD TR0
AND H12.07
ANDTSTN(351) D18461 &0
LD<=(315) D18811 D18427
OR W427.07
ANDLD
OUT W427.07
LD TR0
AND H12.08
ANDTSTN(351) D18462 &0
LD<=(315) D18812 D18428
OR W427.08
ANDLD
OUT W427.08
LD TR0
AND H12.09
ANDTSTN(351) D18463 &0
LD<=(315) D18813 D18429
OR W427.09
ANDLD
OUT W427.09
LD TR0
AND H12.10
ANDTSTN(351) D18464 &0
LD<=(315) D18814 D18430
OR W427.10
ANDLD
OUT W427.10
LD TR0
AND H12.11
ANDTSTN(351) D18465 &0
LD<=(315) D18815 D18431
OR W427.11
ANDLD
OUT W427.11

; rung 46
LD W438.08
OUT TR0
AND H12.12
ANDTSTN(351) D18466 &0
LD<=(315) D18816 D18432
OR W427.12
ANDLD
OUT W427.12
LD TR0
AND H12.13
ANDTSTN(351) D18467 &0
LD<=(315) D18817 D18433
OR W427.13
ANDLD
OUT W427.13
LD TR0
AND H12.14
ANDTSTN(351) D18468 &0
LD<=(315) D18818 D18434
OR W427.14
ANDLD
OUT W427.14
LD TR0
AND H12.15
ANDTSTN(351) D18469 &0
LD<=(315) D18819 D18435
OR W427.15
ANDLD
OUT W427.15
LD TR0
AND H13.00
ANDTSTN(351) D18470 &0
LD<=(315) D18820 D18436
OR W428.00
ANDLD
OUT W428.00
LD TR0
AND H13.01
ANDTSTN(351) D18471 &0
LD<=(315) D18821 D18437
OR W428.01
ANDLD
OUT W428.01
; rung 47
LD W433.08
OUT TR0
AND H13.02
ANDTSTN(351) D18472 &0
LD<=(315) D18822 D18438
OR W428.02
ANDLD
OUT W428.02
LD TR0
AND H13.03
ANDTSTN(351) D18473 &0
LD<=(315) D18823 D18439
OR W428.03
ANDLD
OUT W428.03
LD TR0
AND H13.04
ANDTSTN(351) D18474 &0
LD<=(315) D18824 D18440
OR W428.04
ANDLD
OUT W428.04
LD TR0
AND H13.05
ANDTSTN(351) D18475 &0
LD<=(315) D18825 D18441
OR W428.05
ANDLD
OUT W428.05

; rung 48
LD W433.08
OUT TR0
AND H13.06
ANDTSTN(351) D18476 &0
LD<=(315) D18826 D18442
OR W428.06
ANDLD
OUT W428.06
LD TR0
AND H13.07
ANDTSTN(351) D18477 &0
LD<=(315) D18827 D18443
OR W428.07
ANDLD
OUT W428.07
LD TR0
AND H13.08
LDTSTN(351) D18478 &0
ORNOT T0990
ANDLD
LD<=(315) D18828 D18444
OR W428.08
ANDLD
OUT W428.08
LD TR0
AND H13.09
LDTSTN(351) D18479 &0
ORNOT T0990
ANDLD
LD<=(315) D18829 D18445
OR W428.09
ANDLD
OUT W428.09
LD TR0
AND H14.01
ANDTSTN(351) D18487 &0
LD<=(315) D18736 D18453
OR W428.15
ANDLD
OUT W428.15
; rung 49: ----- 保温／成形を選択し設定温度ＤＭへ転送する -----
LD H2.15
AND W433.13
DIFU(013) W433.14
; rung 50
LD W61.08
AND W433.13
DIFU(013) W433.06
; rung 51
LD W61.08
OUT TR0
AND W433.03
DIFU(013) W433.15
LD TR0
AND W438.06
DIFU(013) W438.10
; rung 52: ----- 実設定にSTEP1温度転送 -----
LD H93.00
XFER(070) &28 D19910 D19604
XFER(070) &26 D19110 D18804
DIFU(013) W438.11

; rung 53: ----- 実設定にSTEP2温度転送 -----
LD H93.01
OUT TR0
AND W184.06
XFER(070) &28 D19940 D19604
XFER(070) &18 D19140 D18804
DIFU(013) W185.04
LD TR0
AND P_Off
XFER(070) &26 D19140 D18804
LD TR0
XFER(070) &8 D19158 D18822
DIFU(013) W438.12
; rung 54: ----- 実設定値に成形温度1転送 -----
LD W433.03
ORNOT W362.12
LDNOT H17.11
ANDNOT H17.01
ORLD
AND W61.08
ANDNOT W357.05
LD W184.01
AND W184.02
ORNOT W184.01
ANDLD
OUT W205.02
XFER(070) &8 D19510 D19604
XFER(070) &8 D19518 D19612
DIFU(013) W438.13

; rung 55
LD W438.06
ORNOT W362.12
LDNOT H17.11
ANDNOT H17.01
ORLD
AND W61.08
ANDNOT W357.05
LD W184.01
AND W184.02
ORNOT W184.01
ANDLD
OUT W205.03
XFER(070) &8 D19526 D19620
XFER(070) &4 D19534 D19628
XFER(070) &6 D18710 D18804
XFER(070) &6 D18716 D18810
XFER(070) &6 D18722 D18816
DIFU(013) W438.14
; rung 56
LD W61.08
OUT TR0
ANDNOT W357.06
OUT W205.04
XFER(070) &8 D18728 D18822
DIFU(013) W438.15
LD TR0
TIM 0502 #10
; rung 57: ----- 実設定値に成形温度2転送 -----
LD W357.05
AND W184.03
XFER(070) &28 D17400 D19604
XFER(070) &18 D17430 D18804
DIFU(013) W439.02

; rung 58
LD W357.06
XFER(070) &8 D17448 D18822
DIFU(013) W439.03
; rung 59: ----- 実設定値に保温温度転送 -----
LD H2.15
OUT TR0
LD W184.01
AND W184.04
ORNOT W184.01
ANDLD
XFER(070) &28 D19540 D19604
XFER(070) &18 D18740 D18804
DIFU(013) W185.02
LD TR0
AND P_Off
XFER(070) &26 D18740 D18804
LD TR0
XFER(070) &7 D18758 D18822
DIFU(013) W439.00

; rung 60
LD W438.11
OR W438.12
OR W438.13
OR W438.14
OR W438.15
OR W439.00
OR W163.12
OR W439.02
OR W439.03
OR W185.00
OR W185.01
OR W185.02
OR W185.03
OR W185.04
MOV(021) #1 D19590
; rung 61: ----- 主内 絶対値上限温度警報設定 -----
LD>=(325) D19219 D6200
AND H10.00
OR W180.00
ANDNOT W394.13
OUT W180.00
; rung 62
LD>=(325) D19220 D6201
AND H10.01
OR W180.01
ANDNOT W394.13
OUT W180.01
; rung 63
LD>=(325) D19221 D6202
AND H10.02
OR W180.02
ANDNOT W394.13
OUT W180.02

; rung 64
LD>=(325) D19222 D6203
AND H10.03
OR W180.03
ANDNOT W394.13
OUT W180.03
; rung 65
LD>=(325) D19225 D6204
AND H10.06
OR W180.04
ANDNOT W394.13
OUT W180.04
; rung 66
LD>=(325) D19226 D6205
AND H10.07
OR W180.05
ANDNOT W394.13
OUT W180.05
; rung 67: ----- 粉砕 絶対値上限温度警報設定 -----
LD>=(325) D19227 D6206
AND H10.08
OR W180.06
ANDNOT W394.13
OUT W180.06
; rung 68
LD>=(325) D19228 D6207
AND H10.09
OR W180.07
ANDNOT W394.13
OUT W180.07
; rung 69
LD>=(325) D19229 D6208
AND H10.10
OR W180.08
ANDNOT W394.13
OUT W180.08
; rung 70
LD>=(325) D19230 D6209
AND H10.11
OR W180.09
ANDNOT W394.13
OUT W180.09
; rung 71
LD>=(325) D19231 D6210
AND H10.12
OR W180.10
ANDNOT W394.13
OUT W180.10

; rung 72
LD>=(325) D19233 D6211
AND H10.14
OR W180.11
ANDNOT W394.13
OUT W180.11
; rung 73
LD>=(325) D19234 D6212
AND H10.15
OR W180.12
ANDNOT W394.13
OUT W180.12
; rung 74: ----- 主外 絶対値上限温度警報設定 -----
LD>=(325) D19235 D6213
AND H11.00
OR W180.13
ANDNOT W394.13
OUT W180.13
; rung 75
LD>=(325) D19236 D6214
AND H11.01
OR W180.14
ANDNOT W394.13
OUT W180.14
; rung 76
LD>=(325) D19237 D6215
AND H11.02
OR W180.15
ANDNOT W394.13
OUT W180.15
; rung 77
LD>=(325) D19238 D6216
AND H11.03
OR W181.00
ANDNOT W394.13
OUT W181.00
; rung 78
LD>=(325) D19241 D6217
AND H11.06
OR W181.01
ANDNOT W394.13
OUT W181.01
; rung 79
LD>=(325) D19242 D6218
AND H11.07
OR W181.02
ANDNOT W394.13
OUT W181.02

; rung 80: ----- ﾊﾞﾘｱ 絶対値上限温度警報設定 -----
LD>=(325) D18420 D6219
AND H12.00
OR W181.03
ANDNOT W394.13
OUT W181.03
; rung 81
LD>=(325) D18421 D6220
AND H12.01
OR W181.04
ANDNOT W394.13
OUT W181.04
; rung 82
LD>=(325) D18422 D6221
AND H12.02
OR W181.05
ANDNOT W394.13
OUT W181.05
; rung 83
LD>=(325) D18423 D6222
AND H12.03
OR W181.06
ANDNOT W394.13
OUT W181.06
; rung 84
LD>=(325) D18424 D6223
AND H12.04
OR W181.07
ANDNOT W394.13
OUT W181.07
; rung 85
LD>=(325) D18425 D6224
AND H12.05
OR W181.08
ANDNOT W394.13
OUT W181.08
; rung 86: ----- 接内 絶対値上限温度警報設定 -----
LD>=(325) D18426 D6225
AND H12.06
OR W181.09
ANDNOT W394.13
OUT W181.09
; rung 87
LD>=(325) D18427 D6226
AND H12.07
OR W181.10
ANDNOT W394.13
OUT W181.10

; rung 88
LD>=(325) D18428 D6227
AND H12.08
OR W181.11
ANDNOT W394.13
OUT W181.11
; rung 89
LD>=(325) D18429 D6228
AND H12.09
OR W181.12
ANDNOT W394.13
OUT W181.12
; rung 90
LD>=(325) D18430 D6229
AND H12.10
OR W181.13
ANDNOT W394.13
OUT W181.13
; rung 91
LD>=(325) D18431 D6230
AND H12.11
OR W181.14
ANDNOT W394.13
OUT W181.14
; rung 92: ----- 接外 絶対値上限温度警報設定 -----
LD>=(325) D18432 D6231
AND H12.12
OR W181.15
ANDNOT W394.13
OUT W181.15
; rung 93
LD>=(325) D18433 D6232
AND H12.13
OR W182.00
ANDNOT W394.13
OUT W182.00
; rung 94
LD>=(325) D18434 D6233
AND H12.14
OR W182.01
ANDNOT W394.13
OUT W182.01
; rung 95
LD>=(325) D18435 D6234
AND H12.15
OR W182.02
ANDNOT W394.13
OUT W182.02

; rung 96
LD>=(325) D18436 D6235
AND H13.00
OR W182.03
ANDNOT W394.13
OUT W182.03
; rung 97: ----- ﾍｯﾄﾞ 絶対値上限温度警報設定 -----
LD>=(325) D18453 D6236
AND P_On
OR W182.04
ANDNOT W394.13
OUT W182.04
; rung 98
LD>=(325) D18438 D6237
AND H13.02
OR W182.05
ANDNOT W394.13
OUT W182.05
; rung 99
LD>=(325) D18439 D6238
AND H13.03
OR W182.06
ANDNOT W394.13
OUT W182.06
; rung 100
LD>=(325) D18440 D6239
AND H13.04
OR W182.07
ANDNOT W394.13
OUT W182.07
; rung 101
LD>=(325) D18441 D6240
AND H13.05
OR W182.08
ANDNOT W394.13
OUT W182.08
; rung 102
LD>=(325) D18442 D6241
AND H13.06
OR W182.09
ANDNOT W394.13
OUT W182.09
; rung 103
LD>=(325) D18443 D6242
AND H13.07
OR W182.10
ANDNOT W394.13
OUT W182.10

; rung 104
LD>=(325) D18444 D6243
AND H13.08
OR W182.11
ANDNOT W394.13
OUT W182.11
; rung 105
LD P_Off
OUT W182.12
OUT W182.13
OUT W182.14
OUT W182.15
; rung 106
LD<>(305) #0 W180
OR<>(305) #0 W181
OR<>(305) #0 W182
OUT W183.00
; rung 107: ----- 1次電源容量が足りないのでｸﾛｽﾍｯﾄﾞが (設定値-10℃） < (測定値) にならないとｼﾘﾝﾀﾞ昇温開始しない追加 ----- 2014年9月
LD P_On
MOV(021) #A D6500
; rung 108
LD H13.02
CLC(041)
-C(412) D18822 D6500 D6501
AND P_CY
MOV(021) #0 D6501

; rung 109
LD H13.03
CLC(041)
-C(412) D18823 D6500 D6502
AND P_CY
MOV(021) #0 D6502
; rung 110
LD H13.04
CLC(041)
-C(412) D18824 D6500 D6503
AND P_CY
MOV(021) #0 D6503
; rung 111
LD H13.05
CLC(041)
-C(412) D18825 D6500 D6504
AND P_CY
MOV(021) #0 D6504
; rung 112
LD H13.06
CLC(041)
-C(412) D18826 D6500 D6505
AND P_CY
MOV(021) #0 D6505

; rung 113
LD H13.07
CLC(041)
-C(412) D18827 D6500 D6506
AND P_CY
MOV(021) #0 D6506
; rung 114
LD>=(325) D18438 D6501
ORNOT H13.02
LD>=(325) D18439 D6502
ORNOT H13.03
ANDLD
LD>=(325) D18440 D6503
ORNOT H13.04
ANDLD
LD>=(325) D18441 D6504
ORNOT H13.05
ANDLD
LD>=(325) D18442 D6505
ORNOT H13.06
ANDLD
LD>=(325) D18443 D6506
ORNOT H13.07
ANDLD
AND T0094
TIM 0140 #10
AND T0140
OUT W184.00
; rung 115: ----- ｼﾘﾝﾀﾞ通常昇温開始処理 ----- / ｸﾛｽﾍｯﾄﾞ温度が1回範囲に入ったら昇温開始は保持する
LD W184.00
OR W184.01
AND T0094
OUT W184.01
; rung 116: ----- ｼﾘﾝﾀﾞ成形温度転送処理 -----
LD T0094
ANDNOT H2.15
ANDNOT H93.00
ANDNOT H93.01
TIM 0141 #10
; rung 117
LD W184.00
OR W184.02
AND T0094
ANDNOT H2.15
ANDNOT H93.00
ANDNOT H93.01
AND T0141
ANDNOT W357.06
OUT W184.02
AND P_Off
DIFU(013) W185.00
; rung 118
LD W357.06
AND T0094
AND T0141
TIM 0142 #10
; rung 119
LD W184.00
OR W184.03
AND T0094
ANDNOT H2.15
ANDNOT H93.00
ANDNOT H93.01
AND T0141
AND T0142
OUT W184.03
AND P_Off
DIFU(013) W185.01

; rung 120: ----- ｼﾘﾝﾀﾞ保温温度転送処理 -----
LD T0094
AND H2.15
ANDNOT H93.00
ANDNOT H93.01
TIM 0143 #10
; rung 121
LD W184.00
OR W184.04
AND T0094
AND H2.15
ANDNOT H93.00
ANDNOT H93.01
AND T0143
OUT W184.04
; rung 122: ----- ｼﾘﾝﾀﾞSTEP1温度転送処理 -----
LD T0094
ANDNOT H2.15
AND H93.00
ANDNOT H93.01
TIM 0144 #10
; rung 123
LD W184.00
OR W184.05
AND T0094
ANDNOT H2.15
AND H93.00
ANDNOT H93.01
AND T0144
AND P_Off
OUT W184.05
DIFU(013) W185.03
; rung 124: ----- ｼﾘﾝﾀﾞSTEP2温度転送処理 -----
LD T0094
ANDNOT H2.15
ANDNOT H93.00
AND H93.01
TIM 0145 #10
; rung 125
LD W184.00
OR W184.06
AND T0094
ANDNOT H2.15
ANDNOT H93.00
AND H93.01
AND T0145
OUT W184.06

### Section EJ1_HFU0

; rung 0: ********** 温調計本処理 ********** / ********** 温調計異常確認 **********
LD P_On
TIM 0999 #50
; rung 1
LD<>(305) D19590 #0
@MOV(021) #1 D18795
; rung 2: ********** 温調計初期設定 **********
LD P_First_Cycle
BSET(071) #0 D19200 D19484
BSET(071) #0 D19600 D19603
BSET(071) #1 D19247 D19274
MOV(021) #0 D19599
BSET(071) #0 D16900 D16908
; rung 3: ***** 温調計ダンマリ停止 ***** / 通信ビット確認し変化がなければ通信していないと判断
LD T0999
OUT TR0
ANDTST(350) D19203 &15
TIM 0998 #100
LD TR0
ANDTSTN(351) D19203 &15
TIM 0985 #100

; rung 4: ***** 温調計-PLC間通信異常 ***** / ----- HFU0-PLC間通信異常 -----
LD T0999
OUT TR0
AND=(300) D19202 #EEEE
SET H50.00
MOV(021) #0 D19600
MOV(021) #0 D19601
MOV(021) #FFFF D19602
LD TR0
AND=(300) D19202 #FFFF
RSET H50.00
SET H50.01
MOV(021) #0 D19602
LD TR0
AND=(300) D19202 #0
AND H50.01
RSET H50.01
; rung 5
LD H50.00
OR H50.01
OUT W400.00
; rung 6: ********** EJ1設定書込処理 **********
LD P_First_Cycle
OR<>(305) D19590 #0
OR W400.05
ANDNOT W400.04
OUT W400.05
; rung 7
LD=(300) D19599 #0
ANDNOT W400.03
OR W400.01
AND W400.05
AND T0999
ANDNOT W400.00
OUT W400.01
@MOV(021) #1 D19599
@SET H50.02
@BSET(071) #0 D19600 D19602

; rung 8
LD W400.01
AND H50.02
AND=(300) D19200 #0
AND=(300) D19201 #0
AND=(300) D19202 #0
RSET H50.02
SET H50.03
@MOV(021) #1 D19601
@MOV(021) #0 D19590  // ｺﾏﾝﾄﾞ送信後再度画面変更されても良い様に
; rung 9
LD W400.01
AND H50.03
LD=(300) D19201 #1
OR=(300) D19201 #8001
ANDLD
RSET H50.03
SET H50.04
@MOV(021) #0 D19601
; rung 10
LD W400.01
AND H50.04
LD=(300) D19201 #0
OR=(300) D19201 #8001
ANDLD
OUT W400.04
RSET H50.04
@MOV(021) #0 D19599
; rung 11: ********** EJ1動作書込処理 ********** / ＥＪ１ではXunitXchからYunitYchまで一括設定できない（Xunitの全chや全ｕｎｉｔ全ch一括は可能) / 溶着時先に制御停止しておく。 / ---------- 主材内層制御開始/停止 ----------
LD W433.12
ANDTSTN(351) D19574 &6
OUT TR0
UP(521)
MOVB(082) #FFFF #0 D16900
LD TR0
DOWN(522)
MOVB(082) #0 #0 D16900
; rung 12
LD W433.12
ANDTSTN(351) D19574 &14
OUT TR0
UP(521)
MOVB(082) #FFFF #101 D16900
LD TR0
DOWN(522)
MOVB(082) #0 #101 D16900

; rung 13
LD W433.12
ANDTSTN(351) D19575 &6
OUT TR0
UP(521)
MOVB(082) #FFFF #202 D16900
LD TR0
DOWN(522)
MOVB(082) #0 #202 D16900
; rung 14
LD W433.12
ANDTSTN(351) D19575 &14
OUT TR0
UP(521)
MOVB(082) #FFFF #303 D16900
LD TR0
DOWN(522)
MOVB(082) #0 #303 D16900
; rung 15
LD W433.12
ANDTSTN(351) D19576 &6
OUT TR0
UP(521)
MOVB(082) #FFFF #404 D16900
LD TR0
DOWN(522)
MOVB(082) #0 #404 D16900
; rung 16
LD W433.12
ANDTSTN(351) D19576 &14
OUT TR0
UP(521)
MOVB(082) #FFFF #505 D16900
LD TR0
DOWN(522)
MOVB(082) #0 #505 D16900
; rung 17
LD W433.12
ANDTSTN(351) D19577 &6
OUT TR0
UP(521)
MOVB(082) #FFFF #606 D16900
LD TR0
DOWN(522)
MOVB(082) #0 #606 D16900

; rung 18
LD W433.12
ANDTSTN(351) D19577 &14
OUT TR0
UP(521)
MOVB(082) #FFFF #707 D16900
LD TR0
DOWN(522)
MOVB(082) #0 #707 D16900
; rung 19: ---------- 粉砕層制御開始/停止 ----------
LD W433.12
ANDTSTN(351) D19578 &6
OUT TR0
UP(521)
MOVB(082) #FFFF #808 D16900
LD TR0
DOWN(522)
MOVB(082) #0 #808 D16900
; rung 20
LD W433.12
ANDTSTN(351) D19578 &14
OUT TR0
UP(521)
MOVB(082) #FFFF #909 D16900
LD TR0
DOWN(522)
MOVB(082) #0 #909 D16900
; rung 21
LD W433.12
ANDTSTN(351) D19579 &6
OUT TR0
UP(521)
MOVB(082) #FFFF #A0A D16900
LD TR0
DOWN(522)
MOVB(082) #0 #A0A D16900
; rung 22
LD W433.12
ANDTSTN(351) D19579 &14
OUT TR0
UP(521)
MOVB(082) #FFFF #B0B D16900
LD TR0
DOWN(522)
MOVB(082) #0 #B0B D16900

; rung 23
LD W433.12
ANDTSTN(351) D19580 &6
OUT TR0
UP(521)
MOVB(082) #FFFF #C0C D16900
LD TR0
DOWN(522)
MOVB(082) #0 #C0C D16900
; rung 24
LD W433.12
ANDTSTN(351) D19580 &14
OUT TR0
UP(521)
MOVB(082) #FFFF #D0D D16900
LD TR0
DOWN(522)
MOVB(082) #0 #D0D D16900
; rung 25
LD W433.12
ANDTSTN(351) D19581 &6
OUT TR0
UP(521)
MOVB(082) #FFFF #E0E D16900
LD TR0
DOWN(522)
MOVB(082) #0 #E0E D16900
; rung 26
LD W433.12
ANDTSTN(351) D19581 &14
OUT TR0
UP(521)
MOVB(082) #FFFF #F0F D16900
LD TR0
DOWN(522)
MOVB(082) #0 #F0F D16900
; rung 27: ---------- 主材外層制御開始/停止 ----------
LD W438.09
ANDTSTN(351) D19582 &6
OUT TR0
UP(521)
MOVB(082) #FFFF #0 D16901
LD TR0
DOWN(522)
MOVB(082) #0 #0 D16901

; rung 28
LD W438.09
ANDTSTN(351) D19582 &14
OUT TR0
UP(521)
MOVB(082) #FFFF #101 D16901
LD TR0
DOWN(522)
MOVB(082) #0 #101 D16901
; rung 29
LD W438.09
ANDTSTN(351) D19583 &6
OUT TR0
UP(521)
MOVB(082) #FFFF #202 D16901
LD TR0
DOWN(522)
MOVB(082) #0 #202 D16901
; rung 30
LD W438.09
ANDTSTN(351) D19583 &14
OUT TR0
UP(521)
MOVB(082) #FFFF #303 D16901
LD TR0
DOWN(522)
MOVB(082) #0 #303 D16901
; rung 31
LD W438.09
ANDTSTN(351) D19584 &6
OUT TR0
UP(521)
MOVB(082) #FFFF #404 D16901
LD TR0
DOWN(522)
MOVB(082) #0 #404 D16901
; rung 32
LD W438.09
ANDTSTN(351) D19584 &14
OUT TR0
UP(521)
MOVB(082) #FFFF #505 D16901
LD TR0
DOWN(522)
MOVB(082) #0 #505 D16901

; rung 33
LD W438.09
ANDTSTN(351) D19585 &6
OUT TR0
UP(521)
MOVB(082) #FFFF #606 D16901
LD TR0
DOWN(522)
MOVB(082) #0 #606 D16901
; rung 34
LD W438.09
ANDTSTN(351) D19585 &14
OUT TR0
UP(521)
MOVB(082) #FFFF #707 D16901
LD TR0
DOWN(522)
MOVB(082) #0 #707 D16901
; rung 35: ---------- ﾊﾞﾘﾔ層FD部制御開始/停止 ----------
LD W438.09
ANDTSTN(351) D19586 &6
OUT TR0
UP(521)
MOVB(082) #FFFF #808 D16901
LD TR0
DOWN(522)
MOVB(082) #0 #808 D16901
; rung 36: ---------- 予備制御開始/停止 ----------
LD W438.09
ANDTSTN(351) D19586 &14
OUT TR0
UP(521)
MOVB(082) #FFFF #909 D16901
LD TR0
DOWN(522)
MOVB(082) #0 #909 D16901
; rung 37: ---------- 接着内層FD部制御開始/停止 ----------
LD W438.09
ANDTSTN(351) D19587 &6
OUT TR0
UP(521)
MOVB(082) #FFFF #A0A D16901
LD TR0
DOWN(522)
MOVB(082) #0 #A0A D16901

; rung 38: ---------- 接着外層FD部制御開始/停止 ----------
LD W438.09
ANDTSTN(351) D19587 &14
OUT TR0
UP(521)
MOVB(082) #FFFF #B0B D16901
LD TR0
DOWN(522)
MOVB(082) #0 #B0B D16901
; rung 39: ---------- 3-1ch制御開始・停止処理 ----------
LDTST(350) D16900 &0
ANDTSTN(351) D16906 &0
LDTSTN(351) D16900 &0
ANDTST(350) D16906 &0
ORLD
AND=(300) D19599 #0
ANDNOT W400.03
AND H10.00
OR W401.00
AND T0999
ANDNOT W400.00
ANDNOT W401.01
OUT W401.00
@MOVB(082) D16900 #0 D16903
@MOV(021) #1 D19599
; rung 40
LD W401.00
OUT TR0
@SET H50.10
@BSET(071) #0 D19600 D19602
ANDTST(350) D16903 &0
@MOV(021) #2830 D19603
LD TR0
ANDTSTN(351) D16903 &0
@MOV(021) #2C30 D19603
; rung 41
LD W401.00
AND H50.10
AND=(300) D19200 #0
AND=(300) D19201 #0
AND=(300) D19202 #0
RSET H50.10
SET H50.11
@MOV(021) #1 D19602

; rung 42
LD W401.00
AND H50.11
AND=(300) D19202 #1
RSET H50.11
SET H50.12
@MOV(021) #0 D19602
; rung 43
LD W401.00
AND H50.12
AND=(300) D19202 #0
OUT W401.01
RSET H50.12
@MOVB(082) D16903 #0 D16906
@MOV(021) #0 D19599
; rung 44: ---------- 3-2ch制御開始・停止処理 ----------
LDTST(350) D16900 &1
ANDTSTN(351) D16906 &1
LDTSTN(351) D16900 &1
ANDTST(350) D16906 &1
ORLD
AND=(300) D19599 #0
ANDNOT W400.03
AND H10.01
OR W401.02
AND T0999
ANDNOT W400.00
ANDNOT W401.03
OUT W401.02
@MOVB(082) D16900 #101 D16903
@MOV(021) #1 D19599
; rung 45
LD W401.02
OUT TR0
@SET H50.13
@BSET(071) #0 D19600 D19602
ANDTST(350) D16903 &1
@MOV(021) #2832 D19603
LD TR0
ANDTSTN(351) D16903 &1
@MOV(021) #2C32 D19603

; rung 46
LD W401.02
AND H50.13
AND=(300) D19200 #0
AND=(300) D19201 #0
AND=(300) D19202 #0
RSET H50.13
SET H50.14
@MOV(021) #1 D19602
; rung 47
LD W401.02
AND H50.14
AND=(300) D19202 #1
RSET H50.14
SET H50.15
@MOV(021) #0 D19602
; rung 48
LD W401.02
AND H50.15
AND=(300) D19202 #0
OUT W401.03
RSET H50.15
@MOVB(082) D16903 #101 D16906
@MOV(021) #0 D19599
; rung 49: ---------- 4-1ch制御開始・停止処理 ----------
LDTST(350) D16900 &2
ANDTSTN(351) D16906 &2
LDTSTN(351) D16900 &2
ANDTST(350) D16906 &2
ORLD
AND=(300) D19599 #0
ANDNOT W400.03
AND H10.02
OR W401.04
AND T0999
ANDNOT W400.00
ANDNOT W401.05
OUT W401.04
@MOVB(082) D16900 #202 D16903
@MOV(021) #1 D19599

; rung 50
LD W401.04
OUT TR0
@SET H51.00
@BSET(071) #0 D19600 D19602
ANDTST(350) D16903 &2
@MOV(021) #2840 D19603
LD TR0
ANDTSTN(351) D16903 &2
@MOV(021) #2C40 D19603
; rung 51
LD W401.04
AND H51.00
AND=(300) D19200 #0
AND=(300) D19201 #0
AND=(300) D19202 #0
RSET H51.00
SET H51.01
@MOV(021) #1 D19602
; rung 52
LD W401.04
AND H51.01
AND=(300) D19202 #1
RSET H51.01
SET H51.02
@MOV(021) #0 D19602
; rung 53
LD W401.04
AND H51.02
AND=(300) D19202 #0
OUT W401.05
RSET H51.02
@MOVB(082) D16903 #202 D16906
@MOV(021) #0 D19599

; rung 54: ---------- 4-2ch制御開始・停止処理 ----------
LDTST(350) D16900 &3
ANDTSTN(351) D16906 &3
LDTSTN(351) D16900 &3
ANDTST(350) D16906 &3
ORLD
AND=(300) D19599 #0
ANDNOT W400.03
AND H10.03
OR W401.06
AND T0999
ANDNOT W400.00
ANDNOT W401.07
OUT W401.06
@MOVB(082) D16900 #303 D16903
@MOV(021) #1 D19599
; rung 55
LD W401.06
OUT TR0
@SET H51.03
@BSET(071) #0 D19600 D19602
ANDTST(350) D16903 &3
@MOV(021) #2842 D19603
LD TR0
ANDTSTN(351) D16903 &3
@MOV(021) #2C42 D19603
; rung 56
LD W401.06
AND H51.03
AND=(300) D19200 #0
AND=(300) D19201 #0
AND=(300) D19202 #0
RSET H51.03
SET H51.04
@MOV(021) #1 D19602
; rung 57
LD W401.06
AND H51.04
AND=(300) D19202 #1
RSET H51.04
SET H51.05
@MOV(021) #0 D19602

; rung 58
LD W401.06
AND H51.05
AND=(300) D19202 #0
OUT W401.07
RSET H51.05
@MOVB(082) D16903 #303 D16906
@MOV(021) #0 D19599
; rung 59: ---------- 5-1ch制御開始・停止処理 ----------
LDTST(350) D16900 &4
ANDTSTN(351) D16906 &4
LDTSTN(351) D16900 &4
ANDTST(350) D16906 &4
ORLD
AND=(300) D19599 #0
ANDNOT W400.03
AND H10.04
OR W401.08
AND T0999
ANDNOT W400.00
ANDNOT W401.09
OUT W401.08
@MOVB(082) D16900 #404 D16903
@MOV(021) #1 D19599
; rung 60
LD W401.08
OUT TR0
@SET H51.06
@BSET(071) #0 D19600 D19602
ANDTST(350) D16903 &4
@MOV(021) #2850 D19603
LD TR0
ANDTSTN(351) D16903 &4
@MOV(021) #2C50 D19603
; rung 61
LD W401.08
AND H51.06
AND=(300) D19200 #0
AND=(300) D19201 #0
AND=(300) D19202 #0
RSET H51.06
SET H51.07
@MOV(021) #1 D19602

; rung 62
LD W401.08
AND H51.07
AND=(300) D19202 #1
RSET H51.07
SET H51.08
@MOV(021) #0 D19602
; rung 63
LD W401.08
AND H51.08
AND=(300) D19202 #0
OUT W401.09
RSET H51.08
@MOVB(082) D16903 #404 D16906
@MOV(021) #0 D19599
; rung 64: ---------- 5-2ch制御開始・停止処理 ----------
LDTST(350) D16900 &5
ANDTSTN(351) D16906 &5
LDTSTN(351) D16900 &5
ANDTST(350) D16906 &5
ORLD
AND=(300) D19599 #0
ANDNOT W400.03
AND H10.05
OR W401.10
AND T0999
ANDNOT W400.00
ANDNOT W401.11
OUT W401.10
@MOVB(082) D16900 #505 D16903
@MOV(021) #1 D19599
; rung 65
LD W401.10
OUT TR0
@SET H51.09
@BSET(071) #0 D19600 D19602
ANDTST(350) D16903 &5
@MOV(021) #2852 D19603
LD TR0
ANDTSTN(351) D16903 &5
@MOV(021) #2C52 D19603

; rung 66
LD W401.10
AND H51.09
AND=(300) D19200 #0
AND=(300) D19201 #0
AND=(300) D19202 #0
RSET H51.09
SET H51.10
@MOV(021) #1 D19602
; rung 67
LD W401.10
AND H51.10
AND=(300) D19202 #1
RSET H51.10
SET H51.11
@MOV(021) #0 D19602
; rung 68
LD W401.10
AND H51.11
AND=(300) D19202 #0
OUT W401.11
RSET H51.11
@MOVB(082) D16903 #505 D16906
@MOV(021) #0 D19599
; rung 69: ---------- 6-1ch制御開始・停止処理 ----------
LDTST(350) D16900 &6
ANDTSTN(351) D16906 &6
LDTSTN(351) D16900 &6
ANDTST(350) D16906 &6
ORLD
AND=(300) D19599 #0
ANDNOT W400.03
AND H10.06
OR W401.12
AND T0999
ANDNOT W400.00
ANDNOT W401.13
OUT W401.12
@MOVB(082) D16900 #606 D16903
@MOV(021) #1 D19599

; rung 70
LD W401.12
OUT TR0
@SET H51.12
@BSET(071) #0 D19600 D19602
ANDTST(350) D16903 &6
@MOV(021) #2860 D19603
LD TR0
ANDTSTN(351) D16903 &6
@MOV(021) #2C60 D19603
; rung 71
LD W401.12
AND H51.12
AND=(300) D19200 #0
AND=(300) D19201 #0
AND=(300) D19202 #0
RSET H51.12
SET H51.13
@MOV(021) #1 D19602
; rung 72
LD W401.12
AND H51.13
AND=(300) D19202 #1
RSET H51.13
SET H51.14
@MOV(021) #0 D19602
; rung 73
LD W401.12
AND H51.14
AND=(300) D19202 #0
OUT W401.13
RSET H51.14
@MOVB(082) D16903 #606 D16906
@MOV(021) #0 D19599

; rung 74: ---------- 6-2ch制御開始・停止処理 ----------
LDTST(350) D16900 &7
ANDTSTN(351) D16906 &7
LDTSTN(351) D16900 &7
ANDTST(350) D16906 &7
ORLD
AND=(300) D19599 #0
ANDNOT W400.03
AND H10.07
OR W401.14
AND T0999
ANDNOT W400.00
ANDNOT W401.15
OUT W401.14
@MOVB(082) D16900 #707 D16903
@MOV(021) #1 D19599
; rung 75
LD W401.14
OUT TR0
@SET H51.15
@BSET(071) #0 D19600 D19602
ANDTST(350) D16903 &7
@MOV(021) #2862 D19603
LD TR0
ANDTSTN(351) D16903 &7
@MOV(021) #2C62 D19603
; rung 76
LD W401.14
AND H51.15
AND=(300) D19200 #0
AND=(300) D19201 #0
AND=(300) D19202 #0
RSET H51.15
SET H52.00
@MOV(021) #1 D19602
; rung 77
LD W401.14
AND H52.00
AND=(300) D19202 #1
RSET H52.00
SET H52.01
@MOV(021) #0 D19602

; rung 78
LD W401.14
AND H52.01
AND=(300) D19202 #0
OUT W401.15
RSET H52.01
@MOVB(082) D16903 #707 D16906
@MOV(021) #0 D19599
; rung 79: ---------- 7-1ch制御開始・停止処理 ----------
LDTST(350) D16900 &8
ANDTSTN(351) D16906 &8
LDTSTN(351) D16900 &8
ANDTST(350) D16906 &8
ORLD
AND=(300) D19599 #0
ANDNOT W400.03
AND H10.08
OR W402.00
AND T0999
ANDNOT W400.00
ANDNOT W402.01
OUT W402.00
@MOVB(082) D16900 #808 D16903
@MOV(021) #1 D19599
; rung 80
LD W402.00
OUT TR0
@SET H52.02
@BSET(071) #0 D19600 D19602
ANDTST(350) D16903 &8
@MOV(021) #2870 D19603
LD TR0
ANDTSTN(351) D16903 &8
@MOV(021) #2C70 D19603
; rung 81
LD W402.00
AND H52.02
AND=(300) D19200 #0
AND=(300) D19201 #0
AND=(300) D19202 #0
RSET H52.02
SET H52.03
@MOV(021) #1 D19602

; rung 82
LD W402.00
AND H52.03
AND=(300) D19202 #1
RSET H52.03
SET H52.04
@MOV(021) #0 D19602
; rung 83
LD W402.00
AND H52.04
AND=(300) D19202 #0
OUT W402.01
RSET H52.04
@MOVB(082) D16903 #808 D16906
@MOV(021) #0 D19599
; rung 84: ---------- 7-2ch制御開始・停止処理 ----------
LDTST(350) D16900 &9
ANDTSTN(351) D16906 &9
LDTSTN(351) D16900 &9
ANDTST(350) D16906 &9
ORLD
AND=(300) D19599 #0
ANDNOT W400.03
AND H10.09
OR W402.02
AND T0999
ANDNOT W400.00
ANDNOT W402.03
OUT W402.02
@MOVB(082) D16900 #909 D16903
@MOV(021) #1 D19599
; rung 85
LD W402.02
OUT TR0
@SET H52.05
@BSET(071) #0 D19600 D19602
ANDTST(350) D16903 &9
@MOV(021) #2872 D19603
LD TR0
ANDTSTN(351) D16903 &9
@MOV(021) #2C72 D19603

; rung 86
LD W402.02
AND H52.05
AND=(300) D19200 #0
AND=(300) D19201 #0
AND=(300) D19202 #0
RSET H52.05
SET H52.06
@MOV(021) #1 D19602
; rung 87
LD W402.02
AND H52.06
AND=(300) D19202 #1
RSET H52.06
SET H52.07
@MOV(021) #0 D19602
; rung 88
LD W402.02
AND H52.07
AND=(300) D19202 #0
OUT W402.03
RSET H52.07
@MOVB(082) D16903 #909 D16906
@MOV(021) #0 D19599
; rung 89: ---------- 8-1ch制御開始・停止処理 ----------
LDTST(350) D16900 &10
ANDTSTN(351) D16906 &10
LDTSTN(351) D16900 &10
ANDTST(350) D16906 &10
ORLD
AND=(300) D19599 #0
ANDNOT W400.03
AND H10.10
OR W402.04
AND T0999
ANDNOT W400.00
ANDNOT W402.05
OUT W402.04
@MOVB(082) D16900 #A0A D16903
@MOV(021) #1 D19599

; rung 90
LD W402.04
OUT TR0
@SET H52.08
@BSET(071) #0 D19600 D19602
ANDTST(350) D16903 &10
@MOV(021) #2880 D19603
LD TR0
ANDTSTN(351) D16903 &10
@MOV(021) #2C80 D19603
; rung 91
LD W402.04
AND H52.08
AND=(300) D19200 #0
AND=(300) D19201 #0
AND=(300) D19202 #0
RSET H52.08
SET H52.09
@MOV(021) #1 D19602
; rung 92
LD W402.04
AND H52.09
AND=(300) D19202 #1
RSET H52.09
SET H52.10
@MOV(021) #0 D19602
; rung 93
LD W402.04
AND H52.10
AND=(300) D19202 #0
OUT W402.05
RSET H52.10
@MOVB(082) D16903 #A0A D16906
@MOV(021) #0 D19599

; rung 94: ---------- 8-2ch制御開始・停止処理 ----------
LDTST(350) D16900 &11
ANDTSTN(351) D16906 &11
LDTSTN(351) D16900 &11
ANDTST(350) D16906 &11
ORLD
AND=(300) D19599 #0
ANDNOT W400.03
AND H10.11
OR W402.06
AND T0999
ANDNOT W400.00
ANDNOT W402.07
OUT W402.06
@MOVB(082) D16900 #B0B D16903
@MOV(021) #1 D19599
; rung 95
LD W402.06
OUT TR0
@SET H52.11
@BSET(071) #0 D19600 D19602
ANDTST(350) D16903 &11
@MOV(021) #2882 D19603
LD TR0
ANDTSTN(351) D16903 &11
@MOV(021) #2C82 D19603
; rung 96
LD W402.06
AND H52.11
AND=(300) D19200 #0
AND=(300) D19201 #0
AND=(300) D19202 #0
RSET H52.11
SET H52.12
@MOV(021) #1 D19602
; rung 97
LD W402.06
AND H52.12
AND=(300) D19202 #1
RSET H52.12
SET H52.13
@MOV(021) #0 D19602

; rung 98
LD W402.06
AND H52.13
AND=(300) D19202 #0
OUT W402.07
RSET H52.13
@MOVB(082) D16903 #B0B D16906
@MOV(021) #0 D19599
; rung 99: ---------- 9-1ch制御開始・停止処理 ----------
LDTST(350) D16900 &12
ANDTSTN(351) D16906 &12
LDTSTN(351) D16900 &12
ANDTST(350) D16906 &12
ORLD
AND=(300) D19599 #0
ANDNOT W400.03
AND H10.12
OR W402.08
AND T0999
ANDNOT W400.00
ANDNOT W402.09
OUT W402.08
@MOVB(082) D16900 #C0C D16903
@MOV(021) #1 D19599
; rung 100
LD W402.08
OUT TR0
@SET H52.14
@BSET(071) #0 D19600 D19602
ANDTST(350) D16903 &12
@MOV(021) #2890 D19603
LD TR0
ANDTSTN(351) D16903 &12
@MOV(021) #2C90 D19603
; rung 101
LD W402.08
AND H52.14
AND=(300) D19200 #0
AND=(300) D19201 #0
AND=(300) D19202 #0
RSET H52.14
SET H52.15
@MOV(021) #1 D19602

; rung 102
LD W402.08
AND H52.15
AND=(300) D19202 #1
RSET H52.15
SET H53.00
@MOV(021) #0 D19602
; rung 103
LD W402.08
AND H53.00
AND=(300) D19202 #0
OUT W402.09
RSET H53.00
@MOVB(082) D16903 #C0C D16906
@MOV(021) #0 D19599
; rung 104: ---------- 9-2ch制御開始・停止処理 ----------
LDTST(350) D16900 &13
ANDTSTN(351) D16906 &13
LDTSTN(351) D16900 &13
ANDTST(350) D16906 &13
ORLD
AND=(300) D19599 #0
ANDNOT W400.03
AND H10.13
OR W402.10
AND T0999
ANDNOT W400.00
ANDNOT W402.11
OUT W402.10
@MOVB(082) D16900 #D0D D16903
@MOV(021) #1 D19599
; rung 105
LD W402.10
OUT TR0
@SET H53.01
@BSET(071) #0 D19600 D19602
ANDTST(350) D16903 &13
@MOV(021) #2892 D19603
LD TR0
ANDTSTN(351) D16903 &13
@MOV(021) #2C92 D19603

; rung 106
LD W402.10
AND H53.01
AND=(300) D19200 #0
AND=(300) D19201 #0
AND=(300) D19202 #0
RSET H53.01
SET H53.02
@MOV(021) #1 D19602
; rung 107
LD W402.10
AND H53.02
AND=(300) D19202 #1
RSET H53.02
SET H53.03
@MOV(021) #0 D19602
; rung 108
LD W402.10
AND H53.03
AND=(300) D19202 #0
OUT W402.11
RSET H53.03
@MOVB(082) D16903 #D0D D16906
@MOV(021) #0 D19599
; rung 109: ---------- 10-1ch制御開始・停止処理 ----------
LDTST(350) D16900 &14
ANDTSTN(351) D16906 &14
LDTSTN(351) D16900 &14
ANDTST(350) D16906 &14
ORLD
AND=(300) D19599 #0
ANDNOT W400.03
AND H10.14
OR W402.12
AND T0999
ANDNOT W400.00
ANDNOT W402.13
OUT W402.12
@MOVB(082) D16900 #E0E D16903
@MOV(021) #1 D19599

; rung 110
LD W402.12
OUT TR0
@SET H53.04
@BSET(071) #0 D19600 D19602
ANDTST(350) D16903 &14
@MOV(021) #28A0 D19603
LD TR0
ANDTSTN(351) D16903 &14
@MOV(021) #2CA0 D19603
; rung 111
LD W402.12
AND H53.04
AND=(300) D19200 #0
AND=(300) D19201 #0
AND=(300) D19202 #0
RSET H53.04
SET H53.05
@MOV(021) #1 D19602
; rung 112
LD W402.12
AND H53.05
AND=(300) D19202 #1
RSET H53.05
SET H53.06
@MOV(021) #0 D19602
; rung 113
LD W402.12
AND H53.06
AND=(300) D19202 #0
OUT W402.13
RSET H53.06
@MOVB(082) D16903 #E0E D16906
@MOV(021) #0 D19599

; rung 114: ---------- 10-2ch制御開始・停止処理 ----------
LDTST(350) D16900 &15
ANDTSTN(351) D16906 &15
LDTSTN(351) D16900 &15
ANDTST(350) D16906 &15
ORLD
AND=(300) D19599 #0
ANDNOT W400.03
AND H10.15
OR W402.14
AND T0999
ANDNOT W400.00
ANDNOT W402.15
OUT W402.14
@MOVB(082) D16900 #F0F D16903
@MOV(021) #1 D19599
; rung 115
LD W402.14
OUT TR0
@SET H53.07
@BSET(071) #0 D19600 D19602
ANDTST(350) D16903 &15
@MOV(021) #28A2 D19603
LD TR0
ANDTSTN(351) D16903 &15
@MOV(021) #2CA2 D19603
; rung 116
LD W402.14
AND H53.07
AND=(300) D19200 #0
AND=(300) D19201 #0
AND=(300) D19202 #0
RSET H53.07
SET H53.08
@MOV(021) #1 D19602
; rung 117
LD W402.14
AND H53.08
AND=(300) D19202 #1
RSET H53.08
SET H53.09
@MOV(021) #0 D19602

; rung 118
LD W402.14
AND H53.09
AND=(300) D19202 #0
OUT W402.15
RSET H53.09
@MOVB(082) D16903 #F0F D16906
@MOV(021) #0 D19599
; rung 119: ---------- 11-1ch制御開始・停止処理 ----------
LDTST(350) D16901 &0
ANDTSTN(351) D16907 &0
LDTSTN(351) D16901 &0
ANDTST(350) D16907 &0
ORLD
AND=(300) D19599 #0
ANDNOT W400.03
AND H11.00
OR W403.00
AND T0999
ANDNOT W400.00
ANDNOT W403.01
OUT W403.00
@MOVB(082) D16901 #0 D16904
@MOV(021) #1 D19599
; rung 120
LD W403.00
OUT TR0
@SET H53.10
@BSET(071) #0 D19600 D19602
ANDTST(350) D16904 &0
@MOV(021) #28B0 D19603
LD TR0
ANDTSTN(351) D16904 &0
@MOV(021) #2CB0 D19603
; rung 121
LD W403.00
AND H53.10
AND=(300) D19200 #0
AND=(300) D19201 #0
AND=(300) D19202 #0
RSET H53.10
SET H53.11
@MOV(021) #1 D19602

; rung 122
LD W403.00
AND H53.11
AND=(300) D19202 #1
RSET H53.11
SET H53.12
@MOV(021) #0 D19602
; rung 123
LD W403.00
AND H53.12
AND=(300) D19202 #0
OUT W403.01
RSET H53.12
@MOVB(082) D16904 #0 D16907
@MOV(021) #0 D19599
; rung 124: ---------- 11-2ch制御開始・停止処理 ----------
LDTST(350) D16901 &1
ANDTSTN(351) D16907 &1
LDTSTN(351) D16901 &1
ANDTST(350) D16907 &1
ORLD
AND=(300) D19599 #0
ANDNOT W400.03
AND H11.01
OR W403.02
AND T0999
ANDNOT W400.00
ANDNOT W403.03
OUT W403.02
@MOVB(082) D16901 #101 D16904
@MOV(021) #1 D19599
; rung 125
LD W403.02
OUT TR0
@SET H53.13
@BSET(071) #0 D19600 D19602
ANDTST(350) D16904 &1
@MOV(021) #28B2 D19603
LD TR0
ANDTSTN(351) D16904 &1
@MOV(021) #2CB2 D19603

; rung 126
LD W403.02
AND H53.13
AND=(300) D19200 #0
AND=(300) D19201 #0
AND=(300) D19202 #0
RSET H53.13
SET H53.14
@MOV(021) #1 D19602
; rung 127
LD W403.02
AND H53.14
AND=(300) D19202 #1
RSET H53.14
SET H53.15
@MOV(021) #0 D19602
; rung 128
LD W403.02
AND H53.15
AND=(300) D19202 #0
OUT W403.03
RSET H53.15
@MOVB(082) D16904 #101 D16907
@MOV(021) #0 D19599
; rung 129: ---------- 12-1ch制御開始・停止処理 ----------
LDTST(350) D16901 &2
ANDTSTN(351) D16907 &2
LDTSTN(351) D16901 &2
ANDTST(350) D16907 &2
ORLD
AND=(300) D19599 #0
ANDNOT W400.03
AND H11.02
OR W403.04
AND T0999
ANDNOT W400.00
ANDNOT W403.05
OUT W403.04
@MOVB(082) D16901 #202 D16904
@MOV(021) #1 D19599

; rung 130
LD W403.04
OUT TR0
@SET H54.00
@BSET(071) #0 D19600 D19602
ANDTST(350) D16904 &2
@MOV(021) #28C0 D19603
LD TR0
ANDTSTN(351) D16904 &2
@MOV(021) #2CC0 D19603
; rung 131
LD W403.04
AND H54.00
AND=(300) D19200 #0
AND=(300) D19201 #0
AND=(300) D19202 #0
RSET H54.00
SET H54.01
@MOV(021) #1 D19602
; rung 132
LD W403.04
AND H54.01
AND=(300) D19202 #1
RSET H54.01
SET H54.02
@MOV(021) #0 D19602
; rung 133
LD W403.04
AND H54.02
AND=(300) D19202 #0
OUT W403.05
RSET H54.02
@MOVB(082) D16904 #202 D16907
@MOV(021) #0 D19599

; rung 134: ---------- 12-2ch制御開始・停止処理 ----------
LDTST(350) D16901 &3
ANDTSTN(351) D16907 &3
LDTSTN(351) D16901 &3
ANDTST(350) D16907 &3
ORLD
AND=(300) D19599 #0
ANDNOT W400.03
AND H11.03
OR W403.06
AND T0999
ANDNOT W400.00
ANDNOT W403.07
OUT W403.06
@MOVB(082) D16901 #303 D16904
@MOV(021) #1 D19599
; rung 135
LD W403.06
OUT TR0
@SET H54.03
@BSET(071) #0 D19600 D19602
ANDTST(350) D16904 &3
@MOV(021) #28C2 D19603
LD TR0
ANDTSTN(351) D16904 &3
@MOV(021) #2CC2 D19603
; rung 136
LD W403.06
AND H54.03
AND=(300) D19200 #0
AND=(300) D19201 #0
AND=(300) D19202 #0
RSET H54.03
SET H54.04
@MOV(021) #1 D19602
; rung 137
LD W403.06
AND H54.04
AND=(300) D19202 #1
RSET H54.04
SET H54.05
@MOV(021) #0 D19602

; rung 138
LD W403.06
AND H54.05
AND=(300) D19202 #0
OUT W403.07
RSET H54.05
@MOVB(082) D16904 #303 D16907
@MOV(021) #0 D19599
; rung 139: ---------- 13-1ch制御開始・停止処理 ----------
LDTST(350) D16901 &4
ANDTSTN(351) D16907 &4
LDTSTN(351) D16901 &4
ANDTST(350) D16907 &4
ORLD
AND=(300) D19599 #0
ANDNOT W400.03
AND H11.04
OR W403.08
AND T0999
ANDNOT W400.00
ANDNOT W403.09
OUT W403.08
@MOVB(082) D16901 #404 D16904
@MOV(021) #1 D19599
; rung 140
LD W403.08
OUT TR0
@SET H54.06
@BSET(071) #0 D19600 D19602
ANDTST(350) D16904 &4
@MOV(021) #28D0 D19603
LD TR0
ANDTSTN(351) D16904 &4
@MOV(021) #2CD0 D19603
; rung 141
LD W403.08
AND H54.06
AND=(300) D19200 #0
AND=(300) D19201 #0
AND=(300) D19202 #0
RSET H54.06
SET H54.07
@MOV(021) #1 D19602

; rung 142
LD W403.08
AND H54.07
AND=(300) D19202 #1
RSET H54.07
SET H54.08
@MOV(021) #0 D19602
; rung 143
LD W403.08
AND H54.08
AND=(300) D19202 #0
OUT W403.09
RSET H54.08
@MOVB(082) D16904 #404 D16907
@MOV(021) #0 D19599
; rung 144: ---------- 13-2ch制御開始・停止処理 ----------
LDTST(350) D16901 &5
ANDTSTN(351) D16907 &5
LDTSTN(351) D16901 &5
ANDTST(350) D16907 &5
ORLD
AND=(300) D19599 #0
ANDNOT W400.03
AND H11.05
OR W403.10
AND T0999
ANDNOT W400.00
ANDNOT W403.11
OUT W403.10
@MOVB(082) D16901 #505 D16904
@MOV(021) #1 D19599
; rung 145
LD W403.10
OUT TR0
@SET H54.09
@BSET(071) #0 D19600 D19602
ANDTST(350) D16904 &5
@MOV(021) #28D2 D19603
LD TR0
ANDTSTN(351) D16904 &5
@MOV(021) #2CD2 D19603

; rung 146
LD W403.10
AND H54.09
AND=(300) D19200 #0
AND=(300) D19201 #0
AND=(300) D19202 #0
RSET H54.09
SET H54.10
@MOV(021) #1 D19602
; rung 147
LD W403.10
AND H54.10
AND=(300) D19202 #1
RSET H54.10
SET H54.11
@MOV(021) #0 D19602
; rung 148
LD W403.10
AND H54.11
AND=(300) D19202 #0
OUT W403.11
RSET H54.11
@MOVB(082) D16904 #505 D16907
@MOV(021) #0 D19599
; rung 149: ---------- 14-1ch制御開始・停止処理 ----------
LDTST(350) D16901 &6
ANDTSTN(351) D16907 &6
LDTSTN(351) D16901 &6
ANDTST(350) D16907 &6
ORLD
AND=(300) D19599 #0
ANDNOT W400.03
AND H11.06
OR W403.12
AND T0999
ANDNOT W400.00
ANDNOT W403.13
OUT W403.12
@MOVB(082) D16901 #606 D16904
@MOV(021) #1 D19599

; rung 150
LD W403.12
OUT TR0
@SET H54.12
@BSET(071) #0 D19600 D19602
ANDTST(350) D16904 &6
@MOV(021) #28E0 D19603
LD TR0
ANDTSTN(351) D16904 &6
@MOV(021) #2CE0 D19603
; rung 151
LD W403.12
AND H54.12
AND=(300) D19200 #0
AND=(300) D19201 #0
AND=(300) D19202 #0
RSET H54.12
SET H54.13
@MOV(021) #1 D19602
; rung 152
LD W403.12
AND H54.13
AND=(300) D19202 #1
RSET H54.13
SET H54.14
@MOV(021) #0 D19602
; rung 153
LD W403.12
AND H54.14
AND=(300) D19202 #0
OUT W403.13
RSET H54.14
@MOVB(082) D16904 #606 D16907
@MOV(021) #0 D19599

; rung 154: ---------- 14-2ch制御開始・停止処理 ----------
LDTST(350) D16901 &7
ANDTSTN(351) D16907 &7
LDTSTN(351) D16901 &7
ANDTST(350) D16907 &7
ORLD
AND=(300) D19599 #0
ANDNOT W400.03
AND H11.07
OR W403.14
AND T0999
ANDNOT W400.00
ANDNOT W403.15
OUT W403.14
@MOVB(082) D16901 #707 D16904
@MOV(021) #1 D19599
; rung 155
LD W403.14
OUT TR0
@SET H54.15
@BSET(071) #0 D19600 D19602
ANDTST(350) D16904 &7
@MOV(021) #28E2 D19603
LD TR0
ANDTSTN(351) D16904 &7
@MOV(021) #2CE2 D19603
; rung 156
LD W403.14
AND H54.15
AND=(300) D19200 #0
AND=(300) D19201 #0
AND=(300) D19202 #0
RSET H54.15
SET H55.00
@MOV(021) #1 D19602
; rung 157
LD W403.14
AND H55.00
AND=(300) D19202 #1
RSET H55.00
SET H55.01
@MOV(021) #0 D19602

; rung 158
LD W403.14
AND H55.01
AND=(300) D19202 #0
OUT W403.15
RSET H55.01
@MOVB(082) D16904 #707 D16907
@MOV(021) #0 D19599
; rung 159: ---------- 15-1ch制御開始・停止処理 ----------
LDTST(350) D16901 &8
ANDTSTN(351) D16907 &8
LDTSTN(351) D16901 &8
ANDTST(350) D16907 &8
ORLD
AND=(300) D19599 #0
ANDNOT W400.03
AND H11.08
OR W404.00
AND T0999
ANDNOT W400.00
ANDNOT W404.01
OUT W404.00
@MOVB(082) D16901 #808 D16904
@MOV(021) #1 D19599
; rung 160
LD W404.00
OUT TR0
@SET H55.02
@BSET(071) #0 D19600 D19602
ANDTST(350) D16904 &8
@MOV(021) #28F0 D19603
LD TR0
ANDTSTN(351) D16904 &8
@MOV(021) #2CF0 D19603
; rung 161
LD W404.00
AND H55.02
AND=(300) D19200 #0
AND=(300) D19201 #0
AND=(300) D19202 #0
RSET H55.02
SET H55.03
@MOV(021) #1 D19602

; rung 162
LD W404.00
AND H55.03
AND=(300) D19202 #1
RSET H55.03
SET H55.04
@MOV(021) #0 D19602
; rung 163
LD W404.00
AND H55.04
AND=(300) D19202 #0
OUT W404.01
RSET H55.04
@MOVB(082) D16904 #808 D16907
@MOV(021) #0 D19599
; rung 164: ---------- 15-2ch制御開始・停止処理 ----------
LDTST(350) D16901 &9
ANDTSTN(351) D16907 &9
LDTSTN(351) D16901 &9
ANDTST(350) D16907 &9
ORLD
AND=(300) D19599 #0
ANDNOT W400.03
AND H11.09
OR W404.02
AND T0999
ANDNOT W400.00
ANDNOT W404.03
OUT W404.02
@MOVB(082) D16901 #909 D16904
@MOV(021) #1 D19599
; rung 165
LD W404.02
OUT TR0
@SET H55.05
@BSET(071) #0 D19600 D19602
ANDTST(350) D16904 &9
@MOV(021) #28F2 D19603
LD TR0
ANDTSTN(351) D16904 &9
@MOV(021) #2CF2 D19603

; rung 166
LD W404.02
AND H55.05
AND=(300) D19200 #0
AND=(300) D19201 #0
AND=(300) D19202 #0
RSET H55.05
SET H55.06
@MOV(021) #1 D19602
; rung 167
LD W404.02
AND H55.06
AND=(300) D19202 #1
RSET H55.06
SET H55.07
@MOV(021) #0 D19602
; rung 168
LD W404.02
AND H55.07
AND=(300) D19202 #0
OUT W404.03
RSET H55.07
@MOVB(082) D16904 #909 D16907
@MOV(021) #0 D19599
; rung 169: ---------- 16-1ch制御開始・停止処理 ----------
LDTST(350) D16901 &10
ANDTSTN(351) D16907 &10
LDTSTN(351) D16901 &10
ANDTST(350) D16907 &10
ORLD
AND=(300) D19599 #0
ANDNOT W400.03
AND H11.10
OR W404.04
AND T0999
ANDNOT W400.00
ANDNOT W404.05
OUT W404.04
@MOVB(082) D16901 #A0A D16904
@MOV(021) #1 D19599

; rung 170
LD W404.04
OUT TR0
@SET H55.08
@BSET(071) #0 D19600 D19602
ANDTST(350) D16904 &10
@MOV(021) #2900 D19603
LD TR0
ANDTSTN(351) D16904 &10
@MOV(021) #2D00 D19603
; rung 171
LD W404.04
AND H55.08
AND=(300) D19200 #0
AND=(300) D19201 #0
AND=(300) D19202 #0
RSET H55.08
SET H55.09
@MOV(021) #1 D19602
; rung 172
LD W404.04
AND H55.09
AND=(300) D19202 #1
RSET H55.09
SET H55.10
@MOV(021) #0 D19602
; rung 173
LD W404.04
AND H55.10
AND=(300) D19202 #0
OUT W404.05
RSET H55.10
@MOVB(082) D16904 #A0A D16907
@MOV(021) #0 D19599

; rung 174: ---------- 16-2ch制御開始・停止処理 ----------
LDTST(350) D16901 &11
ANDTSTN(351) D16907 &11
LDTSTN(351) D16901 &11
ANDTST(350) D16907 &11
ORLD
AND=(300) D19599 #0
ANDNOT W400.03
AND H11.11
OR W404.06
AND T0999
ANDNOT W400.00
ANDNOT W404.07
OUT W404.06
@MOVB(082) D16901 #B0B D16904
@MOV(021) #1 D19599
; rung 175
LD W404.06
OUT TR0
@SET H55.11
@BSET(071) #0 D19600 D19602
ANDTST(350) D16904 &11
@MOV(021) #2902 D19603
LD TR0
ANDTSTN(351) D16904 &11
@MOV(021) #2D02 D19603
; rung 176
LD W404.06
AND H55.11
AND=(300) D19200 #0
AND=(300) D19201 #0
AND=(300) D19202 #0
RSET H55.11
SET H55.12
@MOV(021) #1 D19602
; rung 177
LD W404.06
AND H55.12
AND=(300) D19202 #1
RSET H55.12
SET H55.13
@MOV(021) #0 D19602

; rung 178
LD W404.06
AND H55.13
AND=(300) D19202 #0
OUT W404.07
RSET H55.13
@MOVB(082) D16904 #B0B D16907
@MOV(021) #0 D19599
; rung 179: ********** EJ1読出処理 **********
LD=(300) D19599 #0
AND T0999
ANDNOT W400.00
OUT W400.07
; rung 180
LD W400.07
OUT TR0
@SET H50.08
@BSET(071) #0 D19600 D19602
AND H50.08
AND=(300) D19200 #0
AND=(300) D19201 #0
AND=(300) D19202 #0
RSET H50.08
SET H50.09
@MOV(021) #2 D19600
LD TR0
LD=(300) D19200 #2
OR=(300) D19200 #8002
ANDLD
AND H50.09
RSET H50.09
; rung 181
LDNOT H50.08
ANDNOT H50.09
OUTNOT W400.03

### Section EJ1_HFU1

; rung 0: ********** 温調計初期設定 **********
LD P_First_Cycle
BSET(071) #0 D18400 D18690
BSET(071) #0 D18800 D18803
BSET(071) #1 D18454 D18487
MOV(021) #0 D18799
BSET(071) #0 D16918 D16926
; rung 1: ***** 温調計ダンマリ停止 ***** / 通信ビット確認し変化がなければ通信していないと判断
LD T0999
OUT TR0
ANDTST(350) D18403 &15
TIM 0984 #100
LD TR0
ANDTSTN(351) D18403 &15
TIM 0983 #100

; rung 2: ***** 温調計-PLC間通信異常 ***** / ----- HFU1-PLC間通信異常 -----
LD T0999
OUT TR0
AND=(300) D18402 #EEEE
SET H60.00
MOV(021) #0 D18800
MOV(021) #0 D18801
MOV(021) #FFFF D18802
LD TR0
AND=(300) D18402 #FFFF
RSET H60.00
SET H60.01
MOV(021) #0 D18802
LD TR0
AND=(300) D18402 #0
AND H60.01
RSET H60.01
; rung 3
LD H60.00
OR H60.01
OUT W410.00
; rung 4: ********** EJ1設定書込処理 **********
LD P_First_Cycle
OR<>(305) D18795 #0
OR W410.05
ANDNOT W410.04
OUT W410.05
; rung 5
LD=(300) D18799 #0
ANDNOT W410.03
OR W410.01
AND W410.05
AND T0999
ANDNOT W410.00
OUT W410.01
@MOV(021) #1 D18799
@SET H60.02
@BSET(071) #0 D18800 D18802

; rung 6
LD W410.01
AND H60.02
AND=(300) D18400 #0
AND=(300) D18401 #0
AND=(300) D18402 #0
RSET H60.02
SET H60.03
@MOV(021) #1 D18801
@MOV(021) #0 D18795  // ｺﾏﾝﾄﾞ送信後再度画面変更されても良い様に
; rung 7
LD W410.01
AND H60.03
LD=(300) D18401 #1
OR=(300) D18401 #8001
ANDLD
RSET H60.03
SET H60.04
@MOV(021) #0 D18801
; rung 8
LD W410.01
AND H60.04
LD=(300) D18401 #0
OR=(300) D18401 #8001
ANDLD
OUT W410.04
RSET H60.04
@MOV(021) #0 D18799
; rung 9: ********** EJ1動作書込処理 ********** / ＥＪ１ではXunitXchからYunitYchまで一括設定できない（Xunitの全chや全ｕｎｉｔ全ch一括は可能) / 溶着時先に制御停止しておく。 / ---------- バリヤ層制御開始/停止 ----------
LD W438.09
ANDTSTN(351) D18774 &6
OUT TR0
UP(521)
MOVB(082) #FFFF #0 D16918
LD TR0
DOWN(522)
MOVB(082) #0 #0 D16918
; rung 10
LD W438.09
ANDTSTN(351) D18774 &14
OUT TR0
UP(521)
MOVB(082) #FFFF #101 D16918
LD TR0
DOWN(522)
MOVB(082) #0 #101 D16918

; rung 11
LD W438.09
ANDTSTN(351) D18775 &6
OUT TR0
UP(521)
MOVB(082) #FFFF #202 D16918
LD TR0
DOWN(522)
MOVB(082) #0 #202 D16918
; rung 12
LD W438.09
ANDTSTN(351) D18775 &14
OUT TR0
UP(521)
MOVB(082) #FFFF #303 D16918
LD TR0
DOWN(522)
MOVB(082) #0 #303 D16918
; rung 13
LD W438.09
ANDTSTN(351) D18776 &6
OUT TR0
UP(521)
MOVB(082) #FFFF #404 D16918
LD TR0
DOWN(522)
MOVB(082) #0 #404 D16918
; rung 14
LD W438.09
ANDTSTN(351) D18776 &14
OUT TR0
UP(521)
MOVB(082) #FFFF #505 D16918
LD TR0
DOWN(522)
MOVB(082) #0 #505 D16918
; rung 15: ---------- 接着内層制御開始/停止 ----------
LD W438.09
ANDTSTN(351) D18777 &6
OUT TR0
UP(521)
MOVB(082) #FFFF #606 D16918
LD TR0
DOWN(522)
MOVB(082) #0 #606 D16918

; rung 16
LD W438.09
ANDTSTN(351) D18777 &14
OUT TR0
UP(521)
MOVB(082) #FFFF #707 D16918
LD TR0
DOWN(522)
MOVB(082) #0 #707 D16918
; rung 17
LD W438.09
ANDTSTN(351) D18778 &6
OUT TR0
UP(521)
MOVB(082) #FFFF #808 D16918
LD TR0
DOWN(522)
MOVB(082) #0 #808 D16918
; rung 18
LD W438.09
ANDTSTN(351) D18778 &14
OUT TR0
UP(521)
MOVB(082) #FFFF #909 D16918
LD TR0
DOWN(522)
MOVB(082) #0 #909 D16918
; rung 19
LD W438.09
ANDTSTN(351) D18779 &6
OUT TR0
UP(521)
MOVB(082) #FFFF #A0A D16918
LD TR0
DOWN(522)
MOVB(082) #0 #A0A D16918
; rung 20
LD W438.09
ANDTSTN(351) D18779 &14
OUT TR0
UP(521)
MOVB(082) #FFFF #B0B D16918
LD TR0
DOWN(522)
MOVB(082) #0 #B0B D16918

; rung 21: ---------- 接着外層制御開始/停止 ----------
LD W438.09
ANDTSTN(351) D18780 &6
OUT TR0
UP(521)
MOVB(082) #FFFF #C0C D16918
LD TR0
DOWN(522)
MOVB(082) #0 #C0C D16918
; rung 22
LD W438.09
ANDTSTN(351) D18780 &14
OUT TR0
UP(521)
MOVB(082) #FFFF #D0D D16918
LD TR0
DOWN(522)
MOVB(082) #0 #D0D D16918
; rung 23
LD W438.09
ANDTSTN(351) D18781 &6
OUT TR0
UP(521)
MOVB(082) #FFFF #E0E D16918
LD TR0
DOWN(522)
MOVB(082) #0 #E0E D16918
; rung 24
LD W438.09
ANDTSTN(351) D18781 &14
OUT TR0
UP(521)
MOVB(082) #FFFF #F0F D16918
LD TR0
DOWN(522)
MOVB(082) #0 #F0F D16918
; rung 25
LD W438.09
ANDTSTN(351) D18782 &6
OUT TR0
UP(521)
MOVB(082) #FFFF #0 D16919
LD TR0
DOWN(522)
MOVB(082) #0 #0 D16919

; rung 26
LD W438.09
ANDTSTN(351) D18782 &14
OUT TR0
UP(521)
MOVB(082) #FFFF #101 D16919
LD TR0
DOWN(522)
MOVB(082) #0 #101 D16919
; rung 27: ---------- ヘッド制御開始/停止 ----------
LD W433.13
ANDTSTN(351) D18783 &6
OUT TR0
UP(521)
MOVB(082) #FFFF #202 D16919
LD TR0
DOWN(522)
MOVB(082) #0 #202 D16919
; rung 28
LD W433.13
ANDTSTN(351) D18783 &14
OUT TR0
UP(521)
MOVB(082) #FFFF #303 D16919
LD TR0
DOWN(522)
MOVB(082) #0 #303 D16919
; rung 29
LD W433.13
ANDTSTN(351) D18784 &6
OUT TR0
UP(521)
MOVB(082) #FFFF #404 D16919
LD TR0
DOWN(522)
MOVB(082) #0 #404 D16919
; rung 30
LD W433.13
ANDTSTN(351) D18784 &14
OUT TR0
UP(521)
MOVB(082) #FFFF #505 D16919
LD TR0
DOWN(522)
MOVB(082) #0 #505 D16919

; rung 31
LD W433.13
ANDTSTN(351) D18785 &6
OUT TR0
UP(521)
MOVB(082) #FFFF #606 D16919
LD TR0
DOWN(522)
MOVB(082) #0 #606 D16919
; rung 32
LD W433.13
ANDTSTN(351) D18785 &14
OUT TR0
UP(521)
MOVB(082) #FFFF #707 D16919
LD TR0
DOWN(522)
MOVB(082) #0 #707 D16919
; rung 33
LD W433.13
AND 1.07
ANDTSTN(351) D18786 &6
OUT TR0
UP(521)
MOVB(082) #FFFF #808 D16919
LD TR0
DOWN(522)
MOVB(082) #0 #808 D16919
; rung 34
LD W433.13
AND 1.07
ANDTSTN(351) D18786 &14
OUT TR0
UP(521)
MOVB(082) #FFFF #909 D16919
LD TR0
DOWN(522)
MOVB(082) #0 #909 D16919
; rung 35: ---------- 主内/粉砕/主外樹脂温度 ----------
LD W433.12
ANDTSTN(351) D18787 &6
OUT TR0
UP(521)
MOVB(082) #FFFF #A0A D16919
LD TR0
DOWN(522)
MOVB(082) #0 #A0A D16919

; rung 36
LD W433.12
ANDTSTN(351) D18787 &14
OUT TR0
UP(521)
MOVB(082) #FFFF #B0B D16919
LD TR0
DOWN(522)
MOVB(082) #0 #B0B D16919
; rung 37
LD W438.09
ANDTSTN(351) D18788 &6
OUT TR0
UP(521)
MOVB(082) #FFFF #C0C D16919
LD TR0
DOWN(522)
MOVB(082) #0 #C0C D16919
; rung 38: ---------- ﾊﾞﾘﾔ/接内/接外/ﾘﾝｸﾞ樹脂温度 ----------
LD W438.09
ANDTSTN(351) D18789 &6
OUT TR0
UP(521)
MOVB(082) #FFFF #E0E D16919
LD TR0
DOWN(522)
MOVB(082) #0 #E0E D16919
; rung 39
LD W438.09
ANDTSTN(351) D18789 &14
OUT TR0
UP(521)
MOVB(082) #FFFF #F0F D16919
LD TR0
DOWN(522)
MOVB(082) #0 #F0F D16919
; rung 40
LD W438.09
ANDTSTN(351) D18790 &6
OUT TR0
UP(521)
MOVB(082) #FFFF #0 D16920
LD TR0
DOWN(522)
MOVB(082) #0 #0 D16920

; rung 41
LD W433.13
ANDTSTN(351) D18790 &14
OUT TR0
UP(521)
MOVB(082) #FFFF #101 D16920
LD TR0
DOWN(522)
MOVB(082) #0 #101 D16920
; rung 42: ---------- 3-1ch制御開始・停止処理 ----------
LDTST(350) D16918 &0
ANDTSTN(351) D16924 &0
LDTSTN(351) D16918 &0
ANDTST(350) D16924 &0
ORLD
AND=(300) D18799 #0
ANDNOT W410.03
AND H12.00
OR W411.00
AND T0999
ANDNOT W410.00
ANDNOT W411.01
OUT W411.00
@MOVB(082) D16918 #0 D16921
@MOV(021) #1 D18799
; rung 43
LD W411.00
OUT TR0
@SET H60.10
@BSET(071) #0 D18800 D18802
ANDTST(350) D16921 &0
@MOV(021) #2830 D18803
LD TR0
ANDTSTN(351) D16921 &0
@MOV(021) #2C30 D18803
; rung 44
LD W411.00
AND H60.10
AND=(300) D18400 #0
AND=(300) D18401 #0
AND=(300) D18402 #0
RSET H60.10
SET H60.11
@MOV(021) #1 D18802

; rung 45
LD W411.00
AND H60.11
AND=(300) D18402 #1
RSET H60.11
SET H60.12
@MOV(021) #0 D18802
; rung 46
LD W411.00
AND H60.12
AND=(300) D18402 #0
OUT W411.01
RSET H60.12
@MOVB(082) D16921 #0 D16924
@MOV(021) #0 D18799
; rung 47: ---------- 3-2ch制御開始・停止処理 ----------
LDTST(350) D16918 &1
ANDTSTN(351) D16924 &1
LDTSTN(351) D16918 &1
ANDTST(350) D16924 &1
ORLD
AND=(300) D18799 #0
ANDNOT W410.03
AND H12.01
OR W411.02
AND T0999
ANDNOT W410.00
ANDNOT W411.03
OUT W411.02
@MOVB(082) D16918 #101 D16921
@MOV(021) #1 D18799
; rung 48
LD W411.02
OUT TR0
@SET H60.13
@BSET(071) #0 D18800 D18802
ANDTST(350) D16921 &1
@MOV(021) #2832 D18803
LD TR0
ANDTSTN(351) D16921 &1
@MOV(021) #2C32 D18803

; rung 49
LD W411.02
AND H60.13
AND=(300) D18400 #0
AND=(300) D18401 #0
AND=(300) D18402 #0
RSET H60.13
SET H60.14
@MOV(021) #1 D18802
; rung 50
LD W411.02
AND H60.14
AND=(300) D18402 #1
RSET H60.14
SET H60.15
@MOV(021) #0 D18802
; rung 51
LD W411.02
AND H60.15
AND=(300) D18402 #0
OUT W411.03
RSET H60.15
@MOVB(082) D16921 #101 D16924
@MOV(021) #0 D18799
; rung 52: ---------- 4-1ch制御開始・停止処理 ----------
LDTST(350) D16918 &2
ANDTSTN(351) D16924 &2
LDTSTN(351) D16918 &2
ANDTST(350) D16924 &2
ORLD
AND=(300) D18799 #0
ANDNOT W410.03
AND H12.02
OR W411.04
AND T0999
ANDNOT W410.00
ANDNOT W411.05
OUT W411.04
@MOVB(082) D16918 #202 D16921
@MOV(021) #1 D18799

; rung 53
LD W411.04
OUT TR0
@SET H61.00
@BSET(071) #0 D18800 D18802
ANDTST(350) D16921 &2
@MOV(021) #2840 D18803
LD TR0
ANDTSTN(351) D16921 &2
@MOV(021) #2C40 D18803
; rung 54
LD W411.04
AND H61.00
AND=(300) D18400 #0
AND=(300) D18401 #0
AND=(300) D18402 #0
RSET H61.00
SET H61.01
@MOV(021) #1 D18802
; rung 55
LD W411.04
AND H61.01
AND=(300) D18402 #1
RSET H61.01
SET H61.02
@MOV(021) #0 D18802
; rung 56
LD W411.04
AND H61.02
AND=(300) D18402 #0
OUT W411.05
RSET H61.02
@MOVB(082) D16921 #202 D16924
@MOV(021) #0 D18799

; rung 57: ---------- 4-2ch制御開始・停止処理 ----------
LDTST(350) D16918 &3
ANDTSTN(351) D16924 &3
LDTSTN(351) D16918 &3
ANDTST(350) D16924 &3
ORLD
AND=(300) D18799 #0
ANDNOT W410.03
AND H12.03
OR W411.06
AND T0999
ANDNOT W410.00
ANDNOT W411.07
OUT W411.06
@MOVB(082) D16918 #303 D16921
@MOV(021) #1 D18799
; rung 58
LD W411.06
OUT TR0
@SET H61.03
@BSET(071) #0 D18800 D18802
ANDTST(350) D16921 &3
@MOV(021) #2842 D18803
LD TR0
ANDTSTN(351) D16921 &3
@MOV(021) #2C42 D18803
; rung 59
LD W411.06
AND H61.03
AND=(300) D18400 #0
AND=(300) D18401 #0
AND=(300) D18402 #0
RSET H61.03
SET H61.04
@MOV(021) #1 D18802
; rung 60
LD W411.06
AND H61.04
AND=(300) D18402 #1
RSET H61.04
SET H61.05
@MOV(021) #0 D18802

; rung 61
LD W411.06
AND H61.05
AND=(300) D18402 #0
OUT W411.07
RSET H61.05
@MOVB(082) D16921 #303 D16924
@MOV(021) #0 D18799
; rung 62: ---------- 5-1ch制御開始・停止処理 ----------
LDTST(350) D16918 &4
ANDTSTN(351) D16924 &4
LDTSTN(351) D16918 &4
ANDTST(350) D16924 &4
ORLD
AND=(300) D18799 #0
ANDNOT W410.03
AND H12.04
OR W411.08
AND T0999
ANDNOT W410.00
ANDNOT W411.09
OUT W411.08
@MOVB(082) D16918 #404 D16921
@MOV(021) #1 D18799
; rung 63
LD W411.08
OUT TR0
@SET H61.06
@BSET(071) #0 D18800 D18802
ANDTST(350) D16921 &4
@MOV(021) #2850 D18803
LD TR0
ANDTSTN(351) D16921 &4
@MOV(021) #2C50 D18803
; rung 64
LD W411.08
AND H61.06
AND=(300) D18400 #0
AND=(300) D18401 #0
AND=(300) D18402 #0
RSET H61.06
SET H61.07
@MOV(021) #1 D18802

; rung 65
LD W411.08
AND H61.07
AND=(300) D18402 #1
RSET H61.07
SET H61.08
@MOV(021) #0 D18802
; rung 66
LD W411.08
AND H61.08
AND=(300) D18402 #0
OUT W411.09
RSET H61.08
@MOVB(082) D16921 #404 D16924
@MOV(021) #0 D18799
; rung 67: ---------- 5-2ch制御開始・停止処理 ----------
LDTST(350) D16918 &5
ANDTSTN(351) D16924 &5
LDTSTN(351) D16918 &5
ANDTST(350) D16924 &5
ORLD
AND=(300) D18799 #0
ANDNOT W410.03
AND H12.05
OR W411.10
AND T0999
ANDNOT W410.00
ANDNOT W411.11
OUT W411.10
@MOVB(082) D16918 #505 D16921
@MOV(021) #1 D18799
; rung 68
LD W411.10
OUT TR0
@SET H61.09
@BSET(071) #0 D18800 D18802
ANDTST(350) D16921 &5
@MOV(021) #2852 D18803
LD TR0
ANDTSTN(351) D16921 &5
@MOV(021) #2C52 D18803

; rung 69
LD W411.10
AND H61.09
AND=(300) D18400 #0
AND=(300) D18401 #0
AND=(300) D18402 #0
RSET H61.09
SET H61.10
@MOV(021) #1 D18802
; rung 70
LD W411.10
AND H61.10
AND=(300) D18402 #1
RSET H61.10
SET H61.11
@MOV(021) #0 D18802
; rung 71
LD W411.10
AND H61.11
AND=(300) D18402 #0
OUT W411.11
RSET H61.11
@MOVB(082) D16921 #505 D16924
@MOV(021) #0 D18799
; rung 72: ---------- 6-1ch制御開始・停止処理 ----------
LDTST(350) D16918 &6
ANDTSTN(351) D16924 &6
LDTSTN(351) D16918 &6
ANDTST(350) D16924 &6
ORLD
AND=(300) D18799 #0
ANDNOT W410.03
AND H12.06
OR W411.12
AND T0999
ANDNOT W410.00
ANDNOT W411.13
OUT W411.12
@MOVB(082) D16918 #606 D16921
@MOV(021) #1 D18799

; rung 73
LD W411.12
OUT TR0
@SET H61.12
@BSET(071) #0 D18800 D18802
ANDTST(350) D16921 &6
@MOV(021) #2860 D18803
LD TR0
ANDTSTN(351) D16921 &6
@MOV(021) #2C60 D18803
; rung 74
LD W411.12
AND H61.12
AND=(300) D18400 #0
AND=(300) D18401 #0
AND=(300) D18402 #0
RSET H61.12
SET H61.13
@MOV(021) #1 D18802
; rung 75
LD W411.12
AND H61.13
AND=(300) D18402 #1
RSET H61.13
SET H61.14
@MOV(021) #0 D18802
; rung 76
LD W411.12
AND H61.14
AND=(300) D18402 #0
OUT W411.13
RSET H61.14
@MOVB(082) D16921 #606 D16924
@MOV(021) #0 D18799

; rung 77: ---------- 6-2ch制御開始・停止処理 ----------
LDTST(350) D16918 &7
ANDTSTN(351) D16924 &7
LDTSTN(351) D16918 &7
ANDTST(350) D16924 &7
ORLD
AND=(300) D18799 #0
ANDNOT W410.03
AND H12.07
OR W411.14
AND T0999
ANDNOT W410.00
ANDNOT W411.15
OUT W411.14
@MOVB(082) D16918 #707 D16921
@MOV(021) #1 D18799
; rung 78
LD W411.14
OUT TR0
@SET H61.15
@BSET(071) #0 D18800 D18802
ANDTST(350) D16921 &7
@MOV(021) #2862 D18803
LD TR0
ANDTSTN(351) D16921 &7
@MOV(021) #2C62 D18803
; rung 79
LD W411.14
AND H61.15
AND=(300) D18400 #0
AND=(300) D18401 #0
AND=(300) D18402 #0
RSET H61.15
SET H62.00
@MOV(021) #1 D18802
; rung 80
LD W411.14
AND H62.00
AND=(300) D18402 #1
RSET H62.00
SET H62.01
@MOV(021) #0 D18802

; rung 81
LD W411.14
AND H62.01
AND=(300) D18402 #0
OUT W411.15
RSET H62.01
@MOVB(082) D16921 #707 D16924
@MOV(021) #0 D18799
; rung 82: ---------- 7-1ch制御開始・停止処理 ----------
LDTST(350) D16918 &8
ANDTSTN(351) D16924 &8
LDTSTN(351) D16918 &8
ANDTST(350) D16924 &8
ORLD
AND=(300) D18799 #0
ANDNOT W410.03
AND H12.08
OR W412.00
AND T0999
ANDNOT W410.00
ANDNOT W412.01
OUT W412.00
@MOVB(082) D16918 #808 D16921
@MOV(021) #1 D18799
; rung 83
LD W412.00
OUT TR0
@SET H62.02
@BSET(071) #0 D18800 D18802
ANDTST(350) D16921 &8
@MOV(021) #2870 D18803
LD TR0
ANDTSTN(351) D16921 &8
@MOV(021) #2C70 D18803
; rung 84
LD W412.00
AND H62.02
AND=(300) D18400 #0
AND=(300) D18401 #0
AND=(300) D18402 #0
RSET H62.02
SET H62.03
@MOV(021) #1 D18802

; rung 85
LD W412.00
AND H62.03
AND=(300) D18402 #1
RSET H62.03
SET H62.04
@MOV(021) #0 D18802
; rung 86
LD W412.00
AND H62.04
AND=(300) D18402 #0
OUT W412.01
RSET H62.04
@MOVB(082) D16921 #808 D16924
@MOV(021) #0 D18799
; rung 87: ---------- 7-2ch制御開始・停止処理 ----------
LDTST(350) D16918 &9
ANDTSTN(351) D16924 &9
LDTSTN(351) D16918 &9
ANDTST(350) D16924 &9
ORLD
AND=(300) D18799 #0
ANDNOT W410.03
AND H12.09
OR W412.02
AND T0999
ANDNOT W410.00
ANDNOT W412.03
OUT W412.02
@MOVB(082) D16918 #909 D16921
@MOV(021) #1 D18799
; rung 88
LD W412.02
OUT TR0
@SET H62.05
@BSET(071) #0 D18800 D18802
ANDTST(350) D16921 &9
@MOV(021) #2872 D18803
LD TR0
ANDTSTN(351) D16921 &9
@MOV(021) #2C72 D18803

; rung 89
LD W412.02
AND H62.05
AND=(300) D18400 #0
AND=(300) D18401 #0
AND=(300) D18402 #0
RSET H62.05
SET H62.06
@MOV(021) #1 D18802
; rung 90
LD W412.02
AND H62.06
AND=(300) D18402 #1
RSET H62.06
SET H62.07
@MOV(021) #0 D18802
; rung 91
LD W412.02
AND H62.07
AND=(300) D18402 #0
OUT W412.03
RSET H62.07
@MOVB(082) D16921 #909 D16924
@MOV(021) #0 D18799
; rung 92: ---------- 8-1ch制御開始・停止処理 ----------
LDTST(350) D16918 &10
ANDTSTN(351) D16924 &10
LDTSTN(351) D16918 &10
ANDTST(350) D16924 &10
ORLD
AND=(300) D18799 #0
ANDNOT W410.03
AND H12.10
OR W412.04
AND T0999
ANDNOT W410.00
ANDNOT W412.05
OUT W412.04
@MOVB(082) D16918 #A0A D16921
@MOV(021) #1 D18799

; rung 93
LD W412.04
OUT TR0
@SET H62.08
@BSET(071) #0 D18800 D18802
ANDTST(350) D16921 &10
@MOV(021) #2880 D18803
LD TR0
ANDTSTN(351) D16921 &10
@MOV(021) #2C80 D18803
; rung 94
LD W412.04
AND H62.08
AND=(300) D18400 #0
AND=(300) D18401 #0
AND=(300) D18402 #0
RSET H62.08
SET H62.09
@MOV(021) #1 D18802
; rung 95
LD W412.04
AND H62.09
AND=(300) D18402 #1
RSET H62.09
SET H62.10
@MOV(021) #0 D18802
; rung 96
LD W412.04
AND H62.10
AND=(300) D18402 #0
OUT W412.05
RSET H62.10
@MOVB(082) D16921 #A0A D16924
@MOV(021) #0 D18799

; rung 97: ---------- 8-2ch制御開始・停止処理 ----------
LDTST(350) D16918 &11
ANDTSTN(351) D16924 &11
LDTSTN(351) D16918 &11
ANDTST(350) D16924 &11
ORLD
AND=(300) D18799 #0
ANDNOT W410.03
AND H12.11
OR W412.06
AND T0999
ANDNOT W410.00
ANDNOT W412.07
OUT W412.06
@MOVB(082) D16918 #B0B D16921
@MOV(021) #1 D18799
; rung 98
LD W412.06
OUT TR0
@SET H62.11
@BSET(071) #0 D18800 D18802
ANDTST(350) D16921 &11
@MOV(021) #2882 D18803
LD TR0
ANDTSTN(351) D16921 &11
@MOV(021) #2C82 D18803
; rung 99
LD W412.06
AND H62.11
AND=(300) D18400 #0
AND=(300) D18401 #0
AND=(300) D18402 #0
RSET H62.11
SET H62.12
@MOV(021) #1 D18802
; rung 100
LD W412.06
AND H62.12
AND=(300) D18402 #1
RSET H62.12
SET H62.13
@MOV(021) #0 D18802

; rung 101
LD W412.06
AND H62.13
AND=(300) D18402 #0
OUT W412.07
RSET H62.13
@MOVB(082) D16921 #B0B D16924
@MOV(021) #0 D18799
; rung 102: ---------- 9-1ch制御開始・停止処理 ----------
LDTST(350) D16918 &12
ANDTSTN(351) D16924 &12
LDTSTN(351) D16918 &12
ANDTST(350) D16924 &12
ORLD
AND=(300) D18799 #0
ANDNOT W410.03
AND H12.12
OR W412.08
AND T0999
ANDNOT W410.00
ANDNOT W412.09
OUT W412.08
@MOVB(082) D16918 #C0C D16921
@MOV(021) #1 D18799
; rung 103
LD W412.08
OUT TR0
@SET H62.14
@BSET(071) #0 D18800 D18802
ANDTST(350) D16921 &12
@MOV(021) #2890 D18803
LD TR0
ANDTSTN(351) D16921 &12
@MOV(021) #2C90 D18803
; rung 104
LD W412.08
AND H62.14
AND=(300) D18400 #0
AND=(300) D18401 #0
AND=(300) D18402 #0
RSET H62.14
SET H62.15
@MOV(021) #1 D18802

; rung 105
LD W412.08
AND H62.15
AND=(300) D18402 #1
RSET H62.15
SET H63.00
@MOV(021) #0 D18802
; rung 106
LD W412.08
AND H63.00
AND=(300) D18402 #0
OUT W412.09
RSET H63.00
@MOVB(082) D16921 #C0C D16924
@MOV(021) #0 D18799
; rung 107: ---------- 9-2ch制御開始・停止処理 ----------
LDTST(350) D16918 &13
ANDTSTN(351) D16924 &13
LDTSTN(351) D16918 &13
ANDTST(350) D16924 &13
ORLD
AND=(300) D18799 #0
ANDNOT W410.03
AND H12.13
OR W412.10
AND T0999
ANDNOT W410.00
ANDNOT W412.11
OUT W412.10
@MOVB(082) D16918 #D0D D16921
@MOV(021) #1 D18799
; rung 108
LD W412.10
OUT TR0
@SET H63.01
@BSET(071) #0 D18800 D18802
ANDTST(350) D16921 &13
@MOV(021) #2892 D18803
LD TR0
ANDTSTN(351) D16921 &13
@MOV(021) #2C92 D18803

; rung 109
LD W412.10
AND H63.01
AND=(300) D18400 #0
AND=(300) D18401 #0
AND=(300) D18402 #0
RSET H63.01
SET H63.02
@MOV(021) #1 D18802
; rung 110
LD W412.10
AND H63.02
AND=(300) D18402 #1
RSET H63.02
SET H63.03
@MOV(021) #0 D18802
; rung 111
LD W412.10
AND H63.03
AND=(300) D18402 #0
OUT W412.11
RSET H63.03
@MOVB(082) D16921 #D0D D16924
@MOV(021) #0 D18799
; rung 112: ---------- 10-1ch制御開始・停止処理 ----------
LDTST(350) D16918 &14
ANDTSTN(351) D16924 &14
LDTSTN(351) D16918 &14
ANDTST(350) D16924 &14
ORLD
AND=(300) D18799 #0
ANDNOT W410.03
AND H12.14
OR W412.12
AND T0999
ANDNOT W410.00
ANDNOT W412.13
OUT W412.12
@MOVB(082) D16918 #E0E D16921
@MOV(021) #1 D18799

; rung 113
LD W412.12
OUT TR0
@SET H63.04
@BSET(071) #0 D18800 D18802
ANDTST(350) D16921 &14
@MOV(021) #28A0 D18803
LD TR0
ANDTSTN(351) D16921 &14
@MOV(021) #2CA0 D18803
; rung 114
LD W412.12
AND H63.04
AND=(300) D18400 #0
AND=(300) D18401 #0
AND=(300) D18402 #0
RSET H63.04
SET H63.05
@MOV(021) #1 D18802
; rung 115
LD W412.12
AND H63.05
AND=(300) D18402 #1
RSET H63.05
SET H63.06
@MOV(021) #0 D18802
; rung 116
LD W412.12
AND H63.06
AND=(300) D18402 #0
OUT W412.13
RSET H63.06
@MOVB(082) D16921 #E0E D16924
@MOV(021) #0 D18799

; rung 117: ---------- 10-2ch制御開始・停止処理 ----------
LDTST(350) D16918 &15
ANDTSTN(351) D16924 &15
LDTSTN(351) D16918 &15
ANDTST(350) D16924 &15
ORLD
AND=(300) D18799 #0
ANDNOT W410.03
AND H12.15
OR W412.14
AND T0999
ANDNOT W410.00
ANDNOT W412.15
OUT W412.14
@MOVB(082) D16918 #F0F D16921
@MOV(021) #1 D18799
; rung 118
LD W412.14
OUT TR0
@SET H63.07
@BSET(071) #0 D18800 D18802
ANDTST(350) D16921 &15
@MOV(021) #28A2 D18803
LD TR0
ANDTSTN(351) D16921 &15
@MOV(021) #2CA2 D18803
; rung 119
LD W412.14
AND H63.07
AND=(300) D18400 #0
AND=(300) D18401 #0
AND=(300) D18402 #0
RSET H63.07
SET H63.08
@MOV(021) #1 D18802
; rung 120
LD W412.14
AND H63.08
AND=(300) D18402 #1
RSET H63.08
SET H63.09
@MOV(021) #0 D18802

; rung 121
LD W412.14
AND H63.09
AND=(300) D18402 #0
OUT W412.15
RSET H63.09
@MOVB(082) D16921 #F0F D16924
@MOV(021) #0 D18799
; rung 122: ---------- 11-1ch制御開始・停止処理 ----------
LDTST(350) D16919 &0
ANDTSTN(351) D16925 &0
LDTSTN(351) D16919 &0
ANDTST(350) D16925 &0
ORLD
AND=(300) D18799 #0
ANDNOT W410.03
AND H13.00
OR W413.00
AND T0999
ANDNOT W410.00
ANDNOT W413.01
OUT W413.00
@MOVB(082) D16919 #0 D16922
@MOV(021) #1 D18799
; rung 123
LD W413.00
OUT TR0
@SET H63.10
@BSET(071) #0 D18800 D18802
ANDTST(350) D16922 &0
@MOV(021) #28B0 D18803
LD TR0
ANDTSTN(351) D16922 &0
@MOV(021) #2CB0 D18803
; rung 124
LD W413.00
AND H63.10
AND=(300) D18400 #0
AND=(300) D18401 #0
AND=(300) D18402 #0
RSET H63.10
SET H63.11
@MOV(021) #1 D18802

; rung 125
LD W413.00
AND H63.11
AND=(300) D18402 #1
RSET H63.11
SET H63.12
@MOV(021) #0 D18802
; rung 126
LD W413.00
AND H63.12
AND=(300) D18402 #0
OUT W413.01
RSET H63.12
@MOVB(082) D16922 #0 D16925
@MOV(021) #0 D18799
; rung 127: ---------- 11-2ch制御開始・停止処理 ----------
LDTST(350) D16919 &1
ANDTSTN(351) D16925 &1
LDTSTN(351) D16919 &1
ANDTST(350) D16925 &1
ORLD
AND=(300) D18799 #0
ANDNOT W410.03
AND H13.01
OR W413.02
AND T0999
ANDNOT W410.00
ANDNOT W413.03
OUT W413.02
@MOVB(082) D16919 #101 D16922
@MOV(021) #1 D18799
; rung 128
LD W413.02
OUT TR0
@SET H63.13
@BSET(071) #0 D18800 D18802
ANDTST(350) D16922 &1
@MOV(021) #28B2 D18803
LD TR0
ANDTSTN(351) D16922 &1
@MOV(021) #2CB2 D18803

; rung 129
LD W413.02
AND H63.13
AND=(300) D18400 #0
AND=(300) D18401 #0
AND=(300) D18402 #0
RSET H63.13
SET H63.14
@MOV(021) #1 D18802
; rung 130
LD W413.02
AND H63.14
AND=(300) D18402 #1
RSET H63.14
SET H63.15
@MOV(021) #0 D18802
; rung 131
LD W413.02
AND H63.15
AND=(300) D18402 #0
OUT W413.03
RSET H63.15
@MOVB(082) D16922 #101 D16925
@MOV(021) #0 D18799
; rung 132: ---------- 12-1ch制御開始・停止処理 ----------
LDTST(350) D16919 &2
ANDTSTN(351) D16925 &2
LDTSTN(351) D16919 &2
ANDTST(350) D16925 &2
ORLD
AND=(300) D18799 #0
ANDNOT W410.03
AND H13.02
OR W413.04
AND T0999
ANDNOT W410.00
ANDNOT W413.05
OUT W413.04
@MOVB(082) D16919 #202 D16922
@MOV(021) #1 D18799

; rung 133
LD W413.04
OUT TR0
@SET H64.00
@BSET(071) #0 D18800 D18802
ANDTST(350) D16922 &2
@MOV(021) #28C0 D18803
LD TR0
ANDTSTN(351) D16922 &2
@MOV(021) #2CC0 D18803
; rung 134
LD W413.04
AND H64.00
AND=(300) D18400 #0
AND=(300) D18401 #0
AND=(300) D18402 #0
RSET H64.00
SET H64.01
@MOV(021) #1 D18802
; rung 135
LD W413.04
AND H64.01
AND=(300) D18402 #1
RSET H64.01
SET H64.02
@MOV(021) #0 D18802
; rung 136
LD W413.04
AND H64.02
AND=(300) D18402 #0
OUT W413.05
RSET H64.02
@MOVB(082) D16922 #202 D16925
@MOV(021) #0 D18799

; rung 137: ---------- 12-2ch制御開始・停止処理 ----------
LDTST(350) D16919 &3
ANDTSTN(351) D16925 &3
LDTSTN(351) D16919 &3
ANDTST(350) D16925 &3
ORLD
AND=(300) D18799 #0
ANDNOT W410.03
AND H13.03
OR W413.06
AND T0999
ANDNOT W410.00
ANDNOT W413.07
OUT W413.06
@MOVB(082) D16919 #303 D16922
@MOV(021) #1 D18799
; rung 138
LD W413.06
OUT TR0
@SET H64.03
@BSET(071) #0 D18800 D18802
ANDTST(350) D16922 &3
@MOV(021) #28C2 D18803
LD TR0
ANDTSTN(351) D16922 &3
@MOV(021) #2CC2 D18803
; rung 139
LD W413.06
AND H64.03
AND=(300) D18400 #0
AND=(300) D18401 #0
AND=(300) D18402 #0
RSET H64.03
SET H64.04
@MOV(021) #1 D18802
; rung 140
LD W413.06
AND H64.04
AND=(300) D18402 #1
RSET H64.04
SET H64.05
@MOV(021) #0 D18802

; rung 141
LD W413.06
AND H64.05
AND=(300) D18402 #0
OUT W413.07
RSET H64.05
@MOVB(082) D16922 #303 D16925
@MOV(021) #0 D18799
; rung 142: ---------- 13-1ch制御開始・停止処理 ----------
LDTST(350) D16919 &4
ANDTSTN(351) D16925 &4
LDTSTN(351) D16919 &4
ANDTST(350) D16925 &4
ORLD
AND=(300) D18799 #0
ANDNOT W410.03
AND H13.04
OR W413.08
AND T0999
ANDNOT W410.00
ANDNOT W413.09
OUT W413.08
@MOVB(082) D16919 #404 D16922
@MOV(021) #1 D18799
; rung 143
LD W413.08
OUT TR0
@SET H64.06
@BSET(071) #0 D18800 D18802
ANDTST(350) D16922 &4
@MOV(021) #28D0 D18803
LD TR0
ANDTSTN(351) D16922 &4
@MOV(021) #2CD0 D18803
; rung 144
LD W413.08
AND H64.06
AND=(300) D18400 #0
AND=(300) D18401 #0
AND=(300) D18402 #0
RSET H64.06
SET H64.07
@MOV(021) #1 D18802

; rung 145
LD W413.08
AND H64.07
AND=(300) D18402 #1
RSET H64.07
SET H64.08
@MOV(021) #0 D18802
; rung 146
LD W413.08
AND H64.08
AND=(300) D18402 #0
OUT W413.09
RSET H64.08
@MOVB(082) D16922 #404 D16925
@MOV(021) #0 D18799
; rung 147: ---------- 13-2ch制御開始・停止処理 ----------
LDTST(350) D16919 &5
ANDTSTN(351) D16925 &5
LDTSTN(351) D16919 &5
ANDTST(350) D16925 &5
ORLD
AND=(300) D18799 #0
ANDNOT W410.03
AND H13.05
OR W413.10
AND T0999
ANDNOT W410.00
ANDNOT W413.11
OUT W413.10
@MOVB(082) D16919 #505 D16922
@MOV(021) #1 D18799
; rung 148
LD W413.10
OUT TR0
@SET H64.09
@BSET(071) #0 D18800 D18802
ANDTST(350) D16922 &5
@MOV(021) #28D2 D18803
LD TR0
ANDTSTN(351) D16922 &5
@MOV(021) #2CD2 D18803

; rung 149
LD W413.10
AND H64.09
AND=(300) D18400 #0
AND=(300) D18401 #0
AND=(300) D18402 #0
RSET H64.09
SET H64.10
@MOV(021) #1 D18802
; rung 150
LD W413.10
AND H64.10
AND=(300) D18402 #1
RSET H64.10
SET H64.11
@MOV(021) #0 D18802
; rung 151
LD W413.10
AND H64.11
AND=(300) D18402 #0
OUT W413.11
RSET H64.11
@MOVB(082) D16922 #505 D16925
@MOV(021) #0 D18799
; rung 152: ---------- 14-1ch制御開始・停止処理 ----------
LDTST(350) D16919 &6
ANDTSTN(351) D16925 &6
LDTSTN(351) D16919 &6
ANDTST(350) D16925 &6
ORLD
AND=(300) D18799 #0
ANDNOT W410.03
AND H13.06
OR W413.12
AND T0999
ANDNOT W410.00
ANDNOT W413.13
OUT W413.12
@MOVB(082) D16919 #606 D16922
@MOV(021) #1 D18799

; rung 153
LD W413.12
OUT TR0
@SET H64.12
@BSET(071) #0 D18800 D18802
ANDTST(350) D16922 &6
@MOV(021) #28E0 D18803
LD TR0
ANDTSTN(351) D16922 &6
@MOV(021) #2CE0 D18803
; rung 154
LD W413.12
AND H64.12
AND=(300) D18400 #0
AND=(300) D18401 #0
AND=(300) D18402 #0
RSET H64.12
SET H64.13
@MOV(021) #1 D18802
; rung 155
LD W413.12
AND H64.13
AND=(300) D18402 #1
RSET H64.13
SET H64.14
@MOV(021) #0 D18802
; rung 156
LD W413.12
AND H64.14
AND=(300) D18402 #0
OUT W413.13
RSET H64.14
@MOVB(082) D16922 #606 D16925
@MOV(021) #0 D18799

; rung 157: ---------- 14-2ch制御開始・停止処理 ----------
LDTST(350) D16919 &7
ANDTSTN(351) D16925 &7
LDTSTN(351) D16919 &7
ANDTST(350) D16925 &7
ORLD
AND=(300) D18799 #0
ANDNOT W410.03
AND H13.07
OR W413.14
AND T0999
ANDNOT W410.00
ANDNOT W413.15
OUT W413.14
@MOVB(082) D16919 #707 D16922
@MOV(021) #1 D18799
; rung 158
LD W413.14
OUT TR0
@SET H64.15
@BSET(071) #0 D18800 D18802
ANDTST(350) D16922 &7
@MOV(021) #28E2 D18803
LD TR0
ANDTSTN(351) D16922 &7
@MOV(021) #2CE2 D18803
; rung 159
LD W413.14
AND H64.15
AND=(300) D18400 #0
AND=(300) D18401 #0
AND=(300) D18402 #0
RSET H64.15
SET H65.00
@MOV(021) #1 D18802
; rung 160
LD W413.14
AND H65.00
AND=(300) D18402 #1
RSET H65.00
SET H65.01
@MOV(021) #0 D18802

; rung 161
LD W413.14
AND H65.01
AND=(300) D18402 #0
OUT W413.15
RSET H65.01
@MOVB(082) D16922 #707 D16925
@MOV(021) #0 D18799
; rung 162: ---------- 15-1ch制御開始・停止処理 ----------
LDTST(350) D16919 &8
ANDTSTN(351) D16925 &8
LDTSTN(351) D16919 &8
ANDTST(350) D16925 &8
ORLD
AND=(300) D18799 #0
ANDNOT W410.03
AND H13.08
OR W414.00
AND T0999
ANDNOT W410.00
ANDNOT W414.01
OUT W414.00
@MOVB(082) D16919 #808 D16922
@MOV(021) #1 D18799
; rung 163
LD W414.00
OUT TR0
@SET H65.02
@BSET(071) #0 D18800 D18802
ANDTST(350) D16922 &8
@MOV(021) #28F0 D18803
LD TR0
ANDTSTN(351) D16922 &8
@MOV(021) #2CF0 D18803
; rung 164
LD W414.00
AND H65.02
AND=(300) D18400 #0
AND=(300) D18401 #0
AND=(300) D18402 #0
RSET H65.02
SET H65.03
@MOV(021) #1 D18802

; rung 165
LD W414.00
AND H65.03
AND=(300) D18402 #1
RSET H65.03
SET H65.04
@MOV(021) #0 D18802
; rung 166
LD W414.00
AND H65.04
AND=(300) D18402 #0
OUT W414.01
RSET H65.04
@MOVB(082) D16922 #808 D16925
@MOV(021) #0 D18799
; rung 167: ---------- 15-2ch制御開始・停止処理 ----------
LDTST(350) D16919 &9
ANDTSTN(351) D16925 &9
LDTSTN(351) D16919 &9
ANDTST(350) D16925 &9
ORLD
AND=(300) D18799 #0
ANDNOT W410.03
AND H13.09
OR W414.02
AND T0999
ANDNOT W410.00
ANDNOT W414.03
OUT W414.02
@MOVB(082) D16919 #909 D16922
@MOV(021) #1 D18799
; rung 168
LD W414.02
OUT TR0
@SET H65.05
@BSET(071) #0 D18800 D18802
ANDTST(350) D16922 &9
@MOV(021) #28F2 D18803
LD TR0
ANDTSTN(351) D16922 &9
@MOV(021) #2CF2 D18803

; rung 169
LD W414.02
AND H65.05
AND=(300) D18400 #0
AND=(300) D18401 #0
AND=(300) D18402 #0
RSET H65.05
SET H65.06
@MOV(021) #1 D18802
; rung 170
LD W414.02
AND H65.06
AND=(300) D18402 #1
RSET H65.06
SET H65.07
@MOV(021) #0 D18802
; rung 171
LD W414.02
AND H65.07
AND=(300) D18402 #0
OUT W414.03
RSET H65.07
@MOVB(082) D16922 #909 D16925
@MOV(021) #0 D18799
; rung 172: ---------- 16-1ch制御開始・停止処理 ----------
LDTST(350) D16919 &10
ANDTSTN(351) D16925 &10
LDTSTN(351) D16919 &10
ANDTST(350) D16925 &10
ORLD
AND=(300) D18799 #0
ANDNOT W410.03
AND H13.10
OR W414.04
AND T0999
ANDNOT W410.00
ANDNOT W414.05
OUT W414.04
@MOVB(082) D16919 #A0A D16922
@MOV(021) #1 D18799

; rung 173
LD W414.04
OUT TR0
@SET H65.08
@BSET(071) #0 D18800 D18802
ANDTST(350) D16922 &10
@MOV(021) #2900 D18803
LD TR0
ANDTSTN(351) D16922 &10
@MOV(021) #2D00 D18803
; rung 174
LD W414.04
AND H65.08
AND=(300) D18400 #0
AND=(300) D18401 #0
AND=(300) D18402 #0
RSET H65.08
SET H65.09
@MOV(021) #1 D18802
; rung 175
LD W414.04
AND H65.09
AND=(300) D18402 #1
RSET H65.09
SET H65.10
@MOV(021) #0 D18802
; rung 176
LD W414.04
AND H65.10
AND=(300) D18402 #0
OUT W414.05
RSET H65.10
@MOVB(082) D16922 #A0A D16925
@MOV(021) #0 D18799

; rung 177: ---------- 16-2ch制御開始・停止処理 ----------
LDTST(350) D16919 &11
ANDTSTN(351) D16925 &11
LDTSTN(351) D16919 &11
ANDTST(350) D16925 &11
ORLD
AND=(300) D18799 #0
ANDNOT W410.03
AND H13.11
OR W414.06
AND T0999
ANDNOT W410.00
ANDNOT W414.07
OUT W414.06
@MOVB(082) D16919 #B0B D16922
@MOV(021) #1 D18799
; rung 178
LD W414.06
OUT TR0
@SET H65.11
@BSET(071) #0 D18800 D18802
ANDTST(350) D16922 &11
@MOV(021) #2902 D18803
LD TR0
ANDTSTN(351) D16922 &11
@MOV(021) #2D02 D18803
; rung 179
LD W414.06
AND H65.11
AND=(300) D18400 #0
AND=(300) D18401 #0
AND=(300) D18402 #0
RSET H65.11
SET H65.12
@MOV(021) #1 D18802
; rung 180
LD W414.06
AND H65.12
AND=(300) D18402 #1
RSET H65.12
SET H65.13
@MOV(021) #0 D18802

; rung 181
LD W414.06
AND H65.13
AND=(300) D18402 #0
OUT W414.07
RSET H65.13
@MOVB(082) D16922 #B0B D16925
@MOV(021) #0 D18799
; rung 182: ---------- 16-3ch制御開始・停止処理 ----------
LDTST(350) D16919 &12
ANDTSTN(351) D16925 &12
LDTSTN(351) D16919 &12
ANDTST(350) D16925 &12
ORLD
AND=(300) D18799 #0
ANDNOT W410.03
AND H13.12
OR W414.08
AND T0999
ANDNOT W410.00
ANDNOT W414.09
OUT W414.08
@MOVB(082) D16919 #C0C D16922
@MOV(021) #1 D18799
; rung 183
LD W414.08
OUT TR0
@SET H65.14
@BSET(071) #0 D18800 D18802
ANDTST(350) D16922 &12
@MOV(021) #2904 D18803
LD TR0
ANDTSTN(351) D16922 &12
@MOV(021) #2D04 D18803
; rung 184
LD W414.08
AND H65.14
AND=(300) D18400 #0
AND=(300) D18401 #0
AND=(300) D18402 #0
RSET H65.14
SET H65.15
@MOV(021) #1 D18802

; rung 185
LD W414.08
AND H65.15
AND=(300) D18402 #1
RSET H65.15
SET H66.00
@MOV(021) #0 D18802
; rung 186
LD W414.08
AND H66.00
AND=(300) D18402 #0
OUT W414.09
RSET H66.00
@MOVB(082) D16922 #C0C D16925
@MOV(021) #0 D18799
; rung 187: ---------- 16-4ch制御開始・停止処理 ----------
LDTST(350) D16919 &13
ANDTSTN(351) D16925 &13
LDTSTN(351) D16919 &13
ANDTST(350) D16925 &13
ORLD
AND=(300) D18799 #0
ANDNOT W410.03
AND H13.13
OR W414.10
AND T0999
ANDNOT W410.00
ANDNOT W414.11
OUT W414.10
@MOVB(082) D16919 #D0D D16922
@MOV(021) #1 D18799
; rung 188
LD W414.10
OUT TR0
@SET H66.01
@BSET(071) #0 D18800 D18802
ANDTST(350) D16922 &13
@MOV(021) #2906 D18803
LD TR0
ANDTSTN(351) D16922 &13
@MOV(021) #2D06 D18803

; rung 189
LD W414.10
AND H66.01
AND=(300) D18400 #0
AND=(300) D18401 #0
AND=(300) D18402 #0
RSET H66.01
SET H66.02
@MOV(021) #1 D18802
; rung 190
LD W414.10
AND H66.02
AND=(300) D18402 #1
RSET H66.02
SET H66.03
@MOV(021) #0 D18802
; rung 191
LD W414.10
AND H66.03
AND=(300) D18402 #0
OUT W414.11
RSET H66.03
@MOVB(082) D16922 #D0D D16925
@MOV(021) #0 D18799
; rung 192: ---------- 17-1ch制御開始・停止処理 ----------
LDTST(350) D16919 &14
ANDTSTN(351) D16925 &14
LDTSTN(351) D16919 &14
ANDTST(350) D16925 &14
ORLD
AND=(300) D18799 #0
ANDNOT W410.03
AND H13.14
OR W414.12
AND T0999
ANDNOT W410.00
ANDNOT W414.13
OUT W414.12
@MOVB(082) D16919 #E0E D16922
@MOV(021) #1 D18799

; rung 193
LD W414.12
OUT TR0
@SET H66.04
@BSET(071) #0 D18800 D18802
ANDTST(350) D16922 &14
@MOV(021) #2910 D18803
LD TR0
ANDTSTN(351) D16922 &14
@MOV(021) #2D10 D18803
; rung 194
LD W414.12
AND H66.04
AND=(300) D18400 #0
AND=(300) D18401 #0
AND=(300) D18402 #0
RSET H66.04
SET H66.05
@MOV(021) #1 D18802
; rung 195
LD W414.12
AND H66.05
AND=(300) D18402 #1
RSET H66.05
SET H66.06
@MOV(021) #0 D18802
; rung 196
LD W414.12
AND H66.06
AND=(300) D18402 #0
OUT W414.13
RSET H66.06
@MOVB(082) D16922 #E0E D16925
@MOV(021) #0 D18799

; rung 197: ---------- 17-2ch制御開始・停止処理 ----------
LDTST(350) D16919 &15
ANDTSTN(351) D16925 &15
LDTSTN(351) D16919 &15
ANDTST(350) D16925 &15
ORLD
AND=(300) D18799 #0
ANDNOT W410.03
AND H13.15
OR W414.14
AND T0999
ANDNOT W410.00
ANDNOT W414.15
OUT W414.14
@MOVB(082) D16919 #F0F D16922
@MOV(021) #1 D18799
; rung 198
LD W414.14
OUT TR0
@SET H66.07
@BSET(071) #0 D18800 D18802
ANDTST(350) D16922 &15
@MOV(021) #2912 D18803
LD TR0
ANDTSTN(351) D16922 &15
@MOV(021) #2D12 D18803
; rung 199
LD W414.14
AND H66.07
AND=(300) D18400 #0
AND=(300) D18401 #0
AND=(300) D18402 #0
RSET H66.07
SET H66.08
@MOV(021) #1 D18802
; rung 200
LD W414.14
AND H66.08
AND=(300) D18402 #1
RSET H66.08
SET H66.09
@MOV(021) #0 D18802

; rung 201
LD W414.14
AND H66.09
AND=(300) D18402 #0
OUT W414.15
RSET H66.09
@MOVB(082) D16922 #F0F D16925
@MOV(021) #0 D18799
; rung 202: ---------- 17-3ch制御開始・停止処理 ----------
LDTST(350) D16920 &0
ANDTSTN(351) D16926 &0
LDTSTN(351) D16920 &0
ANDTST(350) D16926 &0
ORLD
AND=(300) D18799 #0
ANDNOT W410.03
AND H14.00
OR W415.00
AND T0999
ANDNOT W410.00
ANDNOT W415.01
OUT W415.00
@MOVB(082) D16920 #0 D16923
@MOV(021) #1 D18799
; rung 203
LD W415.00
OUT TR0
@SET H66.10
@BSET(071) #0 D18800 D18802
ANDTST(350) D16923 &0
@MOV(021) #2914 D18803
LD TR0
ANDTSTN(351) D16923 &0
@MOV(021) #2D14 D18803
; rung 204
LD W415.00
AND H66.10
AND=(300) D18400 #0
AND=(300) D18401 #0
AND=(300) D18402 #0
RSET H66.10
SET H66.11
@MOV(021) #1 D18802

; rung 205
LD W415.00
AND H66.11
AND=(300) D18402 #1
RSET H66.11
SET H66.12
@MOV(021) #0 D18802
; rung 206
LD W415.00
AND H66.12
AND=(300) D18402 #0
OUT W415.01
RSET H66.12
@MOVB(082) D16923 #0 D16926
@MOV(021) #0 D18799
; rung 207: ---------- 17-4ch制御開始・停止処理 ----------
LDTST(350) D16920 &1
ANDTSTN(351) D16926 &1
LDTSTN(351) D16920 &1
ANDTST(350) D16926 &1
ORLD
AND=(300) D18799 #0
ANDNOT W410.03
AND H14.01
OR W415.02
AND T0999
ANDNOT W410.00
ANDNOT W415.03
OUT W415.02
@MOVB(082) D16920 #101 D16923
@MOV(021) #1 D18799
; rung 208
LD W415.02
OUT TR0
@SET H66.13
@BSET(071) #0 D18800 D18802
ANDTST(350) D16923 &1
@MOV(021) #2916 D18803
LD TR0
ANDTSTN(351) D16923 &1
@MOV(021) #2D16 D18803

; rung 209
LD W415.02
AND H66.13
AND=(300) D18400 #0
AND=(300) D18401 #0
AND=(300) D18402 #0
RSET H66.13
SET H66.14
@MOV(021) #1 D18802
; rung 210
LD W415.02
AND H66.14
AND=(300) D18402 #1
RSET H66.14
SET H66.15
@MOV(021) #0 D18802
; rung 211
LD W415.02
AND H66.15
AND=(300) D18402 #0
OUT W415.03
RSET H66.15
@MOVB(082) D16923 #101 D16926
@MOV(021) #0 D18799
; rung 212: ********** EJ1読出処理 **********
LD=(300) D18799 #0
AND T0999
ANDNOT W410.00
OUT W410.07

; rung 213
LD W410.07
OUT TR0
@SET H60.08
@BSET(071) #0 D18800 D18802
AND H60.08
AND=(300) D18400 #0
AND=(300) D18401 #0
AND=(300) D18402 #0
RSET H60.08
SET H60.09
@MOV(021) #2 D18800
LD TR0
LD=(300) D18400 #2
OR=(300) D18400 #8002
ANDLD
AND H60.09
RSET H60.09
; rung 214
LDNOT H60.08
ANDNOT H60.09
OUTNOT W410.03

### Section EJ1_HFU0_ALARM

; rung 0: ********** HFU0系統異常処理 **********
LD T0999
IL(002)
; rung 1: ---------- HFU0異常詳細 ----------
LD<>(305) H10 #0
OR<>(305) H11 #0
OUT TR0
ANDTST(350) D19204 &0
MOVB(082) #1 #0 D19573
LD TR0
ANDTST(350) D19204 &1
MOVB(082) #1 #100 D19573
LD TR0
ANDTST(350) D19204 &3
MOVB(082) #1 #300 D19573
LD TR0
ANDTST(350) D19204 &4
MOVB(082) #1 #400 D19573
LD TR0
ANDTST(350) D19204 &6
MOVB(082) #1 #600 D19573
LD TR0
LD T0998
OR T0985
OR W400.00
ANDLD
MOVB(082) #1 #F00 D19573

; rung 2: ---------- 0-3-1ch 異常詳細 ----------
LD H10.00
OUT TR0
ANDTST(350) D19205 &0
MOVB(082) #1 #0 D19574
LD TR0
ANDTST(350) D19247 &8
MOVB(082) #1 #100 D19574
LD TR0
ANDTST(350) D19275 &0
MOVB(082) #1 #200 D19574
LD TR0
ANDTSTN(351) D19247 &0
AND T0977
OUT TR1
ANDTST(350) D19275 &1
MOVB(082) #1 #300 D19574
LD TR1
ANDTST(350) D19275 &4
MOVB(082) #1 #400 D19574
LD TR1
ANDTST(350) D19275 &5
MOVB(082) #1 #500 D19574
LD TR0
ANDTST(350) D19275 &6
MOVB(082) #1 #600 D19574
LD TR0
ANDTST(350) D19275 &7
MOVB(082) #1 #700 D19574

; rung 3: ---------- 0-3-2ch 異常詳細 ----------
LD H10.01
OUT TR0
ANDTST(350) D19205 &0
MOVB(082) #1 #800 D19574
LD TR0
ANDTST(350) D19248 &8
MOVB(082) #1 #900 D19574
LD TR0
ANDTST(350) D19276 &0
MOVB(082) #1 #A00 D19574
LD TR0
ANDTSTN(351) D19248 &0
AND T0977
OUT TR1
ANDTST(350) D19276 &1
MOVB(082) #1 #B00 D19574
LD TR1
ANDTST(350) D19276 &4
MOVB(082) #1 #C00 D19574
LD TR1
ANDTST(350) D19276 &5
MOVB(082) #1 #D00 D19574
LD TR0
ANDTST(350) D19276 &6
MOVB(082) #1 #E00 D19574
LD TR0
ANDTST(350) D19276 &7
MOVB(082) #1 #F00 D19574

; rung 4: ---------- 0-4-1ch 異常詳細 ----------
LD H10.02
OUT TR0
ANDTST(350) D19206 &0
MOVB(082) #1 #0 D19575
LD TR0
ANDTST(350) D19249 &8
MOVB(082) #1 #100 D19575
LD TR0
ANDTST(350) D19277 &0
MOVB(082) #1 #200 D19575
LD TR0
ANDTSTN(351) D19249 &0
AND T0977
OUT TR1
ANDTST(350) D19277 &1
MOVB(082) #1 #300 D19575
LD TR1
ANDTST(350) D19277 &4
MOVB(082) #1 #400 D19575
LD TR1
ANDTST(350) D19277 &5
MOVB(082) #1 #500 D19575
LD TR0
ANDTST(350) D19277 &6
MOVB(082) #1 #600 D19575
LD TR0
ANDTST(350) D19277 &7
MOVB(082) #1 #700 D19575

; rung 5: ---------- 0-4-2ch 異常詳細 ----------
LD H10.03
OUT TR0
ANDTST(350) D19206 &0
MOVB(082) #1 #800 D19575
LD TR0
ANDTST(350) D19250 &8
MOVB(082) #1 #900 D19575
LD TR0
ANDTST(350) D19278 &0
MOVB(082) #1 #A00 D19575
LD TR0
ANDTSTN(351) D19250 &0
AND T0977
OUT TR1
ANDTST(350) D19278 &1
MOVB(082) #1 #B00 D19575
LD TR1
ANDTST(350) D19278 &4
MOVB(082) #1 #C00 D19575
LD TR1
ANDTST(350) D19278 &5
MOVB(082) #1 #D00 D19575
LD TR0
ANDTST(350) D19278 &6
MOVB(082) #1 #E00 D19575
LD TR0
ANDTST(350) D19278 &7
MOVB(082) #1 #F00 D19575

; rung 6: ---------- 0-5-1ch 異常詳細 ----------
LD H10.04
OUT TR0
ANDTST(350) D19207 &0
MOVB(082) #1 #0 D19576
LD TR0
ANDTST(350) D19251 &8
MOVB(082) #1 #100 D19576
LD TR0
ANDNOT P_On
OUT TR0
ANDTST(350) D19279 &0
MOVB(082) #1 #200 D19576
LD TR0
ANDTST(350) D19279 &1
ANDTSTN(351) D19251 &0
AND T0977
MOVB(082) #1 #300 D19576
LD TR0
ANDNOT P_On
OUT TR0
ANDTST(350) D19279 &4
MOVB(082) #1 #400 D19576
LD TR0
ANDTST(350) D19279 &5
MOVB(082) #1 #500 D19576
LD TR0
ANDTST(350) D19279 &6
MOVB(082) #1 #600 D19576
LD TR0
ANDTST(350) D19279 &7
MOVB(082) #1 #700 D19576

; rung 7: ---------- 0-5-2ch 異常詳細 ----------
LD H10.05
OUT TR0
ANDTST(350) D19207 &0
MOVB(082) #1 #800 D19576
LD TR0
ANDTST(350) D19252 &8
MOVB(082) #1 #900 D19576
LD TR0
ANDNOT P_On
OUT TR0
ANDTST(350) D19280 &0
MOVB(082) #1 #A00 D19576
LD TR0
ANDTSTN(351) D19252 &0
AND T0977
OUT TR1
ANDTST(350) D19280 &1
MOVB(082) #1 #B00 D19576
LD TR1
ANDTST(350) D19280 &4
MOVB(082) #1 #C00 D19576
LD TR1
ANDTST(350) D19280 &5
MOVB(082) #1 #D00 D19576
LD TR0
ANDTST(350) D19280 &6
MOVB(082) #1 #E00 D19576
LD TR0
ANDTST(350) D19280 &7
MOVB(082) #1 #F00 D19576

; rung 8: ---------- 0-6-1ch 異常詳細 ----------
LD H10.06
OUT TR0
ANDTST(350) D19208 &0
MOVB(082) #1 #0 D19577
LD TR0
ANDTST(350) D19253 &8
MOVB(082) #1 #100 D19577
LD TR0
ANDTST(350) D19281 &0
MOVB(082) #1 #200 D19577
LD TR0
ANDTSTN(351) D19253 &0
AND T0977
OUT TR1
ANDTST(350) D19281 &1
MOVB(082) #1 #300 D19577
LD TR1
ANDTST(350) D19281 &4
MOVB(082) #1 #400 D19577
LD TR1
ANDTST(350) D19281 &5
MOVB(082) #1 #500 D19577
LD TR0
ANDTST(350) D19281 &6
MOVB(082) #1 #600 D19577
LD TR0
ANDTST(350) D19281 &7
MOVB(082) #1 #700 D19577

; rung 9: ---------- 0-6-2ch 異常詳細 ----------
LD H10.07
OUT TR0
ANDTST(350) D19208 &0
MOVB(082) #1 #800 D19577
LD TR0
ANDTST(350) D19254 &8
MOVB(082) #1 #900 D19577
LD TR0
ANDTST(350) D19282 &0
MOVB(082) #1 #A00 D19577
LD TR0
ANDTSTN(351) D19254 &0
AND T0977
OUT TR1
ANDTST(350) D19282 &1
MOVB(082) #1 #B00 D19577
LD TR1
ANDTST(350) D19282 &4
MOVB(082) #1 #C00 D19577
LD TR1
ANDTST(350) D19282 &5
MOVB(082) #1 #D00 D19577
LD TR0
ANDTST(350) D19282 &6
MOVB(082) #1 #E00 D19577
LD TR0
ANDTST(350) D19282 &7
MOVB(082) #1 #F00 D19577

; rung 10: ---------- 0-7-1ch 異常詳細 ----------
LD H10.08
OUT TR0
ANDTST(350) D19209 &0
MOVB(082) #1 #0 D19578
LD TR0
ANDTST(350) D19255 &8
MOVB(082) #1 #100 D19578
LD TR0
ANDTST(350) D19283 &0
MOVB(082) #1 #200 D19578
LD TR0
ANDTSTN(351) D19255 &0
AND T0977
OUT TR1
ANDTST(350) D19283 &1
MOVB(082) #1 #300 D19578
LD TR1
ANDTST(350) D19283 &4
MOVB(082) #1 #400 D19578
LD TR1
ANDTST(350) D19283 &5
MOVB(082) #1 #500 D19578
LD TR0
ANDTST(350) D19283 &6
MOVB(082) #1 #600 D19578
LD TR0
ANDTST(350) D19283 &7
MOVB(082) #1 #700 D19578

; rung 11: ---------- 0-7-2ch 異常詳細 ----------
LD H10.09
OUT TR0
ANDTST(350) D19209 &0
MOVB(082) #1 #800 D19578
LD TR0
ANDTST(350) D19256 &8
MOVB(082) #1 #900 D19578
LD TR0
ANDTST(350) D19284 &0
MOVB(082) #1 #A00 D19578
LD TR0
ANDTSTN(351) D19256 &0
AND T0977
OUT TR1
ANDTST(350) D19284 &1
MOVB(082) #1 #B00 D19578
LD TR1
ANDTST(350) D19284 &4
MOVB(082) #1 #C00 D19578
LD TR1
ANDTST(350) D19284 &5
MOVB(082) #1 #D00 D19578
LD TR0
ANDTST(350) D19284 &6
MOVB(082) #1 #E00 D19578
LD TR0
ANDTST(350) D19284 &7
MOVB(082) #1 #F00 D19578

; rung 12: ---------- 0-8-1ch 異常詳細 ----------
LD H10.10
OUT TR0
ANDTST(350) D19210 &0
MOVB(082) #1 #0 D19579
LD TR0
ANDTST(350) D19257 &8
MOVB(082) #1 #100 D19579
LD TR0
ANDTST(350) D19285 &0
MOVB(082) #1 #200 D19579
LD TR0
ANDTSTN(351) D19257 &0
AND T0977
OUT TR1
ANDTST(350) D19285 &1
MOVB(082) #1 #300 D19579
LD TR1
ANDTST(350) D19285 &4
MOVB(082) #1 #400 D19579
LD TR1
ANDTST(350) D19285 &5
MOVB(082) #1 #500 D19579
LD TR0
ANDTST(350) D19285 &6
MOVB(082) #1 #600 D19579
LD TR0
ANDTST(350) D19285 &7
MOVB(082) #1 #700 D19579

; rung 13: ---------- 0-8-2ch 異常詳細 ----------
LD H10.11
OUT TR0
ANDTST(350) D19210 &0
MOVB(082) #1 #800 D19579
LD TR0
ANDTST(350) D19257 &8
MOVB(082) #1 #900 D19579
LD TR0
ANDTST(350) D19286 &0
MOVB(082) #1 #A00 D19579
LD TR0
ANDTSTN(351) D19258 &0
AND T0977
OUT TR1
ANDTST(350) D19286 &1
MOVB(082) #1 #B00 D19579
LD TR1
ANDTST(350) D19286 &4
MOVB(082) #1 #C00 D19579
LD TR1
ANDTST(350) D19286 &5
MOVB(082) #1 #D00 D19579
LD TR0
ANDTST(350) D19286 &6
MOVB(082) #1 #E00 D19579
LD TR0
ANDTST(350) D19286 &7
MOVB(082) #1 #F00 D19579

; rung 14: ---------- 0-9-1ch 異常詳細 ----------
LD H10.12
OUT TR0
ANDTST(350) D19211 &0
MOVB(082) #1 #0 D19580
LD TR0
ANDTST(350) D19259 &8
MOVB(082) #1 #100 D19580
LD TR0
ANDTST(350) D19287 &0
MOVB(082) #1 #200 D19580
LD TR0
ANDTSTN(351) D19259 &0
AND T0977
OUT TR1
ANDTST(350) D19287 &1
MOVB(082) #1 #300 D19580
LD TR1
ANDTST(350) D19287 &4
MOVB(082) #1 #400 D19580
LD TR1
ANDTST(350) D19287 &5
MOVB(082) #1 #500 D19580
LD TR0
ANDTST(350) D19287 &6
MOVB(082) #1 #600 D19580
LD TR0
ANDTST(350) D19287 &7
MOVB(082) #1 #700 D19580

; rung 15: ---------- 0-9-2ch 異常詳細 ----------
LD H10.13
OUT TR0
ANDTST(350) D19211 &0
MOVB(082) #1 #800 D19580
LD TR0
ANDTST(350) D19260 &8
MOVB(082) #1 #900 D19580
LD TR0
ANDNOT P_On
OUT TR0
ANDTST(350) D19288 &0
MOVB(082) #1 #A00 D19580
LD TR0
ANDTST(350) D19288 &1
ANDTSTN(351) D19260 &0
AND T0977
MOVB(082) #1 #B00 D19580
LD TR0
ANDNOT P_On
OUT TR0
ANDTST(350) D19288 &4
MOVB(082) #1 #C00 D19580
LD TR0
ANDTST(350) D19288 &5
MOVB(082) #1 #D00 D19580
LD TR0
ANDTST(350) D19288 &6
MOVB(082) #1 #E00 D19580
LD TR0
ANDTST(350) D19288 &7
MOVB(082) #1 #F00 D19580

; rung 16: ---------- 0-10-1ch 異常詳細 ----------
LD H10.14
OUT TR0
ANDTST(350) D19212 &0
MOVB(082) #1 #0 D19581
LD TR0
ANDTST(350) D19261 &8
MOVB(082) #1 #100 D19581
LD TR0
ANDTST(350) D19289 &0
MOVB(082) #1 #200 D19581
LD TR0
ANDTSTN(351) D19261 &0
AND T0977
OUT TR1
ANDTST(350) D19289 &1
MOVB(082) #1 #300 D19581
LD TR1
ANDTST(350) D19289 &4
MOVB(082) #1 #400 D19581
LD TR1
ANDTST(350) D19289 &5
MOVB(082) #1 #500 D19581
LD TR0
ANDTST(350) D19289 &6
MOVB(082) #1 #600 D19581
LD TR0
ANDTST(350) D19289 &7
MOVB(082) #1 #700 D19581

; rung 17: ---------- 0-10-2ch 異常詳細 ----------
LD H10.15
OUT TR0
ANDTST(350) D19212 &0
MOVB(082) #1 #800 D19581
LD TR0
ANDTST(350) D19262 &8
MOVB(082) #1 #900 D19581
LD TR0
ANDTST(350) D19290 &0
MOVB(082) #1 #A00 D19581
LD TR0
ANDTSTN(351) D19262 &0
AND T0977
OUT TR1
ANDTST(350) D19290 &1
MOVB(082) #1 #B00 D19581
LD TR1
ANDTST(350) D19290 &4
MOVB(082) #1 #C00 D19581
LD TR1
ANDTST(350) D19290 &5
MOVB(082) #1 #D00 D19581
LD TR0
ANDTST(350) D19290 &6
MOVB(082) #1 #E00 D19581
LD TR0
ANDTST(350) D19290 &7
MOVB(082) #1 #F00 D19581

; rung 18: ---------- 0-11-1ch 異常詳細 ----------
LD H11.00
OUT TR0
ANDTST(350) D19213 &0
MOVB(082) #1 #0 D19582
LD TR0
ANDTST(350) D19263 &8
MOVB(082) #1 #100 D19582
LD TR0
ANDTST(350) D19291 &0
MOVB(082) #1 #200 D19582
LD TR0
ANDTSTN(351) D19263 &0
AND T0978
OUT TR1
ANDTST(350) D19291 &1
MOVB(082) #1 #300 D19582
LD TR1
ANDTST(350) D19291 &4
MOVB(082) #1 #400 D19582
LD TR1
ANDTST(350) D19291 &5
MOVB(082) #1 #500 D19582
LD TR0
ANDTST(350) D19291 &6
MOVB(082) #1 #600 D19582
LD TR0
ANDTST(350) D19291 &7
MOVB(082) #1 #700 D19582

; rung 19: ---------- 0-11-2ch 異常詳細 ----------
LD H11.01
OUT TR0
ANDTST(350) D19213 &0
MOVB(082) #1 #800 D19582
LD TR0
ANDTST(350) D19264 &8
MOVB(082) #1 #900 D19582
LD TR0
ANDTST(350) D19292 &0
MOVB(082) #1 #A00 D19582
LD TR0
ANDTSTN(351) D19264 &0
AND T0978
OUT TR1
ANDTST(350) D19292 &1
MOVB(082) #1 #B00 D19582
LD TR1
ANDTST(350) D19292 &4
MOVB(082) #1 #C00 D19582
LD TR1
ANDTST(350) D19292 &5
MOVB(082) #1 #D00 D19582
LD TR0
ANDTST(350) D19292 &6
MOVB(082) #1 #E00 D19582
LD TR0
ANDTST(350) D19292 &7
MOVB(082) #1 #F00 D19582

; rung 20: ---------- 0-12-1ch 異常詳細 ----------
LD H11.02
OUT TR0
ANDTST(350) D19214 &0
MOVB(082) #1 #0 D19583
LD TR0
ANDTST(350) D19265 &8
MOVB(082) #1 #100 D19583
LD TR0
ANDTST(350) D19293 &0
MOVB(082) #1 #200 D19583
LD TR0
ANDTSTN(351) D19265 &0
AND T0978
OUT TR1
ANDTST(350) D19293 &1
MOVB(082) #1 #300 D19583
LD TR1
ANDTST(350) D19293 &4
MOVB(082) #1 #400 D19583
LD TR1
ANDTST(350) D19293 &5
MOVB(082) #1 #500 D19583
LD TR0
ANDTST(350) D19293 &6
MOVB(082) #1 #600 D19583
LD TR0
ANDTST(350) D19293 &7
MOVB(082) #1 #700 D19583

; rung 21: ---------- 0-12-2ch 異常詳細 ----------
LD H11.03
OUT TR0
ANDTST(350) D19214 &0
MOVB(082) #1 #800 D19583
LD TR0
ANDTST(350) D19266 &8
MOVB(082) #1 #900 D19583
LD TR0
ANDTST(350) D19294 &0
MOVB(082) #1 #A00 D19583
LD TR0
ANDTSTN(351) D19266 &0
AND T0978
OUT TR1
ANDTST(350) D19294 &1
MOVB(082) #1 #B00 D19583
LD TR1
ANDTST(350) D19294 &4
MOVB(082) #1 #C00 D19583
LD TR1
ANDTST(350) D19294 &5
MOVB(082) #1 #D00 D19583
LD TR0
ANDTST(350) D19294 &6
MOVB(082) #1 #E00 D19583
LD TR0
ANDTST(350) D19294 &7
MOVB(082) #1 #F00 D19583

; rung 22: ---------- 0-13-1ch 異常詳細 ----------
LD H11.04
OUT TR0
ANDTST(350) D19215 &0
MOVB(082) #1 #0 D19584
LD TR0
ANDTST(350) D19267 &8
MOVB(082) #1 #100 D19584
LD TR0
ANDNOT P_On
OUT TR0
ANDTST(350) D19295 &0
MOVB(082) #1 #200 D19584
LD TR0
ANDTST(350) D19295 &1
ANDTSTN(351) D19267 &0
AND T0978
MOVB(082) #1 #300 D19584
LD TR0
ANDNOT P_On
OUT TR0
ANDTST(350) D19295 &4
MOVB(082) #1 #400 D19584
LD TR0
ANDTST(350) D19295 &5
MOVB(082) #1 #500 D19584
LD TR0
ANDTST(350) D19295 &6
MOVB(082) #1 #600 D19584
LD TR0
ANDTST(350) D19295 &7
MOVB(082) #1 #700 D19584

; rung 23: ---------- 0-13-2ch 異常詳細 ----------
LD H11.05
OUT TR0
ANDTST(350) D19215 &0
MOVB(082) #1 #800 D19584
LD TR0
ANDTST(350) D19268 &8
MOVB(082) #1 #900 D19584
LD TR0
ANDTST(350) D19296 &0
MOVB(082) #1 #A00 D19584
LD TR0
ANDTSTN(351) D19268 &0
AND T0978
OUT TR1
ANDTST(350) D19296 &1
MOVB(082) #1 #B00 D19584
LD TR1
ANDTST(350) D19296 &4
MOVB(082) #1 #C00 D19584
LD TR1
ANDTST(350) D19296 &5
MOVB(082) #1 #D00 D19584
LD TR0
ANDTST(350) D19296 &6
MOVB(082) #1 #E00 D19584
LD TR0
ANDTST(350) D19296 &7
MOVB(082) #1 #F00 D19584

; rung 24: ---------- 0-14-1ch 異常詳細 ----------
LD H11.06
OUT TR0
ANDTST(350) D19216 &0
MOVB(082) #1 #0 D19585
LD TR0
ANDTST(350) D19269 &8
MOVB(082) #1 #100 D19585
LD TR0
ANDTST(350) D19297 &0
MOVB(082) #1 #200 D19585
LD TR0
ANDTSTN(351) D19269 &0
AND T0978
OUT TR1
ANDTST(350) D19297 &1
MOVB(082) #1 #300 D19585
LD TR1
ANDTST(350) D19297 &4
MOVB(082) #1 #400 D19585
LD TR1
ANDTST(350) D19297 &5
MOVB(082) #1 #500 D19585
LD TR0
ANDTST(350) D19297 &6
MOVB(082) #1 #600 D19585
LD TR0
ANDTST(350) D19297 &7
MOVB(082) #1 #700 D19585

; rung 25: ---------- 0-14-2ch 異常詳細 ----------
LD H11.07
OUT TR0
ANDTST(350) D19216 &0
MOVB(082) #1 #800 D19585
LD TR0
ANDTST(350) D19270 &8
MOVB(082) #1 #900 D19585
LD TR0
ANDTST(350) D19298 &0
MOVB(082) #1 #A00 D19585
LD TR0
ANDTSTN(351) D19270 &0
AND T0978
OUT TR1
ANDTST(350) D19298 &1
MOVB(082) #1 #B00 D19585
LD TR1
ANDTST(350) D19298 &4
MOVB(082) #1 #C00 D19585
LD TR1
ANDTST(350) D19298 &5
MOVB(082) #1 #D00 D19585
LD TR0
ANDTST(350) D19298 &6
MOVB(082) #1 #E00 D19585
LD TR0
ANDTST(350) D19298 &7
MOVB(082) #1 #F00 D19585

; rung 26: ---------- 0-15-1ch 異常詳細 ----------
LD H11.08
OUT TR0
ANDTST(350) D19217 &0
MOVB(082) #1 #0 D19586
LD TR0
ANDTST(350) D19271 &8
MOVB(082) #1 #100 D19586
LD TR0
ANDTST(350) D19299 &0
MOVB(082) #1 #200 D19586
LD TR0
ANDTST(350) D19299 &1
ANDTSTN(351) D19271 &0
AND T0978
MOVB(082) #1 #300 D19586
LD TR0
ANDTST(350) D19299 &4
MOVB(082) #1 #400 D19586
LD TR0
ANDTST(350) D19299 &5
MOVB(082) #1 #500 D19586
LD TR0
ANDTST(350) D19299 &6
MOVB(082) #1 #600 D19586
LD TR0
ANDTST(350) D19299 &7
MOVB(082) #1 #700 D19586

; rung 27: ---------- 0-15-2ch 異常詳細 ----------
LD H11.09
OUT TR0
ANDTST(350) D19217 &0
MOVB(082) #1 #800 D19586
LD TR0
ANDTST(350) D19272 &8
MOVB(082) #1 #900 D19586
LD TR0
ANDTST(350) D19300 &0
MOVB(082) #1 #A00 D19586
LD TR0
ANDTSTN(351) D19272 &0
AND T0978
OUT TR1
ANDTST(350) D19300 &1
MOVB(082) #1 #B00 D19586
LD TR1
ANDTST(350) D19300 &4
MOVB(082) #1 #C00 D19586
LD TR1
ANDTST(350) D19300 &5
MOVB(082) #1 #D00 D19586
LD TR0
ANDTST(350) D19300 &6
MOVB(082) #1 #E00 D19586
LD TR0
ANDTST(350) D19300 &7
MOVB(082) #1 #F00 D19586

; rung 28: ---------- 0-16-1ch 異常詳細 ----------
LD H11.10
OUT TR0
ANDTST(350) D19218 &0
MOVB(082) #1 #0 D19587
LD TR0
ANDTST(350) D19273 &8
MOVB(082) #1 #100 D19587
LD TR0
ANDTST(350) D19301 &0
MOVB(082) #1 #200 D19587
LD TR0
ANDTST(350) D19301 &1
ANDTSTN(351) D19273 &0
AND T0978
MOVB(082) #1 #300 D19587
LD TR0
ANDTST(350) D19301 &4
MOVB(082) #1 #400 D19587
LD TR0
ANDTST(350) D19301 &5
MOVB(082) #1 #500 D19587
LD TR0
ANDTST(350) D19301 &6
MOVB(082) #1 #600 D19587
LD TR0
ANDTST(350) D19301 &7
MOVB(082) #1 #700 D19587

; rung 29: ---------- 0-16-2ch 異常詳細 ----------
LD H11.11
OUT TR0
ANDTST(350) D19218 &0
MOVB(082) #1 #800 D19587
LD TR0
ANDTST(350) D19274 &8
MOVB(082) #1 #900 D19587
LD TR0
ANDTST(350) D19302 &0
MOVB(082) #1 #A00 D19587
LD TR0
ANDTST(350) D19302 &1
ANDTSTN(351) D19274 &0
AND T0978
MOVB(082) #1 #B00 D19587
LD TR0
ANDTST(350) D19302 &4
MOVB(082) #1 #C00 D19587
LD TR0
ANDTST(350) D19302 &5
MOVB(082) #1 #D00 D19587
LD TR0
ANDTST(350) D19302 &6
MOVB(082) #1 #E00 D19587
LD TR0
ANDTST(350) D19302 &7
MOVB(082) #1 #F00 D19587
; rung 30: ********** 警報表示 ********** / ---------- HFU0系EJ1警報表示 ----------
LD<>(305) H10 #0
OR<>(305) H11 #0
AND<>(305) D19573 #0
OUT W434.00
MOVB(082) #1 #0 D19570

; rung 31
LD H10.00
MOV(021) #0 D19598
MOVD(083) D19574 #10 D19598
AND<>(305) D19598 #0
MOVB(082) #1 #100 D19570
; rung 32
LD H10.01
MOV(021) #0 D19598
MOVD(083) D19574 #12 D19598
AND<>(305) D19598 #0
MOVB(082) #1 #200 D19570
; rung 33
LD H10.02
MOV(021) #0 D19598
MOVD(083) D19575 #10 D19598
AND<>(305) D19598 #0
MOVB(082) #1 #300 D19570
; rung 34
LD H10.03
MOV(021) #0 D19598
MOVD(083) D19575 #12 D19598
AND<>(305) D19598 #0
MOVB(082) #1 #400 D19570

; rung 35
LD H10.04
MOV(021) #0 D19598
MOVD(083) D19576 #10 D19598
AND<>(305) D19598 #0
MOVB(082) #1 #500 D19570
; rung 36
LD H10.05
MOV(021) #0 D19598
MOVD(083) D19576 #12 D19598
AND<>(305) D19598 #0
MOVB(082) #1 #600 D19570
; rung 37
LD H10.06
MOV(021) #0 D19598
MOVD(083) D19577 #10 D19598
AND<>(305) D19598 #0
MOVB(082) #1 #700 D19570
; rung 38
LD H10.07
MOV(021) #0 D19598
MOVD(083) D19577 #12 D19598
AND<>(305) D19598 #0
MOVB(082) #1 #800 D19570

; rung 39
LD H10.08
MOV(021) #0 D19598
MOVD(083) D19578 #10 D19598
AND<>(305) D19598 #0
MOVB(082) #1 #900 D19570
; rung 40
LD H10.09
MOV(021) #0 D19598
MOVD(083) D19578 #12 D19598
AND<>(305) D19598 #0
MOVB(082) #1 #A00 D19570
; rung 41
LD H10.10
MOV(021) #0 D19598
MOVD(083) D19579 #10 D19598
AND<>(305) D19598 #0
MOVB(082) #1 #B00 D19570
; rung 42
LD H10.11
MOV(021) #0 D19598
MOVD(083) D19579 #12 D19598
AND<>(305) D19598 #0
MOVB(082) #1 #C00 D19570

; rung 43
LD H10.12
MOV(021) #0 D19598
MOVD(083) D19580 #10 D19598
AND<>(305) D19598 #0
MOVB(082) #1 #D00 D19570
; rung 44
LD H10.13
MOV(021) #0 D19598
MOVD(083) D19580 #12 D19598
AND<>(305) D19598 #0
MOVB(082) #1 #E00 D19570
; rung 45
LD H10.14
MOV(021) #0 D19598
MOVD(083) D19581 #10 D19598
AND<>(305) D19598 #0
MOVB(082) #1 #F00 D19570
; rung 46
LD H10.15
MOV(021) #0 D19598
MOVD(083) D19581 #12 D19598
AND<>(305) D19598 #0
MOVB(082) #1 #0 D19571

; rung 47
LD H11.00
MOV(021) #0 D19598
MOVD(083) D19582 #10 D19598
AND<>(305) D19598 #0
MOVB(082) #1 #100 D19571
; rung 48
LD H11.01
MOV(021) #0 D19598
MOVD(083) D19582 #12 D19598
AND<>(305) D19598 #0
MOVB(082) #1 #200 D19571
; rung 49
LD H11.02
MOV(021) #0 D19598
MOVD(083) D19583 #10 D19598
AND<>(305) D19598 #0
MOVB(082) #1 #300 D19571
; rung 50
LD H11.03
MOV(021) #0 D19598
MOVD(083) D19583 #12 D19598
AND<>(305) D19598 #0
MOVB(082) #1 #400 D19571

; rung 51
LD H11.04
MOV(021) #0 D19598
MOVD(083) D19584 #10 D19598
AND<>(305) D19598 #0
MOVB(082) #1 #500 D19571
; rung 52
LD H11.05
MOV(021) #0 D19598
MOVD(083) D19584 #12 D19598
AND<>(305) D19598 #0
MOVB(082) #1 #600 D19571
; rung 53
LD H11.06
MOV(021) #0 D19598
MOVD(083) D19585 #10 D19598
AND<>(305) D19598 #0
MOVB(082) #1 #700 D19571
; rung 54
LD H11.07
MOV(021) #0 D19598
MOVD(083) D19585 #12 D19598
AND<>(305) D19598 #0
MOVB(082) #1 #800 D19571

; rung 55
LD H11.08
MOV(021) #0 D19598
MOVD(083) D19586 #10 D19598
AND<>(305) D19598 #0
MOVB(082) #1 #900 D19571
; rung 56
LD H11.09
MOV(021) #0 D19598
MOVD(083) D19586 #12 D19598
AND<>(305) D19598 #0
MOVB(082) #1 #A00 D19571
; rung 57
LD H11.10
MOV(021) #0 D19598
MOVD(083) D19587 #10 D19598
AND<>(305) D19598 #0
MOVB(082) #1 #B00 D19571
; rung 58
LD H11.11
MOV(021) #0 D19598
MOVD(083) D19587 #12 D19598
AND<>(305) D19598 #0
MOVB(082) #1 #C00 D19571

; rung 59
ILC(003)
; rung 60
LD 400.00
@BSET(071) #0 D19570 D19588
; rung 61: ********** 温度上限警報 **********
LDTSTN(351) D19574 &2
ANDTSTN(351) D19575 &2
ANDTSTN(351) D19576 &2
ANDTSTN(351) D19577 &2
ANDTSTN(351) D19578 &2
ANDTSTN(351) D19579 &2
ANDTSTN(351) D19580 &2
ANDTSTN(351) D19581 &2
OUTNOT W435.00
; rung 62
LDTSTN(351) D19574 &10
ANDTSTN(351) D19575 &10
ANDTSTN(351) D19576 &10
ANDTSTN(351) D19577 &10
ANDTSTN(351) D19578 &10
ANDTSTN(351) D19579 &10
ANDTSTN(351) D19580 &10
ANDTSTN(351) D19581 &10
OUTNOT W435.01
; rung 63
LDTSTN(351) D19582 &2
ANDTSTN(351) D19583 &2
ANDTSTN(351) D19584 &2
ANDTSTN(351) D19585 &2
ANDTSTN(351) D19586 &2
ANDTSTN(351) D19587 &2
OUTNOT W435.02
; rung 64
LDTSTN(351) D19582 &10
ANDTSTN(351) D19583 &10
ANDTSTN(351) D19584 &10
ANDTSTN(351) D19585 &10
ANDTSTN(351) D19586 &10
ANDTSTN(351) D19587 &10
OUTNOT W435.03
; rung 65: ********** 温度下限警報 **********
LDTSTN(351) D19574 &3
ANDTSTN(351) D19575 &3
ANDTSTN(351) D19576 &3
ANDTSTN(351) D19577 &3
ANDTSTN(351) D19578 &3
ANDTSTN(351) D19579 &3
ANDTSTN(351) D19580 &3
ANDTSTN(351) D19581 &3
OUTNOT W435.08
; rung 66
LDTSTN(351) D19574 &11
ANDTSTN(351) D19575 &11
ANDTSTN(351) D19576 &11
ANDTSTN(351) D19577 &11
ANDTSTN(351) D19578 &11
ANDTSTN(351) D19579 &11
ANDTSTN(351) D19580 &11
ANDTSTN(351) D19581 &11
OUTNOT W435.09
; rung 67
LDTSTN(351) D19582 &3
ANDTSTN(351) D19583 &3
ANDTSTN(351) D19584 &3
ANDTSTN(351) D19585 &3
ANDTSTN(351) D19586 &3
ANDTSTN(351) D19587 &3
OUTNOT W435.10

; rung 68
LDTSTN(351) D19582 &11
ANDTSTN(351) D19583 &11
ANDTSTN(351) D19584 &11
ANDTSTN(351) D19585 &11
ANDTSTN(351) D19586 &11
ANDTSTN(351) D19587 &11
OUTNOT W435.11
; rung 69: ********** ﾋｰﾀ断線警報 **********
LDTSTN(351) D19574 &5
ANDTSTN(351) D19575 &5
ANDTSTN(351) D19576 &5
ANDTSTN(351) D19577 &5
ANDTSTN(351) D19578 &5
ANDTSTN(351) D19579 &5
ANDTSTN(351) D19580 &5
ANDTSTN(351) D19581 &5
OUTNOT W436.00
; rung 70
LDTSTN(351) D19574 &13
ANDTSTN(351) D19575 &13
ANDTSTN(351) D19576 &13
ANDTSTN(351) D19577 &13
ANDTSTN(351) D19578 &13
ANDTSTN(351) D19579 &13
ANDTSTN(351) D19580 &13
ANDTSTN(351) D19581 &13
OUTNOT W436.01
; rung 71
LDTSTN(351) D19582 &5
ANDTSTN(351) D19583 &5
ANDTSTN(351) D19584 &5
ANDTSTN(351) D19585 &5
ANDTSTN(351) D19586 &5
ANDTSTN(351) D19587 &5
OUTNOT W436.02
; rung 72
LDTSTN(351) D19582 &13
ANDTSTN(351) D19583 &13
ANDTSTN(351) D19584 &13
ANDTSTN(351) D19585 &13
ANDTSTN(351) D19586 &13
ANDTSTN(351) D19587 &13
OUTNOT W436.03
; rung 73: ********** ｺﾝﾀｸﾀ溶着警報 **********
LDTSTN(351) D19574 &6
ANDTSTN(351) D19575 &6
ANDTSTN(351) D19576 &6
ANDTSTN(351) D19577 &6
ANDTSTN(351) D19578 &6
ANDTSTN(351) D19579 &6
ANDTSTN(351) D19580 &6
ANDTSTN(351) D19581 &6
OUTNOT W436.08
; rung 74
LDTSTN(351) D19574 &14
ANDTSTN(351) D19575 &14
ANDTSTN(351) D19576 &14
ANDTSTN(351) D19577 &14
ANDTSTN(351) D19578 &14
ANDTSTN(351) D19579 &14
ANDTSTN(351) D19580 &14
ANDTSTN(351) D19581 &14
OUTNOT W436.09
; rung 75
LDTSTN(351) D19582 &6
ANDTSTN(351) D19583 &6
ANDTSTN(351) D19584 &6
ANDTSTN(351) D19585 &6
ANDTSTN(351) D19586 &6
ANDTSTN(351) D19587 &6
OUTNOT W436.10
; rung 76
LDTSTN(351) D19582 &14
ANDTSTN(351) D19583 &14
ANDTSTN(351) D19584 &14
ANDTSTN(351) D19585 &14
ANDTSTN(351) D19586 &14
ANDTSTN(351) D19587 &14
OUTNOT W436.11

; rung 77: ********** 熱電対異常 **********
LDTSTN(351) D19574 &1
ANDTSTN(351) D19575 &1
ANDTSTN(351) D19576 &1
ANDTSTN(351) D19577 &1
ANDTSTN(351) D19578 &1
ANDTSTN(351) D19579 &1
ANDTSTN(351) D19580 &1
ANDTSTN(351) D19581 &1
OUTNOT W437.08
; rung 78
LDTSTN(351) D19574 &9
ANDTSTN(351) D19575 &9
ANDTSTN(351) D19576 &9
ANDTSTN(351) D19577 &9
ANDTSTN(351) D19578 &9
ANDTSTN(351) D19579 &9
ANDTSTN(351) D19580 &9
ANDTSTN(351) D19581 &9
OUTNOT W437.09
; rung 79
LDTSTN(351) D19582 &1
ANDTSTN(351) D19583 &1
ANDTSTN(351) D19584 &1
ANDTSTN(351) D19585 &1
ANDTSTN(351) D19586 &1
ANDTSTN(351) D19587 &1
OUTNOT W437.10
; rung 80
LDTSTN(351) D19582 &9
ANDTSTN(351) D19583 &9
ANDTSTN(351) D19584 &9
ANDTSTN(351) D19585 &9
ANDTSTN(351) D19586 &9
ANDTSTN(351) D19587 &9
OUTNOT W437.11
; rung 81: ********** ﾋｰﾀ電流ｵｰﾊﾞｰﾌﾛｰ **********
LDTSTN(351) D19574 &4
ANDTSTN(351) D19575 &4
ANDTSTN(351) D19576 &4
ANDTSTN(351) D19577 &4
ANDTSTN(351) D19578 &4
ANDTSTN(351) D19579 &4
ANDTSTN(351) D19580 &4
ANDTSTN(351) D19581 &4
OUTNOT W437.00
; rung 82
LDTSTN(351) D19574 &12
ANDTSTN(351) D19575 &12
ANDTSTN(351) D19576 &12
ANDTSTN(351) D19577 &12
ANDTSTN(351) D19578 &12
ANDTSTN(351) D19579 &12
ANDTSTN(351) D19580 &12
ANDTSTN(351) D19581 &12
OUTNOT W437.01
; rung 83
LDTSTN(351) D19582 &4
ANDTSTN(351) D19583 &4
ANDTSTN(351) D19584 &4
ANDTSTN(351) D19585 &4
ANDTSTN(351) D19586 &4
ANDTSTN(351) D19587 &4
OUTNOT W437.02
; rung 84
LDTSTN(351) D19582 &12
ANDTSTN(351) D19583 &12
ANDTSTN(351) D19584 &12
ANDTSTN(351) D19585 &12
ANDTSTN(351) D19586 &12
ANDTSTN(351) D19587 &12
OUTNOT W437.03

### Section EJ1_HFU1_ALARM

; rung 0: ********** HFU1系統異常処理 **********
LD T0999
IL(002)
; rung 1: ---------- HFU1異常詳細 ----------
LD<>(305) H12 #0
OR<>(305) H13 #0
OR<>(305) H14 #0
OUT TR0
ANDTST(350) D18404 &0
MOVB(082) #1 #0 D18773
LD TR0
ANDTST(350) D18404 &1
MOVB(082) #1 #100 D18773
LD TR0
ANDTST(350) D18404 &3
MOVB(082) #1 #300 D18773
LD TR0
ANDTST(350) D18404 &4
MOVB(082) #1 #400 D18773
LD TR0
ANDTST(350) D18404 &6
MOVB(082) #1 #600 D18773
LD TR0
LD T0984
OR T0983
OR W410.00
ANDLD
MOVB(082) #1 #F00 D18773

; rung 2: ---------- 1-3-1ch 異常詳細 ----------
LD H12.00
OUT TR0
ANDTST(350) D18405 &0
MOVB(082) #1 #0 D18774
LD TR0
ANDTST(350) D18454 &8
MOVB(082) #1 #100 D18774
LD TR0
ANDTST(350) D18488 &0
MOVB(082) #1 #200 D18774
LD TR0
ANDTSTN(351) D18454 &0
AND T0978
OUT TR1
ANDTST(350) D18488 &1
MOVB(082) #1 #300 D18774
LD TR1
ANDTST(350) D18488 &4
MOVB(082) #1 #400 D18774
LD TR1
ANDTST(350) D18488 &5
MOVB(082) #1 #500 D18774
LD TR0
ANDTST(350) D18488 &6
MOVB(082) #1 #600 D18774
LD TR0
ANDTST(350) D18488 &7
MOVB(082) #1 #700 D18774

; rung 3: ---------- 1-3-2ch 異常詳細 ----------
LD H12.01
OUT TR0
ANDTST(350) D18405 &0
MOVB(082) #1 #800 D18774
LD TR0
ANDTST(350) D18455 &8
MOVB(082) #1 #900 D18774
LD TR0
ANDTST(350) D18489 &0
MOVB(082) #1 #A00 D18774
LD TR0
ANDTSTN(351) D18455 &0
AND T0978
OUT TR1
ANDTST(350) D18489 &1
MOVB(082) #1 #B00 D18774
LD TR1
ANDTST(350) D18489 &4
MOVB(082) #1 #C00 D18774
LD TR1
ANDTST(350) D18489 &5
MOVB(082) #1 #D00 D18774
LD TR0
ANDTST(350) D18489 &6
MOVB(082) #1 #E00 D18774
LD TR0
ANDTST(350) D18489 &7
MOVB(082) #1 #F00 D18774

; rung 4: ---------- 1-4-1ch 異常詳細 ----------
LD H12.02
OUT TR0
ANDTST(350) D18406 &0
MOVB(082) #1 #0 D18775
LD TR0
ANDTST(350) D18456 &8
MOVB(082) #1 #100 D18775
LD TR0
ANDTST(350) D18490 &0
MOVB(082) #1 #200 D18775
LD TR0
ANDTSTN(351) D18456 &0
AND T0978
OUT TR1
ANDTST(350) D18490 &1
MOVB(082) #1 #300 D18775
LD TR1
ANDTST(350) D18490 &4
MOVB(082) #1 #400 D18775
LD TR1
ANDTST(350) D18490 &5
MOVB(082) #1 #500 D18775
LD TR0
ANDTST(350) D18490 &6
MOVB(082) #1 #600 D18775
LD TR0
ANDTST(350) D18490 &7
MOVB(082) #1 #700 D18775

; rung 5: ---------- 1-4-2ch 異常詳細 ----------
LD H12.03
OUT TR0
ANDTST(350) D18406 &0
MOVB(082) #1 #800 D18775
LD TR0
ANDTST(350) D18457 &8
MOVB(082) #1 #900 D18775
LD TR0
ANDTST(350) D18491 &0
MOVB(082) #1 #A00 D18775
LD TR0
ANDTSTN(351) D18457 &0
AND T0978
OUT TR1
ANDTST(350) D18491 &1
MOVB(082) #1 #B00 D18775
LD TR1
ANDTST(350) D18491 &4
MOVB(082) #1 #C00 D18775
LD TR1
ANDTST(350) D18491 &5
MOVB(082) #1 #D00 D18775
LD TR0
ANDTST(350) D18491 &6
MOVB(082) #1 #E00 D18775
LD TR0
ANDTST(350) D18491 &7
MOVB(082) #1 #F00 D18775

; rung 6: ---------- 1-5-1ch 異常詳細 ----------
LD H12.04
OUT TR0
ANDTST(350) D18407 &0
MOVB(082) #1 #0 D18776
LD TR0
ANDTST(350) D18458 &8
MOVB(082) #1 #100 D18776
LD TR0
ANDTST(350) D18492 &0
MOVB(082) #1 #200 D18776
LD TR0
ANDTSTN(351) D18458 &0
AND T0978
OUT TR1
ANDTST(350) D18492 &1
MOVB(082) #1 #300 D18776
LD TR1
ANDTST(350) D18492 &4
MOVB(082) #1 #400 D18776
LD TR1
ANDTST(350) D18492 &5
MOVB(082) #1 #500 D18776
LD TR0
ANDTST(350) D18492 &6
MOVB(082) #1 #600 D18776
LD TR0
ANDTST(350) D18492 &7
MOVB(082) #1 #700 D18776

; rung 7: ---------- 1-5-2ch 異常詳細 ----------
LD H12.05
OUT TR0
ANDTST(350) D18407 &0
MOVB(082) #1 #800 D18776
LD TR0
ANDTST(350) D18459 &8
MOVB(082) #1 #900 D18776
LD TR0
ANDTST(350) D18493 &0
MOVB(082) #1 #A00 D18776
LD TR0
ANDTSTN(351) D18459 &0
AND T0978
OUT TR1
ANDTST(350) D18493 &1
MOVB(082) #1 #B00 D18776
LD TR1
ANDTST(350) D18493 &4
MOVB(082) #1 #C00 D18776
LD TR1
ANDTST(350) D18493 &5
MOVB(082) #1 #D00 D18776
LD TR0
ANDTST(350) D18493 &6
MOVB(082) #1 #E00 D18776
LD TR0
ANDTST(350) D18493 &7
MOVB(082) #1 #F00 D18776

; rung 8: ---------- 1-6-1ch 異常詳細 ----------
LD H12.06
OUT TR0
ANDTST(350) D18408 &0
MOVB(082) #1 #0 D18777
LD TR0
ANDTST(350) D18460 &8
MOVB(082) #1 #100 D18777
LD TR0
ANDTST(350) D18494 &0
MOVB(082) #1 #200 D18777
LD TR0
ANDTSTN(351) D18460 &0
AND T0978
OUT TR1
ANDTST(350) D18494 &1
MOVB(082) #1 #300 D18777
LD TR1
ANDTST(350) D18494 &4
MOVB(082) #1 #400 D18777
LD TR1
ANDTST(350) D18494 &5
MOVB(082) #1 #500 D18777
LD TR0
ANDTST(350) D18494 &6
MOVB(082) #1 #600 D18777
LD TR0
ANDTST(350) D18494 &7
MOVB(082) #1 #700 D18777

; rung 9: ---------- 1-6-2ch 異常詳細 ----------
LD H12.07
OUT TR0
ANDTST(350) D18408 &0
MOVB(082) #1 #800 D18777
LD TR0
ANDTST(350) D18461 &8
MOVB(082) #1 #900 D18777
LD TR0
ANDTST(350) D18495 &0
MOVB(082) #1 #A00 D18777
LD TR0
ANDTSTN(351) D18461 &0
AND T0978
OUT TR1
ANDTST(350) D18495 &1
MOVB(082) #1 #B00 D18777
LD TR1
ANDTST(350) D18495 &4
MOVB(082) #1 #C00 D18777
LD TR1
ANDTST(350) D18495 &5
MOVB(082) #1 #D00 D18777
LD TR0
ANDTST(350) D18495 &6
MOVB(082) #1 #E00 D18777
LD TR0
ANDTST(350) D18495 &7
MOVB(082) #1 #F00 D18777

; rung 10: ---------- 1-7-1ch 異常詳細 ----------
LD H12.08
OUT TR0
ANDTST(350) D18409 &0
MOVB(082) #1 #0 D18778
LD TR0
ANDTST(350) D18462 &8
MOVB(082) #1 #100 D18778
LD TR0
ANDTST(350) D18496 &0
MOVB(082) #1 #200 D18778
LD TR0
ANDTSTN(351) D18462 &0
AND T0978
OUT TR1
ANDTST(350) D18496 &1
MOVB(082) #1 #300 D18778
LD TR1
ANDTST(350) D18496 &4
MOVB(082) #1 #400 D18778
LD TR1
ANDTST(350) D18496 &5
MOVB(082) #1 #500 D18778
LD TR0
ANDTST(350) D18496 &6
MOVB(082) #1 #600 D18778
LD TR0
ANDTST(350) D18496 &7
MOVB(082) #1 #700 D18778

; rung 11: ---------- 1-7-2ch 異常詳細 ----------
LD H12.09
OUT TR0
ANDTST(350) D18409 &0
MOVB(082) #1 #800 D18778
LD TR0
ANDTST(350) D18463 &8
MOVB(082) #1 #900 D18778
LD TR0
ANDTST(350) D18497 &0
MOVB(082) #1 #A00 D18778
LD TR0
ANDTSTN(351) D18463 &0
AND T0978
OUT TR1
ANDTST(350) D18497 &1
MOVB(082) #1 #B00 D18778
LD TR1
ANDTST(350) D18497 &4
MOVB(082) #1 #C00 D18778
LD TR1
ANDTST(350) D18497 &5
MOVB(082) #1 #D00 D18778
LD TR0
ANDTST(350) D18497 &6
MOVB(082) #1 #E00 D18778
LD TR0
ANDTST(350) D18497 &7
MOVB(082) #1 #F00 D18778

; rung 12: ---------- 1-8-1ch 異常詳細 ----------
LD H12.10
OUT TR0
ANDTST(350) D18410 &0
MOVB(082) #1 #0 D18779
LD TR0
ANDTST(350) D18464 &8
MOVB(082) #1 #100 D18779
LD TR0
ANDTST(350) D18498 &0
MOVB(082) #1 #200 D18779
LD TR0
ANDTSTN(351) D18464 &0
AND T0978
OUT TR1
ANDTST(350) D18498 &1
MOVB(082) #1 #300 D18779
LD TR1
ANDTST(350) D18498 &4
MOVB(082) #1 #400 D18779
LD TR1
ANDTST(350) D18498 &5
MOVB(082) #1 #500 D18779
LD TR0
ANDTST(350) D18498 &6
MOVB(082) #1 #600 D18779
LD TR0
ANDTST(350) D18498 &7
MOVB(082) #1 #700 D18779

; rung 13: ---------- 1-8-2ch 異常詳細 ----------
LD H12.11
OUT TR0
ANDTST(350) D18410 &0
MOVB(082) #1 #800 D18779
LD TR0
ANDTST(350) D18465 &8
MOVB(082) #1 #900 D18779
LD TR0
ANDTST(350) D18499 &0
MOVB(082) #1 #A00 D18779
LD TR0
ANDTSTN(351) D18465 &0
AND T0978
OUT TR1
ANDTST(350) D18499 &1
MOVB(082) #1 #B00 D18779
LD TR1
ANDTST(350) D18499 &4
MOVB(082) #1 #C00 D18779
LD TR1
ANDTST(350) D18499 &5
MOVB(082) #1 #D00 D18779
LD TR0
ANDTST(350) D18499 &6
MOVB(082) #1 #E00 D18779
LD TR0
ANDTST(350) D18499 &7
MOVB(082) #1 #F00 D18779

; rung 14: ---------- 1-9-1ch 異常詳細 ----------
LD H12.12
OUT TR0
ANDTST(350) D18411 &0
MOVB(082) #1 #0 D18780
LD TR0
ANDTST(350) D18466 &8
MOVB(082) #1 #100 D18780
LD TR0
ANDTST(350) D18500 &0
MOVB(082) #1 #200 D18780
LD TR0
ANDTSTN(351) D18466 &0
AND T0978
OUT TR1
ANDTST(350) D18500 &1
MOVB(082) #1 #300 D18780
LD TR1
ANDTST(350) D18500 &4
MOVB(082) #1 #400 D18780
LD TR1
ANDTST(350) D18500 &5
MOVB(082) #1 #500 D18780
LD TR0
ANDTST(350) D18500 &6
MOVB(082) #1 #600 D18780
LD TR0
ANDTST(350) D18500 &7
MOVB(082) #1 #700 D18780

; rung 15: ---------- 1-9-2ch 異常詳細 ----------
LD H12.13
OUT TR0
ANDTST(350) D18411 &0
MOVB(082) #1 #800 D18780
LD TR0
ANDTST(350) D18467 &8
MOVB(082) #1 #900 D18780
LD TR0
ANDTST(350) D18501 &0
MOVB(082) #1 #A00 D18780
LD TR0
ANDTSTN(351) D18467 &0
AND T0978
OUT TR1
ANDTST(350) D18501 &1
MOVB(082) #1 #B00 D18780
LD TR1
ANDTST(350) D18501 &4
MOVB(082) #1 #C00 D18780
LD TR1
ANDTST(350) D18501 &5
MOVB(082) #1 #D00 D18780
LD TR0
ANDTST(350) D18501 &6
MOVB(082) #1 #E00 D18780
LD TR0
ANDTST(350) D18501 &7
MOVB(082) #1 #F00 D18780

; rung 16: ---------- 1-10-1ch 異常詳細 ----------
LD H12.14
OUT TR0
ANDTST(350) D18412 &0
MOVB(082) #1 #0 D18781
LD TR0
ANDTST(350) D18468 &8
MOVB(082) #1 #100 D18781
LD TR0
ANDTST(350) D18502 &0
MOVB(082) #1 #200 D18781
LD TR0
ANDTSTN(351) D18468 &0
AND T0978
OUT TR1
ANDTST(350) D18502 &1
MOVB(082) #1 #300 D18781
LD TR1
ANDTST(350) D18502 &4
MOVB(082) #1 #400 D18781
LD TR1
ANDTST(350) D18502 &5
MOVB(082) #1 #500 D18781
LD TR0
ANDTST(350) D18502 &6
MOVB(082) #1 #600 D18781
LD TR0
ANDTST(350) D18502 &7
MOVB(082) #1 #700 D18781

; rung 17: ---------- 1-10-2ch 異常詳細 ----------
LD H12.15
OUT TR0
ANDTST(350) D18412 &0
MOVB(082) #1 #800 D18781
LD TR0
ANDTST(350) D18469 &8
MOVB(082) #1 #900 D18781
LD TR0
ANDTST(350) D18503 &0
MOVB(082) #1 #A00 D18781
LD TR0
ANDTSTN(351) D18469 &0
AND T0978
OUT TR1
ANDTST(350) D18503 &1
MOVB(082) #1 #B00 D18781
LD TR1
ANDTST(350) D18503 &4
MOVB(082) #1 #C00 D18781
LD TR1
ANDTST(350) D18503 &5
MOVB(082) #1 #D00 D18781
LD TR0
ANDTST(350) D18503 &6
MOVB(082) #1 #E00 D18781
LD TR0
ANDTST(350) D18503 &7
MOVB(082) #1 #F00 D18781

; rung 18: ---------- 1-11-1ch 異常詳細 ----------
LD H13.00
OUT TR0
ANDTST(350) D18413 &0
MOVB(082) #1 #0 D18782
LD TR0
ANDTST(350) D18470 &8
MOVB(082) #1 #100 D18782
LD TR0
ANDTST(350) D18504 &0
MOVB(082) #1 #200 D18782
LD TR0
ANDTSTN(351) D18470 &0
AND T0978
OUT TR1
ANDTST(350) D18504 &1
MOVB(082) #1 #300 D18782
LD TR1
ANDTST(350) D18504 &4
MOVB(082) #1 #400 D18782
LD TR1
ANDTST(350) D18504 &5
MOVB(082) #1 #500 D18782
LD TR0
ANDTST(350) D18504 &6
MOVB(082) #1 #600 D18782
LD TR0
ANDTST(350) D18504 &7
MOVB(082) #1 #700 D18782

; rung 19: ---------- 1-11-2ch 異常詳細 ----------
LD H13.01
OUT TR0
ANDTST(350) D18413 &0
MOVB(082) #1 #800 D18782
LD TR0
ANDTST(350) D18471 &8
MOVB(082) #1 #900 D18782
LD TR0
ANDNOT P_On
OUT TR0
ANDTST(350) D18505 &0
MOVB(082) #1 #A00 D18782
LD TR0
ANDTST(350) D18505 &1
ANDTSTN(351) D18471 &0
AND T0978
MOVB(082) #1 #B00 D18782
LD TR0
ANDTST(350) D18505 &4
MOVB(082) #1 #C00 D18782
LD TR0
ANDTST(350) D18505 &5
MOVB(082) #1 #D00 D18782
LD TR0
ANDTST(350) D18505 &6
MOVB(082) #1 #E00 D18782
LD TR0
ANDTST(350) D18505 &7
MOVB(082) #1 #F00 D18782

; rung 20: ---------- 1-12-1ch 異常詳細 ----------
LD H13.02
OUT TR0
ANDTST(350) D18414 &0
MOVB(082) #1 #0 D18783
LD TR0
ANDTST(350) D18472 &8
MOVB(082) #1 #100 D18783
LD TR0
ANDTST(350) D18506 &0
MOVB(082) #1 #200 D18783
LD TR0
ANDTSTN(351) D18472 &0
AND T0979
OUT TR1
ANDTST(350) D18506 &1
MOVB(082) #1 #300 D18783
LD TR1
ANDTST(350) D18506 &4
MOVB(082) #1 #400 D18783
LD TR1
ANDTST(350) D18506 &5
MOVB(082) #1 #500 D18783
LD TR0
ANDTST(350) D18506 &6
MOVB(082) #1 #600 D18783
LD TR0
ANDTST(350) D18506 &7
MOVB(082) #1 #700 D18783

; rung 21: ---------- 1-12-2ch 異常詳細 ----------
LD H13.03
OUT TR0
ANDTST(350) D18414 &0
MOVB(082) #1 #800 D18783
LD TR0
ANDTST(350) D18473 &8
MOVB(082) #1 #900 D18783
LD TR0
ANDTST(350) D18507 &0
MOVB(082) #1 #A00 D18783
LD TR0
ANDTSTN(351) D18473 &0
AND T0979
OUT TR1
ANDTST(350) D18507 &1
MOVB(082) #1 #B00 D18783
LD TR1
ANDTST(350) D18507 &4
MOVB(082) #1 #C00 D18783
LD TR1
ANDTST(350) D18507 &5
MOVB(082) #1 #D00 D18783
LD TR0
ANDTST(350) D18507 &6
MOVB(082) #1 #E00 D18783
LD TR0
ANDTST(350) D18507 &7
MOVB(082) #1 #F00 D18783

; rung 22: ---------- 1-13-1ch 異常詳細 ----------
LD H13.04
OUT TR0
ANDTST(350) D18415 &0
MOVB(082) #1 #0 D18784
LD TR0
ANDTST(350) D18474 &8
MOVB(082) #1 #100 D18784
LD TR0
ANDTST(350) D18508 &0
MOVB(082) #1 #200 D18784
LD TR0
ANDTSTN(351) D18474 &0
AND T0979
OUT TR1
ANDTST(350) D18508 &1
MOVB(082) #1 #300 D18784
LD TR1
ANDTST(350) D18508 &4
MOVB(082) #1 #400 D18784
LD TR1
ANDTST(350) D18508 &5
MOVB(082) #1 #500 D18784
LD TR0
ANDTST(350) D18508 &6
MOVB(082) #1 #600 D18784
LD TR0
ANDTST(350) D18508 &7
MOVB(082) #1 #700 D18784

; rung 23: ---------- 1-13-2ch 異常詳細 ----------
LD H13.05
OUT TR0
ANDTST(350) D18415 &0
MOVB(082) #1 #800 D18784
LD TR0
ANDTST(350) D18475 &8
MOVB(082) #1 #900 D18784
LD TR0
ANDTST(350) D18509 &0
MOVB(082) #1 #A00 D18784
LD TR0
ANDTSTN(351) D18475 &0
AND T0979
OUT TR1
ANDTST(350) D18509 &1
MOVB(082) #1 #B00 D18784
LD TR1
ANDTST(350) D18509 &4
MOVB(082) #1 #C00 D18784
LD TR1
ANDTST(350) D18509 &5
MOVB(082) #1 #D00 D18784
LD TR0
ANDTST(350) D18509 &6
MOVB(082) #1 #E00 D18784
LD TR0
ANDTST(350) D18509 &7
MOVB(082) #1 #F00 D18784

; rung 24: ---------- 1-14-1ch 異常詳細 ----------
LD H13.06
OUT TR0
ANDTST(350) D18416 &0
MOVB(082) #1 #0 D18785
LD TR0
ANDTST(350) D18476 &8
MOVB(082) #1 #100 D18785
LD TR0
ANDTST(350) D18510 &0
MOVB(082) #1 #200 D18785
LD TR0
ANDTSTN(351) D18476 &0
AND T0979
OUT TR1
ANDTST(350) D18510 &1
MOVB(082) #1 #300 D18785
LD TR1
ANDTST(350) D18510 &4
MOVB(082) #1 #400 D18785
LD TR1
ANDTST(350) D18510 &5
MOVB(082) #1 #500 D18785
LD TR0
ANDTST(350) D18510 &6
MOVB(082) #1 #600 D18785
LD TR0
ANDTST(350) D18510 &7
MOVB(082) #1 #700 D18785

; rung 25: ---------- 1-14-2ch 異常詳細 ----------
LD H13.07
OUT TR0
ANDTST(350) D18416 &0
MOVB(082) #1 #800 D18785
LD TR0
ANDTST(350) D18477 &8
MOVB(082) #1 #900 D18785
LD TR0
ANDTST(350) D18511 &0
MOVB(082) #1 #A00 D18785
LD TR0
ANDTSTN(351) D18477 &0
AND T0979
OUT TR1
ANDTST(350) D18511 &1
MOVB(082) #1 #B00 D18785
LD TR1
ANDTST(350) D18511 &4
MOVB(082) #1 #C00 D18785
LD TR1
ANDTST(350) D18511 &5
MOVB(082) #1 #D00 D18785
LD TR0
ANDTST(350) D18511 &6
MOVB(082) #1 #E00 D18785
LD TR0
ANDTST(350) D18511 &7
MOVB(082) #1 #F00 D18785

; rung 26: ---------- 1-15-1ch 異常詳細 ----------
LD H13.08
OUT TR0
ANDTST(350) D18417 &0
MOVB(082) #1 #0 D18786
LD TR0
ANDTST(350) D18478 &8
MOVB(082) #1 #100 D18786
LD TR0
ANDTST(350) D18512 &0
MOVB(082) #1 #200 D18786
LD TR0
ANDTSTN(351) D18478 &0
AND T0979
AND T0990
OUT TR1
ANDTST(350) D18512 &1
MOVB(082) #1 #300 D18786
LD TR1
ANDTST(350) D18512 &4
MOVB(082) #1 #400 D18786
LD TR1
ANDTST(350) D18512 &5
MOVB(082) #1 #500 D18786
LD TR0
ANDTST(350) D18512 &6
MOVB(082) #1 #600 D18786
LD TR0
ANDTST(350) D18512 &7
MOVB(082) #1 #700 D18786

; rung 27: ---------- 1-15-2ch 異常詳細 ----------
LD H13.09
OUT TR0
ANDTST(350) D18417 &0
MOVB(082) #1 #800 D18786
LD TR0
ANDTST(350) D18479 &8
MOVB(082) #1 #900 D18786
LD TR0
ANDTST(350) D18513 &0
MOVB(082) #1 #A00 D18786
LD TR0
ANDTSTN(351) D18479 &0
AND T0979
AND T0990
OUT TR1
ANDTST(350) D18513 &1
MOVB(082) #1 #B00 D18786
LD TR1
ANDTST(350) D18513 &4
MOVB(082) #1 #C00 D18786
LD TR1
ANDTST(350) D18513 &5
MOVB(082) #1 #D00 D18786
LD TR0
ANDTST(350) D18513 &6
MOVB(082) #1 #E00 D18786
LD TR0
ANDTST(350) D18513 &7
MOVB(082) #1 #F00 D18786

; rung 28: ---------- 1-16-1ch 異常詳細 ----------
LD H13.10
OUT TR0
ANDTST(350) D18418 &0
MOVB(082) #1 #0 D18787
LD TR0
ANDTST(350) D18480 &8
MOVB(082) #1 #100 D18787
LD TR0
ANDNOT P_On
OUT TR0
ANDTST(350) D18514 &0
MOVB(082) #1 #200 D18787
LD TR0
ANDTSTN(351) D18480 &0
AND T0979
OUT TR1
ANDTST(350) D18514 &1
MOVB(082) #1 #300 D18787
LD TR1
ANDTST(350) D18514 &4
MOVB(082) #1 #400 D18787
LD TR1
ANDTST(350) D18514 &5
MOVB(082) #1 #500 D18787
LD TR0
ANDTST(350) D18514 &6
MOVB(082) #1 #600 D18787
LD TR0
ANDTST(350) D18514 &7
MOVB(082) #1 #700 D18787

; rung 29: ---------- 1-16-2ch 異常詳細 ----------
LD H13.11
OUT TR0
ANDTST(350) D18418 &0
MOVB(082) #1 #800 D18787
LD TR0
ANDTST(350) D18481 &8
MOVB(082) #1 #900 D18787
LD TR0
ANDNOT P_On
OUT TR0
ANDTST(350) D18515 &0
MOVB(082) #1 #A00 D18787
LD TR0
ANDTSTN(351) D18481 &0
AND T0979
OUT TR1
ANDTST(350) D18515 &1
MOVB(082) #1 #B00 D18787
LD TR1
ANDTST(350) D18515 &4
MOVB(082) #1 #C00 D18787
LD TR1
ANDTST(350) D18515 &5
MOVB(082) #1 #D00 D18787
LD TR0
ANDTST(350) D18515 &6
MOVB(082) #1 #E00 D18787
LD TR0
ANDTST(350) D18515 &7
MOVB(082) #1 #F00 D18787

; rung 30: ---------- 1-16-3ch 異常詳細 ----------
LD H13.12
OUT TR0
ANDTST(350) D18418 &0
MOVB(082) #1 #0 D18788
LD TR0
ANDTST(350) D18482 &8
MOVB(082) #1 #100 D18788
LD TR0
ANDNOT P_On
OUT TR0
ANDTST(350) D18516 &0
MOVB(082) #1 #200 D18788
LD TR0
ANDTSTN(351) D18482 &0
AND T0979
OUT TR1
ANDTST(350) D18516 &1
MOVB(082) #1 #300 D18788
LD TR1
ANDTST(350) D18516 &4
MOVB(082) #1 #400 D18788
LD TR1
ANDTST(350) D18516 &5
MOVB(082) #1 #500 D18788
LD TR0
ANDTST(350) D18516 &6
MOVB(082) #1 #600 D18788
LD TR0
ANDTST(350) D18516 &7
MOVB(082) #1 #700 D18788

; rung 31: ---------- 1-16-4ch 異常詳細 ----------
LD H13.13
OUT TR0
ANDTST(350) D18418 &0
MOVB(082) #1 #800 D18788
LD TR0
ANDTST(350) D18483 &8
MOVB(082) #1 #900 D18788
LD TR0
ANDNOT P_On
OUT TR0
ANDTST(350) D18517 &0
MOVB(082) #1 #A00 D18788
LD TR0
ANDTSTN(351) D18483 &0
AND T0979
OUT TR1
ANDTST(350) D18517 &1
MOVB(082) #1 #B00 D18788
LD TR1
ANDTST(350) D18517 &4
MOVB(082) #1 #C00 D18788
LD TR1
ANDTST(350) D18517 &5
MOVB(082) #1 #D00 D18788
LD TR0
ANDTST(350) D18517 &6
MOVB(082) #1 #E00 D18788
LD TR0
ANDTST(350) D18517 &7
MOVB(082) #1 #F00 D18788

; rung 32: ---------- 1-17-1ch 異常詳細 ----------
LD H13.14
OUT TR0
ANDTST(350) D18419 &0
MOVB(082) #1 #0 D18789
LD TR0
ANDTST(350) D18484 &8
MOVB(082) #1 #100 D18789
LD TR0
ANDNOT P_On
OUT TR0
ANDTST(350) D18518 &0
MOVB(082) #1 #200 D18789
LD TR0
ANDTSTN(351) D18484 &0
AND T0979
OUT TR1
ANDTST(350) D18518 &1
MOVB(082) #1 #300 D18789
LD TR1
ANDTST(350) D18518 &4
MOVB(082) #1 #400 D18789
LD TR1
ANDTST(350) D18518 &5
MOVB(082) #1 #500 D18789
LD TR0
ANDTST(350) D18518 &6
MOVB(082) #1 #600 D18789
LD TR0
ANDTST(350) D18518 &7
MOVB(082) #1 #700 D18789

; rung 33: ---------- 1-17-2ch 異常詳細 ----------
LD H13.15
OUT TR0
ANDTST(350) D18419 &0
MOVB(082) #1 #800 D18789
LD TR0
ANDTST(350) D18485 &8
MOVB(082) #1 #900 D18789
LD TR0
ANDNOT P_On
OUT TR0
ANDTST(350) D18519 &0
MOVB(082) #1 #A00 D18789
LD TR0
ANDTSTN(351) D18485 &0
AND T0979
OUT TR1
ANDTST(350) D18519 &1
MOVB(082) #1 #B00 D18789
LD TR1
ANDTST(350) D18519 &4
MOVB(082) #1 #C00 D18789
LD TR1
ANDTST(350) D18519 &5
MOVB(082) #1 #D00 D18789
LD TR0
ANDTST(350) D18519 &6
MOVB(082) #1 #E00 D18789
LD TR0
ANDTST(350) D18519 &7
MOVB(082) #1 #F00 D18789

; rung 34: ---------- 1-17-3ch 異常詳細 ----------
LD H14.00
OUT TR0
ANDTST(350) D18419 &0
MOVB(082) #1 #0 D18790
LD TR0
ANDTST(350) D18486 &8
MOVB(082) #1 #100 D18790
LD TR0
ANDNOT P_On
OUT TR0
ANDTST(350) D18520 &0
MOVB(082) #1 #200 D18790
LD TR0
ANDTSTN(351) D18486 &0
AND T0979
OUT TR1
ANDTST(350) D18520 &1
MOVB(082) #1 #300 D18790
LD TR1
ANDTST(350) D18520 &4
MOVB(082) #1 #400 D18790
LD TR1
ANDTST(350) D18520 &5
MOVB(082) #1 #500 D18790
LD TR0
ANDTST(350) D18520 &6
MOVB(082) #1 #600 D18790
LD TR0
ANDTST(350) D18520 &7
MOVB(082) #1 #700 D18790

; rung 35: ---------- 1-17-4ch 異常詳細 ----------
LD H14.01
OUT TR0
ANDTST(350) D18419 &0
MOVB(082) #1 #800 D18790
LD TR0
ANDTST(350) D18487 &8
MOVB(082) #1 #900 D18790
LD TR0
ANDNOT P_On
OUT TR0
ANDTST(350) D18521 &0
MOVB(082) #1 #A00 D18790
LD TR0
ANDTSTN(351) D18487 &0
AND T0979
OUT TR1
ANDTST(350) D18521 &1
MOVB(082) #1 #B00 D18790
LD TR1
ANDTST(350) D18521 &4
MOVB(082) #1 #C00 D18790
LD TR1
ANDTST(350) D18521 &5
MOVB(082) #1 #D00 D18790
LD TR0
ANDTST(350) D18521 &6
MOVB(082) #1 #E00 D18790
LD TR0
ANDTST(350) D18521 &7
MOVB(082) #1 #F00 D18790
; rung 36: ********** 警報表示 ********** / ---------- HFU1系EJ1警報表示 ----------
LD<>(305) H12 #0
OR<>(305) H13 #0
OR<>(305) H14 #0
AND<>(305) D18773 #0
OUT W434.01
MOVB(082) #1 #0 D18770

; rung 37
LD H12.00
MOV(021) #0 D18798
MOVD(083) D18774 #10 D18798
AND<>(305) D18798 #0
MOVB(082) #1 #100 D18770
; rung 38
LD H12.01
MOV(021) #0 D18798
MOVD(083) D18774 #12 D18798
AND<>(305) D18798 #0
MOVB(082) #1 #200 D18770
; rung 39
LD H12.02
MOV(021) #0 D18798
MOVD(083) D18775 #10 D18798
AND<>(305) D18798 #0
MOVB(082) #1 #300 D18770
; rung 40
LD H12.03
MOV(021) #0 D18798
MOVD(083) D18775 #12 D18798
AND<>(305) D18798 #0
MOVB(082) #1 #400 D18770

; rung 41
LD H12.04
MOV(021) #0 D18798
MOVD(083) D18776 #10 D18798
AND<>(305) D18798 #0
MOVB(082) #1 #500 D18770
; rung 42
LD H12.05
MOV(021) #0 D18798
MOVD(083) D18776 #12 D18798
AND<>(305) D18798 #0
MOVB(082) #1 #600 D18770
; rung 43
LD H12.06
MOV(021) #0 D18798
MOVD(083) D18777 #10 D18798
AND<>(305) D18798 #0
MOVB(082) #1 #700 D18770
; rung 44
LD H12.07
MOV(021) #0 D18798
MOVD(083) D18777 #12 D18798
AND<>(305) D18798 #0
MOVB(082) #1 #800 D18770

; rung 45
LD H12.08
MOV(021) #0 D18798
MOVD(083) D18778 #10 D18798
AND<>(305) D18798 #0
MOVB(082) #1 #900 D18770
; rung 46
LD H12.09
MOV(021) #0 D18798
MOVD(083) D18778 #12 D18798
AND<>(305) D18798 #0
MOVB(082) #1 #A00 D18770
; rung 47
LD H12.10
MOV(021) #0 D18798
MOVD(083) D18779 #10 D18798
AND<>(305) D18798 #0
MOVB(082) #1 #B00 D18770
; rung 48
LD H12.11
MOV(021) #0 D18798
MOVD(083) D18779 #12 D18798
AND<>(305) D18798 #0
MOVB(082) #1 #C00 D18770

; rung 49
LD H12.12
MOV(021) #0 D18798
MOVD(083) D18780 #10 D18798
AND<>(305) D18798 #0
MOVB(082) #1 #D00 D18770
; rung 50
LD H12.13
MOV(021) #0 D18798
MOVD(083) D18780 #12 D18798
AND<>(305) D18798 #0
MOVB(082) #1 #E00 D18770
; rung 51
LD H12.14
MOV(021) #0 D18798
MOVD(083) D18781 #10 D18798
AND<>(305) D18798 #0
MOVB(082) #1 #F00 D18770
; rung 52
LD H12.15
MOV(021) #0 D18798
MOVD(083) D18781 #12 D18798
AND<>(305) D18798 #0
MOVB(082) #1 #0 D18771

; rung 53
LD H13.00
MOV(021) #0 D18798
MOVD(083) D18782 #10 D18798
AND<>(305) D18798 #0
MOVB(082) #1 #100 D18771
; rung 54
LD H13.01
MOV(021) #0 D18798
MOVD(083) D18782 #12 D18798
AND<>(305) D18798 #0
MOVB(082) #1 #200 D18771
; rung 55
LD H13.02
MOV(021) #0 D18798
MOVD(083) D18783 #10 D18798
AND<>(305) D18798 #0
MOVB(082) #1 #300 D18771
; rung 56
LD H13.03
MOV(021) #0 D18798
MOVD(083) D18783 #12 D18798
AND<>(305) D18798 #0
MOVB(082) #1 #400 D18771

; rung 57
LD H13.04
MOV(021) #0 D18798
MOVD(083) D18784 #10 D18798
AND<>(305) D18798 #0
MOVB(082) #1 #500 D18771
; rung 58
LD H13.05
MOV(021) #0 D18798
MOVD(083) D18784 #12 D18798
AND<>(305) D18798 #0
MOVB(082) #1 #600 D18771
; rung 59
LD H13.06
MOV(021) #0 D18798
MOVD(083) D18785 #10 D18798
AND<>(305) D18798 #0
MOVB(082) #1 #700 D18771
; rung 60
LD H13.07
MOV(021) #0 D18798
MOVD(083) D18785 #12 D18798
AND<>(305) D18798 #0
MOVB(082) #1 #800 D18771

; rung 61
LD H13.08
MOV(021) #0 D18798
MOVD(083) D18786 #10 D18798
AND<>(305) D18798 #0
MOVB(082) #1 #900 D18771
; rung 62
LD H13.09
MOV(021) #0 D18798
MOVD(083) D18786 #12 D18798
AND<>(305) D18798 #0
MOVB(082) #1 #A00 D18771
; rung 63
LD H13.10
MOV(021) #0 D18798
MOVD(083) D18787 #10 D18798
AND<>(305) D18798 #0
MOVB(082) #1 #B00 D18771
; rung 64
LD H13.11
MOV(021) #0 D18798
MOVD(083) D18787 #12 D18798
AND<>(305) D18798 #0
MOVB(082) #1 #C00 D18771

; rung 65
LD H13.12
MOV(021) #0 D18798
MOVD(083) D18788 #10 D18798
AND<>(305) D18798 #0
MOVB(082) #1 #D00 D18771
; rung 66
LD H13.13
MOV(021) #0 D18798
MOVD(083) D18788 #12 D18798
AND<>(305) D18798 #0
MOVB(082) #1 #E00 D18771
; rung 67
LD H13.14
MOV(021) #0 D18798
MOVD(083) D18789 #10 D18798
AND<>(305) D18798 #0
MOVB(082) #1 #F00 D18771
; rung 68
LD H13.15
MOV(021) #0 D18798
MOVD(083) D18789 #12 D18798
AND<>(305) D18798 #0
MOVB(082) #1 #0 D18772

; rung 69
LD H14.00
MOV(021) #0 D18798
MOVD(083) D18790 #10 D18798
AND<>(305) D18798 #0
MOVB(082) #1 #100 D18772
; rung 70
LD H14.01
MOV(021) #0 D18798
MOVD(083) D18790 #12 D18798
AND<>(305) D18798 #0
MOVB(082) #1 #200 D18772
; rung 71
ILC(003)
; rung 72
LD 400.00
@BSET(071) #0 D18770 D18790
; rung 73: ********** 温度上限警報 **********
LDTSTN(351) D18774 &2
ANDTSTN(351) D18775 &2
ANDTSTN(351) D18776 &2
ANDTSTN(351) D18777 &2
ANDTSTN(351) D18778 &2
ANDTSTN(351) D18779 &2
ANDTSTN(351) D18780 &2
ANDTSTN(351) D18781 &2
OUTNOT W435.04
; rung 74
LDTSTN(351) D18774 &10
ANDTSTN(351) D18775 &10
ANDTSTN(351) D18776 &10
ANDTSTN(351) D18777 &10
ANDTSTN(351) D18778 &10
ANDTSTN(351) D18779 &10
ANDTSTN(351) D18780 &10
ANDTSTN(351) D18781 &10
OUTNOT W435.05
; rung 75
LDTSTN(351) D18782 &2
ANDTSTN(351) D18783 &2
ANDTSTN(351) D18784 &2
ANDTSTN(351) D18785 &2
ANDTSTN(351) D18786 &2
ANDTSTN(351) D18787 &2
ANDTSTN(351) D18788 &2
ANDTSTN(351) D18789 &2
ANDTSTN(351) D18790 &2
OUTNOT W435.06

; rung 76
LDTSTN(351) D18782 &10
ANDTSTN(351) D18783 &10
ANDTSTN(351) D18784 &10
ANDTSTN(351) D18785 &10
ANDTSTN(351) D18786 &10
ANDTSTN(351) D18787 &10
ANDTSTN(351) D18788 &10
ANDTSTN(351) D18789 &10
ANDTSTN(351) D18790 &10
OUTNOT W435.07
; rung 77: ********** 温度下限警報 **********
LDTSTN(351) D18774 &3
ANDTSTN(351) D18775 &3
ANDTSTN(351) D18776 &3
ANDTSTN(351) D18777 &3
ANDTSTN(351) D18778 &3
ANDTSTN(351) D18779 &3
ANDTSTN(351) D18780 &3
ANDTSTN(351) D18781 &3
OUTNOT W435.12
; rung 78
LDTSTN(351) D18774 &11
ANDTSTN(351) D18775 &11
ANDTSTN(351) D18776 &11
ANDTSTN(351) D18777 &11
ANDTSTN(351) D18778 &11
ANDTSTN(351) D18779 &11
ANDTSTN(351) D18780 &11
ANDTSTN(351) D18781 &11
OUTNOT W435.13
; rung 79
LDTSTN(351) D18782 &3
ANDTSTN(351) D18783 &3
ANDTSTN(351) D18784 &3
ANDTSTN(351) D18785 &3
ANDTSTN(351) D18786 &3
ANDTSTN(351) D18787 &3
ANDTSTN(351) D18788 &3
ANDTSTN(351) D18789 &3
ANDTSTN(351) D18790 &3
OUTNOT W435.14
; rung 80
LDTSTN(351) D18782 &11
ANDTSTN(351) D18783 &11
ANDTSTN(351) D18784 &11
ANDTSTN(351) D18785 &11
ANDTSTN(351) D18786 &11
ANDTSTN(351) D18787 &11
ANDTSTN(351) D18788 &11
ANDTSTN(351) D18789 &11
ANDTSTN(351) D18790 &11
OUTNOT W435.15
; rung 81: ********** ﾋｰﾀ断線警報 **********
LDTSTN(351) D18774 &5
ANDTSTN(351) D18775 &5
ANDTSTN(351) D18776 &5
ANDTSTN(351) D18777 &5
ANDTSTN(351) D18778 &5
ANDTSTN(351) D18779 &5
ANDTSTN(351) D18780 &5
ANDTSTN(351) D18781 &5
OUTNOT W436.04
; rung 82
LDTSTN(351) D18774 &13
ANDTSTN(351) D18775 &13
ANDTSTN(351) D18776 &13
ANDTSTN(351) D18777 &13
ANDTSTN(351) D18778 &13
ANDTSTN(351) D18779 &13
ANDTSTN(351) D18780 &13
ANDTSTN(351) D18781 &13
OUTNOT W436.05
; rung 83
LDTSTN(351) D18782 &5
ANDTSTN(351) D18783 &5
ANDTSTN(351) D18784 &5
ANDTSTN(351) D18785 &5
ANDTSTN(351) D18786 &5
ANDTSTN(351) D18787 &5
ANDTSTN(351) D18788 &5
ANDTSTN(351) D18789 &5
ANDTSTN(351) D18790 &5
OUTNOT W436.06
; rung 84
LDTSTN(351) D18782 &13
ANDTSTN(351) D18783 &13
ANDTSTN(351) D18784 &13
ANDTSTN(351) D18785 &13
ANDTSTN(351) D18786 &13
ANDTSTN(351) D18787 &13
ANDTSTN(351) D18788 &13
ANDTSTN(351) D18789 &13
ANDTSTN(351) D18790 &13
OUTNOT W436.07

; rung 85: ********** ｺﾝﾀｸﾀ溶着警報 **********
LDTSTN(351) D18774 &6
ANDTSTN(351) D18775 &6
ANDTSTN(351) D18776 &6
ANDTSTN(351) D18777 &6
ANDTSTN(351) D18778 &6
ANDTSTN(351) D18779 &6
ANDTSTN(351) D18780 &6
ANDTSTN(351) D18781 &6
OUTNOT W436.12
; rung 86
LDTSTN(351) D18774 &14
ANDTSTN(351) D18775 &14
ANDTSTN(351) D18776 &14
ANDTSTN(351) D18777 &14
ANDTSTN(351) D18778 &14
ANDTSTN(351) D18779 &14
ANDTSTN(351) D18780 &14
ANDTSTN(351) D18781 &14
OUTNOT W436.13
; rung 87
LDTSTN(351) D18782 &6
ANDTSTN(351) D18783 &6
ANDTSTN(351) D18784 &6
ANDTSTN(351) D18785 &6
ANDTSTN(351) D18786 &6
ANDTSTN(351) D18787 &6
ANDTSTN(351) D18788 &6
ANDTSTN(351) D18789 &6
ANDTSTN(351) D18790 &6
OUTNOT W436.14
; rung 88
LDTSTN(351) D18782 &14
ANDTSTN(351) D18783 &14
ANDTSTN(351) D18784 &14
ANDTSTN(351) D18785 &14
ANDTSTN(351) D18786 &14
ANDTSTN(351) D18787 &14
ANDTSTN(351) D18788 &14
ANDTSTN(351) D18789 &14
ANDTSTN(351) D18790 &14
OUTNOT W436.15
; rung 89: ********** 熱電対異常 **********
LDTSTN(351) D18774 &1
ANDTSTN(351) D18775 &1
ANDTSTN(351) D18776 &1
ANDTSTN(351) D18777 &1
ANDTSTN(351) D18778 &1
ANDTSTN(351) D18779 &1
ANDTSTN(351) D18780 &1
ANDTSTN(351) D18781 &1
OUTNOT W437.12
; rung 90
LDTSTN(351) D18774 &9
ANDTSTN(351) D18775 &9
ANDTSTN(351) D18776 &9
ANDTSTN(351) D18777 &9
ANDTSTN(351) D18778 &9
ANDTSTN(351) D18779 &9
ANDTSTN(351) D18780 &9
ANDTSTN(351) D18781 &9
OUTNOT W437.13
; rung 91
LDTSTN(351) D18782 &1
ANDTSTN(351) D18783 &1
ANDTSTN(351) D18784 &1
ANDTSTN(351) D18785 &1
ANDTSTN(351) D18786 &1
ANDTSTN(351) D18787 &1
ANDTSTN(351) D18788 &1
ANDTSTN(351) D18789 &1
ANDTSTN(351) D18790 &1
OUTNOT W437.14
; rung 92
LDTSTN(351) D18782 &9
ANDTSTN(351) D18783 &9
ANDTSTN(351) D18784 &9
ANDTSTN(351) D18785 &9
ANDTSTN(351) D18786 &9
ANDTSTN(351) D18787 &9
ANDTSTN(351) D18788 &9
ANDTSTN(351) D18789 &9
ANDTSTN(351) D18790 &9
OUTNOT W437.15
; rung 93: ********** ﾋｰﾀ電流ｵｰﾊﾞｰﾌﾛｰ **********
LDTSTN(351) D18774 &4
ANDTSTN(351) D18775 &4
ANDTSTN(351) D18776 &4
ANDTSTN(351) D18777 &4
ANDTSTN(351) D18778 &4
ANDTSTN(351) D18779 &4
ANDTSTN(351) D18780 &4
ANDTSTN(351) D18781 &4
OUTNOT W437.04

; rung 94
LDTSTN(351) D18774 &12
ANDTSTN(351) D18775 &12
ANDTSTN(351) D18776 &12
ANDTSTN(351) D18777 &12
ANDTSTN(351) D18778 &12
ANDTSTN(351) D18779 &12
ANDTSTN(351) D18780 &12
ANDTSTN(351) D18781 &12
OUTNOT W437.05
; rung 95
LDTSTN(351) D18782 &4
ANDTSTN(351) D18783 &4
ANDTSTN(351) D18784 &4
ANDTSTN(351) D18785 &4
ANDTSTN(351) D18786 &4
ANDTSTN(351) D18787 &4
ANDTSTN(351) D18788 &4
ANDTSTN(351) D18789 &4
ANDTSTN(351) D18790 &4
OUTNOT W437.06
; rung 96
LDTSTN(351) D18782 &12
ANDTSTN(351) D18783 &12
ANDTSTN(351) D18784 &12
ANDTSTN(351) D18785 &12
ANDTSTN(351) D18786 &12
ANDTSTN(351) D18787 &12
ANDTSTN(351) D18788 &12
ANDTSTN(351) D18789 &12
ANDTSTN(351) D18790 &12
OUTNOT W437.07

### Section EJ1_AMPERE

; rung 0: ---------- ﾋｰﾀ電流表示 ---------- / 計算結果は２ﾜｰﾄﾞとなるがDM削減の為
LD T0094
OUT TR0
AND H10.00
*U(422) D19359 D17500 D19970
LD TR0
AND H10.01
*U(422) D19360 D17501 D19971
LD TR0
AND H10.02
*U(422) D19361 D17502 D19972
LD TR0
AND H10.03
*U(422) D19362 D17503 D19973
LD TR0
AND H10.04
*U(422) D19363 D17504 D19974
LD TR0
AND H10.05
*U(422) D19364 D17505 D19975
LD TR0
AND H10.06
*U(422) D19365 D17506 D19976
LD TR0
AND H10.07
*U(422) D19366 D17507 D19977

; rung 1
LD T0094
OUT TR0
AND H10.08
*U(422) D19367 D17508 D19978
LD TR0
AND H10.09
*U(422) D19368 D17509 D19979
LD TR0
AND H10.10
*U(422) D19369 D17510 D19980
LD TR0
AND H10.11
*U(422) D19370 D17511 D19981
LD TR0
AND H10.12
*U(422) D19371 D17512 D19982
LD TR0
AND H10.13
*U(422) D19372 D17513 D19983
LD TR0
AND H10.14
*U(422) D19373 D17514 D19984
LD TR0
AND H10.15
*U(422) D19374 D17515 D19985

; rung 2
LD T0094
OUT TR0
AND H11.00
*U(422) D19375 D17516 D19986
LD TR0
AND H11.01
*U(422) D19376 D17517 D19987
LD TR0
AND H11.02
*U(422) D19377 D17518 D19988
LD TR0
AND H11.03
*U(422) D19378 D17519 D19989
LD TR0
AND H11.04
*U(422) D19379 D17520 D19990
LD TR0
AND H11.05
*U(422) D19380 D17521 D19991
LD TR0
AND H11.06
*U(422) D19381 D17522 D19992
LD TR0
AND H11.07
*U(422) D19382 D17523 D19993
; rung 3
LD T0094
OUT TR0
AND H11.08
*U(422) D19383 D17524 D19994
LD TR0
AND H11.09
*U(422) D19384 D17525 D19995
LD TR0
AND H11.10
*U(422) D19385 D17526 D19996
LD TR0
AND H11.11
*U(422) D19386 D17527 D19997

; rung 4
LD T0094
OUT TR0
AND H12.00
*U(422) D18574 D17530 D19170
LD TR0
AND H12.01
*U(422) D18575 D17531 D19171
LD TR0
AND H12.02
*U(422) D18576 D17532 D19172
LD TR0
AND H12.03
*U(422) D18577 D17533 D19173
LD TR0
AND H12.04
*U(422) D18578 D17534 D19174
LD TR0
AND H12.05
*U(422) D18579 D17535 D19175
LD TR0
AND H12.06
*U(422) D18580 D17536 D19176
LD TR0
AND H12.07
*U(422) D18581 D17537 D19177

; rung 5
LD T0094
OUT TR0
AND H12.08
*U(422) D18582 D17538 D19178
LD TR0
AND H12.09
*U(422) D18583 D17539 D19179
LD TR0
AND H12.10
*U(422) D18584 D17540 D19180
LD TR0
AND H12.11
*U(422) D18585 D17541 D19181
LD TR0
AND H12.12
*U(422) D18586 D17542 D19182
LD TR0
AND H12.13
*U(422) D18587 D17543 D19183
LD TR0
AND H12.14
*U(422) D18588 D17544 D19184
LD TR0
AND H12.15
*U(422) D18589 D17545 D19185

; rung 6
LD T0094
OUT TR0
AND H13.00
*U(422) D18590 D17546 D19186
LD TR0
AND H13.01
*U(422) D18591 D17547 D19187
LD TR0
AND H13.02
*U(422) D18592 D17548 D19188
LD TR0
AND H13.03
*U(422) D18593 D17549 D19189
LD TR0
AND H13.04
*U(422) D18594 D17550 D19190
LD TR0
AND H13.05
*U(422) D18595 D17551 D19191
LD TR0
AND H13.06
*U(422) D18596 D17552 D19192
LD TR0
AND H13.07
*U(422) D18597 D17553 D19193
LD TR0
AND H13.08
*U(422) D18598 D17554 D19194
LD TR0
AND H13.09
*U(422) D18599 D17555 D19195

; rung 7: ---------- 制御停止中処理 -----
LDNOT T0094
BSET(071) #0 D19970 D19997
BSET(071) #0 D19170 D19195
BSET(071) #0 D19303 D19358
BSET(071) #0 D18522 D18573
; rung 8: ********** 熱電対抜け監視 ********** / ---------- HFU0 ----------
LD 420.06
AND T0094
AND H20.00
AND>=(325) D19303 D2900
ANDNOT T0900
@MOV(021) D19219 D3901
TIM 0900 D2901
AND T0900
OUT TR0
-(410) D19219 D3901 D3900
AND P_CY
MOV(021) #0 D3900
LD TR0
AND>=(325) D2902 D3900
@MOVB(082) #FFFF #0 D2880

; rung 9
LD 420.06
AND T0094
AND H20.01
AND>=(325) D19305 D2900
ANDNOT T0901
@MOV(021) D19220 D3902
TIM 0901 D2901
AND T0901
OUT TR0
-(410) D19220 D3902 D3900
AND P_CY
MOV(021) #0 D3900
LD TR0
AND>=(325) D2902 D3900
@MOVB(082) #FFFF #101 D2880
; rung 10
LD 420.06
AND T0094
AND H20.02
AND>=(325) D19307 D2900
ANDNOT T0902
@MOV(021) D19221 D3903
TIM 0902 D2901
AND T0902
OUT TR0
-(410) D19221 D3903 D3900
AND P_CY
MOV(021) #0 D3900
LD TR0
AND>=(325) D2902 D3900
@MOVB(082) #FFFF #202 D2880

; rung 11
LD 420.06
AND T0094
AND H20.03
AND>=(325) D19309 D2900
ANDNOT T0903
@MOV(021) D19222 D3904
TIM 0903 D2901
AND T0903
OUT TR0
-(410) D19222 D3904 D3900
AND P_CY
MOV(021) #0 D3900
LD TR0
AND>=(325) D2902 D3900
@MOVB(082) #FFFF #303 D2880
; rung 12
LD 420.06
AND T0094
AND H20.04
AND>=(325) D19311 D2900
ANDNOT T0904
@MOV(021) D19223 D3905
TIM 0904 D2901
AND T0904
OUT TR0
-(410) D19223 D3905 D3900
AND P_CY
MOV(021) #0 D3900
LD TR0
AND>=(325) D2902 D3900
@MOVB(082) #FFFF #404 D2880

; rung 13
LD 420.06
AND T0094
AND H20.05
AND>=(325) D19313 D2900
ANDNOT T0905
@MOV(021) D19224 D3906
TIM 0905 D2901
AND T0905
OUT TR0
-(410) D19224 D3906 D3900
AND P_CY
MOV(021) #0 D3900
LD TR0
AND>=(325) D2902 D3900
@MOVB(082) #FFFF #505 D2880
; rung 14
LD 420.06
AND T0094
AND H20.06
AND>=(325) D19315 D2900
ANDNOT T0906
@MOV(021) D19225 D3907
TIM 0906 D2901
AND T0906
OUT TR0
-(410) D19225 D3907 D3900
AND P_CY
MOV(021) #0 D3900
LD TR0
AND>=(325) D2902 D3900
@MOVB(082) #FFFF #606 D2880

; rung 15
LD 420.06
AND T0094
AND H20.07
AND>=(325) D19317 D2900
ANDNOT T0907
@MOV(021) D19226 D3908
TIM 0907 D2901
AND T0907
OUT TR0
-(410) D19226 D3908 D3900
AND P_CY
MOV(021) #0 D3900
LD TR0
AND>=(325) D2902 D3900
@MOVB(082) #FFFF #707 D2880
; rung 16
LD 420.06
AND T0094
AND H20.08
AND>=(325) D19319 D2900
ANDNOT T0908
@MOV(021) D19227 D3909
TIM 0908 D2901
AND T0908
OUT TR0
-(410) D19227 D3909 D3900
AND P_CY
MOV(021) #0 D3900
LD TR0
AND>=(325) D2902 D3900
@MOVB(082) #FFFF #808 D2880

; rung 17
LD 420.06
AND T0094
AND H20.09
AND>=(325) D19321 D2900
ANDNOT T0909
@MOV(021) D19228 D3910
TIM 0909 D2901
AND T0909
OUT TR0
-(410) D19228 D3910 D3900
AND P_CY
MOV(021) #0 D3900
LD TR0
AND>=(325) D2902 D3900
@MOVB(082) #FFFF #909 D2880
; rung 18
LD 420.06
AND T0094
AND H20.10
AND>=(325) D19323 D2900
ANDNOT T0910
@MOV(021) D19229 D3911
TIM 0910 D2901
AND T0910
OUT TR0
-(410) D19229 D3911 D3900
AND P_CY
MOV(021) #0 D3900
LD TR0
AND>=(325) D2902 D3900
@MOVB(082) #FFFF #A0A D2880

; rung 19
LD 420.06
AND T0094
AND H20.11
AND>=(325) D19325 D2900
ANDNOT T0911
@MOV(021) D19230 D3912
TIM 0911 D2901
AND T0911
OUT TR0
-(410) D19230 D3912 D3900
AND P_CY
MOV(021) #0 D3900
LD TR0
AND>=(325) D2902 D3900
@MOVB(082) #FFFF #B0B D2880
; rung 20
LD 420.06
AND T0094
AND H20.12
AND>=(325) D19327 D2900
ANDNOT T0912
@MOV(021) D19231 D3913
TIM 0912 D2901
AND T0912
OUT TR0
-(410) D19231 D3913 D3900
AND P_CY
MOV(021) #0 D3900
LD TR0
AND>=(325) D2902 D3900
@MOVB(082) #FFFF #C0C D2880

; rung 21
LD 420.06
AND T0094
AND H20.13
AND>=(325) D19329 D2900
ANDNOT T0913
@MOV(021) D19232 D3914
TIM 0913 D2901
AND T0913
OUT TR0
-(410) D19232 D3914 D3900
AND P_CY
MOV(021) #0 D3900
LD TR0
AND>=(325) D2902 D3900
@MOVB(082) #FFFF #D0D D2880
; rung 22
LD 420.06
AND T0094
AND H20.14
AND>=(325) D19331 D2900
ANDNOT T0914
@MOV(021) D19233 D3915
TIM 0914 D2901
AND T0914
OUT TR0
-(410) D19233 D3915 D3900
AND P_CY
MOV(021) #0 D3900
LD TR0
AND>=(325) D2902 D3900
@MOVB(082) #FFFF #E0E D2880

; rung 23
LD 420.06
AND T0094
AND H20.15
AND>=(325) D19333 D2900
ANDNOT T0915
@MOV(021) D19234 D3916
TIM 0915 D2901
AND T0915
OUT TR0
-(410) D19234 D3916 D3900
AND P_CY
MOV(021) #0 D3900
LD TR0
AND>=(325) D2902 D3900
@MOVB(082) #FFFF #F0F D2880
; rung 24
LD 420.06
AND T0094
AND H21.00
AND>=(325) D19335 D2900
ANDNOT T0916
@MOV(021) D19235 D3917
TIM 0916 D2901
AND T0916
OUT TR0
-(410) D19235 D3917 D3900
AND P_CY
MOV(021) #0 D3900
LD TR0
AND>=(325) D2902 D3900
@MOVB(082) #FFFF #0 D2881

; rung 25
LD 420.06
AND T0094
AND H21.01
AND>=(325) D19337 D2900
ANDNOT T0917
@MOV(021) D19236 D3918
TIM 0917 D2901
AND T0917
OUT TR0
-(410) D19236 D3918 D3900
AND P_CY
MOV(021) #0 D3900
LD TR0
AND>=(325) D2902 D3900
@MOVB(082) #FFFF #101 D2881
; rung 26
LD 420.06
AND T0094
AND H21.02
AND>=(325) D19339 D2900
ANDNOT T0918
@MOV(021) D19237 D3919
TIM 0918 D2901
AND T0918
OUT TR0
-(410) D19237 D3919 D3900
AND P_CY
MOV(021) #0 D3900
LD TR0
AND>=(325) D2902 D3900
@MOVB(082) #FFFF #202 D2881

; rung 27
LD 420.06
AND T0094
AND H21.03
AND>=(325) D19341 D2900
ANDNOT T0919
@MOV(021) D19238 D3920
TIM 0919 D2901
AND T0919
OUT TR0
-(410) D19238 D3920 D3900
AND P_CY
MOV(021) #0 D3900
LD TR0
AND>=(325) D2902 D3900
@MOVB(082) #FFFF #303 D2881
; rung 28
LD 420.06
AND T0094
AND H21.04
AND>=(325) D19343 D2900
ANDNOT T0920
@MOV(021) D19239 D3921
TIM 0920 D2901
AND T0920
OUT TR0
-(410) D19239 D3921 D3900
AND P_CY
MOV(021) #0 D3900
LD TR0
AND>=(325) D2902 D3900
@MOVB(082) #FFFF #404 D2881

; rung 29
LD 420.06
AND T0094
AND H21.05
AND>=(325) D19345 D2900
ANDNOT T0921
@MOV(021) D19240 D3922
TIM 0921 D2901
AND T0921
OUT TR0
-(410) D19240 D3922 D3900
AND P_CY
MOV(021) #0 D3900
LD TR0
AND>=(325) D2902 D3900
@MOVB(082) #FFFF #505 D2881
; rung 30
LD 420.06
AND T0094
AND H21.06
AND>=(325) D19347 D2900
ANDNOT T0922
@MOV(021) D19241 D3923
TIM 0922 D2901
AND T0922
OUT TR0
-(410) D19241 D3923 D3900
AND P_CY
MOV(021) #0 D3900
LD TR0
AND>=(325) D2902 D3900
@MOVB(082) #FFFF #606 D2881

; rung 31
LD 420.06
AND T0094
AND H21.07
AND>=(325) D19349 D2900
ANDNOT T0923
@MOV(021) D19242 D3924
TIM 0923 D2901
AND T0923
OUT TR0
-(410) D19242 D3924 D3900
AND P_CY
MOV(021) #0 D3900
LD TR0
AND>=(325) D2902 D3900
@MOVB(082) #FFFF #707 D2881
; rung 32
LD 420.06
AND T0094
AND H21.08
AND>=(325) D19351 D2900
ANDNOT T0924
@MOV(021) D19243 D3925
TIM 0924 D2901
AND T0924
OUT TR0
-(410) D19243 D3925 D3900
AND P_CY
MOV(021) #0 D3900
LD TR0
AND>=(325) D2902 D3900
@MOVB(082) #FFFF #808 D2881

; rung 33
LD 420.06
AND T0094
AND H21.09
AND>=(325) D19353 D2900
ANDNOT T0925
@MOV(021) D19244 D3926
TIM 0925 D2901
AND T0925
OUT TR0
-(410) D19244 D3926 D3900
AND P_CY
MOV(021) #0 D3900
LD TR0
AND>=(325) D2902 D3900
@MOVB(082) #FFFF #909 D2881
; rung 34
LD 420.06
AND T0094
AND H21.10
AND>=(325) D19355 D2900
ANDNOT T0926
@MOV(021) D19245 D3927
TIM 0926 D2901
AND T0926
OUT TR0
-(410) D19245 D3927 D3900
AND P_CY
MOV(021) #0 D3900
LD TR0
AND>=(325) D2902 D3900
@MOVB(082) #FFFF #A0A D2881

; rung 35
LD 420.06
AND T0094
AND H21.11
AND>=(325) D19357 D2900
ANDNOT T0927
@MOV(021) D19246 D3928
TIM 0927 D2901
AND T0927
OUT TR0
-(410) D19246 D3928 D3900
AND P_CY
MOV(021) #0 D3900
LD TR0
AND>=(325) D2902 D3900
@MOVB(082) #FFFF #B0B D2881
; rung 36: ---------- HFU1 ----------
LD 420.06
AND T0094
AND H22.00
AND>=(325) D18522 D2900
ANDNOT T0928
@MOV(021) D18420 D3929
TIM 0928 D2901
AND T0928
OUT TR0
-(410) D18420 D3929 D3900
AND P_CY
MOV(021) #0 D3900
LD TR0
AND>=(325) D2902 D3900
@MOVB(082) #FFFF #0 D2882

; rung 37
LD 420.06
AND T0094
AND H22.01
AND>=(325) D18524 D2900
ANDNOT T0929
@MOV(021) D18421 D3930
TIM 0929 D2901
AND T0929
OUT TR0
-(410) D18421 D3930 D3900
AND P_CY
MOV(021) #0 D3900
LD TR0
AND>=(325) D2902 D3900
@MOVB(082) #FFFF #101 D2882
; rung 38
LD 420.06
AND T0094
AND H22.02
AND>=(325) D18526 D2900
ANDNOT T0930
@MOV(021) D18422 D3931
TIM 0930 D2901
AND T0930
OUT TR0
-(410) D18422 D3931 D3900
AND P_CY
MOV(021) #0 D3900
LD TR0
AND>=(325) D2902 D3900
@MOVB(082) #FFFF #202 D2882

; rung 39
LD 420.06
AND T0094
AND H22.03
AND>=(325) D18528 D2900
ANDNOT T0931
@MOV(021) D18423 D3932
TIM 0931 D2901
AND T0931
OUT TR0
-(410) D18423 D3932 D3900
AND P_CY
MOV(021) #0 D3900
LD TR0
AND>=(325) D2902 D3900
@MOVB(082) #FFFF #303 D2882
; rung 40
LD 420.06
AND T0094
AND H22.04
AND>=(325) D18530 D2900
ANDNOT T0932
@MOV(021) D18424 D3933
TIM 0932 D2901
AND T0932
OUT TR0
-(410) D18424 D3933 D3900
AND P_CY
MOV(021) #0 D3900
LD TR0
AND>=(325) D2902 D3900
@MOVB(082) #FFFF #404 D2882

; rung 41
LD 420.06
AND T0094
AND H22.05
AND>=(325) D18532 D2900
ANDNOT T0933
@MOV(021) D18425 D3934
TIM 0933 D2901
AND T0933
OUT TR0
-(410) D18425 D3934 D3900
AND P_CY
MOV(021) #0 D3900
LD TR0
AND>=(325) D2902 D3900
@MOVB(082) #FFFF #505 D2882
; rung 42
LD 420.06
AND T0094
AND H22.06
AND>=(325) D18534 D2900
ANDNOT T0934
@MOV(021) D18426 D3935
TIM 0934 D2901
AND T0934
OUT TR0
-(410) D18426 D3935 D3900
AND P_CY
MOV(021) #0 D3900
LD TR0
AND>=(325) D2902 D3900
@MOVB(082) #FFFF #606 D2882

; rung 43
LD 420.06
AND T0094
AND H22.07
AND>=(325) D18536 D2900
ANDNOT T0935
@MOV(021) D18427 D3936
TIM 0935 D2901
AND T0935
OUT TR0
-(410) D18427 D3936 D3900
AND P_CY
MOV(021) #0 D3900
LD TR0
AND>=(325) D2902 D3900
@MOVB(082) #FFFF #707 D2882
; rung 44
LD 420.06
AND T0094
AND H22.08
AND>=(325) D18538 D2900
ANDNOT T0936
@MOV(021) D18428 D3937
TIM 0936 D2901
AND T0936
OUT TR0
-(410) D18428 D3937 D3900
AND P_CY
MOV(021) #0 D3900
LD TR0
AND>=(325) D2902 D3900
@MOVB(082) #FFFF #808 D2882

; rung 45
LD 420.06
AND T0094
AND H22.09
AND>=(325) D18540 D2900
ANDNOT T0937
@MOV(021) D18429 D3938
TIM 0937 D2901
AND T0937
OUT TR0
-(410) D18429 D3938 D3900
AND P_CY
MOV(021) #0 D3900
LD TR0
AND>=(325) D2902 D3900
@MOVB(082) #FFFF #909 D2882
; rung 46
LD 420.06
AND T0094
AND H22.10
AND>=(325) D18542 D2900
ANDNOT T0938
@MOV(021) D18430 D3939
TIM 0938 D2901
AND T0938
OUT TR0
-(410) D18430 D3939 D3900
AND P_CY
MOV(021) #0 D3900
LD TR0
AND>=(325) D2902 D3900
@MOVB(082) #FFFF #A0A D2882

; rung 47
LD 420.06
AND T0094
AND H22.11
AND>=(325) D18544 D2900
ANDNOT T0939
@MOV(021) D18431 D3940
TIM 0939 D2901
AND T0939
OUT TR0
-(410) D18431 D3940 D3900
AND P_CY
MOV(021) #0 D3900
LD TR0
AND>=(325) D2902 D3900
@MOVB(082) #FFFF #B0B D2882
; rung 48
LD 420.06
AND T0094
AND H22.12
AND>=(325) D18546 D2900
ANDNOT T0940
@MOV(021) D18432 D3941
TIM 0940 D2901
AND T0940
OUT TR0
-(410) D18432 D3941 D3900
AND P_CY
MOV(021) #0 D3900
LD TR0
AND>=(325) D2902 D3900
@MOVB(082) #FFFF #C0C D2882

; rung 49
LD 420.06
AND T0094
AND H22.13
AND>=(325) D18548 D2900
ANDNOT T0941
@MOV(021) D18433 D3942
TIM 0941 D2901
AND T0941
OUT TR0
-(410) D18433 D3942 D3900
AND P_CY
MOV(021) #0 D3900
LD TR0
AND>=(325) D2902 D3900
@MOVB(082) #FFFF #D0D D2882
; rung 50
LD 420.06
AND T0094
AND H22.14
AND>=(325) D18550 D2900
ANDNOT T0942
@MOV(021) D18434 D3943
TIM 0942 D2901
AND T0942
OUT TR0
-(410) D18434 D3943 D3900
AND P_CY
MOV(021) #0 D3900
LD TR0
AND>=(325) D2902 D3900
@MOVB(082) #FFFF #E0E D2882

; rung 51
LD 420.06
AND T0094
AND H22.15
AND>=(325) D18552 D2900
ANDNOT T0943
@MOV(021) D18435 D3944
TIM 0943 D2901
AND T0943
OUT TR0
-(410) D18435 D3944 D3900
AND P_CY
MOV(021) #0 D3900
LD TR0
AND>=(325) D2902 D3900
@MOVB(082) #FFFF #F0F D2882
; rung 52
LD 420.06
AND T0094
AND H23.00
AND>=(325) D18554 D2900
ANDNOT T0944
@MOV(021) D18436 D3945
TIM 0944 D2901
AND T0944
OUT TR0
-(410) D18436 D3945 D3900
AND P_CY
MOV(021) #0 D3900
LD TR0
AND>=(325) D2902 D3900
@MOVB(082) #FFFF #0 D2883

; rung 53
LD 420.06
AND T0094
AND H23.01
AND>=(325) D18556 D2900
ANDNOT T0945
@MOV(021) D18437 D3946
TIM 0945 D2901
AND T0945
OUT TR0
-(410) D18437 D3946 D3900
AND P_CY
MOV(021) #0 D3900
LD TR0
AND>=(325) D2902 D3900
@MOVB(082) #FFFF #101 D2883
; rung 54
LD 420.06
AND T0094
AND H23.02
AND>=(325) D18558 D2903
ANDNOT T0946
@MOV(021) D18438 D3947
TIM 0946 D2904
AND T0946
OUT TR0
-(410) D18438 D3947 D3900
AND P_CY
MOV(021) #0 D3900
LD TR0
AND>=(325) D2905 D3900
@MOVB(082) #FFFF #202 D2883

; rung 55
LD 420.06
AND T0094
AND H23.03
AND>=(325) D18560 D2903
ANDNOT T0947
@MOV(021) D18439 D3948
TIM 0947 D2904
AND T0947
OUT TR0
-(410) D18439 D3948 D3900
AND P_CY
MOV(021) #0 D3900
LD TR0
AND>=(325) D2905 D3900
@MOVB(082) #FFFF #303 D2883
; rung 56
LD 420.06
AND T0094
AND H23.04
AND>=(325) D18562 D2903
ANDNOT T0948
@MOV(021) D18440 D3949
TIM 0948 D2904
AND T0948
OUT TR0
-(410) D18440 D3949 D3900
AND P_CY
MOV(021) #0 D3900
LD TR0
AND>=(325) D2905 D3900
@MOVB(082) #FFFF #404 D2883

; rung 57
LD 420.06
AND T0094
AND H23.05
AND>=(325) D18564 D2903
ANDNOT T0949
@MOV(021) D18441 D3950
TIM 0949 D2904
AND T0949
OUT TR0
-(410) D18441 D3950 D3900
AND P_CY
MOV(021) #0 D3900
LD TR0
AND>=(325) D2905 D3900
@MOVB(082) #FFFF #505 D2883
; rung 58
LD 420.06
AND T0094
AND H23.06
AND>=(325) D18566 D2903
ANDNOT T0950
@MOV(021) D18442 D3951
TIM 0950 D2904
AND T0950
OUT TR0
-(410) D18442 D3951 D3900
AND P_CY
MOV(021) #0 D3900
LD TR0
AND>=(325) D2905 D3900
@MOVB(082) #FFFF #606 D2883

; rung 59
LD 420.06
AND T0094
AND H23.07
AND>=(325) D18568 D2903
ANDNOT T0951
@MOV(021) D18443 D3952
TIM 0951 D2904
AND T0951
OUT TR0
-(410) D18443 D3952 D3900
AND P_CY
MOV(021) #0 D3900
LD TR0
AND>=(325) D2905 D3900
@MOVB(082) #FFFF #707 D2883
; rung 60
LD 420.06
AND T0094
AND H23.08
AND>=(325) D18570 D2903
ANDNOT T0952
@MOV(021) D18444 D3953
TIM 0952 D2904
AND T0952
OUT TR0
-(410) D18444 D3953 D3900
AND P_CY
MOV(021) #0 D3900
LD TR0
AND>=(325) D2905 D3900
@MOVB(082) #FFFF #808 D2883

; rung 61
LD 420.06
AND T0094
AND H23.09
AND>=(325) D18572 D2903
ANDNOT T0953
@MOV(021) D18445 D3954
TIM 0953 D2904
AND T0953
OUT TR0
-(410) D18445 D3954 D3900
AND P_CY
MOV(021) #0 D3900
LD TR0
AND>=(325) D2905 D3900
@MOVB(082) #FFFF #909 D2883
; rung 62
LD 400.00
BSET(071) #0 D2880 D2884

### Section CALENDAR_TIMER

; rung 0: ********** カレンダタイマ処理 **********
LD W395.14
OR H17.00
ANDNOT W395.15
ANDNOT H17.01
OUT H17.00
; rung 1
LDNOT W395.14
ANDNOT H17.00
OUT H17.01
; rung 2
LD W395.07
@XORW(036) H0 #1 H0
; rung 3
LD W395.08
@XORW(036) H0 #2 H0
; rung 4
LD W395.09
@XORW(036) H0 #4 H0
; rung 5
LD W395.10
@XORW(036) H0 #8 H0
; rung 6
LD W395.11
@XORW(036) H0 #10 H0
; rung 7
LD W395.12
@XORW(036) H0 #20 H0
; rung 8
LD W395.13
@XORW(036) H0 #40 H0

; rung 9
LD P_On
MOVD(083) A351 #12 D244
MOVD(083) A352 #210 D244
; rung 10
LD P_On
MLPX(076) A354 #10 W213
MOVD(083) A353 #10 D225
MOVD(083) A352 #12 D226
MOVD(083) A352 #10 D227
MOVD(083) A351 #12 D228
MOVD(083) A351 #10 D229

; rung 11
LDNOT H17.11
ANDNOT W433.00
OUT TR0
AND H0.00
AND W213.00
MOVD(083) D231 #10 D245
MOVD(083) D230 #210 D245
LD TR0
AND H0.01
AND W213.01
MOVD(083) D233 #10 D245
MOVD(083) D232 #210 D245
LD TR0
AND H0.02
AND W213.02
MOVD(083) D235 #10 D245
MOVD(083) D234 #210 D245
; rung 12
LDNOT H17.11
ANDNOT W433.00
OUT TR0
AND H0.03
AND W213.03
MOVD(083) D237 #10 D245
MOVD(083) D236 #210 D245
LD TR0
AND H0.04
AND W213.04
MOVD(083) D239 #10 D245
MOVD(083) D238 #210 D245
LD TR0
AND H0.05
AND W213.05
MOVD(083) D241 #10 D245
MOVD(083) D240 #210 D245

; rung 13
LDNOT H17.11
ANDNOT W433.00
OUT TR0
AND H0.06
AND W213.06
MOVD(083) D243 #10 D245
MOVD(083) D242 #210 D245
LD TR0
LD H0.00
AND W213.00
LD H0.01
AND W213.01
ORLD
LD H0.02
AND W213.02
ORLD
LD H0.03
AND W213.03
ORLD
LD H0.04
AND W213.04
ORLD
LD H0.05
AND W213.05
ORLD
LD H0.06
AND W213.06
ORLD
ANDLD
CMP(020) D245 D244
AND P_EQ
OUT W61.15
; rung 14
LD W61.15
TIM 0197 #10
; rung 15
LD W61.15
@MOV(021) D227 D20500
@MOV(021) D228 D20501
; rung 16
LD 2050.01
@MOV(021) D227 D20502
@MOV(021) D228 D20503

; rung 17: ----- STEP1昇温切替確認 -----
LD T0460
AND H17.11
CMPL(060) D225 D3694
AND P_EQ
CMPL(060) D227 D3382
AND P_EQ
OUT W61.00
; rung 18
LD W61.00
TIM 0447 #10
; rung 19
LD T0447
DIFU(013) W61.01
; rung 20
LD W61.01
OR H93.00
AND H17.11
AND T0460
ANDNOT H93.01
ANDNOT H93.02
OUT H93.00
DIFU(013) W61.06
; rung 21: ----- STEP2昇温切替確認 -----
LD T0460
AND H17.11
CMPL(060) D225 D3696
AND P_EQ
CMPL(060) D227 D3384
AND P_EQ
OUT W61.02
; rung 22
LD W61.02
TIM 0448 #10
; rung 23
LD T0448
DIFU(013) W61.03
; rung 24
LD W61.03
AND H93.00
OR H93.01
AND H17.11
AND T0460
ANDNOT H93.02
OUT H93.01
DIFU(013) W61.07

; rung 25: ----- STEP通常昇温切替確認 -----
LD T0460
AND H17.11
CMPL(060) D225 D3698
AND P_EQ
CMPL(060) D227 D3386
AND P_EQ
OUT W61.04
; rung 26
LD W61.04
TIM 0449 #10
; rung 27
LD T0449
DIFU(013) W61.05
; rung 28
LD W61.05
AND H93.01
OR H93.02
AND H17.11
AND T0460
OUT H93.02
; rung 29
LDNOT H2.15
ANDNOT H93.00
ANDNOT H93.01
OUT W61.08

### Section MOLD_DATA

; rung 0: ********* データ登録／読出／変更 ********** / ・NB-S標準では60ﾌｧｲﾙのﾌｧｲﾙ名分DMを取っていたが、今回DMが不足しているので15ﾌｧｲﾙ分を確保し / 随時EMから読出する。 / ・今回、肉調PLCからの信号でデータ制御する / ・ﾊﾞﾝｸ0に60ﾌｧｲﾙ分のﾌｧｲﾙ名と格納するDMﾃﾞｰﾀ / ﾊﾞﾝｸ1～7までに60ﾌｧｲﾙ分の成形ﾃﾞｰﾀを400毎に格納 / ----- 肉調PLCより信号受信 -----
LD 456.08
DIFU(013) W506.00
; rung 1
LD 456.09
DIFU(013) W506.01
; rung 2
LD 456.14
DIFU(013) W506.02
; rung 3
LD W506.00
OR W506.01
OR W506.02
OUT W506.03
; rung 4: ----- ﾌｧｲﾙNo.よりNo.1～15ﾌｧｲﾙか判別 -----
LD W506.03
CMP(020) D90 #1
ANDNOT P_LT
CMP(020) D90 #15
ANDNOT P_GT
OUT W505.00
; rung 5
LD W506.02
AND W505.00
ANDNOT W506.00
ANDNOT W506.01
OUT W505.01
; rung 6
LD W506.00
AND W505.00
ANDNOT W506.01
ANDNOT W506.02
OUT W505.02
; rung 7
LD W506.01
AND W505.00
ANDNOT W506.00
ANDNOT W506.02
OUT W505.03

; rung 8: ----- ﾌｧｲﾙNo.よりNo.16～30ﾌｧｲﾙか判別 -----
LD W506.03
CMP(020) D90 #16
ANDNOT P_LT
CMP(020) D90 #30
ANDNOT P_GT
OUT W505.04
; rung 9
LD W506.02
AND W505.04
ANDNOT W506.00
ANDNOT W506.01
OUT W505.05
; rung 10
LD W506.00
AND W505.04
ANDNOT W506.01
ANDNOT W506.02
OUT W505.06
; rung 11
LD W506.01
AND W505.04
ANDNOT W506.00
ANDNOT W506.02
OUT W505.07
; rung 12: ----- ﾌｧｲﾙNo.よりNo.31～45ﾌｧｲﾙか判別 -----
LD W506.03
CMP(020) D90 #31
ANDNOT P_LT
CMP(020) D90 #45
ANDNOT P_GT
OUT W505.08
; rung 13
LD W506.02
AND W505.08
ANDNOT W506.00
ANDNOT W506.01
OUT W505.09
; rung 14
LD W506.00
AND W505.08
ANDNOT W506.01
ANDNOT W506.02
OUT W505.10
; rung 15
LD W506.01
AND W505.08
ANDNOT W506.00
ANDNOT W506.02
OUT W505.11

; rung 16: ----- ﾌｧｲﾙNo.よりNo.46～60ﾌｧｲﾙか判別 -----
LD W506.03
CMP(020) D90 #46
ANDNOT P_LT
CMP(020) D90 #60
ANDNOT P_GT
OUT W505.12
; rung 17
LD W506.02
AND W505.12
ANDNOT W506.00
ANDNOT W506.01
OUT W505.13
; rung 18
LD W506.00
AND W505.12
ANDNOT W506.01
ANDNOT W506.02
OUT W505.14
; rung 19
LD W506.01
AND W505.12
ANDNOT W506.00
ANDNOT W506.02
OUT W505.15
; rung 20: ----- ﾌｧｲﾙNo.1～60をNo.1～15に分ける -----
LD P_On
BIN(023) D90 D160
MLPX(076) D160 #10 W507
; rung 21
LD W508.00
AND W507.01
LD W508.01
AND W507.00
ORLD
LD W508.01
AND W507.15
ORLD
LD W508.02
AND W507.14
ORLD
AND W506.03
OUT W504.01
; rung 22
LD W508.00
AND W507.02
LD W508.01
AND W507.01
ORLD
LD W508.02
AND W507.00
ORLD
LD W508.02
AND W507.15
ORLD
AND W506.03
OUT W504.02

; rung 23
LD W508.00
AND W507.03
LD W508.01
AND W507.02
ORLD
LD W508.02
AND W507.01
ORLD
LD W508.03
AND W507.00
ORLD
AND W506.03
OUT W504.03
; rung 24
LD W508.00
AND W507.04
LD W508.01
AND W507.03
ORLD
LD W508.02
AND W507.02
ORLD
LD W508.03
AND W507.01
ORLD
AND W506.03
OUT W504.04
; rung 25
LD W508.00
AND W507.05
LD W508.01
AND W507.04
ORLD
LD W508.02
AND W507.03
ORLD
LD W508.03
AND W507.02
ORLD
AND W506.03
OUT W504.05
; rung 26
LD W508.00
AND W507.06
LD W508.01
AND W507.05
ORLD
LD W508.02
AND W507.04
ORLD
LD W508.03
AND W507.03
ORLD
AND W506.03
OUT W504.06
; rung 27
LD W508.00
AND W507.07
LD W508.01
AND W507.06
ORLD
LD W508.02
AND W507.05
ORLD
LD W508.03
AND W507.04
ORLD
AND W506.03
OUT W504.07

; rung 28
LD W508.00
AND W507.08
LD W508.01
AND W507.07
ORLD
LD W508.02
AND W507.06
ORLD
LD W508.03
AND W507.05
ORLD
AND W506.03
OUT W504.08
; rung 29
LD W508.00
AND W507.09
LD W508.01
AND W507.08
ORLD
LD W508.02
AND W507.07
ORLD
LD W508.03
AND W507.06
ORLD
AND W506.03
OUT W504.09
; rung 30
LD W508.00
AND W507.10
LD W508.01
AND W507.09
ORLD
LD W508.02
AND W507.08
ORLD
LD W508.03
AND W507.07
ORLD
AND W506.03
OUT W504.10
; rung 31
LD W508.00
AND W507.11
LD W508.01
AND W507.10
ORLD
LD W508.02
AND W507.09
ORLD
LD W508.03
AND W507.08
ORLD
AND W506.03
OUT W504.11
; rung 32
LD W508.00
AND W507.12
LD W508.01
AND W507.11
ORLD
LD W508.02
AND W507.10
ORLD
LD W508.03
AND W507.09
ORLD
AND W506.03
OUT W504.12

; rung 33
LD W508.00
AND W507.13
LD W508.01
AND W507.12
ORLD
LD W508.02
AND W507.11
ORLD
LD W508.03
AND W507.10
ORLD
AND W506.03
OUT W504.13
; rung 34
LD W508.00
AND W507.14
LD W508.01
AND W507.13
ORLD
LD W508.02
AND W507.12
ORLD
LD W508.03
AND W507.11
ORLD
AND W506.03
OUT W504.14
; rung 35
LD W508.00
AND W507.15
LD W508.01
AND W507.14
ORLD
LD W508.02
AND W507.13
ORLD
LD W508.03
AND W507.12
ORLD
AND W506.03
OUT W504.15
; rung 36: ----- 表示画面判別 ----- / ----- 成形ﾌｧｲﾙ1 -----
LDNOT W509.15
AND W379.09
AND W378.06
OUT W110.00
; rung 37
LDNOT W509.15
AND W379.09
AND W378.07
OR W505.01
OUT W110.01
; rung 38
LDNOT W509.15
AND W379.09
AND W378.08
OR W505.02
OUT W110.02
; rung 39
LDNOT W509.15
AND W379.09
AND W378.09
OR W505.03
OUT W110.03

; rung 40: ----- 成形ﾌｧｲﾙ2 -----
LDNOT W509.15
AND W379.09
AND W378.10
OUT W110.04
; rung 41
LDNOT W509.15
AND W379.09
AND W378.11
OR W505.05
OUT W110.05
; rung 42
LDNOT W509.15
AND W379.09
AND W378.12
OR W505.06
OUT W110.06
; rung 43
LDNOT W509.15
AND W379.09
AND W378.13
OR W505.07
OUT W110.07
; rung 44: ----- 成形ﾌｧｲﾙ3 -----
LDNOT W509.15
AND W379.09
AND W378.14
OUT W110.08
; rung 45
LDNOT W509.15
AND W379.09
AND W378.15
OR W505.09
OUT W110.09
; rung 46
LDNOT W509.15
AND W379.10
AND W378.00
OR W505.10
OUT W110.10
; rung 47
LDNOT W509.15
AND W379.10
AND W378.01
OR W505.11
OUT W110.11
; rung 48: ----- 成形ﾌｧｲﾙ4 -----
LDNOT W509.15
AND W379.10
AND W378.02
OUT W110.12

; rung 49
LDNOT W509.15
AND W379.10
AND W378.03
OR W505.13
OUT W110.13
; rung 50
LDNOT W509.15
AND W379.10
AND W378.04
OR W505.14
OUT W110.14
; rung 51
LDNOT W509.15
AND W379.10
AND W378.05
OR W505.15
OUT W110.15
; rung 52: ----- ﾃﾞｰﾀ読出ｲﾝﾀｰﾛｯｸ ----- / 現状は全押出機停止・成形機の自動運転信号(45003)の接点01311がOFF
LDNOT 401.10
ANDNOT 10.00
ANDNOT 10.01
ANDNOT 10.02
ANDNOT 10.03
ANDNOT 10.04
ANDNOT 10.05
OR 461.04
OUT W162.10
; rung 53: ----- 成形ﾌｧｲﾙ一覧1表示前処理 ----- / ﾌｧｲﾙ名No.1～15(EM0020～0139)までをﾌｧｲﾙ名No.1～15表示領域(DM0780～0899)へ転送
LD W162.12
OR W505.00
@XFER(070) &120 E0_20 D780
; rung 54
LD W162.12
OR W505.00
@MOV(021) #150 W0
; rung 55: ----- 成形ﾌｧｲﾙ一覧2表示前処理 ----- / ﾌｧｲﾙ名No.16～30(EM0140～0259)までをﾌｧｲﾙ名No.1～15表示領域(DM0780～0899)へ転送
LD W162.13
OR W505.04
@XFER(070) &120 E0_140 D780
@MOV(021) #154 W0

; rung 56: ----- 成形ﾌｧｲﾙ一覧3表示前処理 ----- / ﾌｧｲﾙ名No.31～45(EM0260～0379)までをﾌｧｲﾙ名No.1～15表示領域(DM0780～0899)へ転送
LD W162.14
OR W505.08
@XFER(070) &120 E0_260 D780
@MOV(021) #158 W0
; rung 57: ----- 成形ﾌｧｲﾙ一覧4表示前処理 ----- / ﾌｧｲﾙ名No.46～60(EM0380～0499)までをﾌｧｲﾙ名No.1～15表示領域(DM0780～0899)へ転送
LD W162.15
OR W505.12
@XFER(070) &120 E0_380 D780
@MOV(021) #162 W0
; rung 58: ----- 選択したﾌｧｲﾙNo.判別 -----
LD W160.01
OR W504.01
OR W161.01
ANDNOT W160.02
ANDNOT W160.03
ANDNOT W160.04
ANDNOT W160.05
ANDNOT W160.06
ANDNOT W160.07
ANDNOT W160.08
ANDNOT W160.09
ANDNOT W160.10
ANDNOT W160.11
ANDNOT W160.12
ANDNOT W160.13
ANDNOT W160.14
ANDNOT W160.15
OUT W161.01
; rung 59
LD W160.02
OR W504.02
OR W161.02
ANDNOT W160.01
ANDNOT W160.03
ANDNOT W160.04
ANDNOT W160.05
ANDNOT W160.06
ANDNOT W160.07
ANDNOT W160.08
ANDNOT W160.09
ANDNOT W160.10
ANDNOT W160.11
ANDNOT W160.12
ANDNOT W160.13
ANDNOT W160.14
ANDNOT W160.15
OUT W161.02
; rung 60
LD W160.03
OR W504.03
OR W161.03
ANDNOT W160.01
ANDNOT W160.02
ANDNOT W160.04
ANDNOT W160.05
ANDNOT W160.06
ANDNOT W160.07
ANDNOT W160.08
ANDNOT W160.09
ANDNOT W160.10
ANDNOT W160.11
ANDNOT W160.12
ANDNOT W160.13
ANDNOT W160.14
ANDNOT W160.15
OUT W161.03
; rung 61
LD W160.04
OR W504.04
OR W161.04
ANDNOT W160.01
ANDNOT W160.02
ANDNOT W160.03
ANDNOT W160.05
ANDNOT W160.06
ANDNOT W160.07
ANDNOT W160.08
ANDNOT W160.09
ANDNOT W160.10
ANDNOT W160.11
ANDNOT W160.12
ANDNOT W160.13
ANDNOT W160.14
ANDNOT W160.15
OUT W161.04

; rung 62
LD W160.05
OR W504.05
OR W161.05
ANDNOT W160.01
ANDNOT W160.02
ANDNOT W160.03
ANDNOT W160.04
ANDNOT W160.06
ANDNOT W160.07
ANDNOT W160.08
ANDNOT W160.09
ANDNOT W160.10
ANDNOT W160.11
ANDNOT W160.12
ANDNOT W160.13
ANDNOT W160.14
ANDNOT W160.15
OUT W161.05
; rung 63
LD W160.06
OR W504.06
OR W161.06
ANDNOT W160.01
ANDNOT W160.02
ANDNOT W160.03
ANDNOT W160.04
ANDNOT W160.05
ANDNOT W160.07
ANDNOT W160.08
ANDNOT W160.09
ANDNOT W160.10
ANDNOT W160.11
ANDNOT W160.12
ANDNOT W160.13
ANDNOT W160.14
ANDNOT W160.15
OUT W161.06
; rung 64
LD W160.07
OR W504.07
OR W161.07
ANDNOT W160.01
ANDNOT W160.02
ANDNOT W160.03
ANDNOT W160.04
ANDNOT W160.05
ANDNOT W160.06
ANDNOT W160.08
ANDNOT W160.09
ANDNOT W160.10
ANDNOT W160.11
ANDNOT W160.12
ANDNOT W160.13
ANDNOT W160.14
ANDNOT W160.15
OUT W161.07
; rung 65
LD W160.08
OR W504.08
OR W161.08
ANDNOT W160.01
ANDNOT W160.02
ANDNOT W160.03
ANDNOT W160.04
ANDNOT W160.05
ANDNOT W160.06
ANDNOT W160.07
ANDNOT W160.09
ANDNOT W160.10
ANDNOT W160.11
ANDNOT W160.12
ANDNOT W160.13
ANDNOT W160.14
ANDNOT W160.15
OUT W161.08
; rung 66
LD W160.09
OR W504.09
OR W161.09
ANDNOT W160.01
ANDNOT W160.02
ANDNOT W160.03
ANDNOT W160.04
ANDNOT W160.05
ANDNOT W160.06
ANDNOT W160.07
ANDNOT W160.08
ANDNOT W160.10
ANDNOT W160.11
ANDNOT W160.12
ANDNOT W160.13
ANDNOT W160.14
ANDNOT W160.15
OUT W161.09
; rung 67
LD W160.10
OR W504.10
OR W161.10
ANDNOT W160.01
ANDNOT W160.02
ANDNOT W160.03
ANDNOT W160.04
ANDNOT W160.05
ANDNOT W160.06
ANDNOT W160.07
ANDNOT W160.08
ANDNOT W160.09
ANDNOT W160.11
ANDNOT W160.12
ANDNOT W160.13
ANDNOT W160.14
ANDNOT W160.15
OUT W161.10
; rung 68
LD W160.11
OR W504.11
OR W161.11
ANDNOT W160.01
ANDNOT W160.02
ANDNOT W160.03
ANDNOT W160.04
ANDNOT W160.05
ANDNOT W160.06
ANDNOT W160.07
ANDNOT W160.08
ANDNOT W160.09
ANDNOT W160.10
ANDNOT W160.12
ANDNOT W160.13
ANDNOT W160.14
ANDNOT W160.15
OUT W161.11

; rung 69
LD W160.12
OR W504.12
OR W161.12
ANDNOT W160.01
ANDNOT W160.02
ANDNOT W160.03
ANDNOT W160.04
ANDNOT W160.05
ANDNOT W160.06
ANDNOT W160.07
ANDNOT W160.08
ANDNOT W160.09
ANDNOT W160.10
ANDNOT W160.11
ANDNOT W160.13
ANDNOT W160.14
ANDNOT W160.15
OUT W161.12
; rung 70
LD W160.13
OR W504.13
OR W161.13
ANDNOT W160.01
ANDNOT W160.02
ANDNOT W160.03
ANDNOT W160.04
ANDNOT W160.05
ANDNOT W160.06
ANDNOT W160.07
ANDNOT W160.08
ANDNOT W160.09
ANDNOT W160.10
ANDNOT W160.11
ANDNOT W160.12
ANDNOT W160.14
ANDNOT W160.15
OUT W161.13
; rung 71
LD W160.14
OR W504.14
OR W161.14
ANDNOT W160.01
ANDNOT W160.02
ANDNOT W160.03
ANDNOT W160.04
ANDNOT W160.05
ANDNOT W160.06
ANDNOT W160.07
ANDNOT W160.08
ANDNOT W160.09
ANDNOT W160.10
ANDNOT W160.11
ANDNOT W160.12
ANDNOT W160.13
ANDNOT W160.15
OUT W161.14
; rung 72
LD W160.15
OR W504.15
OR W161.15
ANDNOT W160.01
ANDNOT W160.02
ANDNOT W160.03
ANDNOT W160.04
ANDNOT W160.05
ANDNOT W160.06
ANDNOT W160.07
ANDNOT W160.08
ANDNOT W160.09
ANDNOT W160.10
ANDNOT W160.11
ANDNOT W160.12
ANDNOT W160.13
ANDNOT W160.14
OUT W161.15
; rung 73: ----- 画面から外れる場合はﾌｧｲﾙNo.ﾗﾝﾌﾟ消灯 -----
LDNOT W162.00
ANDNOT W162.11
ANDNOT W162.04
ANDNOT W162.12
ANDNOT W162.13
ANDNOT W162.14
ANDNOT W162.15
ANDNOT W163.14
ANDNOT W506.04
OUTNOT W162.09
; rung 74
LD W162.09
@MOV(021) #0 W161
; rung 75
LD W162.00
@MOV(021) #1 W0
; rung 76
LD W162.11
@MOV(021) #70 W0

; rung 77
LD W163.14
@EMBC(281) &0
@MOV(021) #166 W0
; rung 78
LD W110.00
OR W110.04
OR W110.08
OR W110.12
CMP(020) W161 #0
AND P_GT
OUT TR0
AND P_1s
OUT W163.01
OUT W163.02
AND W162.10
OUT W163.03
LD TR0
OUT W163.00
; rung 79: ----- ﾌｧｲﾙ名変更画面へ切替 -----
LD W163.00
AND W162.01
OUT TR0
AND W110.00
@MOV(021) #151 W0
LD TR0
AND W110.04
@MOV(021) #155 W0
LD TR0
AND W110.08
@MOV(021) #159 W0
LD TR0
AND W110.12
@MOV(021) #163 W0

; rung 80: ----- 成形ﾃﾞｰﾀ登録画面に切替 -----
LD W163.00
AND W162.02
OUT TR0
AND W110.00
@MOV(021) #152 W0
LD TR0
AND W110.04
@MOV(021) #156 W0
LD TR0
AND W110.08
@MOV(021) #160 W0
LD TR0
AND W110.12
@MOV(021) #164 W0
; rung 81: ----- 成形ﾃﾞｰﾀ読出画面に切替 -----
LD W163.00
AND W162.10
AND W162.03
OUT TR0
AND W110.00
@MOV(021) #153 W0
LD TR0
AND W110.04
@MOV(021) #157 W0
LD TR0
AND W110.08
@MOV(021) #161 W0
LD TR0
AND W110.12
@MOV(021) #165 W0
; rung 82: ----- ﾌｧｲﾙ操作時に選択ﾌｧｲﾙ名を作業領域(操作ﾌｧｲﾙ名)へ転送(15ﾌｧｲﾙ) -----
LD W162.01
OR W162.02
LD W162.10
AND W162.03
ORLD
OR W506.00
LD W506.01
AND W162.10
ORLD
OR W506.02
OUT W111.08

; rung 83: No.1
LD W111.08
AND W161.01
@XFERC(565) #8 D780 D771
; rung 84: No.2
LD W111.08
AND W161.02
@XFERC(565) #8 D788 D771
; rung 85: No.3
LD W111.08
AND W161.03
@XFERC(565) #8 D796 D771
; rung 86: No.4
LD W111.08
AND W161.04
@XFERC(565) #8 D804 D771
; rung 87: No.5
LD W111.08
AND W161.05
@XFERC(565) #8 D812 D771
; rung 88: No.6
LD W111.08
AND W161.06
@XFERC(565) #8 D820 D771
; rung 89: No.7
LD W111.08
AND W161.07
@XFERC(565) #8 D828 D771

; rung 90: No.8
LD W111.08
AND W161.08
@XFERC(565) #8 D836 D771
; rung 91: No.9
LD W111.08
AND W161.09
@XFERC(565) #8 D844 D771
; rung 92: No.10
LD W111.08
AND W161.10
@XFERC(565) #8 D852 D771
; rung 93: No.11
LD W111.08
AND W161.11
@XFERC(565) #8 D860 D771
; rung 94: No.12
LD W111.08
AND W161.12
@XFERC(565) #8 D868 D771
; rung 95: No.13
LD W111.08
AND W161.13
@XFERC(565) #8 D876 D771
; rung 96: No.14
LD W111.08
AND W161.14
@XFERC(565) #8 D884 D771

; rung 97: No.15
LD W111.08
AND W161.15
@XFERC(565) #8 D892 D771
; rung 98: ----- 選択されたﾌｧｲﾙNo.を数字で表示 -----
LD W111.08
ANDNOT P_On
OUT TR0
@DMPX(077) W161 D761 #0  // ﾌｧｲﾙNo.ﾗﾝﾌﾟを選択ﾌｧｲﾙNo.とする(BIN)
@MOVD(083) #0 #121 D761  // 選択ﾌｧｲﾙNo.の4-15bit目ｸﾘｱ
@BCD(024) D761 D762  // BCDに変換 / ﾌｧｲﾙ１画面の場合このまま表示(1～15)
AND W110.04
CLC(041)
@+BC(406) D762 #15 D762  // ﾌｧｲﾙ2画面の場合#0015加算する(16～30)
LD TR0
AND W110.08
CLC(041)
@+BC(406) D762 #30 D762  // ﾌｧｲﾙ3画面の場合#0030加算する(31～45)
LD TR0
AND W110.12
CLC(041)
@+BC(406) D762 #45 D762  // ﾌｧｲﾙ4画面の場合#0045加算する(46～60)
; rung 99
LD W111.08
@MOV(021) D90 D762

; rung 100: ----- ﾌｧｲﾙ名変更LAMP/SW処理 -----
LD W110.01
OR W110.05
OR W110.09
OR W110.13
OUT TR0
ANDNOT W163.09
AND P_0_2s
OUT W163.06
LD TR0
AND W234.10
OUT W111.05
LD TR0
LD W111.05
OR W163.09
ANDLD
OUT W163.09
; rung 101
LD W111.05
OR W506.02
OUT W162.06
; rung 102: ----- ﾃﾞｰﾀ登録LAMP/SW処理 -----
LD W110.02
OR W110.06
OR W110.10
OR W110.14
OUT TR0
ANDNOT W163.10
AND P_0_2s
OUT W163.07
LD TR0
AND W234.11
OUT W111.06
LD TR0
LD W111.06
OR W163.10
ANDLD
OUT W163.10
; rung 103
LD W111.06
OR W506.00
OUT W162.07
; rung 104: ----- ﾃﾞｰﾀ読出LAMP/SW処理 -----
LD W110.03
OR W110.07
OR W110.11
OR W110.15
AND W162.10
OUT TR0
ANDNOT W163.11
AND P_1s
OUT W163.08
LD TR0
LD W162.08
OR W163.11
ANDLD
OUT W163.11
; rung 105: ----- ﾌｧｲﾙ一覧1画面に戻る -----
LD W110.01
OR W110.02
OR W110.03
AND W162.05
@MOV(021) #150 W0

; rung 106: ----- ﾌｧｲﾙ一覧2画面に戻る -----
LD W110.05
OR W110.06
OR W110.07
AND W162.05
@MOV(021) #154 W0
; rung 107: ----- ﾌｧｲﾙ一覧3画面に戻る -----
LD W110.09
OR W110.10
OR W110.11
AND W162.05
@MOV(021) #158 W0
; rung 108: ----- ﾌｧｲﾙ一覧4画面に戻る -----
LD W110.13
OR W110.14
OR W110.15
AND W162.05
@MOV(021) #162 W0
; rung 109: ----- ﾌｧｲﾙ一覧画面に戻る時ﾌｧｲﾙNo.ﾗﾝﾌﾟ消去 -----
LD W162.05
@MOV(021) #0 W161

; rung 110: ***** ﾌｧｲﾙ名操作 ***** / 操作ﾌｧｲﾙ名より各1-15のﾌｧｲﾙ名へ転送 / No.1ﾌｧｲﾙ名変更 / No.1 ﾌｧｲﾙ名･･･EM0020～0027     No.16ﾌｧｲﾙ名･･･EM0140～0147 / No.31ﾌｧｲﾙ名･･･EM0260～0267     No.46ﾌｧｲﾙ名･･･EM0380～0387
LD W162.06
OR W162.07
AND W161.01
OUT TR0
@XFERC(565) #8 D91 D780
@EMBC(281) &0
LD W110.01
OR W110.02
ANDLD
@XFERC(565) #8 D780 E20
LD TR0
LD W110.05
OR W110.06
ANDLD
@XFERC(565) #8 D780 E140
LD TR0
LD W110.09
OR W110.10
ANDLD
@XFERC(565) #8 D780 E260
LD TR0
LD W110.13
OR W110.14
ANDLD
@XFERC(565) #8 D780 E380
; rung 111: No.2ﾌｧｲﾙ名変更 / No.2 ﾌｧｲﾙ名･･･EM0028～0035     No.17ﾌｧｲﾙ名･･･EM0148～0155 / No.32ﾌｧｲﾙ名･･･EM0268～0275     No.47ﾌｧｲﾙ名･･･EM0388～0395
LD W162.06
OR W162.07
AND W161.02
OUT TR0
@XFERC(565) #8 D91 D788
@EMBC(281) &0
LD W110.01
OR W110.02
ANDLD
@XFERC(565) #8 D788 E28
LD TR0
LD W110.05
OR W110.06
ANDLD
@XFERC(565) #8 D788 E148
LD TR0
LD W110.09
OR W110.10
ANDLD
@XFERC(565) #8 D788 E268
LD TR0
LD W110.13
OR W110.14
ANDLD
@XFERC(565) #8 D788 E388

; rung 112: No.3ﾌｧｲﾙ名変更 / No.3 ﾌｧｲﾙ名･･･EM0036～0043     No.18ﾌｧｲﾙ名･･･EM0156～0163 / No.33ﾌｧｲﾙ名･･･EM0276～0283     No.48ﾌｧｲﾙ名･･･EM0396～0403
LD W162.06
OR W162.07
AND W161.03
OUT TR0
@XFERC(565) #8 D91 D796
@EMBC(281) &0
LD W110.01
OR W110.02
ANDLD
@XFERC(565) #8 D796 E36
LD TR0
LD W110.05
OR W110.06
ANDLD
@XFERC(565) #8 D796 E156
LD TR0
LD W110.09
OR W110.10
ANDLD
@XFERC(565) #8 D796 E276
LD TR0
LD W110.13
OR W110.14
ANDLD
@XFERC(565) #8 D796 E396
; rung 113: No.4ﾌｧｲﾙ名変更 / No.4 ﾌｧｲﾙ名･･･EM0044～0051     No.19ﾌｧｲﾙ名･･･EM0164～0171 / No.34ﾌｧｲﾙ名･･･EM0284～0291     No.49ﾌｧｲﾙ名･･･EM0404～0411
LD W162.06
OR W162.07
AND W161.04
OUT TR0
@XFERC(565) #8 D91 D804
@EMBC(281) &0
LD W110.01
OR W110.02
ANDLD
@XFERC(565) #8 D804 E44
LD TR0
LD W110.05
OR W110.06
ANDLD
@XFERC(565) #8 D804 E164
LD TR0
LD W110.09
OR W110.10
ANDLD
@XFERC(565) #8 D804 E284
LD TR0
LD W110.13
OR W110.14
ANDLD
@XFERC(565) #8 D804 E404

; rung 114: No.5ﾌｧｲﾙ名変更 / No.5 ﾌｧｲﾙ名･･･EM0052～0059     No.20ﾌｧｲﾙ名･･･EM0172～0179 / No.35ﾌｧｲﾙ名･･･EM0292～0299     No.50ﾌｧｲﾙ名･･･EM0412～0419
LD W162.06
OR W162.07
AND W161.05
OUT TR0
@XFERC(565) #8 D91 D812
@EMBC(281) &0
LD W110.01
OR W110.02
ANDLD
@XFERC(565) #8 D812 E52
LD TR0
LD W110.05
OR W110.06
ANDLD
@XFERC(565) #8 D812 E172
LD TR0
LD W110.09
OR W110.10
ANDLD
@XFERC(565) #8 D812 E292
LD TR0
LD W110.13
OR W110.14
ANDLD
@XFERC(565) #8 D812 E412
; rung 115: No.6ﾌｧｲﾙ名変更 / No.6 ﾌｧｲﾙ名･･･EM0060～0067     No.21ﾌｧｲﾙ名･･･EM0180～0187 / No.36ﾌｧｲﾙ名･･･EM0300～0307     No.51ﾌｧｲﾙ名･･･EM0420～0427
LD W162.06
OR W162.07
AND W161.06
OUT TR0
@XFERC(565) #8 D91 D820
@EMBC(281) &0
LD W110.01
OR W110.02
ANDLD
@XFERC(565) #8 D820 E60
LD TR0
LD W110.05
OR W110.06
ANDLD
@XFERC(565) #8 D820 E180
LD TR0
LD W110.09
OR W110.10
ANDLD
@XFERC(565) #8 D820 E300
LD TR0
LD W110.13
OR W110.14
ANDLD
@XFERC(565) #8 D820 E420

; rung 116: No.7ﾌｧｲﾙ名変更 / No.7 ﾌｧｲﾙ名･･･EM0068～0075     No.22ﾌｧｲﾙ名･･･EM0188～0195 / No.37ﾌｧｲﾙ名･･･EM0308～0315     No.52ﾌｧｲﾙ名･･･EM0428～0435
LD W162.06
OR W162.07
AND W161.07
OUT TR0
@XFERC(565) #8 D91 D828
@EMBC(281) &0
LD W110.01
OR W110.02
ANDLD
@XFERC(565) #8 D828 E68
LD TR0
LD W110.05
OR W110.06
ANDLD
@XFERC(565) #8 D828 E188
LD TR0
LD W110.09
OR W110.10
ANDLD
@XFERC(565) #8 D828 E308
LD TR0
LD W110.13
OR W110.14
ANDLD
@XFERC(565) #8 D828 E428
; rung 117: No.8ﾌｧｲﾙ名変更 / No.8 ﾌｧｲﾙ名･･･EM0076～0083     No.23ﾌｧｲﾙ名･･･EM0196～0203 / No.38ﾌｧｲﾙ名･･･EM0316～0323     No.53ﾌｧｲﾙ名･･･EM0436～0443
LD W162.06
OR W162.07
AND W161.08
OUT TR0
@XFERC(565) #8 D91 D836
@EMBC(281) &0
LD W110.01
OR W110.02
ANDLD
@XFERC(565) #8 D836 E76
LD TR0
LD W110.05
OR W110.06
ANDLD
@XFERC(565) #8 D836 E196
LD TR0
LD W110.09
OR W110.10
ANDLD
@XFERC(565) #8 D836 E316
LD TR0
LD W110.13
OR W110.14
ANDLD
@XFERC(565) #8 D836 E436

; rung 118: No.9ﾌｧｲﾙ名変更 / No.9 ﾌｧｲﾙ名･･･EM0084～0091     No.24ﾌｧｲﾙ名･･･EM0204～0211 / No.39ﾌｧｲﾙ名･･･EM0324～0331     No.54ﾌｧｲﾙ名･･･EM0444～0451
LD W162.06
OR W162.07
AND W161.09
OUT TR0
@XFERC(565) #8 D91 D844
@EMBC(281) &0
LD W110.01
OR W110.02
ANDLD
@XFERC(565) #8 D844 E84
LD TR0
LD W110.05
OR W110.06
ANDLD
@XFERC(565) #8 D844 E204
LD TR0
LD W110.09
OR W110.10
ANDLD
@XFERC(565) #8 D844 E324
LD TR0
LD W110.13
OR W110.14
ANDLD
@XFERC(565) #8 D844 E444
; rung 119: No.10ﾌｧｲﾙ名変更 / No.10ﾌｧｲﾙ名･･･EM0092～0099     No.25ﾌｧｲﾙ名･･･EM0212～0219 / No.40ﾌｧｲﾙ名･･･EM0332～0339     No.55ﾌｧｲﾙ名･･･EM0452～0459
LD W162.06
OR W162.07
AND W161.10
OUT TR0
@XFERC(565) #8 D91 D852
@EMBC(281) &0
LD W110.01
OR W110.02
ANDLD
@XFERC(565) #8 D852 E92
LD TR0
LD W110.05
OR W110.06
ANDLD
@XFERC(565) #8 D852 E212
LD TR0
LD W110.09
OR W110.10
ANDLD
@XFERC(565) #8 D852 E332
LD TR0
LD W110.13
OR W110.14
ANDLD
@XFERC(565) #8 D852 E452

; rung 120: No.11ﾌｧｲﾙ名変更 / No.11ﾌｧｲﾙ名･･･EM0100～0107     No.26ﾌｧｲﾙ名･･･EM0220～0227 / No.41ﾌｧｲﾙ名･･･EM0340～0347     No.56ﾌｧｲﾙ名･･･EM0460～0467
LD W162.06
OR W162.07
AND W161.11
OUT TR0
@XFERC(565) #8 D91 D860
@EMBC(281) &0
LD W110.01
OR W110.02
ANDLD
@XFERC(565) #8 D860 E100
LD TR0
LD W110.05
OR W110.06
ANDLD
@XFERC(565) #8 D860 E220
LD TR0
LD W110.09
OR W110.10
ANDLD
@XFERC(565) #8 D860 E340
LD TR0
LD W110.13
OR W110.14
ANDLD
@XFERC(565) #8 D860 E460
; rung 121: No.12ﾌｧｲﾙ名変更 / No.12ﾌｧｲﾙ名･･･EM0108～0115     No.27ﾌｧｲﾙ名･･･EM0228～0235 / No.42ﾌｧｲﾙ名･･･EM0348～0355     No.57ﾌｧｲﾙ名･･･EM0468～0475
LD W162.06
OR W162.07
AND W161.12
OUT TR0
@XFERC(565) #8 D91 D868
@EMBC(281) &0
LD W110.01
OR W110.02
ANDLD
@XFERC(565) #8 D868 E108
LD TR0
LD W110.05
OR W110.06
ANDLD
@XFERC(565) #8 D868 E228
LD TR0
LD W110.09
OR W110.10
ANDLD
@XFERC(565) #8 D868 E348
LD TR0
LD W110.13
OR W110.14
ANDLD
@XFERC(565) #8 D868 E468

; rung 122: No.13ﾌｧｲﾙ名変更 / No.13ﾌｧｲﾙ名･･･EM0116～0123     No.28ﾌｧｲﾙ名･･･EM0236～0243 / No.43ﾌｧｲﾙ名･･･EM0356～0363     No.58ﾌｧｲﾙ名･･･EM0476～0483
LD W162.06
OR W162.07
AND W161.13
OUT TR0
@XFERC(565) #8 D91 D876
@EMBC(281) &0
LD W110.01
OR W110.02
ANDLD
@XFERC(565) #8 D876 E116
LD TR0
LD W110.05
OR W110.06
ANDLD
@XFERC(565) #8 D876 E236
LD TR0
LD W110.09
OR W110.10
ANDLD
@XFERC(565) #8 D876 E356
LD TR0
LD W110.13
OR W110.14
ANDLD
@XFERC(565) #8 D876 E476
; rung 123: No.14ﾌｧｲﾙ名変更 / No.14ﾌｧｲﾙ名･･･EM0124～0131     No.29ﾌｧｲﾙ名･･･EM0244～0251 / No.44ﾌｧｲﾙ名･･･EM0364～0371     No.59ﾌｧｲﾙ名･･･EM0484～0491
LD W162.06
OR W162.07
AND W161.14
OUT TR0
@XFERC(565) #8 D91 D884
@EMBC(281) &0
LD W110.01
OR W110.02
ANDLD
@XFERC(565) #8 D884 E124
LD TR0
LD W110.05
OR W110.06
ANDLD
@XFERC(565) #8 D884 E244
LD TR0
LD W110.09
OR W110.10
ANDLD
@XFERC(565) #8 D884 E364
LD TR0
LD W110.13
OR W110.14
ANDLD
@XFERC(565) #8 D884 E484

; rung 124: No.15ﾌｧｲﾙ名変更 / No.15ﾌｧｲﾙ名･･･EM0132～0139     No.30ﾌｧｲﾙ名･･･EM0252～0259 / No.45ﾌｧｲﾙ名･･･EM0372～0379     No.60ﾌｧｲﾙ名･･･EM0492～0499
LD W162.06
OR W162.07
AND W161.15
OUT TR0
@XFERC(565) #8 D91 D892
@EMBC(281) &0
LD W110.01
OR W110.02
ANDLD
@XFERC(565) #8 D892 E132
LD TR0
LD W110.05
OR W110.06
ANDLD
@XFERC(565) #8 D892 E252
LD TR0
LD W110.09
OR W110.10
ANDLD
@XFERC(565) #8 D892 E372
LD TR0
LD W110.13
OR W110.14
ANDLD
@XFERC(565) #8 D892 E492
; rung 125: ----- ﾌｧｲﾙ名変更時現在の成形ﾌｧｲﾙ名変更 ----- / ﾌｧｲﾙ名変更時、現在表示されているﾌｧｲﾙ名を変更した場合は、現在ﾌｧｲﾙ名も変更する
LD W110.01
OR W110.05
OR W110.09
OR W110.13
AND W162.06
CMP(020) D760 D762
AND P_EQ
@XFERC(565) #8 D771 D763
; rung 126
LD P_On
MOV(021) 441 D990
MOV(021) 469 D992
MOV(021) 412 D994
; rung 127
LD 462.00
AND=(300) D990 D992
AND=(300) D994 D760
OUTNOT 421.15

; rung 128: ----- ﾃﾞｰﾀ登録・読出時、現在の成形ﾌｧｲﾙ名を変更 -----
LD W506.00
LD W110.02
OR W110.06
OR W110.10
OR W110.14
AND W162.07
ORLD
OUT W111.09
; rung 129
LD W111.09
@MOV(021) D762 D760
@XFERC(565) #8 D91 D763
; rung 130
LD W506.01
LD W110.03
OR W110.07
OR W110.11
OR W110.15
AND W162.08
AND W162.10
ORLD
OUT TR0
@MOV(021) D762 D760
AND W111.00
@XFERC(565) #8 D771 D763
LD TR0
ANDNOT W111.00
@XFERC(565) #8 D91 D763

; rung 131: ----- 各設定をEM1000～1399に仮配置し 400毎にEMへ格納(読出) -----
LD W111.09
@XFER(070) &10 D3650 E0_1000  // ﾀｲﾏ1設定 DM3650～3659/EM1000～1009
@XFER(070) &18 D3700 E0_1010  // ﾀｲﾏ2設定 DM3700～3717/EM1010～1027
@MOV(021) D2739 E0_1028  // ショット重量 DM2739/EM1028
@MOV(021) D2754 E0_1029  // ショット時間 DM2754/EM1029
@XFER(070) &6 D3400 E0_1030  // 層構成比 DM3400～3405/EM1030～1035
; rung 132
LD W111.09
@XFER(070) &12 D3200 E0_1036  // 補正係数設定 DM3200～3211/EM1036～1047
@XFER(070) &6 D3394 E0_1048  // 原料密度設定 DM3394～3399/EM1048～1053
@MOV(021) H2 E0_1054  // 動作選択 HR02/EM1054
; rung 133
LD W111.09
@XFER(070) &28 D19510 E0_1055  // HFU0 成形温度1
@XFER(070) &26 D18710 E0_1083  // HFU1 成形温度1
@MOV(021) D18736 E0_1109  // HFU0_17_4 ﾘﾝｸﾞ温度設定

; rung 134
LD W111.09
@XFER(070) &28 D17400 E0_1110  // HFU0 成形温度2
@XFER(070) &26 D17430 E0_1138  // HFU1 成形温度2
; rung 135
LD W111.09
@MOV(021) H90 E0_1167  // 個別ﾛｽｲﾝ選択 HR90/EM1167
@XFER(070) &96 D2780 E0_1168  // 押出機能力 DM2780～2875/EM1168～1263
; rung 136: 以下ｼｬｯﾄﾀﾞｳﾝ設定及びｽﾀｰﾄｱｯﾌﾟ設定
LD W111.09
@XFER(070) &8 D2910 E0_1264
@MOV(021) D2919 E0_1272
@XFER(070) &12 D3442 E0_1273
@XFER(070) &4 D2776 E0_1285
@XFER(070) &2 D348 E0_1289
@MOV(021) D280 E0_1291
@MOV(021) D282 E0_1292
@XFER(070) &9 D3738 E0_1293

; rung 137
LD W111.09
@MOV(021) D286 E0_1302
@MOV(021) D288 E0_1303
@XFER(070) &10 D5990 E0_1304
@XFER(070) &21 D3610 E0_1314
@XFER(070) &16 D660 E0_1335
@XFER(070) &2 D3631 E0_1351
; rung 138: ----- ﾃﾞｰﾀをEMのどこに格納するか設定 -----
LD W162.07
OR W162.08
OR W506.00
OR W506.01
OUT W111.10

; rung 139: ----- ﾃﾞｰﾀをEMのどこに格納するか設定 ----- / ﾌｧｲﾙ１画面
LD W162.07
OR W506.00
AND W110.02
OUT TR0
AND W161.01
XFER(070) &400 E0_1000 E1_0
LD TR0
AND W161.02
XFER(070) &400 E0_1000 E1_400
LD TR0
AND W161.03
XFER(070) &400 E0_1000 E1_800
LD TR0
AND W161.04
XFER(070) &400 E0_1000 E1_1200
LD TR0
AND W161.05
XFER(070) &400 E0_1000 E1_1600
LD TR0
AND W161.06
XFER(070) &400 E0_1000 E1_2000
LD TR0
AND W161.07
XFER(070) &400 E0_1000 E1_2400
LD TR0
AND W161.08
XFER(070) &400 E0_1000 E1_2800
LD TR0
AND W161.09
XFER(070) &400 E0_1000 E1_3200
LD TR0
AND W161.10
XFER(070) &400 E0_1000 E1_3600

; rung 140
LD W162.07
OR W506.00
AND W110.02
OUT TR0
AND W161.11
XFER(070) &400 E0_1000 E1_4000
LD TR0
AND W161.12
XFER(070) &400 E0_1000 E1_4400
LD TR0
AND W161.13
XFER(070) &400 E0_1000 E1_4800
LD TR0
AND W161.14
XFER(070) &400 E0_1000 E1_5200
LD TR0
AND W161.15
XFER(070) &400 E0_1000 E1_5600

; rung 141: ﾌｧｲﾙ２画面
LD W162.07
OR W506.00
AND W110.06
OUT TR0
AND W161.01
XFER(070) &400 E0_1000 E2_0
LD TR0
AND W161.02
XFER(070) &400 E0_1000 E2_400
LD TR0
AND W161.03
XFER(070) &400 E0_1000 E2_800
LD TR0
AND W161.04
XFER(070) &400 E0_1000 E2_1200
LD TR0
AND W161.05
XFER(070) &400 E0_1000 E2_1600
LD TR0
AND W161.06
XFER(070) &400 E0_1000 E2_2000
LD TR0
AND W161.07
XFER(070) &400 E0_1000 E2_2400
LD TR0
AND W161.08
XFER(070) &400 E0_1000 E2_2800
LD TR0
AND W161.09
XFER(070) &400 E0_1000 E2_3200
LD TR0
AND W161.10
XFER(070) &400 E0_1000 E2_3600

; rung 142
LD W162.07
OR W506.00
AND W110.06
OUT TR0
AND W161.11
XFER(070) &400 E0_1000 E2_4000
LD TR0
AND W161.12
XFER(070) &400 E0_1000 E2_4400
LD TR0
AND W161.13
XFER(070) &400 E0_1000 E2_4800
LD TR0
AND W161.14
XFER(070) &400 E0_1000 E2_5200
LD TR0
AND W161.15
XFER(070) &400 E0_1000 E2_5600

; rung 143: ﾌｧｲﾙ３画面
LD W162.07
OR W506.00
AND W110.10
OUT TR0
AND W161.01
XFER(070) &400 E0_1000 E3_0
LD TR0
AND W161.02
XFER(070) &400 E0_1000 E3_400
LD TR0
AND W161.03
XFER(070) &400 E0_1000 E3_800
LD TR0
AND W161.04
XFER(070) &400 E0_1000 E3_1200
LD TR0
AND W161.05
XFER(070) &400 E0_1000 E3_1600
LD TR0
AND W161.06
XFER(070) &400 E0_1000 E3_2000
LD TR0
AND W161.07
XFER(070) &400 E0_1000 E3_2400
LD TR0
AND W161.08
XFER(070) &400 E0_1000 E3_2800
LD TR0
AND W161.09
XFER(070) &400 E0_1000 E3_3200
LD TR0
AND W161.10
XFER(070) &400 E0_1000 E3_3600

; rung 144
LD W162.07
OR W506.00
AND W110.10
OUT TR0
AND W161.11
XFER(070) &400 E0_1000 E3_4000
LD TR0
AND W161.12
XFER(070) &400 E0_1000 E3_4400
LD TR0
AND W161.13
XFER(070) &400 E0_1000 E3_4800
LD TR0
AND W161.14
XFER(070) &400 E0_1000 E3_5200
LD TR0
AND W161.15
XFER(070) &400 E0_1000 E3_5600

; rung 145: ﾌｧｲﾙ４画面
LD W162.07
OR W506.00
AND W110.14
OUT TR0
AND W161.01
XFER(070) &400 E0_1000 E4_0
LD TR0
AND W161.02
XFER(070) &400 E0_1000 E4_400
LD TR0
AND W161.03
XFER(070) &400 E0_1000 E4_800
LD TR0
AND W161.04
XFER(070) &400 E0_1000 E4_1200
LD TR0
AND W161.05
XFER(070) &400 E0_1000 E4_1600
LD TR0
AND W161.06
XFER(070) &400 E0_1000 E4_2000
LD TR0
AND W161.07
XFER(070) &400 E0_1000 E4_2400
LD TR0
AND W161.08
XFER(070) &400 E0_1000 E4_2800
LD TR0
AND W161.09
XFER(070) &400 E0_1000 E4_3200
LD TR0
AND W161.10
XFER(070) &400 E0_1000 E4_3600

; rung 146
LD W162.07
OR W506.00
AND W110.14
OUT TR0
AND W161.11
XFER(070) &400 E0_1000 E4_4000
LD TR0
AND W161.12
XFER(070) &400 E0_1000 E4_4400
LD TR0
AND W161.13
XFER(070) &400 E0_1000 E4_4800
LD TR0
AND W161.14
XFER(070) &400 E0_1000 E4_5200
LD TR0
AND W161.15
XFER(070) &400 E0_1000 E4_5600

; rung 147: ----- 格納ﾃﾞｰﾀをEMに一時格納する ----- / ﾌｧｲﾙ１画面
LD W111.00
AND W162.08
OR W506.01
AND W110.03
OUT TR0
AND W161.01
XFER(070) &400 E1_0 E0_1000
LD TR0
AND W161.02
XFER(070) &400 E1_400 E0_1000
LD TR0
AND W161.03
XFER(070) &400 E1_800 E0_1000
LD TR0
AND W161.04
XFER(070) &400 E1_1200 E0_1000
LD TR0
AND W161.05
XFER(070) &400 E1_1600 E0_1000
LD TR0
AND W161.06
XFER(070) &400 E1_2000 E0_1000
LD TR0
AND W161.07
XFER(070) &400 E1_2400 E0_1000
LD TR0
AND W161.08
XFER(070) &400 E1_2800 E0_1000
LD TR0
AND W161.09
XFER(070) &400 E1_3200 E0_1000
LD TR0
AND W161.10
XFER(070) &400 E1_3600 E0_1000

; rung 148
LD W111.00
AND W162.08
OR W506.01
AND W110.03
OUT TR0
AND W161.11
XFER(070) &400 E1_4000 E0_1000
LD TR0
AND W161.12
XFER(070) &400 E1_4400 E0_1000
LD TR0
AND W161.13
XFER(070) &400 E1_4800 E0_1000
LD TR0
AND W161.14
XFER(070) &400 E1_5200 E0_1000
LD TR0
AND W161.15
XFER(070) &400 E1_5600 E0_1000

; rung 149: ﾌｧｲﾙ２画面
LD W111.00
AND W162.08
OR W506.01
AND W110.07
OUT TR0
AND W161.01
XFER(070) &400 E2_0 E0_1000
LD TR0
AND W161.02
XFER(070) &400 E2_400 E0_1000
LD TR0
AND W161.03
XFER(070) &400 E2_800 E0_1000
LD TR0
AND W161.04
XFER(070) &400 E2_1200 E0_1000
LD TR0
AND W161.05
XFER(070) &400 E2_1600 E0_1000
LD TR0
AND W161.06
XFER(070) &400 E2_2000 E0_1000
LD TR0
AND W161.07
XFER(070) &400 E2_2400 E0_1000
LD TR0
AND W161.08
XFER(070) &400 E2_2800 E0_1000
LD TR0
AND W161.09
XFER(070) &400 E2_3200 E0_1000
LD TR0
AND W161.10
XFER(070) &400 E2_3600 E0_1000

; rung 150
LD W111.00
AND W162.08
OR W506.01
AND W110.07
OUT TR0
AND W161.11
XFER(070) &400 E2_4000 E0_1000
LD TR0
AND W161.12
XFER(070) &400 E2_4400 E0_1000
LD TR0
AND W161.13
XFER(070) &400 E2_4800 E0_1000
LD TR0
AND W161.14
XFER(070) &400 E2_5200 E0_1000
LD TR0
AND W161.15
XFER(070) &400 E2_5600 E0_1000

; rung 151: ﾌｧｲﾙ３画面
LD W111.00
AND W162.08
OR W506.01
AND W110.11
OUT TR0
AND W161.01
XFER(070) &400 E3_0 E0_1000
LD TR0
AND W161.02
XFER(070) &400 E3_400 E0_1000
LD TR0
AND W161.03
XFER(070) &400 E3_800 E0_1000
LD TR0
AND W161.04
XFER(070) &400 E3_1200 E0_1000
LD TR0
AND W161.05
XFER(070) &400 E3_1600 E0_1000
LD TR0
AND W161.06
XFER(070) &400 E3_2000 E0_1000
LD TR0
AND W161.07
XFER(070) &400 E3_2400 E0_1000
LD TR0
AND W161.08
XFER(070) &400 E3_2800 E0_1000
LD TR0
AND W161.09
XFER(070) &400 E3_3200 E0_1000
LD TR0
AND W161.10
XFER(070) &400 E3_3600 E0_1000

; rung 152
LD W111.00
AND W162.08
OR W506.01
AND W110.11
OUT TR0
AND W161.11
XFER(070) &400 E3_4000 E0_1000
LD TR0
AND W161.12
XFER(070) &400 E3_4400 E0_1000
LD TR0
AND W161.13
XFER(070) &400 E3_4800 E0_1000
LD TR0
AND W161.14
XFER(070) &400 E3_5200 E0_1000
LD TR0
AND W161.15
XFER(070) &400 E3_5600 E0_1000

; rung 153: ﾌｧｲﾙ４画面
LD W111.00
AND W162.08
OR W506.01
AND W110.15
OUT TR0
AND W161.01
XFER(070) &400 E4_0 E0_1000
LD TR0
AND W161.02
XFER(070) &400 E4_400 E0_1000
LD TR0
AND W161.03
XFER(070) &400 E4_800 E0_1000
LD TR0
AND W161.04
XFER(070) &400 E4_1200 E0_1000
LD TR0
AND W161.05
XFER(070) &400 E4_1600 E0_1000
LD TR0
AND W161.06
XFER(070) &400 E4_2000 E0_1000
LD TR0
AND W161.07
XFER(070) &400 E4_2400 E0_1000
LD TR0
AND W161.08
XFER(070) &400 E4_2800 E0_1000
LD TR0
AND W161.09
XFER(070) &400 E4_3200 E0_1000
LD TR0
AND W161.10
XFER(070) &400 E4_3600 E0_1000

; rung 154
LD W111.00
AND W162.08
OR W506.01
AND W110.15
OUT TR0
AND W161.11
XFER(070) &400 E4_4000 E0_1000
LD TR0
AND W161.12
XFER(070) &400 E4_4400 E0_1000
LD TR0
AND W161.13
XFER(070) &400 E4_4800 E0_1000
LD TR0
AND W161.14
XFER(070) &400 E4_5200 E0_1000
LD TR0
AND W161.15
XFER(070) &400 E4_5600 E0_1000
; rung 155: ----- データ読出処理 -----
LD W506.01
LD W110.03
OR W110.07
OR W110.11
OR W110.15
AND W162.08
ORLD
AND W162.10
OUT W111.11

; rung 156: ----- 各DMへﾃﾞｰﾀを展開 -----
LD W111.11
@XFER(070) &10 E0_1000 D3650
@XFER(070) &18 E0_1010 D3700
@MOV(021) E0_1028 D2739
@MOV(021) E0_1029 D2754
@XFER(070) &6 E0_1030 D3400
; rung 157
LD W111.11
@XFER(070) &12 E0_1036 D3200
@XFER(070) &6 E0_1048 D3394
@MOV(021) E0_1054 H2
; rung 158
LD W111.11
@XFER(070) &28 E0_1055 D19510  // HFU0 成形温度1
@XFER(070) &26 E0_1083 D18710  // HFU1 成形温度1
@MOV(021) E0_1109 D18736  // HFU0_17_4 ﾘﾝｸﾞ温度設定

; rung 159
LD W111.11
@XFER(070) &28 E0_1110 D17400  // HFU0 成形温度2
@XFER(070) &26 E0_1138 D17430  // HFU1 成形温度2
; rung 160
LD W111.11
@MOV(021) E0_1167 H90
@XFER(070) &96 E0_1168 D2780
; rung 161
LD W111.11
@XFER(070) &8 E0_1264 D2910
@MOV(021) E0_1272 D2919
@XFER(070) &12 E0_1273 D3442
@XFER(070) &4 E0_1285 D2776
@XFER(070) &2 E0_1289 D348
@MOV(021) E0_1291 D280
@MOV(021) E0_1292 D282
@XFER(070) &9 E0_1293 D3738

; rung 162
LD W111.11
@MOV(021) E1302 D286
@MOV(021) E1303 D288
@XFER(070) &10 E0_1304 D5990
@XFER(070) &21 E0_1314 D3610
@XFER(070) &16 E0_1335 D660
@XFER(070) &2 E0_1351 D3631
; rung 163
LD W111.11
CMP(020) W161 #0
AND P_GT
DIFD(014) W163.12
; rung 164
LD W163.12
OR W163.13
ANDNOT T0153
OUT W163.13
TIM 0153 #2
TIM 0152 #2
; rung 165
LD W506.01
AND W162.10
OR W506.02
OR W506.00
OUT W506.04

### Section LOSSIN

; rung 0: ********** ロスイン制御処理 ********* / ***** 立上時定数初期値設定 *****
LD P_First_Cycle
MOV(021) #5 D190
MOV(021) #0 D191
MOV(021) #50 D192
MOV(021) #0 D193
; rung 1
LD P_First_Cycle
MOV(021) #1 D194
MOV(021) #360 D196
MOV(021) #3600 D198
MOV(021) #0 D199
MOV(021) #500 D200
MOV(021) #0 D201
; rung 2
LD P_First_Cycle
MOV(021) #10 D188
MOV(021) #0 D189
MOV(021) #2000 D186
MOV(021) #0 D187

; rung 3: ----- MAX & MIN 命令ｺﾝﾄﾛｰﾙﾃﾞｰﾀ -----
LD P_On
MOV(021) #A D7000
MOV(021) #4000 D7001
MOV(021) #5 D7038
MOV(021) #4000 D7039
; rung 4: ***** ｵｰﾄﾛｰﾀﾞ(原料供給装置)ｲﾝﾀｰﾛｯｸ ***** / ｵｰﾄﾛｰﾀﾞの輸送ﾌﾞﾛﾜは押出機起動に関係無く、電源入で供給装置入になっているとONする
LD T0511
OUT TR0
ANDNOT W396.06
AND H2.00
ANDNOT W53.00
OUT W121.00
LD TR0
ANDNOT W396.07
AND H2.01
ANDNOT W53.01
OUT W126.00
LD TR0
ANDNOT W396.08
AND H2.02
ANDNOT W53.02
OUT W131.00
LD TR0
ANDNOT W396.09
AND H2.03
ANDNOT W53.03
OUT W136.00
LD TR0
ANDNOT W396.10
AND H2.04
ANDNOT W53.05
OUT W141.00
LD TR0
ANDNOT W396.11
AND H2.05
ANDNOT W53.04
OUT W146.00
; rung 5: '***** ﾛｰﾄﾞｾﾙのDATA要求は常時ON *****
LD P_On
OUT 11.06
OUT 11.07
OUT 11.08
OUT 11.09
OUT 11.10
OUT 11.11
; rung 6: ***** 各層ﾎｯﾊﾟ重量値(BCD) ***** / ﾃﾞｰﾀ取込はﾛｰﾄﾞｾﾙのﾃﾞｰﾀ確定信号ONしてから取込 / 主内・粉砕・主外---00.00kg ﾊﾞﾘﾔ・接内・接外---0.000kg / ----- 主内ﾛｰﾄﾞｾﾙ値判別 -----
LD 11.06
AND 36.01
MOV(021) 30 W120

; rung 7
LD 11.07
AND 36.04
MOV(021) 31 W125
; rung 8
LD 11.08
AND 36.07
MOV(021) 32 W130
; rung 9
LD 11.09
AND 36.10
MOV(021) 33 W135
; rung 10
LD 11.10
AND 36.13
MOV(021) 34 W140
; rung 11
LD 11.11
AND 37.00
MOV(021) 35 W145
; rung 12: ***** ﾛｰﾄﾞｾﾙﾒｰﾀ上下限値到達判別 ***** / 型式違うﾛｰﾄﾞｾﾙﾒｰﾀを使用したのでHH,H,L,LLの信号をﾌﾟﾛｸﾞﾗﾑで判別
LD P_On
OUT TR0
AND>=(325) W120 D690
TIM 0100 #5
LD TR0
AND>=(325) W120 D691
TIM 0101 #5
; rung 13
LD T0100
OUT W84.00
; rung 14
LD T0101
OUT W84.01
; rung 15
LD P_On
OUT TR0
AND<=(315) W120 D692
TIM 0102 #5
LD TR0
AND<=(315) W120 D693
TIM 0103 #5

; rung 16
LD T0102
OUT W84.02
; rung 17
LD T0103
OUT W84.03
; rung 18: ----- 粉砕ﾛｰﾄﾞｾﾙ値判別 -----
LD P_On
OUT TR0
AND>=(325) W125 D694
TIM 0104 #5
LD TR0
AND>=(325) W125 D695
TIM 0105 #5
; rung 19
LD T0104
OUT W84.04
; rung 20
LD T0105
OUT W84.05
; rung 21
LD P_On
OUT TR0
AND<=(315) W125 D696
TIM 0106 #5
LD TR0
AND<=(315) W125 D697
TIM 0107 #5
; rung 22
LD T0106
OUT W84.06
; rung 23
LD T0107
OUT W84.07
; rung 24: ----- 主外ﾛｰﾄﾞｾﾙ値判別 -----
LD P_On
OUT TR0
AND>=(325) W130 D698
TIM 0108 #5
LD TR0
AND>=(325) W130 D699
TIM 0109 #5

; rung 25
LD T0108
OUT W84.08
; rung 26
LD T0109
OUT W84.09
; rung 27
LD P_On
OUT TR0
AND<=(315) W130 D700
TIM 0110 #5
LD TR0
AND<=(315) W130 D701
TIM 0111 #5
; rung 28
LD T0110
OUT W84.10
; rung 29
LD T0111
OUT W84.11
; rung 30: ----- ﾊﾞﾘﾔﾛｰﾄﾞｾﾙ値判別 -----
LD P_On
OUT TR0
AND>=(325) W135 D702
TIM 0112 #5
LD TR0
AND>=(325) W135 D703
TIM 0113 #5
; rung 31
LD T0112
OUT W84.12
; rung 32
LD T0113
OUT W84.13
; rung 33
LD P_On
OUT TR0
AND<=(315) W135 D704
TIM 0114 #5
LD TR0
AND<=(315) W135 D705
TIM 0115 #5
; rung 34
LD T0114
OUT W84.14

; rung 35
LD T0115
OUT W84.15
; rung 36: ----- 接内ﾛｰﾄﾞｾﾙ値判別 -----
LD P_On
OUT TR0
AND>=(325) W140 D706
TIM 0116 #5
LD TR0
AND>=(325) W140 D707
TIM 0117 #5
; rung 37
LD T0116
OUT W85.00
; rung 38
LD T0117
OUT W85.01
; rung 39
LD P_On
OUT TR0
AND<=(315) W140 D708
TIM 0118 #5
LD TR0
AND<=(315) W140 D709
TIM 0119 #5
; rung 40
LD T0118
OUT W85.02
; rung 41
LD T0119
OUT W85.03
; rung 42: ----- 接外ﾛｰﾄﾞｾﾙ値判別 -----
LD P_On
OUT TR0
AND>=(325) W145 D710
TIM 0120 #5
LD TR0
AND>=(325) W145 D711
TIM 0121 #5
; rung 43
LD T0120
OUT W85.04

; rung 44
LD T0121
OUT W85.05
; rung 45
LD P_On
OUT TR0
AND<=(315) W145 D712
TIM 0122 #5
LD TR0
AND<=(315) W145 D713
TIM 0123 #5
; rung 46
LD T0122
OUT W85.06
; rung 47
LD T0123
OUT W85.07
; rung 48: ***** 手動画面(NO.41)から外れた場合SWを強制OFF *****
LD W379.02
AND W378.09
ANDNOT W509.15
OUT W116.06
; rung 49
LDNOT W116.06
MOV(021) #0 H3
MOV(021) #0 H4
; rung 50: ***** 各層ﾛｽｲﾝ切のﾗﾝﾌﾟ表示 ***** / 各層ﾛｽｲﾝ入切は画面でｾｯﾄ/ﾘｾｯﾄSWを使用している
LDNOT H90.00
OUT W119.02
; rung 51
LDNOT H90.01
OUT W119.03
; rung 52
LDNOT H90.02
OUT W119.04
; rung 53
LDNOT H90.03
OUT W119.05
; rung 54
LDNOT H90.04
OUT W119.06

; rung 55
LDNOT H90.05
OUT W119.07
; rung 56: ***** 計測時間より計測回数割出 ***** / 画面43に計測時間設定あり。3600sec÷設定値＝単位時間計測回数
LDNOT W509.15
AND W379.02
AND W378.11
OUT W116.07
; rung 57
LD W116.07
MOV(021) D350 D204
SRD(075) D204 D204
/B(434) #3600 D204 D205
MOV(021) D205 D356
; rung 58
LD W116.07
MOV(021) D351 D207
SRD(075) D207 D207
/B(434) #3600 D207 D208
MOV(021) D208 D357

; rung 59
LD W116.07
MOV(021) D352 D210
SRD(075) D210 D210
/B(434) #3600 D210 D211
MOV(021) D211 D358
; rung 60
LD W116.07
MOV(021) D353 D213
SRD(075) D213 D213
/B(434) #3600 D213 D214
MOV(021) D214 D359
; rung 61
LD W116.07
MOV(021) D354 D216
SRD(075) D216 D216
/B(434) #3600 D216 D217
MOV(021) D217 D360

; rung 62
LD W116.07
MOV(021) D355 D219
SRD(075) D219 D219
/B(434) #3600 D219 D220
MOV(021) D220 D361
; rung 63: ***** 各層計測信号判別 *****
LD W204.06
AND 420.00
OUT W115.00
TIM 0310 #10
DIFU(013) W121.01
; rung 64
LD T0310
DIFU(013) W115.06
; rung 65
LD W204.06
AND 420.01
OUT W115.01
TIM 0311 #10
DIFU(013) W126.01
; rung 66
LD T0311
DIFU(013) W115.07
; rung 67
LD W204.06
AND 420.02
OUT W115.02
TIM 0312 #10
DIFU(013) W131.01

; rung 68
LD T0312
DIFU(013) W115.08
; rung 69
LD W204.06
AND 420.03
OUT W115.03
TIM 0313 #10
DIFU(013) W136.01
; rung 70
LD T0313
DIFU(013) W115.09
; rung 71
LD W204.06
AND 420.04
OUT W115.04
TIM 0314 #10
DIFU(013) W141.01
; rung 72
LD T0314
DIFU(013) W115.10
; rung 73
LD W204.06
AND 420.05
OUT W115.05
TIM 0315 #10
DIFU(013) W146.01
; rung 74
LD T0315
DIFU(013) W115.11
; rung 75: ***** 計測開始で押出機に設定しているDAの出力回転数(BCD)を取込 *****
LD W115.00
MOV(021) D3435 D34
; rung 76
LDNOT W115.00
MOV(021) #0 D34

; rung 77
LD W115.01
MOV(021) D3431 D35
; rung 78
LDNOT W115.01
MOV(021) #0 D35
; rung 79
LD W115.02
MOV(021) D3430 D36
; rung 80
LDNOT W115.02
MOV(021) #0 D36
; rung 81
LD W115.03
MOV(021) D3433 D37
; rung 82
LDNOT W115.03
MOV(021) #0 D37
; rung 83
LD W115.04
MOV(021) D3434 D38
; rung 84
LDNOT W115.04
MOV(021) #0 D38
; rung 85
LD W115.05
MOV(021) D3432 D39
; rung 86
LDNOT W115.05
MOV(021) #0 D39

; rung 87: ***** ｽｸﾘｭｰ回転数取込ｻｲｸﾙ作成(0.5secｸﾛｯｸ) *****
LD P_1s
DIFU(013) W115.12
DIFD(014) W115.13
; rung 88
LD W115.12
OR W115.13
OUT W115.14
; rung 89
LD W115.14
OUT TR0
AND W115.00
OUT W116.00
LD TR0
AND W115.01
OUT W116.01
LD TR0
AND W115.02
OUT W116.02
LD TR0
AND W115.03
OUT W116.03
LD TR0
AND W115.04
OUT W116.04
LD TR0
AND W115.05
OUT W116.05
; rung 90: ***** 主材内層動作中ｽｸﾘｭｰ回転数取込 ***** / 0.5sec毎に現在EXT.設定回転数(DM2000)、0.5s前回転数(DM2001)、1s前回転数を取り込む
LD W116.00
MOV(021) D2001 D2002
MOV(021) D2000 D2001
MOV(021) D34 D2000

; rung 91: 現在の設定回転数と1sec前の設定回転数を比較して#0005以下の時、計測処理し、範囲外の時、計測停止。
LD W116.00
CLC(041)
-BC(416) D34 D2002 D2005
AND P_CY
CLC(041)
-BC(416) #0 D2005 D2005
; rung 92
LD W116.00
OUT TR0
CMP(020) #5 D2005
LD P_EQ
OR P_LT
ANDLD
OUT W121.07
LD TR0
AND P_GT
OUT W121.08
; rung 93
LD W121.08
OR W121.09
ANDNOT W117.15
ANDNOT W121.07
OUT W121.09
DIFU(013) W121.11
; rung 94: 押出機起動中か確認 / 以下信号ﾊﾟｰｼﾞ処理中切れる
LD W115.00
AND 420.00
OUT W121.10
; rung 95: ***** 粉砕材層動作中ｽｸﾘｭｰ回転数取込 *****
LD W116.01
MOV(021) D2101 D2102
MOV(021) D2100 D2101
MOV(021) D35 D2100

; rung 96
LD W116.01
CLC(041)
-BC(416) D35 D2102 D2105
AND P_CY
CLC(041)
-BC(416) #0 D2105 D2105
; rung 97
LD W116.01
OUT TR0
CMP(020) #5 D2105
LD P_EQ
OR P_LT
ANDLD
OUT W126.07
LD TR0
AND P_GT
OUT W126.08
; rung 98
LD W126.08
OR W126.09
ANDNOT W117.15
ANDNOT W126.07
OUT W126.09
DIFU(013) W126.11
; rung 99: 押出機起動中か確認 / 以下信号ﾊﾟｰｼﾞ処理中切れる
LD W115.01
AND 420.01
OUT W126.10
; rung 100: ***** 主材外層動作中ｽｸﾘｭｰ回転数取込 *****
LD W116.02
MOV(021) D2201 D2202
MOV(021) D2200 D2201
MOV(021) D36 D2200

; rung 101
LD W116.02
CLC(041)
-BC(416) D36 D2202 D2205
AND P_CY
CLC(041)
-BC(416) #0 D2205 D2205
; rung 102
LD W116.02
OUT TR0
CMP(020) #5 D2205
LD P_EQ
OR P_LT
ANDLD
OUT W131.07
LD TR0
AND P_GT
OUT W131.08
; rung 103
LD W131.08
OR W131.09
ANDNOT W117.15
ANDNOT W131.07
OUT W131.09
DIFU(013) W131.11
; rung 104: 押出機起動中か確認 / 以下信号ﾊﾟｰｼﾞ処理中切れる
LD W115.02
AND 420.02
OUT W131.10
; rung 105: ***** ﾊﾞﾘﾔ層動作時ｽｸﾘｭｰ回転数取込 *****
LD W116.03
MOV(021) D2301 D2302
MOV(021) D2300 D2301
MOV(021) D37 D2300

; rung 106
LD W116.03
CLC(041)
-BC(416) D37 D2302 D2305
AND P_CY
CLC(041)
-BC(416) #0 D2305 D2305
; rung 107
LD W116.03
OUT TR0
CMP(020) #5 D2305
LD P_EQ
OR P_LT
ANDLD
OUT W136.07
LD TR0
AND P_GT
OUT W136.08
; rung 108
LD W136.08
OR W136.09
ANDNOT W117.15
ANDNOT W136.07
OUT W136.09
DIFU(013) W136.11
; rung 109: 押出機起動中か確認 / 以下信号ﾊﾟｰｼﾞ処理中切れる
LD W115.03
AND 420.03
OUT W136.10
; rung 110: ***** 接着内層動作時ｽｸﾘｭｰ回転数取込 *****
LD W116.04
MOV(021) D2401 D2402
MOV(021) D2400 D2401
MOV(021) D38 D2400

; rung 111
LD W116.04
CLC(041)
-BC(416) D38 D2402 D2405
AND P_CY
CLC(041)
-BC(416) #0 D2405 D2405
; rung 112
LD W116.04
OUT TR0
CMP(020) #5 D2405
LD P_EQ
OR P_LT
ANDLD
OUT W141.07
LD TR0
AND P_GT
OUT W141.08
; rung 113
LD W141.08
OR W141.09
ANDNOT W117.15
ANDNOT W141.07
OUT W141.09
DIFU(013) W141.11
; rung 114: 押出機起動中か確認 / 以下信号ﾊﾟｰｼﾞ処理中切れる
LD W115.04
AND 420.04
OUT W141.10
; rung 115: ***** 接着外層動作中ｽｸﾘｭｳｰ回転数取込 *****
LD W116.05
MOV(021) D2501 D2502
MOV(021) D2500 D2501
MOV(021) D39 D2500

; rung 116
LD W116.05
CLC(041)
-BC(416) D39 D2502 D2505
AND P_CY
CLC(041)
-BC(416) #0 D2505 D2505
; rung 117
LD W116.05
OUT TR0
CMP(020) #5 D2505
LD P_EQ
OR P_LT
ANDLD
OUT W146.07
LD TR0
AND P_GT
OUT W146.08
; rung 118
LD W146.08
OR W146.09
ANDNOT W117.15
ANDNOT W146.07
OUT W146.09
DIFU(013) W146.11
; rung 119: 押出機起動中か確認 / 以下信号ﾊﾟｰｼﾞ処理中切れる
LD W115.05
AND 420.05
OUT W146.10
; rung 120: ***** ﾛｰﾄﾞｾﾙ信号処理 ***** / 画面にてｵｰﾄﾛｰﾀﾞ使用にした時ﾌﾞﾛﾜONﾘﾚｰをON／輸送ﾌﾞﾛﾜをONさせるときは満量ﾘﾚｰON / 下限確認に異常のB接点が入っているのは下限確認してから異常が発生しﾘｾｯﾄした後、ﾌﾞﾛﾜON入らないから
LD H2.00
OUT TR0
AND W84.01
TIM 0333 #5
LD TR0
AND W84.02
TIM 0334 #5
; rung 121
LD T0334
ANDNOT W396.06
OUT W121.04

; rung 122
LD H2.01
OUT TR0
AND W84.05
TIM 0348 #5
LD TR0
AND W84.06
TIM 0349 #5
; rung 123
LD T0349
ANDNOT W396.07
OUT W126.04
; rung 124
LD H2.02
OUT TR0
AND W84.09
TIM 0363 #5
LD TR0
AND W84.10
TIM 0364 #5
; rung 125
LD T0364
ANDNOT W396.08
OUT W131.04
; rung 126
LD H2.03
OUT TR0
AND W84.13
TIM 0378 #5
LD TR0
AND W84.14
TIM 0379 #5
; rung 127
LD T0379
ANDNOT W396.09
OUT W136.04
; rung 128
LD H2.04
OUT TR0
AND W85.01
TIM 0393 #5
LD TR0
AND W85.02
TIM 0394 #5
; rung 129
LD T0394
ANDNOT W396.10
OUT W141.04

; rung 130
LD H2.05
OUT TR0
AND W85.05
TIM 0408 #5
LD TR0
AND W85.06
TIM 0409 #5
; rung 131
LD T0409
ANDNOT W396.11
OUT W146.04
; rung 132: ********** 全層共通実押出量範囲判別保持解除 **********(M) / 実押出量範囲内判別処理は各層の10回計測終わった後にある。
LD P_1s
XFERC(565) #2 D3365 D2943
; rung 133
LDNOT P_1s
XFERC(565) #2 D3365 D2945
; rung 134
LD P_On
CMPL(060) D3365 D2943
ANDNOT P_EQ
OUT W500.00
; rung 135
LD P_On
CMPL(060) D3365 D2945
ANDNOT P_EQ
OUT W500.01

; rung 136
LD W500.00
OR W500.01
OR 427.00
OR H2.14
OR H98.15
ORNOT H2.12
ORNOT 2050.00
OUT W500.02
; rung 137: ***** 主材内層処理 ***** / *** 主材内層輸送ブロワ処理 *** / 輸送ブロワは計測開始時にﾎｯﾊﾟ満量に無い場合、及びﾎｯﾊﾟ下限がONした場合、満量になるまで繰り返す。 / 今回ブロワ無いのでﾌﾟﾛｸﾞﾗﾑは残しﾀｲﾏ設定を#0000にして処理。
LD P_First_Cycle
MOV(021) #0 D3700
MOV(021) #0 D3701
MOV(021) #400 D3702
; rung 138
LD W121.01
OR W121.04
OR W121.02
ANDNOT T0333
AND W121.00
AND 10.06
ANDNOT 427.05
LDNOT H3.15
ORNOT W291.08
ANDLD
AND W73.15
OUT W121.02
; rung 139
LDNOT H3.15
ORNOT W291.08
ANDNOT T0230
OUT TR0
AND W121.02
TIM 0210 D3700
LD TR0
AND T0210
TIM 0211 D3701

; rung 140
LD T0211
OUT TR0
TIM 0212 D3702
ANDNOT T0212
ANDNOT T0333
OUT W121.03
LD TR0
AND T0212
TIM 0230 #10
; rung 141: ***** 主材内層計測処理 *****
LD W122.11
DIFU(013) W122.04
; rung 142
LD W84.00
DIFD(014) W122.03
; rung 143
LD W109.15
DIFU(013) W116.15
; rung 144
LDNOT 1.00
AND T0333
DIFU(013) W89.00
; rung 145: 計測開始時ﾎｯﾊﾟが満量か確認し満量で無い場合はﾊﾞﾀ弁開し原料を投入 / ﾛｰﾄﾞｾﾙHH信号がON時計測せず、HH信号OFFにて再計測 990327
LD W121.11
OR W122.04
OR W121.14
OR W122.03
OR W116.15
OR W115.06
OR W89.00
LD T0333
ORNOT W121.02
ANDLD
AND W121.10
AND H2.00
DIFU(013) W121.13
; rung 146: TEST
LD W121.01
OR W485.00
AND 10.06
OUT W485.00
LD<>(305) #0 2041
OR W485.01
ANDLD
OUT W485.01
TIM 0700 #50

; rung 147: ﾊﾟｰｼﾞ(ｼｬｯﾄﾀﾞｳﾝ)処理でﾊﾟｰｼﾞ終了以降ﾀﾞﾝﾊﾟ開しない様追加
LD W121.03
ANDNOT T0333
LDNOT H3.15
ORNOT W291.08
ANDLD
LD W121.10
LD 427.00
ANDNOT 427.05
ORLD
ANDLD
LD P_On
OR T0700
ANDLD
LD W116.06
OR W290.00
LD H3.06
OR W291.00
ANDLD
LD H3.15
OR W291.08
ANDLD
ANDNOT T0333
ORLD
ANDNOT 427.05
AND W73.15
AND W121.00
OUT 1.00
DIFD(014) W121.14
; rung 148
LD 1.00
AND W84.01
OUT W122.12
; rung 149
LD W121.13
OR W122.12
DIFU(013) W122.06
; rung 150
LD W122.06
OR W122.07
ANDNOT W122.08
ANDNOT W121.07
AND W121.10
OUT W122.07
; rung 151: 0.5sec～4.5secまでに0.5sec毎随時、計測開始ｽﾀｰﾄするので上記信号切るための接点は最低でも下記ﾀｲﾏ5.0sec以上に設定する。(現状0.5sec毎に10回計測し平均しているが回数を増やす場合は下記ﾀｲﾏ設定に注意)
LD W122.07
TIM 0320 #100
; rung 152
LD T0320
OUT W122.08
; rung 153: 計測開始と同時にﾎｯﾊﾟ重量を計測し、画面設定の計量時間後ﾎｯﾊﾟ重量を計測。これを計測開始から0.5sec毎に / 計測ｽﾀｰﾄとし計量時間後の重量を計測。(計10回)
LDNOT W100.00
ANDNOT W100.01
ANDNOT W100.02
ANDNOT W100.03
ANDNOT W100.04
ANDNOT W100.05
ANDNOT W100.06
ANDNOT W100.07
ANDNOT W100.08
ANDNOT W100.09
OUTNOT W109.15
; rung 154
LD W122.08
OR W122.09
ANDNOT W84.00
ANDNOT 1.00
ANDNOT W121.07
ANDNOT W122.04
ANDNOT W109.15
AND W121.10
OUT W122.09
DIFU(013) W123.00

; rung 155
LD W122.09
TIM 0321 #5
TIM 0322 #10
TIM 0323 #15
TIM 0324 #20
; rung 156
LD W122.09
TIM 0016 #25
TIM 0017 #30
TIM 0018 #35
TIM 0019 #40
TIM 0020 #45
TIM 0325 D350
; rung 157
LD T0321
DIFU(013) W123.01
TIM 0326 D350
; rung 158
LD T0322
DIFU(013) W123.02
TIM 0327 D350

; rung 159
LD T0323
DIFU(013) W123.03
TIM 0328 D350
; rung 160
LD T0324
DIFU(013) W123.04
TIM 0329 D350
; rung 161
LD T0016
DIFU(013) W123.10
TIM 0021 D350
; rung 162
LD T0017
DIFU(013) W123.11
TIM 0022 D350
; rung 163
LD T0018
DIFU(013) W123.12
TIM 0023 D350
; rung 164
LD T0019
DIFU(013) W123.13
TIM 0024 D350
; rung 165
LD T0020
DIFU(013) W123.14
TIM 0025 D350
; rung 166
LD T0325
DIFU(013) W123.05

; rung 167
LD T0326
DIFU(013) W123.06
; rung 168
LD T0327
DIFU(013) W123.07
; rung 169
LD T0328
DIFU(013) W123.08
; rung 170
LD T0329
DIFU(013) W123.09
; rung 171
LD T0021
DIFU(013) W124.00
; rung 172
LD T0022
DIFU(013) W124.01
; rung 173
LD T0023
DIFU(013) W124.02
; rung 174
LD T0024
DIFU(013) W124.03
; rung 175
LD T0025
DIFU(013) W124.04
; rung 176
LD W124.04
OR W122.10
ANDNOT W122.04
OUT W122.10
; rung 177: 下記ﾀｲﾏ設定時間元は#0030 これを#0010以下にする場合T410の設定時間に注意すること
LD W122.10
TIM 0331 #20
; rung 178
LD T0331
OUT W122.11

; rung 179: ﾛｰﾄﾞｾﾙﾒｰﾀ(OMRON)は64ms毎にﾃﾞｰﾀ更新しているので、１回の計量開始及び終了取込値を５回取込、最大最小取り除いた平均を取込値にした。(平均は3で割るとは限らない) / 計測１の消費樹脂重量を求める
LD W123.00
OR W124.05
ANDNOT W124.06
AND W122.09
OUT W124.05
; rung 180
LD W123.05
OR W104.00
ANDNOT W124.06
AND W122.09
OUT W104.00
; rung 181
LD W124.05
OR W104.00
@SBS(091) 16
; rung 182
LD W124.05
OR W104.00
AND 11.06
AND 36.01
@MOV(021) 30 *D3000
@++B(594) D3000
CMP(020) #3006 D3000
LD P_EQ
OR P_LT
ANDLD
OUT W124.06
; rung 183
LD W124.06
SBS(091) 17

; rung 184
LD W124.05
AND W124.06
MOV(021) D3014 D2010
@MOV(021) #0 D2006
@MOV(021) #0 D2007
@BSET(071) #0 D2020 D2029
@BSET(071) #0 D1810 D1819
; rung 185
LD W104.00
AND W124.06
OUT TR0
MOV(021) D3014 D2011
CLC(041)
-BC(416) D2010 D2011 D500
AND P_CY
OUT W100.00
LD TR0
AND W100.00
CLC(041)
-BC(416) #0 D500 D500
; rung 186: 計測２の消費樹脂重量を求める
LD W123.01
OR W124.07
ANDNOT W124.08
AND W122.09
OUT W124.07
; rung 187
LD W123.06
OR W104.01
ANDNOT W124.08
AND W122.09
OUT W104.01

; rung 188
LD W124.07
OR W104.01
@SBS(091) 16
; rung 189
LD W124.07
OR W104.01
AND 11.06
AND 36.01
@MOV(021) 30 *D3000
@++B(594) D3000
CMP(020) #3006 D3000
LD P_EQ
OR P_LT
ANDLD
OUT W124.08
; rung 190
LD W124.08
SBS(091) 17
; rung 191
LD W124.07
AND W124.08
MOV(021) D3014 D2012
; rung 192
LD W104.01
AND W124.08
OUT TR0
MOV(021) D3014 D2013
CLC(041)
-BC(416) D2012 D2013 D501
AND P_CY
OUT W100.01
LD TR0
AND W100.01
CLC(041)
-BC(416) #0 D501 D501

; rung 193: 計測３の消費樹脂重量を求める
LD W123.02
OR W124.09
ANDNOT W124.10
AND W122.09
OUT W124.09
; rung 194
LD W123.07
OR W104.02
ANDNOT W124.10
AND W122.09
OUT W104.02
; rung 195
LD W124.09
OR W104.02
@SBS(091) 16
; rung 196
LD W124.09
OR W104.02
AND 11.06
AND 36.01
@MOV(021) 30 *D3000
@++B(594) D3000
CMP(020) #3006 D3000
LD P_EQ
OR P_LT
ANDLD
OUT W124.10
; rung 197
LD W124.10
SBS(091) 17
; rung 198
LD W124.09
AND W124.10
MOV(021) D3014 D2014

; rung 199
LD W104.02
AND W124.10
OUT TR0
MOV(021) D3014 D2015
CLC(041)
-BC(416) D2014 D2015 D502
AND P_CY
OUT W100.0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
